VERSION 5.4 ;
NAMESCASESENSITIVE ON ;
BUSBITCHARS "[]" ;
DIVIDERCHAR "/" ;
UNITS
  DATABASE MICRONS 2000 ;
END UNITS
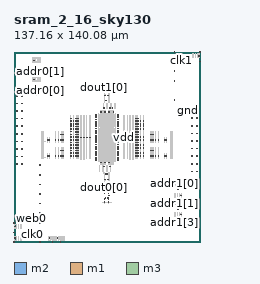
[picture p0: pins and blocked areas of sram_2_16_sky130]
MACRO sram_2_16_sky130
   CLASS BLOCK ;
   SIZE 137.16 BY 140.08 ;
   SYMMETRY X Y R90 ;
   PIN din0[0]
      DIRECTION INPUT ;
      PORT
         LAYER m2 ;
         RECT  26.135 2.69 26.465 2.95 ;
      END
   END din0[0]
   PIN din0[1]
      DIRECTION INPUT ;
      PORT
         LAYER m2 ;
         RECT  31.975 2.69 32.305 2.95 ;
      END
   END din0[1]
   PIN addr0[0]
      DIRECTION INPUT ;
      PORT
         LAYER m2 ;
         RECT  14.455 111.25 14.785 111.51 ;
      END
   END addr0[0]
   PIN addr0[1]
      DIRECTION INPUT ;
      PORT
         LAYER m2 ;
         RECT  14.455 119.75 14.785 120.01 ;
      END
   END addr0[1]
   PIN addr0[2]
      DIRECTION INPUT ;
      PORT
         LAYER m2 ;
         RECT  14.455 125.39 14.785 125.65 ;
      END
   END addr0[2]
   PIN addr0[3]
      DIRECTION INPUT ;
      PORT
         LAYER m2 ;
         RECT  14.455 133.89 14.785 134.15 ;
      END
   END addr0[3]
   PIN addr1[0]
      DIRECTION INPUT ;
      PORT
         LAYER m2 ;
         RECT  122.795 42.71 123.125 42.97 ;
      END
   END addr1[0]
   PIN addr1[1]
      DIRECTION INPUT ;
      PORT
         LAYER m2 ;
         RECT  122.795 34.21 123.125 34.47 ;
      END
   END addr1[1]
   PIN addr1[2]
      DIRECTION INPUT ;
      PORT
         LAYER m2 ;
         RECT  122.795 28.57 123.125 28.83 ;
      END
   END addr1[2]
   PIN addr1[3]
      DIRECTION INPUT ;
      PORT
         LAYER m2 ;
         RECT  122.795 20.07 123.125 20.33 ;
      END
   END addr1[3]
   PIN csb0
      DIRECTION INPUT ;
      PORT
         LAYER m2 ;
         RECT  0.685 2.69 1.015 2.95 ;
      END
   END csb0
   PIN csb1
      DIRECTION INPUT ;
      PORT
         LAYER m2 ;
         RECT  136.145 137.13 136.475 137.39 ;
      END
   END csb1
   PIN web0
      DIRECTION INPUT ;
      PORT
         LAYER m2 ;
         RECT  0.685 11.19 1.015 11.45 ;
      END
   END web0
   PIN clk0
      DIRECTION INPUT ;
      PORT
         LAYER m2 ;
         RECT  13.815 3.275 13.955 3.415 ;
      END
   END clk0
   PIN clk1
      DIRECTION INPUT ;
      PORT
         LAYER m2 ;
         RECT  123.625 136.665 123.765 136.805 ;
      END
   END clk1
   PIN dout0[0]
      DIRECTION OUTPUT ;
      PORT
         LAYER m1 ;
         RECT  65.98 39.79 66.21 41.06 ;
      END
   END dout0[0]
   PIN dout0[1]
      DIRECTION OUTPUT ;
      PORT
         LAYER m1 ;
         RECT  70.33 39.79 70.56 41.06 ;
      END
   END dout0[1]
   PIN dout1[0]
      DIRECTION OUTPUT ;
      PORT
         LAYER m1 ;
         RECT  65.98 113.16 66.21 114.43 ;
      END
   END dout1[0]
   PIN dout1[1]
      DIRECTION OUTPUT ;
      PORT
         LAYER m1 ;
         RECT  70.33 113.16 70.56 114.43 ;
      END
   END dout1[1]
   PIN vdd
      DIRECTION INOUT ;
      USE POWER ; 
      SHAPE ABUTMENT ; 
      PORT
         LAYER m3 ;
         RECT  100.815 63.185 101.305 63.675 ;
         LAYER m3 ;
         RECT  43.67 63.22 44.16 63.71 ;
         LAYER m3 ;
         RECT  104.07 67.17 104.56 67.66 ;
         LAYER m3 ;
         RECT  89.745 75.035 90.235 75.525 ;
         LAYER m3 ;
         RECT  130.995 91.015 131.485 91.505 ;
         LAYER m3 ;
         RECT  46.925 84.91 47.415 85.4 ;
         LAYER m3 ;
         RECT  93.0 79.02 93.49 79.51 ;
         LAYER m3 ;
         RECT  89.745 71.085 90.235 71.575 ;
         LAYER m3 ;
         RECT  25.985 63.185 26.475 63.675 ;
         LAYER m3 ;
         RECT  18.945 6.825 19.435 7.315 ;
         LAYER m3 ;
         RECT  46.925 82.935 47.415 83.425 ;
         LAYER m3 ;
         RECT  68.99 107.845 69.48 108.335 ;
         LAYER m3 ;
         RECT  67.12 112.035 67.61 112.525 ;
         LAYER m3 ;
         RECT  1.995 85.115 2.485 85.605 ;
         LAYER m3 ;
         RECT  80.815 76.865 81.305 77.355 ;
         LAYER m3 ;
         RECT  70.49 55.305 70.98 55.795 ;
         LAYER m3 ;
         RECT  100.815 75.035 101.305 75.525 ;
         LAYER m3 ;
         RECT  64.25 55.305 64.74 55.795 ;
         LAYER m3 ;
         RECT  18.945 49.245 19.435 49.735 ;
         LAYER m3 ;
         RECT  66.18 55.305 66.67 55.795 ;
         LAYER m3 ;
         RECT  134.675 46.215 135.165 46.705 ;
         LAYER m3 ;
         RECT  89.745 67.135 90.235 67.625 ;
         LAYER m3 ;
         RECT  100.815 78.985 101.305 79.475 ;
         LAYER m3 ;
         RECT  46.925 77.01 47.415 77.5 ;
         LAYER m3 ;
         RECT  67.06 45.885 67.55 46.375 ;
         LAYER m3 ;
         RECT  89.745 88.86 90.235 89.35 ;
         LAYER m3 ;
         RECT  130.995 79.815 131.485 80.305 ;
         LAYER m3 ;
         RECT  46.925 65.16 47.415 65.65 ;
         LAYER m3 ;
         RECT  25.985 75.035 26.475 75.525 ;
         LAYER m3 ;
         RECT  100.815 67.135 101.305 67.625 ;
         LAYER m3 ;
         RECT  130.995 68.615 131.485 69.105 ;
         LAYER m3 ;
         RECT  67.12 41.695 67.61 42.185 ;
         LAYER m3 ;
         RECT  43.67 67.17 44.16 67.66 ;
         LAYER m3 ;
         RECT  68.93 112.035 69.42 112.525 ;
         LAYER m3 ;
         RECT  118.145 132.765 118.635 133.255 ;
         LAYER m3 ;
         RECT  118.145 104.485 118.635 104.975 ;
         LAYER m3 ;
         RECT  18.945 35.105 19.435 35.595 ;
         LAYER m3 ;
         RECT  55.855 76.865 56.345 77.355 ;
         LAYER m3 ;
         RECT  43.67 82.97 44.16 83.46 ;
         LAYER m3 ;
         RECT  5.675 73.915 6.165 74.405 ;
         LAYER m3 ;
         RECT  93.0 90.87 93.49 91.36 ;
         LAYER m3 ;
         RECT  89.745 65.16 90.235 65.65 ;
         LAYER m3 ;
         RECT  32.6 63.22 33.09 63.71 ;
         LAYER m3 ;
         RECT  1.995 73.915 2.485 74.405 ;
         LAYER m3 ;
         RECT  43.67 75.07 44.16 75.56 ;
         LAYER m3 ;
         RECT  46.925 67.135 47.415 67.625 ;
         LAYER m3 ;
         RECT  46.925 71.085 47.415 71.575 ;
         LAYER m3 ;
         RECT  63.655 95.47 64.145 95.96 ;
         LAYER m3 ;
         RECT  85.39 76.785 85.88 77.275 ;
         LAYER m3 ;
         RECT  89.745 73.06 90.235 73.55 ;
         LAYER m3 ;
         RECT  104.07 79.02 104.56 79.51 ;
         LAYER m3 ;
         RECT  35.855 67.135 36.345 67.625 ;
         LAYER m3 ;
         RECT  134.675 79.815 135.165 80.305 ;
         LAYER m3 ;
         RECT  51.28 76.785 51.77 77.275 ;
         LAYER m3 ;
         RECT  32.6 75.07 33.09 75.56 ;
         LAYER m3 ;
         RECT  93.0 86.92 93.49 87.41 ;
         LAYER m3 ;
         RECT  134.675 68.615 135.165 69.105 ;
         LAYER m3 ;
         RECT  89.745 82.935 90.235 83.425 ;
         LAYER m3 ;
         RECT  67.06 107.845 67.55 108.335 ;
         LAYER m3 ;
         RECT  93.0 85.07 93.49 85.56 ;
         LAYER m3 ;
         RECT  32.6 79.02 33.09 79.51 ;
         LAYER m3 ;
         RECT  46.925 63.185 47.415 63.675 ;
         LAYER m3 ;
         RECT  46.925 88.86 47.415 89.35 ;
         LAYER m3 ;
         RECT  70.49 98.425 70.98 98.915 ;
         LAYER m3 ;
         RECT  120.645 38.345 121.135 38.835 ;
         LAYER m3 ;
         RECT  46.925 80.96 47.415 81.45 ;
         LAYER m3 ;
         RECT  46.925 69.11 47.415 69.6 ;
         LAYER m3 ;
         RECT  66.87 95.565 67.17 95.865 ;
         LAYER m3 ;
         RECT  134.675 57.415 135.165 57.905 ;
         LAYER m3 ;
         RECT  5.675 96.315 6.165 96.805 ;
         LAYER m3 ;
         RECT  1.995 62.715 2.485 63.205 ;
         LAYER m3 ;
         RECT  93.0 75.07 93.49 75.56 ;
         LAYER m3 ;
         RECT  89.745 80.96 90.235 81.45 ;
         LAYER m3 ;
         RECT  43.67 69.27 44.16 69.76 ;
         LAYER m3 ;
         RECT  93.0 82.97 93.49 83.46 ;
         LAYER m3 ;
         RECT  120.645 24.205 121.135 24.695 ;
         LAYER m3 ;
         RECT  118.145 118.625 118.635 119.115 ;
         LAYER m3 ;
         RECT  72.42 98.425 72.91 98.915 ;
         LAYER m3 ;
         RECT  93.0 89.02 93.49 89.51 ;
         LAYER m3 ;
         RECT  43.67 81.12 44.16 81.61 ;
         LAYER m3 ;
         RECT  93.0 77.17 93.49 77.66 ;
         LAYER m3 ;
         RECT  5.675 62.715 6.165 63.205 ;
         LAYER m3 ;
         RECT  130.995 57.415 131.485 57.905 ;
         LAYER m3 ;
         RECT  66.495 33.935 66.985 34.425 ;
         LAYER m3 ;
         RECT  110.685 63.185 111.175 63.675 ;
         LAYER m3 ;
         RECT  33.965 6.825 34.455 7.315 ;
         LAYER m3 ;
         RECT  68.99 45.885 69.48 46.375 ;
         LAYER m3 ;
         RECT  5.675 85.115 6.165 85.605 ;
         LAYER m3 ;
         RECT  16.445 115.385 16.935 115.875 ;
         LAYER m3 ;
         RECT  43.67 79.02 44.16 79.51 ;
         LAYER m3 ;
         RECT  1.995 107.515 2.485 108.005 ;
         LAYER m3 ;
         RECT  5.675 107.515 6.165 108.005 ;
         LAYER m3 ;
         RECT  46.925 73.06 47.415 73.55 ;
         LAYER m3 ;
         RECT  110.685 75.035 111.175 75.525 ;
         LAYER m3 ;
         RECT  43.67 71.12 44.16 71.61 ;
         LAYER m3 ;
         RECT  69.455 29.185 69.945 29.675 ;
         LAYER m3 ;
         RECT  104.07 63.22 104.56 63.71 ;
         LAYER m3 ;
         RECT  89.745 78.985 90.235 79.475 ;
         LAYER m3 ;
         RECT  93.0 69.27 93.49 69.76 ;
         LAYER m3 ;
         RECT  134.675 91.015 135.165 91.505 ;
         LAYER m3 ;
         RECT  66.87 58.355 67.17 58.655 ;
         LAYER m3 ;
         RECT  43.67 65.32 44.16 65.81 ;
         LAYER m3 ;
         RECT  93.0 81.12 93.49 81.61 ;
         LAYER m3 ;
         RECT  43.67 86.92 44.16 87.41 ;
         LAYER m3 ;
         RECT  35.855 78.985 36.345 79.475 ;
         LAYER m3 ;
         RECT  104.07 75.07 104.56 75.56 ;
         LAYER m3 ;
         RECT  136.915 132.765 137.405 133.255 ;
         LAYER m3 ;
         RECT  93.0 63.22 93.49 63.71 ;
         LAYER m3 ;
         RECT  43.67 90.87 44.16 91.36 ;
         LAYER m3 ;
         RECT  130.995 46.215 131.485 46.705 ;
         LAYER m3 ;
         RECT  89.745 77.01 90.235 77.5 ;
         LAYER m3 ;
         RECT  35.855 63.185 36.345 63.675 ;
         LAYER m3 ;
         RECT  46.925 86.885 47.415 87.375 ;
         LAYER m3 ;
         RECT  16.445 129.525 16.935 130.015 ;
         LAYER m3 ;
         RECT  66.18 98.425 66.67 98.915 ;
         LAYER m3 ;
         RECT  93.0 67.17 93.49 67.66 ;
         LAYER m3 ;
         RECT  93.0 73.22 93.49 73.71 ;
         LAYER m3 ;
         RECT  63.655 58.26 64.145 58.75 ;
         LAYER m3 ;
         RECT  43.67 85.07 44.16 85.56 ;
         LAYER m3 ;
         RECT  43.67 77.17 44.16 77.66 ;
         LAYER m3 ;
         RECT  69.555 33.935 70.045 34.425 ;
         LAYER m3 ;
         RECT  46.925 75.035 47.415 75.525 ;
         LAYER m3 ;
         RECT  89.745 84.91 90.235 85.4 ;
         LAYER m3 ;
         RECT  73.015 58.26 73.505 58.75 ;
         LAYER m3 ;
         RECT  43.67 73.22 44.16 73.71 ;
         LAYER m3 ;
         RECT  32.6 67.17 33.09 67.66 ;
         LAYER m3 ;
         RECT  73.015 95.47 73.505 95.96 ;
         LAYER m3 ;
         RECT  35.855 75.035 36.345 75.525 ;
         LAYER m3 ;
         RECT  66.595 29.185 67.085 29.675 ;
         LAYER m3 ;
         RECT  69.99 95.565 70.29 95.865 ;
         LAYER m3 ;
         RECT  46.925 78.985 47.415 79.475 ;
         LAYER m3 ;
         RECT  93.0 65.32 93.49 65.81 ;
         LAYER m3 ;
         RECT  68.93 41.695 69.42 42.185 ;
         LAYER m3 ;
         RECT  18.945 20.965 19.435 21.455 ;
         LAYER m3 ;
         RECT  46.925 90.835 47.415 91.325 ;
         LAYER m3 ;
         RECT  1.995 96.315 2.485 96.805 ;
         LAYER m3 ;
         RECT  28.125 6.825 28.615 7.315 ;
         LAYER m3 ;
         RECT  43.67 89.02 44.16 89.51 ;
         LAYER m3 ;
         RECT  93.0 71.12 93.49 71.61 ;
         LAYER m3 ;
         RECT  89.745 90.835 90.235 91.325 ;
         LAYER m3 ;
         RECT  89.745 69.11 90.235 69.6 ;
         LAYER m3 ;
         RECT  89.745 86.885 90.235 87.375 ;
         LAYER m3 ;
         RECT  -0.245 6.825 0.245 7.315 ;
         LAYER m3 ;
         RECT  69.99 58.355 70.29 58.655 ;
         LAYER m3 ;
         RECT  89.745 63.185 90.235 63.675 ;
      END
   END vdd
   PIN gnd
      DIRECTION INOUT ;
      USE GROUND ; 
      SHAPE ABUTMENT ; 
      PORT
         LAYER m3 ;
         RECT  41.545 79.02 42.035 79.51 ;
         LAYER m3 ;
         RECT  102.175 78.985 102.665 79.475 ;
         LAYER m3 ;
         RECT  76.59 78.145 76.89 78.445 ;
         LAYER m3 ;
         RECT  1.995 68.315 2.485 68.805 ;
         LAYER m3 ;
         RECT  76.59 84.86 76.89 85.16 ;
         LAYER m3 ;
         RECT  60.27 87.625 60.57 87.925 ;
         LAYER m3 ;
         RECT  106.195 67.17 106.685 67.66 ;
         LAYER m3 ;
         RECT  91.105 82.935 91.595 83.425 ;
         LAYER m3 ;
         RECT  16.445 122.455 16.935 122.945 ;
         LAYER m3 ;
         RECT  76.59 67.875 76.89 68.175 ;
         LAYER m3 ;
         RECT  60.27 73.01 60.57 73.31 ;
         LAYER m3 ;
         RECT  1.995 90.715 2.485 91.205 ;
         LAYER m3 ;
         RECT  5.675 101.915 6.165 102.405 ;
         LAYER m3 ;
         RECT  76.59 82.095 76.89 82.395 ;
         LAYER m3 ;
         RECT  45.565 71.085 46.055 71.575 ;
         LAYER m3 ;
         RECT  95.125 89.01 95.615 89.5 ;
         LAYER m3 ;
         RECT  45.565 73.06 46.055 73.55 ;
         LAYER m3 ;
         RECT  95.125 73.21 95.615 73.7 ;
         LAYER m3 ;
         RECT  30.475 79.02 30.965 79.51 ;
         LAYER m3 ;
         RECT  45.565 75.035 46.055 75.525 ;
         LAYER m3 ;
         RECT  102.175 63.185 102.665 63.675 ;
         LAYER m3 ;
         RECT  91.105 90.835 91.595 91.325 ;
         LAYER m3 ;
         RECT  60.27 69.06 60.57 69.36 ;
         LAYER m3 ;
         RECT  41.545 82.97 42.035 83.46 ;
         LAYER m3 ;
         RECT  5.675 90.715 6.165 91.205 ;
         LAYER m3 ;
         RECT  67.47 49.755 67.96 50.245 ;
         LAYER m3 ;
         RECT  87.515 76.79 88.005 77.28 ;
         LAYER m3 ;
         RECT  76.59 92.76 76.89 93.06 ;
         LAYER m3 ;
         RECT  45.565 80.96 46.055 81.45 ;
         LAYER m3 ;
         RECT  -0.245 13.905 0.245 14.395 ;
         LAYER m3 ;
         RECT  34.495 78.985 34.985 79.475 ;
         LAYER m3 ;
         RECT  68.58 103.975 69.07 104.465 ;
         LAYER m3 ;
         RECT  60.27 75.775 60.57 76.075 ;
         LAYER m3 ;
         RECT  60.27 70.245 60.57 70.545 ;
         LAYER m3 ;
         RECT  76.59 70.245 76.89 70.545 ;
         LAYER m3 ;
         RECT  76.59 87.625 76.89 87.925 ;
         LAYER m3 ;
         RECT  18.945 42.175 19.435 42.665 ;
         LAYER m3 ;
         RECT  45.565 86.885 46.055 87.375 ;
         LAYER m3 ;
         RECT  91.105 77.01 91.595 77.5 ;
         LAYER m3 ;
         RECT  118.145 111.555 118.635 112.045 ;
         LAYER m3 ;
         RECT  76.59 76.96 76.89 77.26 ;
         LAYER m3 ;
         RECT  33.965 -0.245 34.455 0.245 ;
         LAYER m3 ;
         RECT  28.125 -0.245 28.615 0.245 ;
         LAYER m3 ;
         RECT  49.155 76.79 49.645 77.28 ;
         LAYER m3 ;
         RECT  69.525 31.265 70.015 31.755 ;
         LAYER m3 ;
         RECT  60.27 78.145 60.57 78.445 ;
         LAYER m3 ;
         RECT  91.105 80.96 91.595 81.45 ;
         LAYER m3 ;
         RECT  60.27 80.91 60.57 81.21 ;
         LAYER m3 ;
         RECT  118.145 139.835 118.635 140.325 ;
         LAYER m3 ;
         RECT  60.27 86.045 60.57 86.345 ;
         LAYER m3 ;
         RECT  5.675 57.115 6.165 57.605 ;
         LAYER m3 ;
         RECT  30.475 67.17 30.965 67.66 ;
         LAYER m3 ;
         RECT  134.675 51.815 135.165 52.305 ;
         LAYER m3 ;
         RECT  34.495 67.135 34.985 67.625 ;
         LAYER m3 ;
         RECT  24.625 63.185 25.115 63.675 ;
         LAYER m3 ;
         RECT  60.27 76.96 60.57 77.26 ;
         LAYER m3 ;
         RECT  95.125 65.31 95.615 65.8 ;
         LAYER m3 ;
         RECT  91.105 75.035 91.595 75.525 ;
         LAYER m3 ;
         RECT  68.93 113.645 69.42 114.135 ;
         LAYER m3 ;
         RECT  60.27 62.345 60.57 62.645 ;
         LAYER m3 ;
         RECT  112.045 75.035 112.535 75.525 ;
         LAYER m3 ;
         RECT  41.545 85.06 42.035 85.55 ;
         LAYER m3 ;
         RECT  60.27 66.295 60.57 66.595 ;
         LAYER m3 ;
         RECT  45.565 90.835 46.055 91.325 ;
         LAYER m3 ;
         RECT  18.945 56.315 19.435 56.805 ;
         LAYER m3 ;
         RECT  18.945 -0.245 19.435 0.245 ;
         LAYER m3 ;
         RECT  95.125 82.97 95.615 83.46 ;
         LAYER m3 ;
         RECT  91.105 73.06 91.595 73.55 ;
         LAYER m3 ;
         RECT  60.27 71.825 60.57 72.125 ;
         LAYER m3 ;
         RECT  130.995 96.615 131.485 97.105 ;
         LAYER m3 ;
         RECT  134.675 74.215 135.165 74.705 ;
         LAYER m3 ;
         RECT  136.915 139.845 137.405 140.335 ;
         LAYER m3 ;
         RECT  24.625 75.035 25.115 75.525 ;
         LAYER m3 ;
         RECT  134.675 96.615 135.165 97.105 ;
         LAYER m3 ;
         RECT  95.125 77.16 95.615 77.65 ;
         LAYER m3 ;
         RECT  76.59 89.995 76.89 90.295 ;
         LAYER m3 ;
         RECT  60.27 93.945 60.57 94.245 ;
         LAYER m3 ;
         RECT  69.5 36.12 69.99 36.61 ;
         LAYER m3 ;
         RECT  91.105 71.085 91.595 71.575 ;
         LAYER m3 ;
         RECT  41.545 67.17 42.035 67.66 ;
         LAYER m3 ;
         RECT  1.995 79.515 2.485 80.005 ;
         LAYER m3 ;
         RECT  60.27 59.975 60.57 60.275 ;
         LAYER m3 ;
         RECT  45.565 63.185 46.055 63.675 ;
         LAYER m3 ;
         RECT  130.995 74.215 131.485 74.705 ;
         LAYER m3 ;
         RECT  66.525 31.265 67.015 31.755 ;
         LAYER m3 ;
         RECT  76.59 83.675 76.89 83.975 ;
         LAYER m3 ;
         RECT  60.27 65.11 60.57 65.41 ;
         LAYER m3 ;
         RECT  106.195 63.22 106.685 63.71 ;
         LAYER m3 ;
         RECT  120.645 45.415 121.135 45.905 ;
         LAYER m3 ;
         RECT  106.195 79.02 106.685 79.51 ;
         LAYER m3 ;
         RECT  76.59 66.295 76.89 66.595 ;
         LAYER m3 ;
         RECT  112.045 63.185 112.535 63.675 ;
         LAYER m3 ;
         RECT  41.545 69.26 42.035 69.75 ;
         LAYER m3 ;
         RECT  76.59 63.925 76.89 64.225 ;
         LAYER m3 ;
         RECT  76.59 69.06 76.89 69.36 ;
         LAYER m3 ;
         RECT  45.565 78.985 46.055 79.475 ;
         LAYER m3 ;
         RECT  60.27 91.575 60.57 91.875 ;
         LAYER m3 ;
         RECT  76.59 88.81 76.89 89.11 ;
         LAYER m3 ;
         RECT  5.675 68.315 6.165 68.805 ;
         LAYER m3 ;
         RECT  67.12 40.085 67.61 40.575 ;
         LAYER m3 ;
         RECT  76.59 79.725 76.89 80.025 ;
         LAYER m3 ;
         RECT  41.545 81.11 42.035 81.6 ;
         LAYER m3 ;
         RECT  83.305 76.865 83.795 77.355 ;
         LAYER m3 ;
         RECT  91.105 84.91 91.595 85.4 ;
         LAYER m3 ;
         RECT  76.59 59.975 76.89 60.275 ;
         LAYER m3 ;
         RECT  95.125 86.92 95.615 87.41 ;
         LAYER m3 ;
         RECT  95.125 71.12 95.615 71.61 ;
         LAYER m3 ;
         RECT  60.27 79.725 60.57 80.025 ;
         LAYER m3 ;
         RECT  76.59 75.775 76.89 76.075 ;
         LAYER m3 ;
         RECT  1.995 101.915 2.485 102.405 ;
         LAYER m3 ;
         RECT  91.105 65.16 91.595 65.65 ;
         LAYER m3 ;
         RECT  76.59 74.195 76.89 74.495 ;
         LAYER m3 ;
         RECT  95.125 81.11 95.615 81.6 ;
         LAYER m3 ;
         RECT  16.445 136.595 16.935 137.085 ;
         LAYER m3 ;
         RECT  41.545 65.31 42.035 65.8 ;
         LAYER m3 ;
         RECT  67.12 113.645 67.61 114.135 ;
         LAYER m3 ;
         RECT  130.995 51.815 131.485 52.305 ;
         LAYER m3 ;
         RECT  41.545 73.21 42.035 73.7 ;
         LAYER m3 ;
         RECT  102.175 67.135 102.665 67.625 ;
         LAYER m3 ;
         RECT  95.125 85.06 95.615 85.55 ;
         LAYER m3 ;
         RECT  130.995 63.015 131.485 63.505 ;
         LAYER m3 ;
         RECT  45.565 67.135 46.055 67.625 ;
         LAYER m3 ;
         RECT  68.93 40.085 69.42 40.575 ;
         LAYER m3 ;
         RECT  76.59 86.045 76.89 86.345 ;
         LAYER m3 ;
         RECT  106.195 75.07 106.685 75.56 ;
         LAYER m3 ;
         RECT  34.495 63.185 34.985 63.675 ;
         LAYER m3 ;
         RECT  76.59 93.945 76.89 94.245 ;
         LAYER m3 ;
         RECT  91.105 69.11 91.595 69.6 ;
         LAYER m3 ;
         RECT  60.27 67.875 60.57 68.175 ;
         LAYER m3 ;
         RECT  76.59 61.16 76.89 61.46 ;
         LAYER m3 ;
         RECT  95.125 90.87 95.615 91.36 ;
         LAYER m3 ;
         RECT  41.545 90.87 42.035 91.36 ;
         LAYER m3 ;
         RECT  118.145 97.415 118.635 97.905 ;
         LAYER m3 ;
         RECT  76.59 80.91 76.89 81.21 ;
         LAYER m3 ;
         RECT  60.27 84.86 60.57 85.16 ;
         LAYER m3 ;
         RECT  45.565 82.935 46.055 83.425 ;
         LAYER m3 ;
         RECT  34.495 75.035 34.985 75.525 ;
         LAYER m3 ;
         RECT  60.27 63.925 60.57 64.225 ;
         LAYER m3 ;
         RECT  5.675 79.515 6.165 80.005 ;
         LAYER m3 ;
         RECT  18.945 13.895 19.435 14.385 ;
         LAYER m3 ;
         RECT  60.27 92.76 60.57 93.06 ;
         LAYER m3 ;
         RECT  76.59 73.01 76.89 73.31 ;
         LAYER m3 ;
         RECT  76.59 62.345 76.89 62.645 ;
         LAYER m3 ;
         RECT  95.125 69.26 95.615 69.75 ;
         LAYER m3 ;
         RECT  91.105 67.135 91.595 67.625 ;
         LAYER m3 ;
         RECT  30.475 75.07 30.965 75.56 ;
         LAYER m3 ;
         RECT  60.27 82.095 60.57 82.395 ;
         LAYER m3 ;
         RECT  60.27 83.675 60.57 83.975 ;
         LAYER m3 ;
         RECT  45.565 65.16 46.055 65.65 ;
         LAYER m3 ;
         RECT  41.545 63.22 42.035 63.71 ;
         LAYER m3 ;
         RECT  60.27 88.81 60.57 89.11 ;
         LAYER m3 ;
         RECT  16.445 108.315 16.935 108.805 ;
         LAYER m3 ;
         RECT  60.27 61.16 60.57 61.46 ;
         LAYER m3 ;
         RECT  53.365 76.865 53.855 77.355 ;
         LAYER m3 ;
         RECT  67.47 103.975 67.96 104.465 ;
         LAYER m3 ;
         RECT  91.105 78.985 91.595 79.475 ;
         LAYER m3 ;
         RECT  -0.245 -0.255 0.245 0.235 ;
         LAYER m3 ;
         RECT  134.675 63.015 135.165 63.505 ;
         LAYER m3 ;
         RECT  76.59 71.825 76.89 72.125 ;
         LAYER m3 ;
         RECT  45.565 84.91 46.055 85.4 ;
         LAYER m3 ;
         RECT  102.175 75.035 102.665 75.525 ;
         LAYER m3 ;
         RECT  120.645 31.275 121.135 31.765 ;
         LAYER m3 ;
         RECT  95.125 75.07 95.615 75.56 ;
         LAYER m3 ;
         RECT  91.105 63.185 91.595 63.675 ;
         LAYER m3 ;
         RECT  60.27 74.195 60.57 74.495 ;
         LAYER m3 ;
         RECT  95.125 79.02 95.615 79.51 ;
         LAYER m3 ;
         RECT  118.145 125.695 118.635 126.185 ;
         LAYER m3 ;
         RECT  130.995 85.415 131.485 85.905 ;
         LAYER m3 ;
         RECT  68.95 32.275 69.44 32.765 ;
         LAYER m3 ;
         RECT  45.565 77.01 46.055 77.5 ;
         LAYER m3 ;
         RECT  30.475 63.22 30.965 63.71 ;
         LAYER m3 ;
         RECT  1.995 57.115 2.485 57.605 ;
         LAYER m3 ;
         RECT  18.945 28.035 19.435 28.525 ;
         LAYER m3 ;
         RECT  41.545 71.12 42.035 71.61 ;
         LAYER m3 ;
         RECT  134.675 85.415 135.165 85.905 ;
         LAYER m3 ;
         RECT  60.27 89.995 60.57 90.295 ;
         LAYER m3 ;
         RECT  95.125 67.17 95.615 67.66 ;
         LAYER m3 ;
         RECT  41.545 89.01 42.035 89.5 ;
         LAYER m3 ;
         RECT  41.545 77.16 42.035 77.65 ;
         LAYER m3 ;
         RECT  66.55 36.12 67.04 36.61 ;
         LAYER m3 ;
         RECT  76.59 65.11 76.89 65.41 ;
         LAYER m3 ;
         RECT  91.105 88.86 91.595 89.35 ;
         LAYER m3 ;
         RECT  68.58 49.755 69.07 50.245 ;
         LAYER m3 ;
         RECT  76.59 91.575 76.89 91.875 ;
         LAYER m3 ;
         RECT  45.565 88.86 46.055 89.35 ;
         LAYER m3 ;
         RECT  91.105 86.885 91.595 87.375 ;
         LAYER m3 ;
         RECT  95.125 63.22 95.615 63.71 ;
         LAYER m3 ;
         RECT  120.645 17.135 121.135 17.625 ;
         LAYER m3 ;
         RECT  45.565 69.11 46.055 69.6 ;
         LAYER m3 ;
         RECT  67.1 32.275 67.59 32.765 ;
         LAYER m3 ;
         RECT  41.545 86.92 42.035 87.41 ;
         LAYER m3 ;
         RECT  41.545 75.07 42.035 75.56 ;
      END
   END gnd
   OBS
   LAYER  m1 ;
      RECT  68.295 61.705 68.37 63.41 ;
      RECT  68.37 61.12 68.58 61.5 ;
      RECT  66.21 60.79 66.39 61.705 ;
      POLYGON  67.86 61.795 67.86 62.205 68.035 62.205 68.115 62.125 68.115 61.795 67.86 61.795 ;
      RECT  65.85 61.705 66.03 63.41 ;
      RECT  66.21 61.705 66.39 63.41 ;
      RECT  65.46 61.705 65.67 63.41 ;
      RECT  65.25 61.5 65.46 61.705 ;
      RECT  65.25 61.705 65.46 63.41 ;
      RECT  68.37 61.705 68.58 63.41 ;
      POLYGON  67.86 62.785 67.86 63.195 68.115 63.195 68.115 62.865 68.035 62.785 67.86 62.785 ;
      RECT  65.46 61.12 65.67 61.5 ;
      RECT  68.37 60.79 68.58 61.12 ;
      RECT  66.57 60.79 66.75 61.705 ;
      RECT  68.21 62.29 68.295 62.7 ;
      RECT  67.29 61.705 67.47 63.41 ;
      RECT  67.65 62.785 67.86 63.195 ;
      RECT  65.46 60.79 65.67 61.12 ;
      RECT  67.65 61.795 67.86 62.205 ;
      RECT  67.65 61.12 67.86 61.5 ;
      RECT  65.25 61.12 65.46 61.5 ;
      RECT  66.93 60.79 67.11 61.705 ;
      RECT  66.93 61.705 67.11 63.41 ;
      RECT  68.37 61.5 68.58 61.705 ;
      RECT  65.46 61.5 65.67 61.705 ;
      RECT  65.25 60.79 65.46 61.12 ;
      RECT  67.29 60.79 67.47 61.705 ;
      RECT  65.85 60.79 66.03 61.705 ;
      POLYGON  68.295 60.79 68.295 61.12 67.86 61.12 67.86 61.5 68.295 61.5 68.295 61.705 68.37 61.705 68.37 60.79 68.295 60.79 ;
      RECT  66.57 61.705 66.75 63.41 ;
      RECT  68.295 64.865 68.37 63.16 ;
      RECT  68.37 65.45 68.58 65.07 ;
      RECT  66.21 65.78 66.39 64.865 ;
      POLYGON  67.86 64.775 67.86 64.365 68.035 64.365 68.115 64.445 68.115 64.775 67.86 64.775 ;
      RECT  65.85 64.865 66.03 63.16 ;
      RECT  66.21 64.865 66.39 63.16 ;
      RECT  65.46 64.865 65.67 63.16 ;
      RECT  65.25 65.07 65.46 64.865 ;
      RECT  65.25 64.865 65.46 63.16 ;
      RECT  68.37 64.865 68.58 63.16 ;
      POLYGON  67.86 63.785 67.86 63.375 68.115 63.375 68.115 63.705 68.035 63.785 67.86 63.785 ;
      RECT  65.46 65.45 65.67 65.07 ;
      RECT  68.37 65.78 68.58 65.45 ;
      RECT  66.57 65.78 66.75 64.865 ;
      RECT  68.21 64.28 68.295 63.87 ;
      RECT  67.29 64.865 67.47 63.16 ;
      RECT  67.65 63.785 67.86 63.375 ;
      RECT  65.46 65.78 65.67 65.45 ;
      RECT  67.65 64.775 67.86 64.365 ;
      RECT  67.65 65.45 67.86 65.07 ;
      RECT  65.25 65.45 65.46 65.07 ;
      RECT  66.93 65.78 67.11 64.865 ;
      RECT  66.93 64.865 67.11 63.16 ;
      RECT  68.37 65.07 68.58 64.865 ;
      RECT  65.46 65.07 65.67 64.865 ;
      RECT  65.25 65.78 65.46 65.45 ;
      RECT  67.29 65.78 67.47 64.865 ;
      RECT  65.85 65.78 66.03 64.865 ;
      POLYGON  68.295 65.78 68.295 65.45 67.86 65.45 67.86 65.07 68.295 65.07 68.295 64.865 68.37 64.865 68.37 65.78 68.295 65.78 ;
      RECT  66.57 64.865 66.75 63.16 ;
      RECT  68.295 65.655 68.37 67.36 ;
      RECT  68.37 65.07 68.58 65.45 ;
      RECT  66.21 64.74 66.39 65.655 ;
      POLYGON  67.86 65.745 67.86 66.155 68.035 66.155 68.115 66.075 68.115 65.745 67.86 65.745 ;
      RECT  65.85 65.655 66.03 67.36 ;
      RECT  66.21 65.655 66.39 67.36 ;
      RECT  65.46 65.655 65.67 67.36 ;
      RECT  65.25 65.45 65.46 65.655 ;
      RECT  65.25 65.655 65.46 67.36 ;
      RECT  68.37 65.655 68.58 67.36 ;
      POLYGON  67.86 66.735 67.86 67.145 68.115 67.145 68.115 66.815 68.035 66.735 67.86 66.735 ;
      RECT  65.46 65.07 65.67 65.45 ;
      RECT  68.37 64.74 68.58 65.07 ;
      RECT  66.57 64.74 66.75 65.655 ;
      RECT  68.21 66.24 68.295 66.65 ;
      RECT  67.29 65.655 67.47 67.36 ;
      RECT  67.65 66.735 67.86 67.145 ;
      RECT  65.46 64.74 65.67 65.07 ;
      RECT  67.65 65.745 67.86 66.155 ;
      RECT  67.65 65.07 67.86 65.45 ;
      RECT  65.25 65.07 65.46 65.45 ;
      RECT  66.93 64.74 67.11 65.655 ;
      RECT  66.93 65.655 67.11 67.36 ;
      RECT  68.37 65.45 68.58 65.655 ;
      RECT  65.46 65.45 65.67 65.655 ;
      RECT  65.25 64.74 65.46 65.07 ;
      RECT  67.29 64.74 67.47 65.655 ;
      RECT  65.85 64.74 66.03 65.655 ;
      POLYGON  68.295 64.74 68.295 65.07 67.86 65.07 67.86 65.45 68.295 65.45 68.295 65.655 68.37 65.655 68.37 64.74 68.295 64.74 ;
      RECT  66.57 65.655 66.75 67.36 ;
      RECT  68.295 68.815 68.37 67.11 ;
      RECT  68.37 69.4 68.58 69.02 ;
      RECT  66.21 69.73 66.39 68.815 ;
      POLYGON  67.86 68.725 67.86 68.315 68.035 68.315 68.115 68.395 68.115 68.725 67.86 68.725 ;
      RECT  65.85 68.815 66.03 67.11 ;
      RECT  66.21 68.815 66.39 67.11 ;
      RECT  65.46 68.815 65.67 67.11 ;
      RECT  65.25 69.02 65.46 68.815 ;
      RECT  65.25 68.815 65.46 67.11 ;
      RECT  68.37 68.815 68.58 67.11 ;
      POLYGON  67.86 67.735 67.86 67.325 68.115 67.325 68.115 67.655 68.035 67.735 67.86 67.735 ;
      RECT  65.46 69.4 65.67 69.02 ;
      RECT  68.37 69.73 68.58 69.4 ;
      RECT  66.57 69.73 66.75 68.815 ;
      RECT  68.21 68.23 68.295 67.82 ;
      RECT  67.29 68.815 67.47 67.11 ;
      RECT  67.65 67.735 67.86 67.325 ;
      RECT  65.46 69.73 65.67 69.4 ;
      RECT  67.65 68.725 67.86 68.315 ;
      RECT  67.65 69.4 67.86 69.02 ;
      RECT  65.25 69.4 65.46 69.02 ;
      RECT  66.93 69.73 67.11 68.815 ;
      RECT  66.93 68.815 67.11 67.11 ;
      RECT  68.37 69.02 68.58 68.815 ;
      RECT  65.46 69.02 65.67 68.815 ;
      RECT  65.25 69.73 65.46 69.4 ;
      RECT  67.29 69.73 67.47 68.815 ;
      RECT  65.85 69.73 66.03 68.815 ;
      POLYGON  68.295 69.73 68.295 69.4 67.86 69.4 67.86 69.02 68.295 69.02 68.295 68.815 68.37 68.815 68.37 69.73 68.295 69.73 ;
      RECT  66.57 68.815 66.75 67.11 ;
      RECT  68.295 69.605 68.37 71.31 ;
      RECT  68.37 69.02 68.58 69.4 ;
      RECT  66.21 68.69 66.39 69.605 ;
      POLYGON  67.86 69.695 67.86 70.105 68.035 70.105 68.115 70.025 68.115 69.695 67.86 69.695 ;
      RECT  65.85 69.605 66.03 71.31 ;
      RECT  66.21 69.605 66.39 71.31 ;
      RECT  65.46 69.605 65.67 71.31 ;
      RECT  65.25 69.4 65.46 69.605 ;
      RECT  65.25 69.605 65.46 71.31 ;
      RECT  68.37 69.605 68.58 71.31 ;
      POLYGON  67.86 70.685 67.86 71.095 68.115 71.095 68.115 70.765 68.035 70.685 67.86 70.685 ;
      RECT  65.46 69.02 65.67 69.4 ;
      RECT  68.37 68.69 68.58 69.02 ;
      RECT  66.57 68.69 66.75 69.605 ;
      RECT  68.21 70.19 68.295 70.6 ;
      RECT  67.29 69.605 67.47 71.31 ;
      RECT  67.65 70.685 67.86 71.095 ;
      RECT  65.46 68.69 65.67 69.02 ;
      RECT  67.65 69.695 67.86 70.105 ;
      RECT  67.65 69.02 67.86 69.4 ;
      RECT  65.25 69.02 65.46 69.4 ;
      RECT  66.93 68.69 67.11 69.605 ;
      RECT  66.93 69.605 67.11 71.31 ;
      RECT  68.37 69.4 68.58 69.605 ;
      RECT  65.46 69.4 65.67 69.605 ;
      RECT  65.25 68.69 65.46 69.02 ;
      RECT  67.29 68.69 67.47 69.605 ;
      RECT  65.85 68.69 66.03 69.605 ;
      POLYGON  68.295 68.69 68.295 69.02 67.86 69.02 67.86 69.4 68.295 69.4 68.295 69.605 68.37 69.605 68.37 68.69 68.295 68.69 ;
      RECT  66.57 69.605 66.75 71.31 ;
      RECT  68.295 72.765 68.37 71.06 ;
      RECT  68.37 73.35 68.58 72.97 ;
      RECT  66.21 73.68 66.39 72.765 ;
      POLYGON  67.86 72.675 67.86 72.265 68.035 72.265 68.115 72.345 68.115 72.675 67.86 72.675 ;
      RECT  65.85 72.765 66.03 71.06 ;
      RECT  66.21 72.765 66.39 71.06 ;
      RECT  65.46 72.765 65.67 71.06 ;
      RECT  65.25 72.97 65.46 72.765 ;
      RECT  65.25 72.765 65.46 71.06 ;
      RECT  68.37 72.765 68.58 71.06 ;
      POLYGON  67.86 71.685 67.86 71.275 68.115 71.275 68.115 71.605 68.035 71.685 67.86 71.685 ;
      RECT  65.46 73.35 65.67 72.97 ;
      RECT  68.37 73.68 68.58 73.35 ;
      RECT  66.57 73.68 66.75 72.765 ;
      RECT  68.21 72.18 68.295 71.77 ;
      RECT  67.29 72.765 67.47 71.06 ;
      RECT  67.65 71.685 67.86 71.275 ;
      RECT  65.46 73.68 65.67 73.35 ;
      RECT  67.65 72.675 67.86 72.265 ;
      RECT  67.65 73.35 67.86 72.97 ;
      RECT  65.25 73.35 65.46 72.97 ;
      RECT  66.93 73.68 67.11 72.765 ;
      RECT  66.93 72.765 67.11 71.06 ;
      RECT  68.37 72.97 68.58 72.765 ;
      RECT  65.46 72.97 65.67 72.765 ;
      RECT  65.25 73.68 65.46 73.35 ;
      RECT  67.29 73.68 67.47 72.765 ;
      RECT  65.85 73.68 66.03 72.765 ;
      POLYGON  68.295 73.68 68.295 73.35 67.86 73.35 67.86 72.97 68.295 72.97 68.295 72.765 68.37 72.765 68.37 73.68 68.295 73.68 ;
      RECT  66.57 72.765 66.75 71.06 ;
      RECT  68.295 73.555 68.37 75.26 ;
      RECT  68.37 72.97 68.58 73.35 ;
      RECT  66.21 72.64 66.39 73.555 ;
      POLYGON  67.86 73.645 67.86 74.055 68.035 74.055 68.115 73.975 68.115 73.645 67.86 73.645 ;
      RECT  65.85 73.555 66.03 75.26 ;
      RECT  66.21 73.555 66.39 75.26 ;
      RECT  65.46 73.555 65.67 75.26 ;
      RECT  65.25 73.35 65.46 73.555 ;
      RECT  65.25 73.555 65.46 75.26 ;
      RECT  68.37 73.555 68.58 75.26 ;
      POLYGON  67.86 74.635 67.86 75.045 68.115 75.045 68.115 74.715 68.035 74.635 67.86 74.635 ;
      RECT  65.46 72.97 65.67 73.35 ;
      RECT  68.37 72.64 68.58 72.97 ;
      RECT  66.57 72.64 66.75 73.555 ;
      RECT  68.21 74.14 68.295 74.55 ;
      RECT  67.29 73.555 67.47 75.26 ;
      RECT  67.65 74.635 67.86 75.045 ;
      RECT  65.46 72.64 65.67 72.97 ;
      RECT  67.65 73.645 67.86 74.055 ;
      RECT  67.65 72.97 67.86 73.35 ;
      RECT  65.25 72.97 65.46 73.35 ;
      RECT  66.93 72.64 67.11 73.555 ;
      RECT  66.93 73.555 67.11 75.26 ;
      RECT  68.37 73.35 68.58 73.555 ;
      RECT  65.46 73.35 65.67 73.555 ;
      RECT  65.25 72.64 65.46 72.97 ;
      RECT  67.29 72.64 67.47 73.555 ;
      RECT  65.85 72.64 66.03 73.555 ;
      POLYGON  68.295 72.64 68.295 72.97 67.86 72.97 67.86 73.35 68.295 73.35 68.295 73.555 68.37 73.555 68.37 72.64 68.295 72.64 ;
      RECT  66.57 73.555 66.75 75.26 ;
      RECT  68.295 76.715 68.37 75.01 ;
      RECT  68.37 77.3 68.58 76.92 ;
      RECT  66.21 77.63 66.39 76.715 ;
      POLYGON  67.86 76.625 67.86 76.215 68.035 76.215 68.115 76.295 68.115 76.625 67.86 76.625 ;
      RECT  65.85 76.715 66.03 75.01 ;
      RECT  66.21 76.715 66.39 75.01 ;
      RECT  65.46 76.715 65.67 75.01 ;
      RECT  65.25 76.92 65.46 76.715 ;
      RECT  65.25 76.715 65.46 75.01 ;
      RECT  68.37 76.715 68.58 75.01 ;
      POLYGON  67.86 75.635 67.86 75.225 68.115 75.225 68.115 75.555 68.035 75.635 67.86 75.635 ;
      RECT  65.46 77.3 65.67 76.92 ;
      RECT  68.37 77.63 68.58 77.3 ;
      RECT  66.57 77.63 66.75 76.715 ;
      RECT  68.21 76.13 68.295 75.72 ;
      RECT  67.29 76.715 67.47 75.01 ;
      RECT  67.65 75.635 67.86 75.225 ;
      RECT  65.46 77.63 65.67 77.3 ;
      RECT  67.65 76.625 67.86 76.215 ;
      RECT  67.65 77.3 67.86 76.92 ;
      RECT  65.25 77.3 65.46 76.92 ;
      RECT  66.93 77.63 67.11 76.715 ;
      RECT  66.93 76.715 67.11 75.01 ;
      RECT  68.37 76.92 68.58 76.715 ;
      RECT  65.46 76.92 65.67 76.715 ;
      RECT  65.25 77.63 65.46 77.3 ;
      RECT  67.29 77.63 67.47 76.715 ;
      RECT  65.85 77.63 66.03 76.715 ;
      POLYGON  68.295 77.63 68.295 77.3 67.86 77.3 67.86 76.92 68.295 76.92 68.295 76.715 68.37 76.715 68.37 77.63 68.295 77.63 ;
      RECT  66.57 76.715 66.75 75.01 ;
      RECT  68.295 77.505 68.37 79.21 ;
      RECT  68.37 76.92 68.58 77.3 ;
      RECT  66.21 76.59 66.39 77.505 ;
      POLYGON  67.86 77.595 67.86 78.005 68.035 78.005 68.115 77.925 68.115 77.595 67.86 77.595 ;
      RECT  65.85 77.505 66.03 79.21 ;
      RECT  66.21 77.505 66.39 79.21 ;
      RECT  65.46 77.505 65.67 79.21 ;
      RECT  65.25 77.3 65.46 77.505 ;
      RECT  65.25 77.505 65.46 79.21 ;
      RECT  68.37 77.505 68.58 79.21 ;
      POLYGON  67.86 78.585 67.86 78.995 68.115 78.995 68.115 78.665 68.035 78.585 67.86 78.585 ;
      RECT  65.46 76.92 65.67 77.3 ;
      RECT  68.37 76.59 68.58 76.92 ;
      RECT  66.57 76.59 66.75 77.505 ;
      RECT  68.21 78.09 68.295 78.5 ;
      RECT  67.29 77.505 67.47 79.21 ;
      RECT  67.65 78.585 67.86 78.995 ;
      RECT  65.46 76.59 65.67 76.92 ;
      RECT  67.65 77.595 67.86 78.005 ;
      RECT  67.65 76.92 67.86 77.3 ;
      RECT  65.25 76.92 65.46 77.3 ;
      RECT  66.93 76.59 67.11 77.505 ;
      RECT  66.93 77.505 67.11 79.21 ;
      RECT  68.37 77.3 68.58 77.505 ;
      RECT  65.46 77.3 65.67 77.505 ;
      RECT  65.25 76.59 65.46 76.92 ;
      RECT  67.29 76.59 67.47 77.505 ;
      RECT  65.85 76.59 66.03 77.505 ;
      POLYGON  68.295 76.59 68.295 76.92 67.86 76.92 67.86 77.3 68.295 77.3 68.295 77.505 68.37 77.505 68.37 76.59 68.295 76.59 ;
      RECT  66.57 77.505 66.75 79.21 ;
      RECT  68.295 80.665 68.37 78.96 ;
      RECT  68.37 81.25 68.58 80.87 ;
      RECT  66.21 81.58 66.39 80.665 ;
      POLYGON  67.86 80.575 67.86 80.165 68.035 80.165 68.115 80.245 68.115 80.575 67.86 80.575 ;
      RECT  65.85 80.665 66.03 78.96 ;
      RECT  66.21 80.665 66.39 78.96 ;
      RECT  65.46 80.665 65.67 78.96 ;
      RECT  65.25 80.87 65.46 80.665 ;
      RECT  65.25 80.665 65.46 78.96 ;
      RECT  68.37 80.665 68.58 78.96 ;
      POLYGON  67.86 79.585 67.86 79.175 68.115 79.175 68.115 79.505 68.035 79.585 67.86 79.585 ;
      RECT  65.46 81.25 65.67 80.87 ;
      RECT  68.37 81.58 68.58 81.25 ;
      RECT  66.57 81.58 66.75 80.665 ;
      RECT  68.21 80.08 68.295 79.67 ;
      RECT  67.29 80.665 67.47 78.96 ;
      RECT  67.65 79.585 67.86 79.175 ;
      RECT  65.46 81.58 65.67 81.25 ;
      RECT  67.65 80.575 67.86 80.165 ;
      RECT  67.65 81.25 67.86 80.87 ;
      RECT  65.25 81.25 65.46 80.87 ;
      RECT  66.93 81.58 67.11 80.665 ;
      RECT  66.93 80.665 67.11 78.96 ;
      RECT  68.37 80.87 68.58 80.665 ;
      RECT  65.46 80.87 65.67 80.665 ;
      RECT  65.25 81.58 65.46 81.25 ;
      RECT  67.29 81.58 67.47 80.665 ;
      RECT  65.85 81.58 66.03 80.665 ;
      POLYGON  68.295 81.58 68.295 81.25 67.86 81.25 67.86 80.87 68.295 80.87 68.295 80.665 68.37 80.665 68.37 81.58 68.295 81.58 ;
      RECT  66.57 80.665 66.75 78.96 ;
      RECT  68.295 81.455 68.37 83.16 ;
      RECT  68.37 80.87 68.58 81.25 ;
      RECT  66.21 80.54 66.39 81.455 ;
      POLYGON  67.86 81.545 67.86 81.955 68.035 81.955 68.115 81.875 68.115 81.545 67.86 81.545 ;
      RECT  65.85 81.455 66.03 83.16 ;
      RECT  66.21 81.455 66.39 83.16 ;
      RECT  65.46 81.455 65.67 83.16 ;
      RECT  65.25 81.25 65.46 81.455 ;
      RECT  65.25 81.455 65.46 83.16 ;
      RECT  68.37 81.455 68.58 83.16 ;
      POLYGON  67.86 82.535 67.86 82.945 68.115 82.945 68.115 82.615 68.035 82.535 67.86 82.535 ;
      RECT  65.46 80.87 65.67 81.25 ;
      RECT  68.37 80.54 68.58 80.87 ;
      RECT  66.57 80.54 66.75 81.455 ;
      RECT  68.21 82.04 68.295 82.45 ;
      RECT  67.29 81.455 67.47 83.16 ;
      RECT  67.65 82.535 67.86 82.945 ;
      RECT  65.46 80.54 65.67 80.87 ;
      RECT  67.65 81.545 67.86 81.955 ;
      RECT  67.65 80.87 67.86 81.25 ;
      RECT  65.25 80.87 65.46 81.25 ;
      RECT  66.93 80.54 67.11 81.455 ;
      RECT  66.93 81.455 67.11 83.16 ;
      RECT  68.37 81.25 68.58 81.455 ;
      RECT  65.46 81.25 65.67 81.455 ;
      RECT  65.25 80.54 65.46 80.87 ;
      RECT  67.29 80.54 67.47 81.455 ;
      RECT  65.85 80.54 66.03 81.455 ;
      POLYGON  68.295 80.54 68.295 80.87 67.86 80.87 67.86 81.25 68.295 81.25 68.295 81.455 68.37 81.455 68.37 80.54 68.295 80.54 ;
      RECT  66.57 81.455 66.75 83.16 ;
      RECT  68.295 84.615 68.37 82.91 ;
      RECT  68.37 85.2 68.58 84.82 ;
      RECT  66.21 85.53 66.39 84.615 ;
      POLYGON  67.86 84.525 67.86 84.115 68.035 84.115 68.115 84.195 68.115 84.525 67.86 84.525 ;
      RECT  65.85 84.615 66.03 82.91 ;
      RECT  66.21 84.615 66.39 82.91 ;
      RECT  65.46 84.615 65.67 82.91 ;
      RECT  65.25 84.82 65.46 84.615 ;
      RECT  65.25 84.615 65.46 82.91 ;
      RECT  68.37 84.615 68.58 82.91 ;
      POLYGON  67.86 83.535 67.86 83.125 68.115 83.125 68.115 83.455 68.035 83.535 67.86 83.535 ;
      RECT  65.46 85.2 65.67 84.82 ;
      RECT  68.37 85.53 68.58 85.2 ;
      RECT  66.57 85.53 66.75 84.615 ;
      RECT  68.21 84.03 68.295 83.62 ;
      RECT  67.29 84.615 67.47 82.91 ;
      RECT  67.65 83.535 67.86 83.125 ;
      RECT  65.46 85.53 65.67 85.2 ;
      RECT  67.65 84.525 67.86 84.115 ;
      RECT  67.65 85.2 67.86 84.82 ;
      RECT  65.25 85.2 65.46 84.82 ;
      RECT  66.93 85.53 67.11 84.615 ;
      RECT  66.93 84.615 67.11 82.91 ;
      RECT  68.37 84.82 68.58 84.615 ;
      RECT  65.46 84.82 65.67 84.615 ;
      RECT  65.25 85.53 65.46 85.2 ;
      RECT  67.29 85.53 67.47 84.615 ;
      RECT  65.85 85.53 66.03 84.615 ;
      POLYGON  68.295 85.53 68.295 85.2 67.86 85.2 67.86 84.82 68.295 84.82 68.295 84.615 68.37 84.615 68.37 85.53 68.295 85.53 ;
      RECT  66.57 84.615 66.75 82.91 ;
      RECT  68.295 85.405 68.37 87.11 ;
      RECT  68.37 84.82 68.58 85.2 ;
      RECT  66.21 84.49 66.39 85.405 ;
      POLYGON  67.86 85.495 67.86 85.905 68.035 85.905 68.115 85.825 68.115 85.495 67.86 85.495 ;
      RECT  65.85 85.405 66.03 87.11 ;
      RECT  66.21 85.405 66.39 87.11 ;
      RECT  65.46 85.405 65.67 87.11 ;
      RECT  65.25 85.2 65.46 85.405 ;
      RECT  65.25 85.405 65.46 87.11 ;
      RECT  68.37 85.405 68.58 87.11 ;
      POLYGON  67.86 86.485 67.86 86.895 68.115 86.895 68.115 86.565 68.035 86.485 67.86 86.485 ;
      RECT  65.46 84.82 65.67 85.2 ;
      RECT  68.37 84.49 68.58 84.82 ;
      RECT  66.57 84.49 66.75 85.405 ;
      RECT  68.21 85.99 68.295 86.4 ;
      RECT  67.29 85.405 67.47 87.11 ;
      RECT  67.65 86.485 67.86 86.895 ;
      RECT  65.46 84.49 65.67 84.82 ;
      RECT  67.65 85.495 67.86 85.905 ;
      RECT  67.65 84.82 67.86 85.2 ;
      RECT  65.25 84.82 65.46 85.2 ;
      RECT  66.93 84.49 67.11 85.405 ;
      RECT  66.93 85.405 67.11 87.11 ;
      RECT  68.37 85.2 68.58 85.405 ;
      RECT  65.46 85.2 65.67 85.405 ;
      RECT  65.25 84.49 65.46 84.82 ;
      RECT  67.29 84.49 67.47 85.405 ;
      RECT  65.85 84.49 66.03 85.405 ;
      POLYGON  68.295 84.49 68.295 84.82 67.86 84.82 67.86 85.2 68.295 85.2 68.295 85.405 68.37 85.405 68.37 84.49 68.295 84.49 ;
      RECT  66.57 85.405 66.75 87.11 ;
      RECT  68.295 88.565 68.37 86.86 ;
      RECT  68.37 89.15 68.58 88.77 ;
      RECT  66.21 89.48 66.39 88.565 ;
      POLYGON  67.86 88.475 67.86 88.065 68.035 88.065 68.115 88.145 68.115 88.475 67.86 88.475 ;
      RECT  65.85 88.565 66.03 86.86 ;
      RECT  66.21 88.565 66.39 86.86 ;
      RECT  65.46 88.565 65.67 86.86 ;
      RECT  65.25 88.77 65.46 88.565 ;
      RECT  65.25 88.565 65.46 86.86 ;
      RECT  68.37 88.565 68.58 86.86 ;
      POLYGON  67.86 87.485 67.86 87.075 68.115 87.075 68.115 87.405 68.035 87.485 67.86 87.485 ;
      RECT  65.46 89.15 65.67 88.77 ;
      RECT  68.37 89.48 68.58 89.15 ;
      RECT  66.57 89.48 66.75 88.565 ;
      RECT  68.21 87.98 68.295 87.57 ;
      RECT  67.29 88.565 67.47 86.86 ;
      RECT  67.65 87.485 67.86 87.075 ;
      RECT  65.46 89.48 65.67 89.15 ;
      RECT  67.65 88.475 67.86 88.065 ;
      RECT  67.65 89.15 67.86 88.77 ;
      RECT  65.25 89.15 65.46 88.77 ;
      RECT  66.93 89.48 67.11 88.565 ;
      RECT  66.93 88.565 67.11 86.86 ;
      RECT  68.37 88.77 68.58 88.565 ;
      RECT  65.46 88.77 65.67 88.565 ;
      RECT  65.25 89.48 65.46 89.15 ;
      RECT  67.29 89.48 67.47 88.565 ;
      RECT  65.85 89.48 66.03 88.565 ;
      POLYGON  68.295 89.48 68.295 89.15 67.86 89.15 67.86 88.77 68.295 88.77 68.295 88.565 68.37 88.565 68.37 89.48 68.295 89.48 ;
      RECT  66.57 88.565 66.75 86.86 ;
      RECT  68.295 89.355 68.37 91.06 ;
      RECT  68.37 88.77 68.58 89.15 ;
      RECT  66.21 88.44 66.39 89.355 ;
      POLYGON  67.86 89.445 67.86 89.855 68.035 89.855 68.115 89.775 68.115 89.445 67.86 89.445 ;
      RECT  65.85 89.355 66.03 91.06 ;
      RECT  66.21 89.355 66.39 91.06 ;
      RECT  65.46 89.355 65.67 91.06 ;
      RECT  65.25 89.15 65.46 89.355 ;
      RECT  65.25 89.355 65.46 91.06 ;
      RECT  68.37 89.355 68.58 91.06 ;
      POLYGON  67.86 90.435 67.86 90.845 68.115 90.845 68.115 90.515 68.035 90.435 67.86 90.435 ;
      RECT  65.46 88.77 65.67 89.15 ;
      RECT  68.37 88.44 68.58 88.77 ;
      RECT  66.57 88.44 66.75 89.355 ;
      RECT  68.21 89.94 68.295 90.35 ;
      RECT  67.29 89.355 67.47 91.06 ;
      RECT  67.65 90.435 67.86 90.845 ;
      RECT  65.46 88.44 65.67 88.77 ;
      RECT  67.65 89.445 67.86 89.855 ;
      RECT  67.65 88.77 67.86 89.15 ;
      RECT  65.25 88.77 65.46 89.15 ;
      RECT  66.93 88.44 67.11 89.355 ;
      RECT  66.93 89.355 67.11 91.06 ;
      RECT  68.37 89.15 68.58 89.355 ;
      RECT  65.46 89.15 65.67 89.355 ;
      RECT  65.25 88.44 65.46 88.77 ;
      RECT  67.29 88.44 67.47 89.355 ;
      RECT  65.85 88.44 66.03 89.355 ;
      POLYGON  68.295 88.44 68.295 88.77 67.86 88.77 67.86 89.15 68.295 89.15 68.295 89.355 68.37 89.355 68.37 88.44 68.295 88.44 ;
      RECT  66.57 89.355 66.75 91.06 ;
      RECT  68.295 92.515 68.37 90.81 ;
      RECT  68.37 93.1 68.58 92.72 ;
      RECT  66.21 93.43 66.39 92.515 ;
      POLYGON  67.86 92.425 67.86 92.015 68.035 92.015 68.115 92.095 68.115 92.425 67.86 92.425 ;
      RECT  65.85 92.515 66.03 90.81 ;
      RECT  66.21 92.515 66.39 90.81 ;
      RECT  65.46 92.515 65.67 90.81 ;
      RECT  65.25 92.72 65.46 92.515 ;
      RECT  65.25 92.515 65.46 90.81 ;
      RECT  68.37 92.515 68.58 90.81 ;
      POLYGON  67.86 91.435 67.86 91.025 68.115 91.025 68.115 91.355 68.035 91.435 67.86 91.435 ;
      RECT  65.46 93.1 65.67 92.72 ;
      RECT  68.37 93.43 68.58 93.1 ;
      RECT  66.57 93.43 66.75 92.515 ;
      RECT  68.21 91.93 68.295 91.52 ;
      RECT  67.29 92.515 67.47 90.81 ;
      RECT  67.65 91.435 67.86 91.025 ;
      RECT  65.46 93.43 65.67 93.1 ;
      RECT  67.65 92.425 67.86 92.015 ;
      RECT  67.65 93.1 67.86 92.72 ;
      RECT  65.25 93.1 65.46 92.72 ;
      RECT  66.93 93.43 67.11 92.515 ;
      RECT  66.93 92.515 67.11 90.81 ;
      RECT  68.37 92.72 68.58 92.515 ;
      RECT  65.46 92.72 65.67 92.515 ;
      RECT  65.25 93.43 65.46 93.1 ;
      RECT  67.29 93.43 67.47 92.515 ;
      RECT  65.85 93.43 66.03 92.515 ;
      POLYGON  68.295 93.43 68.295 93.1 67.86 93.1 67.86 92.72 68.295 92.72 68.295 92.515 68.37 92.515 68.37 93.43 68.295 93.43 ;
      RECT  66.57 92.515 66.75 90.81 ;
      RECT  68.865 61.705 68.79 63.41 ;
      RECT  68.79 61.12 68.58 61.5 ;
      RECT  70.95 60.79 70.77 61.705 ;
      POLYGON  69.3 61.795 69.3 62.205 69.125 62.205 69.045 62.125 69.045 61.795 69.3 61.795 ;
      RECT  71.31 61.705 71.13 63.41 ;
      RECT  70.95 61.705 70.77 63.41 ;
      RECT  71.7 61.705 71.49 63.41 ;
      RECT  71.91 61.5 71.7 61.705 ;
      RECT  71.91 61.705 71.7 63.41 ;
      RECT  68.79 61.705 68.58 63.41 ;
      POLYGON  69.3 62.785 69.3 63.195 69.045 63.195 69.045 62.865 69.125 62.785 69.3 62.785 ;
      RECT  71.7 61.12 71.49 61.5 ;
      RECT  68.79 60.79 68.58 61.12 ;
      RECT  70.59 60.79 70.41 61.705 ;
      RECT  68.95 62.29 68.865 62.7 ;
      RECT  69.87 61.705 69.69 63.41 ;
      RECT  69.51 62.785 69.3 63.195 ;
      RECT  71.7 60.79 71.49 61.12 ;
      RECT  69.51 61.795 69.3 62.205 ;
      RECT  69.51 61.12 69.3 61.5 ;
      RECT  71.91 61.12 71.7 61.5 ;
      RECT  70.23 60.79 70.05 61.705 ;
      RECT  70.23 61.705 70.05 63.41 ;
      RECT  68.79 61.5 68.58 61.705 ;
      RECT  71.7 61.5 71.49 61.705 ;
      RECT  71.91 60.79 71.7 61.12 ;
      RECT  69.87 60.79 69.69 61.705 ;
      RECT  71.31 60.79 71.13 61.705 ;
      POLYGON  68.865 60.79 68.865 61.12 69.3 61.12 69.3 61.5 68.865 61.5 68.865 61.705 68.79 61.705 68.79 60.79 68.865 60.79 ;
      RECT  70.59 61.705 70.41 63.41 ;
      RECT  68.865 64.865 68.79 63.16 ;
      RECT  68.79 65.45 68.58 65.07 ;
      RECT  70.95 65.78 70.77 64.865 ;
      POLYGON  69.3 64.775 69.3 64.365 69.125 64.365 69.045 64.445 69.045 64.775 69.3 64.775 ;
      RECT  71.31 64.865 71.13 63.16 ;
      RECT  70.95 64.865 70.77 63.16 ;
      RECT  71.7 64.865 71.49 63.16 ;
      RECT  71.91 65.07 71.7 64.865 ;
      RECT  71.91 64.865 71.7 63.16 ;
      RECT  68.79 64.865 68.58 63.16 ;
      POLYGON  69.3 63.785 69.3 63.375 69.045 63.375 69.045 63.705 69.125 63.785 69.3 63.785 ;
      RECT  71.7 65.45 71.49 65.07 ;
      RECT  68.79 65.78 68.58 65.45 ;
      RECT  70.59 65.78 70.41 64.865 ;
      RECT  68.95 64.28 68.865 63.87 ;
      RECT  69.87 64.865 69.69 63.16 ;
      RECT  69.51 63.785 69.3 63.375 ;
      RECT  71.7 65.78 71.49 65.45 ;
      RECT  69.51 64.775 69.3 64.365 ;
      RECT  69.51 65.45 69.3 65.07 ;
      RECT  71.91 65.45 71.7 65.07 ;
      RECT  70.23 65.78 70.05 64.865 ;
      RECT  70.23 64.865 70.05 63.16 ;
      RECT  68.79 65.07 68.58 64.865 ;
      RECT  71.7 65.07 71.49 64.865 ;
      RECT  71.91 65.78 71.7 65.45 ;
      RECT  69.87 65.78 69.69 64.865 ;
      RECT  71.31 65.78 71.13 64.865 ;
      POLYGON  68.865 65.78 68.865 65.45 69.3 65.45 69.3 65.07 68.865 65.07 68.865 64.865 68.79 64.865 68.79 65.78 68.865 65.78 ;
      RECT  70.59 64.865 70.41 63.16 ;
      RECT  68.865 65.655 68.79 67.36 ;
      RECT  68.79 65.07 68.58 65.45 ;
      RECT  70.95 64.74 70.77 65.655 ;
      POLYGON  69.3 65.745 69.3 66.155 69.125 66.155 69.045 66.075 69.045 65.745 69.3 65.745 ;
      RECT  71.31 65.655 71.13 67.36 ;
      RECT  70.95 65.655 70.77 67.36 ;
      RECT  71.7 65.655 71.49 67.36 ;
      RECT  71.91 65.45 71.7 65.655 ;
      RECT  71.91 65.655 71.7 67.36 ;
      RECT  68.79 65.655 68.58 67.36 ;
      POLYGON  69.3 66.735 69.3 67.145 69.045 67.145 69.045 66.815 69.125 66.735 69.3 66.735 ;
      RECT  71.7 65.07 71.49 65.45 ;
      RECT  68.79 64.74 68.58 65.07 ;
      RECT  70.59 64.74 70.41 65.655 ;
      RECT  68.95 66.24 68.865 66.65 ;
      RECT  69.87 65.655 69.69 67.36 ;
      RECT  69.51 66.735 69.3 67.145 ;
      RECT  71.7 64.74 71.49 65.07 ;
      RECT  69.51 65.745 69.3 66.155 ;
      RECT  69.51 65.07 69.3 65.45 ;
      RECT  71.91 65.07 71.7 65.45 ;
      RECT  70.23 64.74 70.05 65.655 ;
      RECT  70.23 65.655 70.05 67.36 ;
      RECT  68.79 65.45 68.58 65.655 ;
      RECT  71.7 65.45 71.49 65.655 ;
      RECT  71.91 64.74 71.7 65.07 ;
      RECT  69.87 64.74 69.69 65.655 ;
      RECT  71.31 64.74 71.13 65.655 ;
      POLYGON  68.865 64.74 68.865 65.07 69.3 65.07 69.3 65.45 68.865 65.45 68.865 65.655 68.79 65.655 68.79 64.74 68.865 64.74 ;
      RECT  70.59 65.655 70.41 67.36 ;
      RECT  68.865 68.815 68.79 67.11 ;
      RECT  68.79 69.4 68.58 69.02 ;
      RECT  70.95 69.73 70.77 68.815 ;
      POLYGON  69.3 68.725 69.3 68.315 69.125 68.315 69.045 68.395 69.045 68.725 69.3 68.725 ;
      RECT  71.31 68.815 71.13 67.11 ;
      RECT  70.95 68.815 70.77 67.11 ;
      RECT  71.7 68.815 71.49 67.11 ;
      RECT  71.91 69.02 71.7 68.815 ;
      RECT  71.91 68.815 71.7 67.11 ;
      RECT  68.79 68.815 68.58 67.11 ;
      POLYGON  69.3 67.735 69.3 67.325 69.045 67.325 69.045 67.655 69.125 67.735 69.3 67.735 ;
      RECT  71.7 69.4 71.49 69.02 ;
      RECT  68.79 69.73 68.58 69.4 ;
      RECT  70.59 69.73 70.41 68.815 ;
      RECT  68.95 68.23 68.865 67.82 ;
      RECT  69.87 68.815 69.69 67.11 ;
      RECT  69.51 67.735 69.3 67.325 ;
      RECT  71.7 69.73 71.49 69.4 ;
      RECT  69.51 68.725 69.3 68.315 ;
      RECT  69.51 69.4 69.3 69.02 ;
      RECT  71.91 69.4 71.7 69.02 ;
      RECT  70.23 69.73 70.05 68.815 ;
      RECT  70.23 68.815 70.05 67.11 ;
      RECT  68.79 69.02 68.58 68.815 ;
      RECT  71.7 69.02 71.49 68.815 ;
      RECT  71.91 69.73 71.7 69.4 ;
      RECT  69.87 69.73 69.69 68.815 ;
      RECT  71.31 69.73 71.13 68.815 ;
      POLYGON  68.865 69.73 68.865 69.4 69.3 69.4 69.3 69.02 68.865 69.02 68.865 68.815 68.79 68.815 68.79 69.73 68.865 69.73 ;
      RECT  70.59 68.815 70.41 67.11 ;
      RECT  68.865 69.605 68.79 71.31 ;
      RECT  68.79 69.02 68.58 69.4 ;
      RECT  70.95 68.69 70.77 69.605 ;
      POLYGON  69.3 69.695 69.3 70.105 69.125 70.105 69.045 70.025 69.045 69.695 69.3 69.695 ;
      RECT  71.31 69.605 71.13 71.31 ;
      RECT  70.95 69.605 70.77 71.31 ;
      RECT  71.7 69.605 71.49 71.31 ;
      RECT  71.91 69.4 71.7 69.605 ;
      RECT  71.91 69.605 71.7 71.31 ;
      RECT  68.79 69.605 68.58 71.31 ;
      POLYGON  69.3 70.685 69.3 71.095 69.045 71.095 69.045 70.765 69.125 70.685 69.3 70.685 ;
      RECT  71.7 69.02 71.49 69.4 ;
      RECT  68.79 68.69 68.58 69.02 ;
      RECT  70.59 68.69 70.41 69.605 ;
      RECT  68.95 70.19 68.865 70.6 ;
      RECT  69.87 69.605 69.69 71.31 ;
      RECT  69.51 70.685 69.3 71.095 ;
      RECT  71.7 68.69 71.49 69.02 ;
      RECT  69.51 69.695 69.3 70.105 ;
      RECT  69.51 69.02 69.3 69.4 ;
      RECT  71.91 69.02 71.7 69.4 ;
      RECT  70.23 68.69 70.05 69.605 ;
      RECT  70.23 69.605 70.05 71.31 ;
      RECT  68.79 69.4 68.58 69.605 ;
      RECT  71.7 69.4 71.49 69.605 ;
      RECT  71.91 68.69 71.7 69.02 ;
      RECT  69.87 68.69 69.69 69.605 ;
      RECT  71.31 68.69 71.13 69.605 ;
      POLYGON  68.865 68.69 68.865 69.02 69.3 69.02 69.3 69.4 68.865 69.4 68.865 69.605 68.79 69.605 68.79 68.69 68.865 68.69 ;
      RECT  70.59 69.605 70.41 71.31 ;
      RECT  68.865 72.765 68.79 71.06 ;
      RECT  68.79 73.35 68.58 72.97 ;
      RECT  70.95 73.68 70.77 72.765 ;
      POLYGON  69.3 72.675 69.3 72.265 69.125 72.265 69.045 72.345 69.045 72.675 69.3 72.675 ;
      RECT  71.31 72.765 71.13 71.06 ;
      RECT  70.95 72.765 70.77 71.06 ;
      RECT  71.7 72.765 71.49 71.06 ;
      RECT  71.91 72.97 71.7 72.765 ;
      RECT  71.91 72.765 71.7 71.06 ;
      RECT  68.79 72.765 68.58 71.06 ;
      POLYGON  69.3 71.685 69.3 71.275 69.045 71.275 69.045 71.605 69.125 71.685 69.3 71.685 ;
      RECT  71.7 73.35 71.49 72.97 ;
      RECT  68.79 73.68 68.58 73.35 ;
      RECT  70.59 73.68 70.41 72.765 ;
      RECT  68.95 72.18 68.865 71.77 ;
      RECT  69.87 72.765 69.69 71.06 ;
      RECT  69.51 71.685 69.3 71.275 ;
      RECT  71.7 73.68 71.49 73.35 ;
      RECT  69.51 72.675 69.3 72.265 ;
      RECT  69.51 73.35 69.3 72.97 ;
      RECT  71.91 73.35 71.7 72.97 ;
      RECT  70.23 73.68 70.05 72.765 ;
      RECT  70.23 72.765 70.05 71.06 ;
      RECT  68.79 72.97 68.58 72.765 ;
      RECT  71.7 72.97 71.49 72.765 ;
      RECT  71.91 73.68 71.7 73.35 ;
      RECT  69.87 73.68 69.69 72.765 ;
      RECT  71.31 73.68 71.13 72.765 ;
      POLYGON  68.865 73.68 68.865 73.35 69.3 73.35 69.3 72.97 68.865 72.97 68.865 72.765 68.79 72.765 68.79 73.68 68.865 73.68 ;
      RECT  70.59 72.765 70.41 71.06 ;
      RECT  68.865 73.555 68.79 75.26 ;
      RECT  68.79 72.97 68.58 73.35 ;
      RECT  70.95 72.64 70.77 73.555 ;
      POLYGON  69.3 73.645 69.3 74.055 69.125 74.055 69.045 73.975 69.045 73.645 69.3 73.645 ;
      RECT  71.31 73.555 71.13 75.26 ;
      RECT  70.95 73.555 70.77 75.26 ;
      RECT  71.7 73.555 71.49 75.26 ;
      RECT  71.91 73.35 71.7 73.555 ;
      RECT  71.91 73.555 71.7 75.26 ;
      RECT  68.79 73.555 68.58 75.26 ;
      POLYGON  69.3 74.635 69.3 75.045 69.045 75.045 69.045 74.715 69.125 74.635 69.3 74.635 ;
      RECT  71.7 72.97 71.49 73.35 ;
      RECT  68.79 72.64 68.58 72.97 ;
      RECT  70.59 72.64 70.41 73.555 ;
      RECT  68.95 74.14 68.865 74.55 ;
      RECT  69.87 73.555 69.69 75.26 ;
      RECT  69.51 74.635 69.3 75.045 ;
      RECT  71.7 72.64 71.49 72.97 ;
      RECT  69.51 73.645 69.3 74.055 ;
      RECT  69.51 72.97 69.3 73.35 ;
      RECT  71.91 72.97 71.7 73.35 ;
      RECT  70.23 72.64 70.05 73.555 ;
      RECT  70.23 73.555 70.05 75.26 ;
      RECT  68.79 73.35 68.58 73.555 ;
      RECT  71.7 73.35 71.49 73.555 ;
      RECT  71.91 72.64 71.7 72.97 ;
      RECT  69.87 72.64 69.69 73.555 ;
      RECT  71.31 72.64 71.13 73.555 ;
      POLYGON  68.865 72.64 68.865 72.97 69.3 72.97 69.3 73.35 68.865 73.35 68.865 73.555 68.79 73.555 68.79 72.64 68.865 72.64 ;
      RECT  70.59 73.555 70.41 75.26 ;
      RECT  68.865 76.715 68.79 75.01 ;
      RECT  68.79 77.3 68.58 76.92 ;
      RECT  70.95 77.63 70.77 76.715 ;
      POLYGON  69.3 76.625 69.3 76.215 69.125 76.215 69.045 76.295 69.045 76.625 69.3 76.625 ;
      RECT  71.31 76.715 71.13 75.01 ;
      RECT  70.95 76.715 70.77 75.01 ;
      RECT  71.7 76.715 71.49 75.01 ;
      RECT  71.91 76.92 71.7 76.715 ;
      RECT  71.91 76.715 71.7 75.01 ;
      RECT  68.79 76.715 68.58 75.01 ;
      POLYGON  69.3 75.635 69.3 75.225 69.045 75.225 69.045 75.555 69.125 75.635 69.3 75.635 ;
      RECT  71.7 77.3 71.49 76.92 ;
      RECT  68.79 77.63 68.58 77.3 ;
      RECT  70.59 77.63 70.41 76.715 ;
      RECT  68.95 76.13 68.865 75.72 ;
      RECT  69.87 76.715 69.69 75.01 ;
      RECT  69.51 75.635 69.3 75.225 ;
      RECT  71.7 77.63 71.49 77.3 ;
      RECT  69.51 76.625 69.3 76.215 ;
      RECT  69.51 77.3 69.3 76.92 ;
      RECT  71.91 77.3 71.7 76.92 ;
      RECT  70.23 77.63 70.05 76.715 ;
      RECT  70.23 76.715 70.05 75.01 ;
      RECT  68.79 76.92 68.58 76.715 ;
      RECT  71.7 76.92 71.49 76.715 ;
      RECT  71.91 77.63 71.7 77.3 ;
      RECT  69.87 77.63 69.69 76.715 ;
      RECT  71.31 77.63 71.13 76.715 ;
      POLYGON  68.865 77.63 68.865 77.3 69.3 77.3 69.3 76.92 68.865 76.92 68.865 76.715 68.79 76.715 68.79 77.63 68.865 77.63 ;
      RECT  70.59 76.715 70.41 75.01 ;
      RECT  68.865 77.505 68.79 79.21 ;
      RECT  68.79 76.92 68.58 77.3 ;
      RECT  70.95 76.59 70.77 77.505 ;
      POLYGON  69.3 77.595 69.3 78.005 69.125 78.005 69.045 77.925 69.045 77.595 69.3 77.595 ;
      RECT  71.31 77.505 71.13 79.21 ;
      RECT  70.95 77.505 70.77 79.21 ;
      RECT  71.7 77.505 71.49 79.21 ;
      RECT  71.91 77.3 71.7 77.505 ;
      RECT  71.91 77.505 71.7 79.21 ;
      RECT  68.79 77.505 68.58 79.21 ;
      POLYGON  69.3 78.585 69.3 78.995 69.045 78.995 69.045 78.665 69.125 78.585 69.3 78.585 ;
      RECT  71.7 76.92 71.49 77.3 ;
      RECT  68.79 76.59 68.58 76.92 ;
      RECT  70.59 76.59 70.41 77.505 ;
      RECT  68.95 78.09 68.865 78.5 ;
      RECT  69.87 77.505 69.69 79.21 ;
      RECT  69.51 78.585 69.3 78.995 ;
      RECT  71.7 76.59 71.49 76.92 ;
      RECT  69.51 77.595 69.3 78.005 ;
      RECT  69.51 76.92 69.3 77.3 ;
      RECT  71.91 76.92 71.7 77.3 ;
      RECT  70.23 76.59 70.05 77.505 ;
      RECT  70.23 77.505 70.05 79.21 ;
      RECT  68.79 77.3 68.58 77.505 ;
      RECT  71.7 77.3 71.49 77.505 ;
      RECT  71.91 76.59 71.7 76.92 ;
      RECT  69.87 76.59 69.69 77.505 ;
      RECT  71.31 76.59 71.13 77.505 ;
      POLYGON  68.865 76.59 68.865 76.92 69.3 76.92 69.3 77.3 68.865 77.3 68.865 77.505 68.79 77.505 68.79 76.59 68.865 76.59 ;
      RECT  70.59 77.505 70.41 79.21 ;
      RECT  68.865 80.665 68.79 78.96 ;
      RECT  68.79 81.25 68.58 80.87 ;
      RECT  70.95 81.58 70.77 80.665 ;
      POLYGON  69.3 80.575 69.3 80.165 69.125 80.165 69.045 80.245 69.045 80.575 69.3 80.575 ;
      RECT  71.31 80.665 71.13 78.96 ;
      RECT  70.95 80.665 70.77 78.96 ;
      RECT  71.7 80.665 71.49 78.96 ;
      RECT  71.91 80.87 71.7 80.665 ;
      RECT  71.91 80.665 71.7 78.96 ;
      RECT  68.79 80.665 68.58 78.96 ;
      POLYGON  69.3 79.585 69.3 79.175 69.045 79.175 69.045 79.505 69.125 79.585 69.3 79.585 ;
      RECT  71.7 81.25 71.49 80.87 ;
      RECT  68.79 81.58 68.58 81.25 ;
      RECT  70.59 81.58 70.41 80.665 ;
      RECT  68.95 80.08 68.865 79.67 ;
      RECT  69.87 80.665 69.69 78.96 ;
      RECT  69.51 79.585 69.3 79.175 ;
      RECT  71.7 81.58 71.49 81.25 ;
      RECT  69.51 80.575 69.3 80.165 ;
      RECT  69.51 81.25 69.3 80.87 ;
      RECT  71.91 81.25 71.7 80.87 ;
      RECT  70.23 81.58 70.05 80.665 ;
      RECT  70.23 80.665 70.05 78.96 ;
      RECT  68.79 80.87 68.58 80.665 ;
      RECT  71.7 80.87 71.49 80.665 ;
      RECT  71.91 81.58 71.7 81.25 ;
      RECT  69.87 81.58 69.69 80.665 ;
      RECT  71.31 81.58 71.13 80.665 ;
      POLYGON  68.865 81.58 68.865 81.25 69.3 81.25 69.3 80.87 68.865 80.87 68.865 80.665 68.79 80.665 68.79 81.58 68.865 81.58 ;
      RECT  70.59 80.665 70.41 78.96 ;
      RECT  68.865 81.455 68.79 83.16 ;
      RECT  68.79 80.87 68.58 81.25 ;
      RECT  70.95 80.54 70.77 81.455 ;
      POLYGON  69.3 81.545 69.3 81.955 69.125 81.955 69.045 81.875 69.045 81.545 69.3 81.545 ;
      RECT  71.31 81.455 71.13 83.16 ;
      RECT  70.95 81.455 70.77 83.16 ;
      RECT  71.7 81.455 71.49 83.16 ;
      RECT  71.91 81.25 71.7 81.455 ;
      RECT  71.91 81.455 71.7 83.16 ;
      RECT  68.79 81.455 68.58 83.16 ;
      POLYGON  69.3 82.535 69.3 82.945 69.045 82.945 69.045 82.615 69.125 82.535 69.3 82.535 ;
      RECT  71.7 80.87 71.49 81.25 ;
      RECT  68.79 80.54 68.58 80.87 ;
      RECT  70.59 80.54 70.41 81.455 ;
      RECT  68.95 82.04 68.865 82.45 ;
      RECT  69.87 81.455 69.69 83.16 ;
      RECT  69.51 82.535 69.3 82.945 ;
      RECT  71.7 80.54 71.49 80.87 ;
      RECT  69.51 81.545 69.3 81.955 ;
      RECT  69.51 80.87 69.3 81.25 ;
      RECT  71.91 80.87 71.7 81.25 ;
      RECT  70.23 80.54 70.05 81.455 ;
      RECT  70.23 81.455 70.05 83.16 ;
      RECT  68.79 81.25 68.58 81.455 ;
      RECT  71.7 81.25 71.49 81.455 ;
      RECT  71.91 80.54 71.7 80.87 ;
      RECT  69.87 80.54 69.69 81.455 ;
      RECT  71.31 80.54 71.13 81.455 ;
      POLYGON  68.865 80.54 68.865 80.87 69.3 80.87 69.3 81.25 68.865 81.25 68.865 81.455 68.79 81.455 68.79 80.54 68.865 80.54 ;
      RECT  70.59 81.455 70.41 83.16 ;
      RECT  68.865 84.615 68.79 82.91 ;
      RECT  68.79 85.2 68.58 84.82 ;
      RECT  70.95 85.53 70.77 84.615 ;
      POLYGON  69.3 84.525 69.3 84.115 69.125 84.115 69.045 84.195 69.045 84.525 69.3 84.525 ;
      RECT  71.31 84.615 71.13 82.91 ;
      RECT  70.95 84.615 70.77 82.91 ;
      RECT  71.7 84.615 71.49 82.91 ;
      RECT  71.91 84.82 71.7 84.615 ;
      RECT  71.91 84.615 71.7 82.91 ;
      RECT  68.79 84.615 68.58 82.91 ;
      POLYGON  69.3 83.535 69.3 83.125 69.045 83.125 69.045 83.455 69.125 83.535 69.3 83.535 ;
      RECT  71.7 85.2 71.49 84.82 ;
      RECT  68.79 85.53 68.58 85.2 ;
      RECT  70.59 85.53 70.41 84.615 ;
      RECT  68.95 84.03 68.865 83.62 ;
      RECT  69.87 84.615 69.69 82.91 ;
      RECT  69.51 83.535 69.3 83.125 ;
      RECT  71.7 85.53 71.49 85.2 ;
      RECT  69.51 84.525 69.3 84.115 ;
      RECT  69.51 85.2 69.3 84.82 ;
      RECT  71.91 85.2 71.7 84.82 ;
      RECT  70.23 85.53 70.05 84.615 ;
      RECT  70.23 84.615 70.05 82.91 ;
      RECT  68.79 84.82 68.58 84.615 ;
      RECT  71.7 84.82 71.49 84.615 ;
      RECT  71.91 85.53 71.7 85.2 ;
      RECT  69.87 85.53 69.69 84.615 ;
      RECT  71.31 85.53 71.13 84.615 ;
      POLYGON  68.865 85.53 68.865 85.2 69.3 85.2 69.3 84.82 68.865 84.82 68.865 84.615 68.79 84.615 68.79 85.53 68.865 85.53 ;
      RECT  70.59 84.615 70.41 82.91 ;
      RECT  68.865 85.405 68.79 87.11 ;
      RECT  68.79 84.82 68.58 85.2 ;
      RECT  70.95 84.49 70.77 85.405 ;
      POLYGON  69.3 85.495 69.3 85.905 69.125 85.905 69.045 85.825 69.045 85.495 69.3 85.495 ;
      RECT  71.31 85.405 71.13 87.11 ;
      RECT  70.95 85.405 70.77 87.11 ;
      RECT  71.7 85.405 71.49 87.11 ;
      RECT  71.91 85.2 71.7 85.405 ;
      RECT  71.91 85.405 71.7 87.11 ;
      RECT  68.79 85.405 68.58 87.11 ;
      POLYGON  69.3 86.485 69.3 86.895 69.045 86.895 69.045 86.565 69.125 86.485 69.3 86.485 ;
      RECT  71.7 84.82 71.49 85.2 ;
      RECT  68.79 84.49 68.58 84.82 ;
      RECT  70.59 84.49 70.41 85.405 ;
      RECT  68.95 85.99 68.865 86.4 ;
      RECT  69.87 85.405 69.69 87.11 ;
      RECT  69.51 86.485 69.3 86.895 ;
      RECT  71.7 84.49 71.49 84.82 ;
      RECT  69.51 85.495 69.3 85.905 ;
      RECT  69.51 84.82 69.3 85.2 ;
      RECT  71.91 84.82 71.7 85.2 ;
      RECT  70.23 84.49 70.05 85.405 ;
      RECT  70.23 85.405 70.05 87.11 ;
      RECT  68.79 85.2 68.58 85.405 ;
      RECT  71.7 85.2 71.49 85.405 ;
      RECT  71.91 84.49 71.7 84.82 ;
      RECT  69.87 84.49 69.69 85.405 ;
      RECT  71.31 84.49 71.13 85.405 ;
      POLYGON  68.865 84.49 68.865 84.82 69.3 84.82 69.3 85.2 68.865 85.2 68.865 85.405 68.79 85.405 68.79 84.49 68.865 84.49 ;
      RECT  70.59 85.405 70.41 87.11 ;
      RECT  68.865 88.565 68.79 86.86 ;
      RECT  68.79 89.15 68.58 88.77 ;
      RECT  70.95 89.48 70.77 88.565 ;
      POLYGON  69.3 88.475 69.3 88.065 69.125 88.065 69.045 88.145 69.045 88.475 69.3 88.475 ;
      RECT  71.31 88.565 71.13 86.86 ;
      RECT  70.95 88.565 70.77 86.86 ;
      RECT  71.7 88.565 71.49 86.86 ;
      RECT  71.91 88.77 71.7 88.565 ;
      RECT  71.91 88.565 71.7 86.86 ;
      RECT  68.79 88.565 68.58 86.86 ;
      POLYGON  69.3 87.485 69.3 87.075 69.045 87.075 69.045 87.405 69.125 87.485 69.3 87.485 ;
      RECT  71.7 89.15 71.49 88.77 ;
      RECT  68.79 89.48 68.58 89.15 ;
      RECT  70.59 89.48 70.41 88.565 ;
      RECT  68.95 87.98 68.865 87.57 ;
      RECT  69.87 88.565 69.69 86.86 ;
      RECT  69.51 87.485 69.3 87.075 ;
      RECT  71.7 89.48 71.49 89.15 ;
      RECT  69.51 88.475 69.3 88.065 ;
      RECT  69.51 89.15 69.3 88.77 ;
      RECT  71.91 89.15 71.7 88.77 ;
      RECT  70.23 89.48 70.05 88.565 ;
      RECT  70.23 88.565 70.05 86.86 ;
      RECT  68.79 88.77 68.58 88.565 ;
      RECT  71.7 88.77 71.49 88.565 ;
      RECT  71.91 89.48 71.7 89.15 ;
      RECT  69.87 89.48 69.69 88.565 ;
      RECT  71.31 89.48 71.13 88.565 ;
      POLYGON  68.865 89.48 68.865 89.15 69.3 89.15 69.3 88.77 68.865 88.77 68.865 88.565 68.79 88.565 68.79 89.48 68.865 89.48 ;
      RECT  70.59 88.565 70.41 86.86 ;
      RECT  68.865 89.355 68.79 91.06 ;
      RECT  68.79 88.77 68.58 89.15 ;
      RECT  70.95 88.44 70.77 89.355 ;
      POLYGON  69.3 89.445 69.3 89.855 69.125 89.855 69.045 89.775 69.045 89.445 69.3 89.445 ;
      RECT  71.31 89.355 71.13 91.06 ;
      RECT  70.95 89.355 70.77 91.06 ;
      RECT  71.7 89.355 71.49 91.06 ;
      RECT  71.91 89.15 71.7 89.355 ;
      RECT  71.91 89.355 71.7 91.06 ;
      RECT  68.79 89.355 68.58 91.06 ;
      POLYGON  69.3 90.435 69.3 90.845 69.045 90.845 69.045 90.515 69.125 90.435 69.3 90.435 ;
      RECT  71.7 88.77 71.49 89.15 ;
      RECT  68.79 88.44 68.58 88.77 ;
      RECT  70.59 88.44 70.41 89.355 ;
      RECT  68.95 89.94 68.865 90.35 ;
      RECT  69.87 89.355 69.69 91.06 ;
      RECT  69.51 90.435 69.3 90.845 ;
      RECT  71.7 88.44 71.49 88.77 ;
      RECT  69.51 89.445 69.3 89.855 ;
      RECT  69.51 88.77 69.3 89.15 ;
      RECT  71.91 88.77 71.7 89.15 ;
      RECT  70.23 88.44 70.05 89.355 ;
      RECT  70.23 89.355 70.05 91.06 ;
      RECT  68.79 89.15 68.58 89.355 ;
      RECT  71.7 89.15 71.49 89.355 ;
      RECT  71.91 88.44 71.7 88.77 ;
      RECT  69.87 88.44 69.69 89.355 ;
      RECT  71.31 88.44 71.13 89.355 ;
      POLYGON  68.865 88.44 68.865 88.77 69.3 88.77 69.3 89.15 68.865 89.15 68.865 89.355 68.79 89.355 68.79 88.44 68.865 88.44 ;
      RECT  70.59 89.355 70.41 91.06 ;
      RECT  68.865 92.515 68.79 90.81 ;
      RECT  68.79 93.1 68.58 92.72 ;
      RECT  70.95 93.43 70.77 92.515 ;
      POLYGON  69.3 92.425 69.3 92.015 69.125 92.015 69.045 92.095 69.045 92.425 69.3 92.425 ;
      RECT  71.31 92.515 71.13 90.81 ;
      RECT  70.95 92.515 70.77 90.81 ;
      RECT  71.7 92.515 71.49 90.81 ;
      RECT  71.91 92.72 71.7 92.515 ;
      RECT  71.91 92.515 71.7 90.81 ;
      RECT  68.79 92.515 68.58 90.81 ;
      POLYGON  69.3 91.435 69.3 91.025 69.045 91.025 69.045 91.355 69.125 91.435 69.3 91.435 ;
      RECT  71.7 93.1 71.49 92.72 ;
      RECT  68.79 93.43 68.58 93.1 ;
      RECT  70.59 93.43 70.41 92.515 ;
      RECT  68.95 91.93 68.865 91.52 ;
      RECT  69.87 92.515 69.69 90.81 ;
      RECT  69.51 91.435 69.3 91.025 ;
      RECT  71.7 93.43 71.49 93.1 ;
      RECT  69.51 92.425 69.3 92.015 ;
      RECT  69.51 93.1 69.3 92.72 ;
      RECT  71.91 93.1 71.7 92.72 ;
      RECT  70.23 93.43 70.05 92.515 ;
      RECT  70.23 92.515 70.05 90.81 ;
      RECT  68.79 92.72 68.58 92.515 ;
      RECT  71.7 92.72 71.49 92.515 ;
      RECT  71.91 93.43 71.7 93.1 ;
      RECT  69.87 93.43 69.69 92.515 ;
      RECT  71.31 93.43 71.13 92.515 ;
      POLYGON  68.865 93.43 68.865 93.1 69.3 93.1 69.3 92.72 68.865 92.72 68.865 92.515 68.79 92.515 68.79 93.43 68.865 93.43 ;
      RECT  70.59 92.515 70.41 90.81 ;
      RECT  65.85 61.31 66.03 92.91 ;
      RECT  66.21 61.31 66.39 92.91 ;
      RECT  66.93 61.31 67.11 92.91 ;
      RECT  67.29 61.31 67.47 92.91 ;
      RECT  71.13 61.31 71.31 92.91 ;
      RECT  70.77 61.31 70.95 92.91 ;
      RECT  70.05 61.31 70.23 92.91 ;
      RECT  69.69 61.31 69.87 92.91 ;
      RECT  70.41 61.705 70.59 63.41 ;
      RECT  66.57 77.505 66.75 79.21 ;
      RECT  70.41 86.86 70.59 88.565 ;
      RECT  70.41 63.16 70.59 64.865 ;
      RECT  70.41 65.655 70.59 67.36 ;
      RECT  66.57 85.405 66.75 87.11 ;
      RECT  70.41 78.96 70.59 80.665 ;
      RECT  66.57 90.81 66.75 92.515 ;
      RECT  70.41 81.455 70.59 83.16 ;
      RECT  66.57 67.11 66.75 68.815 ;
      RECT  66.57 86.86 66.75 88.565 ;
      RECT  70.41 75.01 70.59 76.715 ;
      RECT  70.41 71.06 70.59 72.765 ;
      RECT  70.41 77.505 70.59 79.21 ;
      RECT  66.57 73.555 66.75 75.26 ;
      RECT  70.41 67.11 70.59 68.815 ;
      RECT  70.41 90.81 70.59 92.515 ;
      RECT  70.41 73.555 70.59 75.26 ;
      RECT  66.57 75.01 66.75 76.715 ;
      RECT  66.57 69.605 66.75 71.31 ;
      RECT  70.41 82.91 70.59 84.615 ;
      RECT  70.41 89.355 70.59 91.06 ;
      RECT  70.41 85.405 70.59 87.11 ;
      RECT  66.57 61.705 66.75 63.41 ;
      RECT  66.57 89.355 66.75 91.06 ;
      RECT  66.57 65.655 66.75 67.36 ;
      RECT  66.57 81.455 66.75 83.16 ;
      RECT  66.57 71.06 66.75 72.765 ;
      RECT  66.57 63.16 66.75 64.865 ;
      RECT  70.41 69.605 70.59 71.31 ;
      RECT  66.57 82.91 66.75 84.615 ;
      RECT  66.57 78.96 66.75 80.665 ;
      RECT  64.35 58.15 64.17 59.73 ;
      RECT  64.71 58.15 64.53 59.73 ;
      RECT  64.26 58.15 64.13 58.86 ;
      RECT  63.99 58.15 63.81 59.73 ;
      RECT  64.39 58.15 64.26 58.86 ;
      RECT  64.71 57.36 64.53 58.15 ;
      RECT  65.07 57.36 64.89 58.15 ;
      RECT  63.63 57.36 63.45 58.15 ;
      RECT  64.35 57.36 64.17 58.15 ;
      RECT  63.99 57.36 63.81 58.15 ;
      RECT  65.07 58.15 64.89 59.73 ;
      RECT  63.63 58.15 63.45 59.73 ;
      RECT  62.625 60.915 62.55 59.21 ;
      RECT  62.55 61.5 62.34 61.12 ;
      RECT  64.71 61.83 64.53 60.915 ;
      POLYGON  63.06 60.825 63.06 60.415 62.885 60.415 62.805 60.495 62.805 60.825 63.06 60.825 ;
      RECT  65.07 60.915 64.89 59.21 ;
      RECT  64.71 60.915 64.53 59.21 ;
      RECT  65.46 60.915 65.25 59.21 ;
      RECT  65.67 61.12 65.46 60.915 ;
      RECT  65.67 60.915 65.46 59.21 ;
      RECT  62.55 60.915 62.34 59.21 ;
      POLYGON  63.06 59.835 63.06 59.425 62.805 59.425 62.805 59.755 62.885 59.835 63.06 59.835 ;
      RECT  65.46 61.5 65.25 61.12 ;
      RECT  62.55 61.83 62.34 61.5 ;
      RECT  64.35 61.83 64.17 60.915 ;
      RECT  62.71 60.33 62.625 59.92 ;
      RECT  63.63 60.915 63.45 59.21 ;
      RECT  63.27 59.835 63.06 59.425 ;
      RECT  65.46 61.83 65.25 61.5 ;
      RECT  63.27 60.825 63.06 60.415 ;
      RECT  63.27 61.5 63.06 61.12 ;
      RECT  65.67 61.5 65.46 61.12 ;
      RECT  63.99 61.83 63.81 60.915 ;
      RECT  63.99 60.915 63.81 59.21 ;
      RECT  62.55 61.12 62.34 60.915 ;
      RECT  65.46 61.12 65.25 60.915 ;
      RECT  65.67 61.83 65.46 61.5 ;
      RECT  63.63 61.83 63.45 60.915 ;
      RECT  65.07 61.83 64.89 60.915 ;
      POLYGON  62.625 61.83 62.625 61.5 63.06 61.5 63.06 61.12 62.625 61.12 62.625 60.915 62.55 60.915 62.55 61.83 62.625 61.83 ;
      RECT  64.35 60.915 64.17 59.21 ;
      RECT  62.625 61.705 62.55 63.41 ;
      RECT  62.55 61.12 62.34 61.5 ;
      RECT  64.71 60.79 64.53 61.705 ;
      POLYGON  63.06 61.795 63.06 62.205 62.885 62.205 62.805 62.125 62.805 61.795 63.06 61.795 ;
      RECT  65.07 61.705 64.89 63.41 ;
      RECT  64.71 61.705 64.53 63.41 ;
      RECT  65.46 61.705 65.25 63.41 ;
      RECT  65.67 61.5 65.46 61.705 ;
      RECT  65.67 61.705 65.46 63.41 ;
      RECT  62.55 61.705 62.34 63.41 ;
      POLYGON  63.06 62.785 63.06 63.195 62.805 63.195 62.805 62.865 62.885 62.785 63.06 62.785 ;
      RECT  65.46 61.12 65.25 61.5 ;
      RECT  62.55 60.79 62.34 61.12 ;
      RECT  64.35 60.79 64.17 61.705 ;
      RECT  62.71 62.29 62.625 62.7 ;
      RECT  63.63 61.705 63.45 63.41 ;
      RECT  63.27 62.785 63.06 63.195 ;
      RECT  65.46 60.79 65.25 61.12 ;
      RECT  63.27 61.795 63.06 62.205 ;
      RECT  63.27 61.12 63.06 61.5 ;
      RECT  65.67 61.12 65.46 61.5 ;
      RECT  63.99 60.79 63.81 61.705 ;
      RECT  63.99 61.705 63.81 63.41 ;
      RECT  62.55 61.5 62.34 61.705 ;
      RECT  65.46 61.5 65.25 61.705 ;
      RECT  65.67 60.79 65.46 61.12 ;
      RECT  63.63 60.79 63.45 61.705 ;
      RECT  65.07 60.79 64.89 61.705 ;
      POLYGON  62.625 60.79 62.625 61.12 63.06 61.12 63.06 61.5 62.625 61.5 62.625 61.705 62.55 61.705 62.55 60.79 62.625 60.79 ;
      RECT  64.35 61.705 64.17 63.41 ;
      RECT  62.625 64.865 62.55 63.16 ;
      RECT  62.55 65.45 62.34 65.07 ;
      RECT  64.71 65.78 64.53 64.865 ;
      POLYGON  63.06 64.775 63.06 64.365 62.885 64.365 62.805 64.445 62.805 64.775 63.06 64.775 ;
      RECT  65.07 64.865 64.89 63.16 ;
      RECT  64.71 64.865 64.53 63.16 ;
      RECT  65.46 64.865 65.25 63.16 ;
      RECT  65.67 65.07 65.46 64.865 ;
      RECT  65.67 64.865 65.46 63.16 ;
      RECT  62.55 64.865 62.34 63.16 ;
      POLYGON  63.06 63.785 63.06 63.375 62.805 63.375 62.805 63.705 62.885 63.785 63.06 63.785 ;
      RECT  65.46 65.45 65.25 65.07 ;
      RECT  62.55 65.78 62.34 65.45 ;
      RECT  64.35 65.78 64.17 64.865 ;
      RECT  62.71 64.28 62.625 63.87 ;
      RECT  63.63 64.865 63.45 63.16 ;
      RECT  63.27 63.785 63.06 63.375 ;
      RECT  65.46 65.78 65.25 65.45 ;
      RECT  63.27 64.775 63.06 64.365 ;
      RECT  63.27 65.45 63.06 65.07 ;
      RECT  65.67 65.45 65.46 65.07 ;
      RECT  63.99 65.78 63.81 64.865 ;
      RECT  63.99 64.865 63.81 63.16 ;
      RECT  62.55 65.07 62.34 64.865 ;
      RECT  65.46 65.07 65.25 64.865 ;
      RECT  65.67 65.78 65.46 65.45 ;
      RECT  63.63 65.78 63.45 64.865 ;
      RECT  65.07 65.78 64.89 64.865 ;
      POLYGON  62.625 65.78 62.625 65.45 63.06 65.45 63.06 65.07 62.625 65.07 62.625 64.865 62.55 64.865 62.55 65.78 62.625 65.78 ;
      RECT  64.35 64.865 64.17 63.16 ;
      RECT  62.625 65.655 62.55 67.36 ;
      RECT  62.55 65.07 62.34 65.45 ;
      RECT  64.71 64.74 64.53 65.655 ;
      POLYGON  63.06 65.745 63.06 66.155 62.885 66.155 62.805 66.075 62.805 65.745 63.06 65.745 ;
      RECT  65.07 65.655 64.89 67.36 ;
      RECT  64.71 65.655 64.53 67.36 ;
      RECT  65.46 65.655 65.25 67.36 ;
      RECT  65.67 65.45 65.46 65.655 ;
      RECT  65.67 65.655 65.46 67.36 ;
      RECT  62.55 65.655 62.34 67.36 ;
      POLYGON  63.06 66.735 63.06 67.145 62.805 67.145 62.805 66.815 62.885 66.735 63.06 66.735 ;
      RECT  65.46 65.07 65.25 65.45 ;
      RECT  62.55 64.74 62.34 65.07 ;
      RECT  64.35 64.74 64.17 65.655 ;
      RECT  62.71 66.24 62.625 66.65 ;
      RECT  63.63 65.655 63.45 67.36 ;
      RECT  63.27 66.735 63.06 67.145 ;
      RECT  65.46 64.74 65.25 65.07 ;
      RECT  63.27 65.745 63.06 66.155 ;
      RECT  63.27 65.07 63.06 65.45 ;
      RECT  65.67 65.07 65.46 65.45 ;
      RECT  63.99 64.74 63.81 65.655 ;
      RECT  63.99 65.655 63.81 67.36 ;
      RECT  62.55 65.45 62.34 65.655 ;
      RECT  65.46 65.45 65.25 65.655 ;
      RECT  65.67 64.74 65.46 65.07 ;
      RECT  63.63 64.74 63.45 65.655 ;
      RECT  65.07 64.74 64.89 65.655 ;
      POLYGON  62.625 64.74 62.625 65.07 63.06 65.07 63.06 65.45 62.625 65.45 62.625 65.655 62.55 65.655 62.55 64.74 62.625 64.74 ;
      RECT  64.35 65.655 64.17 67.36 ;
      RECT  62.625 68.815 62.55 67.11 ;
      RECT  62.55 69.4 62.34 69.02 ;
      RECT  64.71 69.73 64.53 68.815 ;
      POLYGON  63.06 68.725 63.06 68.315 62.885 68.315 62.805 68.395 62.805 68.725 63.06 68.725 ;
      RECT  65.07 68.815 64.89 67.11 ;
      RECT  64.71 68.815 64.53 67.11 ;
      RECT  65.46 68.815 65.25 67.11 ;
      RECT  65.67 69.02 65.46 68.815 ;
      RECT  65.67 68.815 65.46 67.11 ;
      RECT  62.55 68.815 62.34 67.11 ;
      POLYGON  63.06 67.735 63.06 67.325 62.805 67.325 62.805 67.655 62.885 67.735 63.06 67.735 ;
      RECT  65.46 69.4 65.25 69.02 ;
      RECT  62.55 69.73 62.34 69.4 ;
      RECT  64.35 69.73 64.17 68.815 ;
      RECT  62.71 68.23 62.625 67.82 ;
      RECT  63.63 68.815 63.45 67.11 ;
      RECT  63.27 67.735 63.06 67.325 ;
      RECT  65.46 69.73 65.25 69.4 ;
      RECT  63.27 68.725 63.06 68.315 ;
      RECT  63.27 69.4 63.06 69.02 ;
      RECT  65.67 69.4 65.46 69.02 ;
      RECT  63.99 69.73 63.81 68.815 ;
      RECT  63.99 68.815 63.81 67.11 ;
      RECT  62.55 69.02 62.34 68.815 ;
      RECT  65.46 69.02 65.25 68.815 ;
      RECT  65.67 69.73 65.46 69.4 ;
      RECT  63.63 69.73 63.45 68.815 ;
      RECT  65.07 69.73 64.89 68.815 ;
      POLYGON  62.625 69.73 62.625 69.4 63.06 69.4 63.06 69.02 62.625 69.02 62.625 68.815 62.55 68.815 62.55 69.73 62.625 69.73 ;
      RECT  64.35 68.815 64.17 67.11 ;
      RECT  62.625 69.605 62.55 71.31 ;
      RECT  62.55 69.02 62.34 69.4 ;
      RECT  64.71 68.69 64.53 69.605 ;
      POLYGON  63.06 69.695 63.06 70.105 62.885 70.105 62.805 70.025 62.805 69.695 63.06 69.695 ;
      RECT  65.07 69.605 64.89 71.31 ;
      RECT  64.71 69.605 64.53 71.31 ;
      RECT  65.46 69.605 65.25 71.31 ;
      RECT  65.67 69.4 65.46 69.605 ;
      RECT  65.67 69.605 65.46 71.31 ;
      RECT  62.55 69.605 62.34 71.31 ;
      POLYGON  63.06 70.685 63.06 71.095 62.805 71.095 62.805 70.765 62.885 70.685 63.06 70.685 ;
      RECT  65.46 69.02 65.25 69.4 ;
      RECT  62.55 68.69 62.34 69.02 ;
      RECT  64.35 68.69 64.17 69.605 ;
      RECT  62.71 70.19 62.625 70.6 ;
      RECT  63.63 69.605 63.45 71.31 ;
      RECT  63.27 70.685 63.06 71.095 ;
      RECT  65.46 68.69 65.25 69.02 ;
      RECT  63.27 69.695 63.06 70.105 ;
      RECT  63.27 69.02 63.06 69.4 ;
      RECT  65.67 69.02 65.46 69.4 ;
      RECT  63.99 68.69 63.81 69.605 ;
      RECT  63.99 69.605 63.81 71.31 ;
      RECT  62.55 69.4 62.34 69.605 ;
      RECT  65.46 69.4 65.25 69.605 ;
      RECT  65.67 68.69 65.46 69.02 ;
      RECT  63.63 68.69 63.45 69.605 ;
      RECT  65.07 68.69 64.89 69.605 ;
      POLYGON  62.625 68.69 62.625 69.02 63.06 69.02 63.06 69.4 62.625 69.4 62.625 69.605 62.55 69.605 62.55 68.69 62.625 68.69 ;
      RECT  64.35 69.605 64.17 71.31 ;
      RECT  62.625 72.765 62.55 71.06 ;
      RECT  62.55 73.35 62.34 72.97 ;
      RECT  64.71 73.68 64.53 72.765 ;
      POLYGON  63.06 72.675 63.06 72.265 62.885 72.265 62.805 72.345 62.805 72.675 63.06 72.675 ;
      RECT  65.07 72.765 64.89 71.06 ;
      RECT  64.71 72.765 64.53 71.06 ;
      RECT  65.46 72.765 65.25 71.06 ;
      RECT  65.67 72.97 65.46 72.765 ;
      RECT  65.67 72.765 65.46 71.06 ;
      RECT  62.55 72.765 62.34 71.06 ;
      POLYGON  63.06 71.685 63.06 71.275 62.805 71.275 62.805 71.605 62.885 71.685 63.06 71.685 ;
      RECT  65.46 73.35 65.25 72.97 ;
      RECT  62.55 73.68 62.34 73.35 ;
      RECT  64.35 73.68 64.17 72.765 ;
      RECT  62.71 72.18 62.625 71.77 ;
      RECT  63.63 72.765 63.45 71.06 ;
      RECT  63.27 71.685 63.06 71.275 ;
      RECT  65.46 73.68 65.25 73.35 ;
      RECT  63.27 72.675 63.06 72.265 ;
      RECT  63.27 73.35 63.06 72.97 ;
      RECT  65.67 73.35 65.46 72.97 ;
      RECT  63.99 73.68 63.81 72.765 ;
      RECT  63.99 72.765 63.81 71.06 ;
      RECT  62.55 72.97 62.34 72.765 ;
      RECT  65.46 72.97 65.25 72.765 ;
      RECT  65.67 73.68 65.46 73.35 ;
      RECT  63.63 73.68 63.45 72.765 ;
      RECT  65.07 73.68 64.89 72.765 ;
      POLYGON  62.625 73.68 62.625 73.35 63.06 73.35 63.06 72.97 62.625 72.97 62.625 72.765 62.55 72.765 62.55 73.68 62.625 73.68 ;
      RECT  64.35 72.765 64.17 71.06 ;
      RECT  62.625 73.555 62.55 75.26 ;
      RECT  62.55 72.97 62.34 73.35 ;
      RECT  64.71 72.64 64.53 73.555 ;
      POLYGON  63.06 73.645 63.06 74.055 62.885 74.055 62.805 73.975 62.805 73.645 63.06 73.645 ;
      RECT  65.07 73.555 64.89 75.26 ;
      RECT  64.71 73.555 64.53 75.26 ;
      RECT  65.46 73.555 65.25 75.26 ;
      RECT  65.67 73.35 65.46 73.555 ;
      RECT  65.67 73.555 65.46 75.26 ;
      RECT  62.55 73.555 62.34 75.26 ;
      POLYGON  63.06 74.635 63.06 75.045 62.805 75.045 62.805 74.715 62.885 74.635 63.06 74.635 ;
      RECT  65.46 72.97 65.25 73.35 ;
      RECT  62.55 72.64 62.34 72.97 ;
      RECT  64.35 72.64 64.17 73.555 ;
      RECT  62.71 74.14 62.625 74.55 ;
      RECT  63.63 73.555 63.45 75.26 ;
      RECT  63.27 74.635 63.06 75.045 ;
      RECT  65.46 72.64 65.25 72.97 ;
      RECT  63.27 73.645 63.06 74.055 ;
      RECT  63.27 72.97 63.06 73.35 ;
      RECT  65.67 72.97 65.46 73.35 ;
      RECT  63.99 72.64 63.81 73.555 ;
      RECT  63.99 73.555 63.81 75.26 ;
      RECT  62.55 73.35 62.34 73.555 ;
      RECT  65.46 73.35 65.25 73.555 ;
      RECT  65.67 72.64 65.46 72.97 ;
      RECT  63.63 72.64 63.45 73.555 ;
      RECT  65.07 72.64 64.89 73.555 ;
      POLYGON  62.625 72.64 62.625 72.97 63.06 72.97 63.06 73.35 62.625 73.35 62.625 73.555 62.55 73.555 62.55 72.64 62.625 72.64 ;
      RECT  64.35 73.555 64.17 75.26 ;
      RECT  62.625 76.715 62.55 75.01 ;
      RECT  62.55 77.3 62.34 76.92 ;
      RECT  64.71 77.63 64.53 76.715 ;
      POLYGON  63.06 76.625 63.06 76.215 62.885 76.215 62.805 76.295 62.805 76.625 63.06 76.625 ;
      RECT  65.07 76.715 64.89 75.01 ;
      RECT  64.71 76.715 64.53 75.01 ;
      RECT  65.46 76.715 65.25 75.01 ;
      RECT  65.67 76.92 65.46 76.715 ;
      RECT  65.67 76.715 65.46 75.01 ;
      RECT  62.55 76.715 62.34 75.01 ;
      POLYGON  63.06 75.635 63.06 75.225 62.805 75.225 62.805 75.555 62.885 75.635 63.06 75.635 ;
      RECT  65.46 77.3 65.25 76.92 ;
      RECT  62.55 77.63 62.34 77.3 ;
      RECT  64.35 77.63 64.17 76.715 ;
      RECT  62.71 76.13 62.625 75.72 ;
      RECT  63.63 76.715 63.45 75.01 ;
      RECT  63.27 75.635 63.06 75.225 ;
      RECT  65.46 77.63 65.25 77.3 ;
      RECT  63.27 76.625 63.06 76.215 ;
      RECT  63.27 77.3 63.06 76.92 ;
      RECT  65.67 77.3 65.46 76.92 ;
      RECT  63.99 77.63 63.81 76.715 ;
      RECT  63.99 76.715 63.81 75.01 ;
      RECT  62.55 76.92 62.34 76.715 ;
      RECT  65.46 76.92 65.25 76.715 ;
      RECT  65.67 77.63 65.46 77.3 ;
      RECT  63.63 77.63 63.45 76.715 ;
      RECT  65.07 77.63 64.89 76.715 ;
      POLYGON  62.625 77.63 62.625 77.3 63.06 77.3 63.06 76.92 62.625 76.92 62.625 76.715 62.55 76.715 62.55 77.63 62.625 77.63 ;
      RECT  64.35 76.715 64.17 75.01 ;
      RECT  62.625 77.505 62.55 79.21 ;
      RECT  62.55 76.92 62.34 77.3 ;
      RECT  64.71 76.59 64.53 77.505 ;
      POLYGON  63.06 77.595 63.06 78.005 62.885 78.005 62.805 77.925 62.805 77.595 63.06 77.595 ;
      RECT  65.07 77.505 64.89 79.21 ;
      RECT  64.71 77.505 64.53 79.21 ;
      RECT  65.46 77.505 65.25 79.21 ;
      RECT  65.67 77.3 65.46 77.505 ;
      RECT  65.67 77.505 65.46 79.21 ;
      RECT  62.55 77.505 62.34 79.21 ;
      POLYGON  63.06 78.585 63.06 78.995 62.805 78.995 62.805 78.665 62.885 78.585 63.06 78.585 ;
      RECT  65.46 76.92 65.25 77.3 ;
      RECT  62.55 76.59 62.34 76.92 ;
      RECT  64.35 76.59 64.17 77.505 ;
      RECT  62.71 78.09 62.625 78.5 ;
      RECT  63.63 77.505 63.45 79.21 ;
      RECT  63.27 78.585 63.06 78.995 ;
      RECT  65.46 76.59 65.25 76.92 ;
      RECT  63.27 77.595 63.06 78.005 ;
      RECT  63.27 76.92 63.06 77.3 ;
      RECT  65.67 76.92 65.46 77.3 ;
      RECT  63.99 76.59 63.81 77.505 ;
      RECT  63.99 77.505 63.81 79.21 ;
      RECT  62.55 77.3 62.34 77.505 ;
      RECT  65.46 77.3 65.25 77.505 ;
      RECT  65.67 76.59 65.46 76.92 ;
      RECT  63.63 76.59 63.45 77.505 ;
      RECT  65.07 76.59 64.89 77.505 ;
      POLYGON  62.625 76.59 62.625 76.92 63.06 76.92 63.06 77.3 62.625 77.3 62.625 77.505 62.55 77.505 62.55 76.59 62.625 76.59 ;
      RECT  64.35 77.505 64.17 79.21 ;
      RECT  62.625 80.665 62.55 78.96 ;
      RECT  62.55 81.25 62.34 80.87 ;
      RECT  64.71 81.58 64.53 80.665 ;
      POLYGON  63.06 80.575 63.06 80.165 62.885 80.165 62.805 80.245 62.805 80.575 63.06 80.575 ;
      RECT  65.07 80.665 64.89 78.96 ;
      RECT  64.71 80.665 64.53 78.96 ;
      RECT  65.46 80.665 65.25 78.96 ;
      RECT  65.67 80.87 65.46 80.665 ;
      RECT  65.67 80.665 65.46 78.96 ;
      RECT  62.55 80.665 62.34 78.96 ;
      POLYGON  63.06 79.585 63.06 79.175 62.805 79.175 62.805 79.505 62.885 79.585 63.06 79.585 ;
      RECT  65.46 81.25 65.25 80.87 ;
      RECT  62.55 81.58 62.34 81.25 ;
      RECT  64.35 81.58 64.17 80.665 ;
      RECT  62.71 80.08 62.625 79.67 ;
      RECT  63.63 80.665 63.45 78.96 ;
      RECT  63.27 79.585 63.06 79.175 ;
      RECT  65.46 81.58 65.25 81.25 ;
      RECT  63.27 80.575 63.06 80.165 ;
      RECT  63.27 81.25 63.06 80.87 ;
      RECT  65.67 81.25 65.46 80.87 ;
      RECT  63.99 81.58 63.81 80.665 ;
      RECT  63.99 80.665 63.81 78.96 ;
      RECT  62.55 80.87 62.34 80.665 ;
      RECT  65.46 80.87 65.25 80.665 ;
      RECT  65.67 81.58 65.46 81.25 ;
      RECT  63.63 81.58 63.45 80.665 ;
      RECT  65.07 81.58 64.89 80.665 ;
      POLYGON  62.625 81.58 62.625 81.25 63.06 81.25 63.06 80.87 62.625 80.87 62.625 80.665 62.55 80.665 62.55 81.58 62.625 81.58 ;
      RECT  64.35 80.665 64.17 78.96 ;
      RECT  62.625 81.455 62.55 83.16 ;
      RECT  62.55 80.87 62.34 81.25 ;
      RECT  64.71 80.54 64.53 81.455 ;
      POLYGON  63.06 81.545 63.06 81.955 62.885 81.955 62.805 81.875 62.805 81.545 63.06 81.545 ;
      RECT  65.07 81.455 64.89 83.16 ;
      RECT  64.71 81.455 64.53 83.16 ;
      RECT  65.46 81.455 65.25 83.16 ;
      RECT  65.67 81.25 65.46 81.455 ;
      RECT  65.67 81.455 65.46 83.16 ;
      RECT  62.55 81.455 62.34 83.16 ;
      POLYGON  63.06 82.535 63.06 82.945 62.805 82.945 62.805 82.615 62.885 82.535 63.06 82.535 ;
      RECT  65.46 80.87 65.25 81.25 ;
      RECT  62.55 80.54 62.34 80.87 ;
      RECT  64.35 80.54 64.17 81.455 ;
      RECT  62.71 82.04 62.625 82.45 ;
      RECT  63.63 81.455 63.45 83.16 ;
      RECT  63.27 82.535 63.06 82.945 ;
      RECT  65.46 80.54 65.25 80.87 ;
      RECT  63.27 81.545 63.06 81.955 ;
      RECT  63.27 80.87 63.06 81.25 ;
      RECT  65.67 80.87 65.46 81.25 ;
      RECT  63.99 80.54 63.81 81.455 ;
      RECT  63.99 81.455 63.81 83.16 ;
      RECT  62.55 81.25 62.34 81.455 ;
      RECT  65.46 81.25 65.25 81.455 ;
      RECT  65.67 80.54 65.46 80.87 ;
      RECT  63.63 80.54 63.45 81.455 ;
      RECT  65.07 80.54 64.89 81.455 ;
      POLYGON  62.625 80.54 62.625 80.87 63.06 80.87 63.06 81.25 62.625 81.25 62.625 81.455 62.55 81.455 62.55 80.54 62.625 80.54 ;
      RECT  64.35 81.455 64.17 83.16 ;
      RECT  62.625 84.615 62.55 82.91 ;
      RECT  62.55 85.2 62.34 84.82 ;
      RECT  64.71 85.53 64.53 84.615 ;
      POLYGON  63.06 84.525 63.06 84.115 62.885 84.115 62.805 84.195 62.805 84.525 63.06 84.525 ;
      RECT  65.07 84.615 64.89 82.91 ;
      RECT  64.71 84.615 64.53 82.91 ;
      RECT  65.46 84.615 65.25 82.91 ;
      RECT  65.67 84.82 65.46 84.615 ;
      RECT  65.67 84.615 65.46 82.91 ;
      RECT  62.55 84.615 62.34 82.91 ;
      POLYGON  63.06 83.535 63.06 83.125 62.805 83.125 62.805 83.455 62.885 83.535 63.06 83.535 ;
      RECT  65.46 85.2 65.25 84.82 ;
      RECT  62.55 85.53 62.34 85.2 ;
      RECT  64.35 85.53 64.17 84.615 ;
      RECT  62.71 84.03 62.625 83.62 ;
      RECT  63.63 84.615 63.45 82.91 ;
      RECT  63.27 83.535 63.06 83.125 ;
      RECT  65.46 85.53 65.25 85.2 ;
      RECT  63.27 84.525 63.06 84.115 ;
      RECT  63.27 85.2 63.06 84.82 ;
      RECT  65.67 85.2 65.46 84.82 ;
      RECT  63.99 85.53 63.81 84.615 ;
      RECT  63.99 84.615 63.81 82.91 ;
      RECT  62.55 84.82 62.34 84.615 ;
      RECT  65.46 84.82 65.25 84.615 ;
      RECT  65.67 85.53 65.46 85.2 ;
      RECT  63.63 85.53 63.45 84.615 ;
      RECT  65.07 85.53 64.89 84.615 ;
      POLYGON  62.625 85.53 62.625 85.2 63.06 85.2 63.06 84.82 62.625 84.82 62.625 84.615 62.55 84.615 62.55 85.53 62.625 85.53 ;
      RECT  64.35 84.615 64.17 82.91 ;
      RECT  62.625 85.405 62.55 87.11 ;
      RECT  62.55 84.82 62.34 85.2 ;
      RECT  64.71 84.49 64.53 85.405 ;
      POLYGON  63.06 85.495 63.06 85.905 62.885 85.905 62.805 85.825 62.805 85.495 63.06 85.495 ;
      RECT  65.07 85.405 64.89 87.11 ;
      RECT  64.71 85.405 64.53 87.11 ;
      RECT  65.46 85.405 65.25 87.11 ;
      RECT  65.67 85.2 65.46 85.405 ;
      RECT  65.67 85.405 65.46 87.11 ;
      RECT  62.55 85.405 62.34 87.11 ;
      POLYGON  63.06 86.485 63.06 86.895 62.805 86.895 62.805 86.565 62.885 86.485 63.06 86.485 ;
      RECT  65.46 84.82 65.25 85.2 ;
      RECT  62.55 84.49 62.34 84.82 ;
      RECT  64.35 84.49 64.17 85.405 ;
      RECT  62.71 85.99 62.625 86.4 ;
      RECT  63.63 85.405 63.45 87.11 ;
      RECT  63.27 86.485 63.06 86.895 ;
      RECT  65.46 84.49 65.25 84.82 ;
      RECT  63.27 85.495 63.06 85.905 ;
      RECT  63.27 84.82 63.06 85.2 ;
      RECT  65.67 84.82 65.46 85.2 ;
      RECT  63.99 84.49 63.81 85.405 ;
      RECT  63.99 85.405 63.81 87.11 ;
      RECT  62.55 85.2 62.34 85.405 ;
      RECT  65.46 85.2 65.25 85.405 ;
      RECT  65.67 84.49 65.46 84.82 ;
      RECT  63.63 84.49 63.45 85.405 ;
      RECT  65.07 84.49 64.89 85.405 ;
      POLYGON  62.625 84.49 62.625 84.82 63.06 84.82 63.06 85.2 62.625 85.2 62.625 85.405 62.55 85.405 62.55 84.49 62.625 84.49 ;
      RECT  64.35 85.405 64.17 87.11 ;
      RECT  62.625 88.565 62.55 86.86 ;
      RECT  62.55 89.15 62.34 88.77 ;
      RECT  64.71 89.48 64.53 88.565 ;
      POLYGON  63.06 88.475 63.06 88.065 62.885 88.065 62.805 88.145 62.805 88.475 63.06 88.475 ;
      RECT  65.07 88.565 64.89 86.86 ;
      RECT  64.71 88.565 64.53 86.86 ;
      RECT  65.46 88.565 65.25 86.86 ;
      RECT  65.67 88.77 65.46 88.565 ;
      RECT  65.67 88.565 65.46 86.86 ;
      RECT  62.55 88.565 62.34 86.86 ;
      POLYGON  63.06 87.485 63.06 87.075 62.805 87.075 62.805 87.405 62.885 87.485 63.06 87.485 ;
      RECT  65.46 89.15 65.25 88.77 ;
      RECT  62.55 89.48 62.34 89.15 ;
      RECT  64.35 89.48 64.17 88.565 ;
      RECT  62.71 87.98 62.625 87.57 ;
      RECT  63.63 88.565 63.45 86.86 ;
      RECT  63.27 87.485 63.06 87.075 ;
      RECT  65.46 89.48 65.25 89.15 ;
      RECT  63.27 88.475 63.06 88.065 ;
      RECT  63.27 89.15 63.06 88.77 ;
      RECT  65.67 89.15 65.46 88.77 ;
      RECT  63.99 89.48 63.81 88.565 ;
      RECT  63.99 88.565 63.81 86.86 ;
      RECT  62.55 88.77 62.34 88.565 ;
      RECT  65.46 88.77 65.25 88.565 ;
      RECT  65.67 89.48 65.46 89.15 ;
      RECT  63.63 89.48 63.45 88.565 ;
      RECT  65.07 89.48 64.89 88.565 ;
      POLYGON  62.625 89.48 62.625 89.15 63.06 89.15 63.06 88.77 62.625 88.77 62.625 88.565 62.55 88.565 62.55 89.48 62.625 89.48 ;
      RECT  64.35 88.565 64.17 86.86 ;
      RECT  62.625 89.355 62.55 91.06 ;
      RECT  62.55 88.77 62.34 89.15 ;
      RECT  64.71 88.44 64.53 89.355 ;
      POLYGON  63.06 89.445 63.06 89.855 62.885 89.855 62.805 89.775 62.805 89.445 63.06 89.445 ;
      RECT  65.07 89.355 64.89 91.06 ;
      RECT  64.71 89.355 64.53 91.06 ;
      RECT  65.46 89.355 65.25 91.06 ;
      RECT  65.67 89.15 65.46 89.355 ;
      RECT  65.67 89.355 65.46 91.06 ;
      RECT  62.55 89.355 62.34 91.06 ;
      POLYGON  63.06 90.435 63.06 90.845 62.805 90.845 62.805 90.515 62.885 90.435 63.06 90.435 ;
      RECT  65.46 88.77 65.25 89.15 ;
      RECT  62.55 88.44 62.34 88.77 ;
      RECT  64.35 88.44 64.17 89.355 ;
      RECT  62.71 89.94 62.625 90.35 ;
      RECT  63.63 89.355 63.45 91.06 ;
      RECT  63.27 90.435 63.06 90.845 ;
      RECT  65.46 88.44 65.25 88.77 ;
      RECT  63.27 89.445 63.06 89.855 ;
      RECT  63.27 88.77 63.06 89.15 ;
      RECT  65.67 88.77 65.46 89.15 ;
      RECT  63.99 88.44 63.81 89.355 ;
      RECT  63.99 89.355 63.81 91.06 ;
      RECT  62.55 89.15 62.34 89.355 ;
      RECT  65.46 89.15 65.25 89.355 ;
      RECT  65.67 88.44 65.46 88.77 ;
      RECT  63.63 88.44 63.45 89.355 ;
      RECT  65.07 88.44 64.89 89.355 ;
      POLYGON  62.625 88.44 62.625 88.77 63.06 88.77 63.06 89.15 62.625 89.15 62.625 89.355 62.55 89.355 62.55 88.44 62.625 88.44 ;
      RECT  64.35 89.355 64.17 91.06 ;
      RECT  62.625 92.515 62.55 90.81 ;
      RECT  62.55 93.1 62.34 92.72 ;
      RECT  64.71 93.43 64.53 92.515 ;
      POLYGON  63.06 92.425 63.06 92.015 62.885 92.015 62.805 92.095 62.805 92.425 63.06 92.425 ;
      RECT  65.07 92.515 64.89 90.81 ;
      RECT  64.71 92.515 64.53 90.81 ;
      RECT  65.46 92.515 65.25 90.81 ;
      RECT  65.67 92.72 65.46 92.515 ;
      RECT  65.67 92.515 65.46 90.81 ;
      RECT  62.55 92.515 62.34 90.81 ;
      POLYGON  63.06 91.435 63.06 91.025 62.805 91.025 62.805 91.355 62.885 91.435 63.06 91.435 ;
      RECT  65.46 93.1 65.25 92.72 ;
      RECT  62.55 93.43 62.34 93.1 ;
      RECT  64.35 93.43 64.17 92.515 ;
      RECT  62.71 91.93 62.625 91.52 ;
      RECT  63.63 92.515 63.45 90.81 ;
      RECT  63.27 91.435 63.06 91.025 ;
      RECT  65.46 93.43 65.25 93.1 ;
      RECT  63.27 92.425 63.06 92.015 ;
      RECT  63.27 93.1 63.06 92.72 ;
      RECT  65.67 93.1 65.46 92.72 ;
      RECT  63.99 93.43 63.81 92.515 ;
      RECT  63.99 92.515 63.81 90.81 ;
      RECT  62.55 92.72 62.34 92.515 ;
      RECT  65.46 92.72 65.25 92.515 ;
      RECT  65.67 93.43 65.46 93.1 ;
      RECT  63.63 93.43 63.45 92.515 ;
      RECT  65.07 93.43 64.89 92.515 ;
      POLYGON  62.625 93.43 62.625 93.1 63.06 93.1 63.06 92.72 62.625 92.72 62.625 92.515 62.55 92.515 62.55 93.43 62.625 93.43 ;
      RECT  64.35 92.515 64.17 90.81 ;
      RECT  62.625 93.305 62.55 95.01 ;
      RECT  62.55 92.72 62.34 93.1 ;
      RECT  64.71 92.39 64.53 93.305 ;
      POLYGON  63.06 93.395 63.06 93.805 62.885 93.805 62.805 93.725 62.805 93.395 63.06 93.395 ;
      RECT  65.07 93.305 64.89 95.01 ;
      RECT  64.71 93.305 64.53 95.01 ;
      RECT  65.46 93.305 65.25 95.01 ;
      RECT  65.67 93.1 65.46 93.305 ;
      RECT  65.67 93.305 65.46 95.01 ;
      RECT  62.55 93.305 62.34 95.01 ;
      POLYGON  63.06 94.385 63.06 94.795 62.805 94.795 62.805 94.465 62.885 94.385 63.06 94.385 ;
      RECT  65.46 92.72 65.25 93.1 ;
      RECT  62.55 92.39 62.34 92.72 ;
      RECT  64.35 92.39 64.17 93.305 ;
      RECT  62.71 93.89 62.625 94.3 ;
      RECT  63.63 93.305 63.45 95.01 ;
      RECT  63.27 94.385 63.06 94.795 ;
      RECT  65.46 92.39 65.25 92.72 ;
      RECT  63.27 93.395 63.06 93.805 ;
      RECT  63.27 92.72 63.06 93.1 ;
      RECT  65.67 92.72 65.46 93.1 ;
      RECT  63.99 92.39 63.81 93.305 ;
      RECT  63.99 93.305 63.81 95.01 ;
      RECT  62.55 93.1 62.34 93.305 ;
      RECT  65.46 93.1 65.25 93.305 ;
      RECT  65.67 92.39 65.46 92.72 ;
      RECT  63.63 92.39 63.45 93.305 ;
      RECT  65.07 92.39 64.89 93.305 ;
      POLYGON  62.625 92.39 62.625 92.72 63.06 92.72 63.06 93.1 62.625 93.1 62.625 93.305 62.55 93.305 62.55 92.39 62.625 92.39 ;
      RECT  64.35 93.305 64.17 95.01 ;
      RECT  64.35 96.07 64.17 94.49 ;
      RECT  64.71 96.07 64.53 94.49 ;
      RECT  64.26 96.07 64.13 95.36 ;
      RECT  63.99 96.07 63.81 94.49 ;
      RECT  64.39 96.07 64.26 95.36 ;
      RECT  64.71 96.86 64.53 96.07 ;
      RECT  65.07 96.86 64.89 96.07 ;
      RECT  63.63 96.86 63.45 96.07 ;
      RECT  64.35 96.86 64.17 96.07 ;
      RECT  63.99 96.86 63.81 96.07 ;
      RECT  65.07 96.07 64.89 94.49 ;
      RECT  63.63 96.07 63.45 94.49 ;
      RECT  64.17 81.455 64.35 83.16 ;
      RECT  64.17 90.81 64.35 92.515 ;
      RECT  64.17 59.21 64.35 60.915 ;
      RECT  64.17 67.11 64.35 68.815 ;
      RECT  64.17 75.01 64.35 76.715 ;
      RECT  64.17 85.405 64.35 87.11 ;
      RECT  64.17 89.355 64.35 91.06 ;
      RECT  64.17 93.305 64.35 95.01 ;
      RECT  64.17 86.86 64.35 88.565 ;
      RECT  64.17 73.555 64.35 75.26 ;
      RECT  64.17 63.16 64.35 64.865 ;
      RECT  64.17 69.605 64.35 71.31 ;
      RECT  64.17 77.505 64.35 79.21 ;
      RECT  64.17 71.06 64.35 72.765 ;
      RECT  64.17 82.91 64.35 84.615 ;
      RECT  64.17 65.655 64.35 67.36 ;
      RECT  64.17 61.705 64.35 63.41 ;
      RECT  64.17 78.96 64.35 80.665 ;
      RECT  72.81 58.15 72.99 59.73 ;
      RECT  72.45 58.15 72.63 59.73 ;
      RECT  72.9 58.15 73.03 58.86 ;
      RECT  73.17 58.15 73.35 59.73 ;
      RECT  72.77 58.15 72.9 58.86 ;
      RECT  72.45 57.36 72.63 58.15 ;
      RECT  72.09 57.36 72.27 58.15 ;
      RECT  73.53 57.36 73.71 58.15 ;
      RECT  72.81 57.36 72.99 58.15 ;
      RECT  73.17 57.36 73.35 58.15 ;
      RECT  72.09 58.15 72.27 59.73 ;
      RECT  73.53 58.15 73.71 59.73 ;
      RECT  74.535 60.915 74.61 59.21 ;
      RECT  74.61 61.5 74.82 61.12 ;
      RECT  72.45 61.83 72.63 60.915 ;
      POLYGON  74.1 60.825 74.1 60.415 74.275 60.415 74.355 60.495 74.355 60.825 74.1 60.825 ;
      RECT  72.09 60.915 72.27 59.21 ;
      RECT  72.45 60.915 72.63 59.21 ;
      RECT  71.7 60.915 71.91 59.21 ;
      RECT  71.49 61.12 71.7 60.915 ;
      RECT  71.49 60.915 71.7 59.21 ;
      RECT  74.61 60.915 74.82 59.21 ;
      POLYGON  74.1 59.835 74.1 59.425 74.355 59.425 74.355 59.755 74.275 59.835 74.1 59.835 ;
      RECT  71.7 61.5 71.91 61.12 ;
      RECT  74.61 61.83 74.82 61.5 ;
      RECT  72.81 61.83 72.99 60.915 ;
      RECT  74.45 60.33 74.535 59.92 ;
      RECT  73.53 60.915 73.71 59.21 ;
      RECT  73.89 59.835 74.1 59.425 ;
      RECT  71.7 61.83 71.91 61.5 ;
      RECT  73.89 60.825 74.1 60.415 ;
      RECT  73.89 61.5 74.1 61.12 ;
      RECT  71.49 61.5 71.7 61.12 ;
      RECT  73.17 61.83 73.35 60.915 ;
      RECT  73.17 60.915 73.35 59.21 ;
      RECT  74.61 61.12 74.82 60.915 ;
      RECT  71.7 61.12 71.91 60.915 ;
      RECT  71.49 61.83 71.7 61.5 ;
      RECT  73.53 61.83 73.71 60.915 ;
      RECT  72.09 61.83 72.27 60.915 ;
      POLYGON  74.535 61.83 74.535 61.5 74.1 61.5 74.1 61.12 74.535 61.12 74.535 60.915 74.61 60.915 74.61 61.83 74.535 61.83 ;
      RECT  72.81 60.915 72.99 59.21 ;
      RECT  74.535 61.705 74.61 63.41 ;
      RECT  74.61 61.12 74.82 61.5 ;
      RECT  72.45 60.79 72.63 61.705 ;
      POLYGON  74.1 61.795 74.1 62.205 74.275 62.205 74.355 62.125 74.355 61.795 74.1 61.795 ;
      RECT  72.09 61.705 72.27 63.41 ;
      RECT  72.45 61.705 72.63 63.41 ;
      RECT  71.7 61.705 71.91 63.41 ;
      RECT  71.49 61.5 71.7 61.705 ;
      RECT  71.49 61.705 71.7 63.41 ;
      RECT  74.61 61.705 74.82 63.41 ;
      POLYGON  74.1 62.785 74.1 63.195 74.355 63.195 74.355 62.865 74.275 62.785 74.1 62.785 ;
      RECT  71.7 61.12 71.91 61.5 ;
      RECT  74.61 60.79 74.82 61.12 ;
      RECT  72.81 60.79 72.99 61.705 ;
      RECT  74.45 62.29 74.535 62.7 ;
      RECT  73.53 61.705 73.71 63.41 ;
      RECT  73.89 62.785 74.1 63.195 ;
      RECT  71.7 60.79 71.91 61.12 ;
      RECT  73.89 61.795 74.1 62.205 ;
      RECT  73.89 61.12 74.1 61.5 ;
      RECT  71.49 61.12 71.7 61.5 ;
      RECT  73.17 60.79 73.35 61.705 ;
      RECT  73.17 61.705 73.35 63.41 ;
      RECT  74.61 61.5 74.82 61.705 ;
      RECT  71.7 61.5 71.91 61.705 ;
      RECT  71.49 60.79 71.7 61.12 ;
      RECT  73.53 60.79 73.71 61.705 ;
      RECT  72.09 60.79 72.27 61.705 ;
      POLYGON  74.535 60.79 74.535 61.12 74.1 61.12 74.1 61.5 74.535 61.5 74.535 61.705 74.61 61.705 74.61 60.79 74.535 60.79 ;
      RECT  72.81 61.705 72.99 63.41 ;
      RECT  74.535 64.865 74.61 63.16 ;
      RECT  74.61 65.45 74.82 65.07 ;
      RECT  72.45 65.78 72.63 64.865 ;
      POLYGON  74.1 64.775 74.1 64.365 74.275 64.365 74.355 64.445 74.355 64.775 74.1 64.775 ;
      RECT  72.09 64.865 72.27 63.16 ;
      RECT  72.45 64.865 72.63 63.16 ;
      RECT  71.7 64.865 71.91 63.16 ;
      RECT  71.49 65.07 71.7 64.865 ;
      RECT  71.49 64.865 71.7 63.16 ;
      RECT  74.61 64.865 74.82 63.16 ;
      POLYGON  74.1 63.785 74.1 63.375 74.355 63.375 74.355 63.705 74.275 63.785 74.1 63.785 ;
      RECT  71.7 65.45 71.91 65.07 ;
      RECT  74.61 65.78 74.82 65.45 ;
      RECT  72.81 65.78 72.99 64.865 ;
      RECT  74.45 64.28 74.535 63.87 ;
      RECT  73.53 64.865 73.71 63.16 ;
      RECT  73.89 63.785 74.1 63.375 ;
      RECT  71.7 65.78 71.91 65.45 ;
      RECT  73.89 64.775 74.1 64.365 ;
      RECT  73.89 65.45 74.1 65.07 ;
      RECT  71.49 65.45 71.7 65.07 ;
      RECT  73.17 65.78 73.35 64.865 ;
      RECT  73.17 64.865 73.35 63.16 ;
      RECT  74.61 65.07 74.82 64.865 ;
      RECT  71.7 65.07 71.91 64.865 ;
      RECT  71.49 65.78 71.7 65.45 ;
      RECT  73.53 65.78 73.71 64.865 ;
      RECT  72.09 65.78 72.27 64.865 ;
      POLYGON  74.535 65.78 74.535 65.45 74.1 65.45 74.1 65.07 74.535 65.07 74.535 64.865 74.61 64.865 74.61 65.78 74.535 65.78 ;
      RECT  72.81 64.865 72.99 63.16 ;
      RECT  74.535 65.655 74.61 67.36 ;
      RECT  74.61 65.07 74.82 65.45 ;
      RECT  72.45 64.74 72.63 65.655 ;
      POLYGON  74.1 65.745 74.1 66.155 74.275 66.155 74.355 66.075 74.355 65.745 74.1 65.745 ;
      RECT  72.09 65.655 72.27 67.36 ;
      RECT  72.45 65.655 72.63 67.36 ;
      RECT  71.7 65.655 71.91 67.36 ;
      RECT  71.49 65.45 71.7 65.655 ;
      RECT  71.49 65.655 71.7 67.36 ;
      RECT  74.61 65.655 74.82 67.36 ;
      POLYGON  74.1 66.735 74.1 67.145 74.355 67.145 74.355 66.815 74.275 66.735 74.1 66.735 ;
      RECT  71.7 65.07 71.91 65.45 ;
      RECT  74.61 64.74 74.82 65.07 ;
      RECT  72.81 64.74 72.99 65.655 ;
      RECT  74.45 66.24 74.535 66.65 ;
      RECT  73.53 65.655 73.71 67.36 ;
      RECT  73.89 66.735 74.1 67.145 ;
      RECT  71.7 64.74 71.91 65.07 ;
      RECT  73.89 65.745 74.1 66.155 ;
      RECT  73.89 65.07 74.1 65.45 ;
      RECT  71.49 65.07 71.7 65.45 ;
      RECT  73.17 64.74 73.35 65.655 ;
      RECT  73.17 65.655 73.35 67.36 ;
      RECT  74.61 65.45 74.82 65.655 ;
      RECT  71.7 65.45 71.91 65.655 ;
      RECT  71.49 64.74 71.7 65.07 ;
      RECT  73.53 64.74 73.71 65.655 ;
      RECT  72.09 64.74 72.27 65.655 ;
      POLYGON  74.535 64.74 74.535 65.07 74.1 65.07 74.1 65.45 74.535 65.45 74.535 65.655 74.61 65.655 74.61 64.74 74.535 64.74 ;
      RECT  72.81 65.655 72.99 67.36 ;
      RECT  74.535 68.815 74.61 67.11 ;
      RECT  74.61 69.4 74.82 69.02 ;
      RECT  72.45 69.73 72.63 68.815 ;
      POLYGON  74.1 68.725 74.1 68.315 74.275 68.315 74.355 68.395 74.355 68.725 74.1 68.725 ;
      RECT  72.09 68.815 72.27 67.11 ;
      RECT  72.45 68.815 72.63 67.11 ;
      RECT  71.7 68.815 71.91 67.11 ;
      RECT  71.49 69.02 71.7 68.815 ;
      RECT  71.49 68.815 71.7 67.11 ;
      RECT  74.61 68.815 74.82 67.11 ;
      POLYGON  74.1 67.735 74.1 67.325 74.355 67.325 74.355 67.655 74.275 67.735 74.1 67.735 ;
      RECT  71.7 69.4 71.91 69.02 ;
      RECT  74.61 69.73 74.82 69.4 ;
      RECT  72.81 69.73 72.99 68.815 ;
      RECT  74.45 68.23 74.535 67.82 ;
      RECT  73.53 68.815 73.71 67.11 ;
      RECT  73.89 67.735 74.1 67.325 ;
      RECT  71.7 69.73 71.91 69.4 ;
      RECT  73.89 68.725 74.1 68.315 ;
      RECT  73.89 69.4 74.1 69.02 ;
      RECT  71.49 69.4 71.7 69.02 ;
      RECT  73.17 69.73 73.35 68.815 ;
      RECT  73.17 68.815 73.35 67.11 ;
      RECT  74.61 69.02 74.82 68.815 ;
      RECT  71.7 69.02 71.91 68.815 ;
      RECT  71.49 69.73 71.7 69.4 ;
      RECT  73.53 69.73 73.71 68.815 ;
      RECT  72.09 69.73 72.27 68.815 ;
      POLYGON  74.535 69.73 74.535 69.4 74.1 69.4 74.1 69.02 74.535 69.02 74.535 68.815 74.61 68.815 74.61 69.73 74.535 69.73 ;
      RECT  72.81 68.815 72.99 67.11 ;
      RECT  74.535 69.605 74.61 71.31 ;
      RECT  74.61 69.02 74.82 69.4 ;
      RECT  72.45 68.69 72.63 69.605 ;
      POLYGON  74.1 69.695 74.1 70.105 74.275 70.105 74.355 70.025 74.355 69.695 74.1 69.695 ;
      RECT  72.09 69.605 72.27 71.31 ;
      RECT  72.45 69.605 72.63 71.31 ;
      RECT  71.7 69.605 71.91 71.31 ;
      RECT  71.49 69.4 71.7 69.605 ;
      RECT  71.49 69.605 71.7 71.31 ;
      RECT  74.61 69.605 74.82 71.31 ;
      POLYGON  74.1 70.685 74.1 71.095 74.355 71.095 74.355 70.765 74.275 70.685 74.1 70.685 ;
      RECT  71.7 69.02 71.91 69.4 ;
      RECT  74.61 68.69 74.82 69.02 ;
      RECT  72.81 68.69 72.99 69.605 ;
      RECT  74.45 70.19 74.535 70.6 ;
      RECT  73.53 69.605 73.71 71.31 ;
      RECT  73.89 70.685 74.1 71.095 ;
      RECT  71.7 68.69 71.91 69.02 ;
      RECT  73.89 69.695 74.1 70.105 ;
      RECT  73.89 69.02 74.1 69.4 ;
      RECT  71.49 69.02 71.7 69.4 ;
      RECT  73.17 68.69 73.35 69.605 ;
      RECT  73.17 69.605 73.35 71.31 ;
      RECT  74.61 69.4 74.82 69.605 ;
      RECT  71.7 69.4 71.91 69.605 ;
      RECT  71.49 68.69 71.7 69.02 ;
      RECT  73.53 68.69 73.71 69.605 ;
      RECT  72.09 68.69 72.27 69.605 ;
      POLYGON  74.535 68.69 74.535 69.02 74.1 69.02 74.1 69.4 74.535 69.4 74.535 69.605 74.61 69.605 74.61 68.69 74.535 68.69 ;
      RECT  72.81 69.605 72.99 71.31 ;
      RECT  74.535 72.765 74.61 71.06 ;
      RECT  74.61 73.35 74.82 72.97 ;
      RECT  72.45 73.68 72.63 72.765 ;
      POLYGON  74.1 72.675 74.1 72.265 74.275 72.265 74.355 72.345 74.355 72.675 74.1 72.675 ;
      RECT  72.09 72.765 72.27 71.06 ;
      RECT  72.45 72.765 72.63 71.06 ;
      RECT  71.7 72.765 71.91 71.06 ;
      RECT  71.49 72.97 71.7 72.765 ;
      RECT  71.49 72.765 71.7 71.06 ;
      RECT  74.61 72.765 74.82 71.06 ;
      POLYGON  74.1 71.685 74.1 71.275 74.355 71.275 74.355 71.605 74.275 71.685 74.1 71.685 ;
      RECT  71.7 73.35 71.91 72.97 ;
      RECT  74.61 73.68 74.82 73.35 ;
      RECT  72.81 73.68 72.99 72.765 ;
      RECT  74.45 72.18 74.535 71.77 ;
      RECT  73.53 72.765 73.71 71.06 ;
      RECT  73.89 71.685 74.1 71.275 ;
      RECT  71.7 73.68 71.91 73.35 ;
      RECT  73.89 72.675 74.1 72.265 ;
      RECT  73.89 73.35 74.1 72.97 ;
      RECT  71.49 73.35 71.7 72.97 ;
      RECT  73.17 73.68 73.35 72.765 ;
      RECT  73.17 72.765 73.35 71.06 ;
      RECT  74.61 72.97 74.82 72.765 ;
      RECT  71.7 72.97 71.91 72.765 ;
      RECT  71.49 73.68 71.7 73.35 ;
      RECT  73.53 73.68 73.71 72.765 ;
      RECT  72.09 73.68 72.27 72.765 ;
      POLYGON  74.535 73.68 74.535 73.35 74.1 73.35 74.1 72.97 74.535 72.97 74.535 72.765 74.61 72.765 74.61 73.68 74.535 73.68 ;
      RECT  72.81 72.765 72.99 71.06 ;
      RECT  74.535 73.555 74.61 75.26 ;
      RECT  74.61 72.97 74.82 73.35 ;
      RECT  72.45 72.64 72.63 73.555 ;
      POLYGON  74.1 73.645 74.1 74.055 74.275 74.055 74.355 73.975 74.355 73.645 74.1 73.645 ;
      RECT  72.09 73.555 72.27 75.26 ;
      RECT  72.45 73.555 72.63 75.26 ;
      RECT  71.7 73.555 71.91 75.26 ;
      RECT  71.49 73.35 71.7 73.555 ;
      RECT  71.49 73.555 71.7 75.26 ;
      RECT  74.61 73.555 74.82 75.26 ;
      POLYGON  74.1 74.635 74.1 75.045 74.355 75.045 74.355 74.715 74.275 74.635 74.1 74.635 ;
      RECT  71.7 72.97 71.91 73.35 ;
      RECT  74.61 72.64 74.82 72.97 ;
      RECT  72.81 72.64 72.99 73.555 ;
      RECT  74.45 74.14 74.535 74.55 ;
      RECT  73.53 73.555 73.71 75.26 ;
      RECT  73.89 74.635 74.1 75.045 ;
      RECT  71.7 72.64 71.91 72.97 ;
      RECT  73.89 73.645 74.1 74.055 ;
      RECT  73.89 72.97 74.1 73.35 ;
      RECT  71.49 72.97 71.7 73.35 ;
      RECT  73.17 72.64 73.35 73.555 ;
      RECT  73.17 73.555 73.35 75.26 ;
      RECT  74.61 73.35 74.82 73.555 ;
      RECT  71.7 73.35 71.91 73.555 ;
      RECT  71.49 72.64 71.7 72.97 ;
      RECT  73.53 72.64 73.71 73.555 ;
      RECT  72.09 72.64 72.27 73.555 ;
      POLYGON  74.535 72.64 74.535 72.97 74.1 72.97 74.1 73.35 74.535 73.35 74.535 73.555 74.61 73.555 74.61 72.64 74.535 72.64 ;
      RECT  72.81 73.555 72.99 75.26 ;
      RECT  74.535 76.715 74.61 75.01 ;
      RECT  74.61 77.3 74.82 76.92 ;
      RECT  72.45 77.63 72.63 76.715 ;
      POLYGON  74.1 76.625 74.1 76.215 74.275 76.215 74.355 76.295 74.355 76.625 74.1 76.625 ;
      RECT  72.09 76.715 72.27 75.01 ;
      RECT  72.45 76.715 72.63 75.01 ;
      RECT  71.7 76.715 71.91 75.01 ;
      RECT  71.49 76.92 71.7 76.715 ;
      RECT  71.49 76.715 71.7 75.01 ;
      RECT  74.61 76.715 74.82 75.01 ;
      POLYGON  74.1 75.635 74.1 75.225 74.355 75.225 74.355 75.555 74.275 75.635 74.1 75.635 ;
      RECT  71.7 77.3 71.91 76.92 ;
      RECT  74.61 77.63 74.82 77.3 ;
      RECT  72.81 77.63 72.99 76.715 ;
      RECT  74.45 76.13 74.535 75.72 ;
      RECT  73.53 76.715 73.71 75.01 ;
      RECT  73.89 75.635 74.1 75.225 ;
      RECT  71.7 77.63 71.91 77.3 ;
      RECT  73.89 76.625 74.1 76.215 ;
      RECT  73.89 77.3 74.1 76.92 ;
      RECT  71.49 77.3 71.7 76.92 ;
      RECT  73.17 77.63 73.35 76.715 ;
      RECT  73.17 76.715 73.35 75.01 ;
      RECT  74.61 76.92 74.82 76.715 ;
      RECT  71.7 76.92 71.91 76.715 ;
      RECT  71.49 77.63 71.7 77.3 ;
      RECT  73.53 77.63 73.71 76.715 ;
      RECT  72.09 77.63 72.27 76.715 ;
      POLYGON  74.535 77.63 74.535 77.3 74.1 77.3 74.1 76.92 74.535 76.92 74.535 76.715 74.61 76.715 74.61 77.63 74.535 77.63 ;
      RECT  72.81 76.715 72.99 75.01 ;
      RECT  74.535 77.505 74.61 79.21 ;
      RECT  74.61 76.92 74.82 77.3 ;
      RECT  72.45 76.59 72.63 77.505 ;
      POLYGON  74.1 77.595 74.1 78.005 74.275 78.005 74.355 77.925 74.355 77.595 74.1 77.595 ;
      RECT  72.09 77.505 72.27 79.21 ;
      RECT  72.45 77.505 72.63 79.21 ;
      RECT  71.7 77.505 71.91 79.21 ;
      RECT  71.49 77.3 71.7 77.505 ;
      RECT  71.49 77.505 71.7 79.21 ;
      RECT  74.61 77.505 74.82 79.21 ;
      POLYGON  74.1 78.585 74.1 78.995 74.355 78.995 74.355 78.665 74.275 78.585 74.1 78.585 ;
      RECT  71.7 76.92 71.91 77.3 ;
      RECT  74.61 76.59 74.82 76.92 ;
      RECT  72.81 76.59 72.99 77.505 ;
      RECT  74.45 78.09 74.535 78.5 ;
      RECT  73.53 77.505 73.71 79.21 ;
      RECT  73.89 78.585 74.1 78.995 ;
      RECT  71.7 76.59 71.91 76.92 ;
      RECT  73.89 77.595 74.1 78.005 ;
      RECT  73.89 76.92 74.1 77.3 ;
      RECT  71.49 76.92 71.7 77.3 ;
      RECT  73.17 76.59 73.35 77.505 ;
      RECT  73.17 77.505 73.35 79.21 ;
      RECT  74.61 77.3 74.82 77.505 ;
      RECT  71.7 77.3 71.91 77.505 ;
      RECT  71.49 76.59 71.7 76.92 ;
      RECT  73.53 76.59 73.71 77.505 ;
      RECT  72.09 76.59 72.27 77.505 ;
      POLYGON  74.535 76.59 74.535 76.92 74.1 76.92 74.1 77.3 74.535 77.3 74.535 77.505 74.61 77.505 74.61 76.59 74.535 76.59 ;
      RECT  72.81 77.505 72.99 79.21 ;
      RECT  74.535 80.665 74.61 78.96 ;
      RECT  74.61 81.25 74.82 80.87 ;
      RECT  72.45 81.58 72.63 80.665 ;
      POLYGON  74.1 80.575 74.1 80.165 74.275 80.165 74.355 80.245 74.355 80.575 74.1 80.575 ;
      RECT  72.09 80.665 72.27 78.96 ;
      RECT  72.45 80.665 72.63 78.96 ;
      RECT  71.7 80.665 71.91 78.96 ;
      RECT  71.49 80.87 71.7 80.665 ;
      RECT  71.49 80.665 71.7 78.96 ;
      RECT  74.61 80.665 74.82 78.96 ;
      POLYGON  74.1 79.585 74.1 79.175 74.355 79.175 74.355 79.505 74.275 79.585 74.1 79.585 ;
      RECT  71.7 81.25 71.91 80.87 ;
      RECT  74.61 81.58 74.82 81.25 ;
      RECT  72.81 81.58 72.99 80.665 ;
      RECT  74.45 80.08 74.535 79.67 ;
      RECT  73.53 80.665 73.71 78.96 ;
      RECT  73.89 79.585 74.1 79.175 ;
      RECT  71.7 81.58 71.91 81.25 ;
      RECT  73.89 80.575 74.1 80.165 ;
      RECT  73.89 81.25 74.1 80.87 ;
      RECT  71.49 81.25 71.7 80.87 ;
      RECT  73.17 81.58 73.35 80.665 ;
      RECT  73.17 80.665 73.35 78.96 ;
      RECT  74.61 80.87 74.82 80.665 ;
      RECT  71.7 80.87 71.91 80.665 ;
      RECT  71.49 81.58 71.7 81.25 ;
      RECT  73.53 81.58 73.71 80.665 ;
      RECT  72.09 81.58 72.27 80.665 ;
      POLYGON  74.535 81.58 74.535 81.25 74.1 81.25 74.1 80.87 74.535 80.87 74.535 80.665 74.61 80.665 74.61 81.58 74.535 81.58 ;
      RECT  72.81 80.665 72.99 78.96 ;
      RECT  74.535 81.455 74.61 83.16 ;
      RECT  74.61 80.87 74.82 81.25 ;
      RECT  72.45 80.54 72.63 81.455 ;
      POLYGON  74.1 81.545 74.1 81.955 74.275 81.955 74.355 81.875 74.355 81.545 74.1 81.545 ;
      RECT  72.09 81.455 72.27 83.16 ;
      RECT  72.45 81.455 72.63 83.16 ;
      RECT  71.7 81.455 71.91 83.16 ;
      RECT  71.49 81.25 71.7 81.455 ;
      RECT  71.49 81.455 71.7 83.16 ;
      RECT  74.61 81.455 74.82 83.16 ;
      POLYGON  74.1 82.535 74.1 82.945 74.355 82.945 74.355 82.615 74.275 82.535 74.1 82.535 ;
      RECT  71.7 80.87 71.91 81.25 ;
      RECT  74.61 80.54 74.82 80.87 ;
      RECT  72.81 80.54 72.99 81.455 ;
      RECT  74.45 82.04 74.535 82.45 ;
      RECT  73.53 81.455 73.71 83.16 ;
      RECT  73.89 82.535 74.1 82.945 ;
      RECT  71.7 80.54 71.91 80.87 ;
      RECT  73.89 81.545 74.1 81.955 ;
      RECT  73.89 80.87 74.1 81.25 ;
      RECT  71.49 80.87 71.7 81.25 ;
      RECT  73.17 80.54 73.35 81.455 ;
      RECT  73.17 81.455 73.35 83.16 ;
      RECT  74.61 81.25 74.82 81.455 ;
      RECT  71.7 81.25 71.91 81.455 ;
      RECT  71.49 80.54 71.7 80.87 ;
      RECT  73.53 80.54 73.71 81.455 ;
      RECT  72.09 80.54 72.27 81.455 ;
      POLYGON  74.535 80.54 74.535 80.87 74.1 80.87 74.1 81.25 74.535 81.25 74.535 81.455 74.61 81.455 74.61 80.54 74.535 80.54 ;
      RECT  72.81 81.455 72.99 83.16 ;
      RECT  74.535 84.615 74.61 82.91 ;
      RECT  74.61 85.2 74.82 84.82 ;
      RECT  72.45 85.53 72.63 84.615 ;
      POLYGON  74.1 84.525 74.1 84.115 74.275 84.115 74.355 84.195 74.355 84.525 74.1 84.525 ;
      RECT  72.09 84.615 72.27 82.91 ;
      RECT  72.45 84.615 72.63 82.91 ;
      RECT  71.7 84.615 71.91 82.91 ;
      RECT  71.49 84.82 71.7 84.615 ;
      RECT  71.49 84.615 71.7 82.91 ;
      RECT  74.61 84.615 74.82 82.91 ;
      POLYGON  74.1 83.535 74.1 83.125 74.355 83.125 74.355 83.455 74.275 83.535 74.1 83.535 ;
      RECT  71.7 85.2 71.91 84.82 ;
      RECT  74.61 85.53 74.82 85.2 ;
      RECT  72.81 85.53 72.99 84.615 ;
      RECT  74.45 84.03 74.535 83.62 ;
      RECT  73.53 84.615 73.71 82.91 ;
      RECT  73.89 83.535 74.1 83.125 ;
      RECT  71.7 85.53 71.91 85.2 ;
      RECT  73.89 84.525 74.1 84.115 ;
      RECT  73.89 85.2 74.1 84.82 ;
      RECT  71.49 85.2 71.7 84.82 ;
      RECT  73.17 85.53 73.35 84.615 ;
      RECT  73.17 84.615 73.35 82.91 ;
      RECT  74.61 84.82 74.82 84.615 ;
      RECT  71.7 84.82 71.91 84.615 ;
      RECT  71.49 85.53 71.7 85.2 ;
      RECT  73.53 85.53 73.71 84.615 ;
      RECT  72.09 85.53 72.27 84.615 ;
      POLYGON  74.535 85.53 74.535 85.2 74.1 85.2 74.1 84.82 74.535 84.82 74.535 84.615 74.61 84.615 74.61 85.53 74.535 85.53 ;
      RECT  72.81 84.615 72.99 82.91 ;
      RECT  74.535 85.405 74.61 87.11 ;
      RECT  74.61 84.82 74.82 85.2 ;
      RECT  72.45 84.49 72.63 85.405 ;
      POLYGON  74.1 85.495 74.1 85.905 74.275 85.905 74.355 85.825 74.355 85.495 74.1 85.495 ;
      RECT  72.09 85.405 72.27 87.11 ;
      RECT  72.45 85.405 72.63 87.11 ;
      RECT  71.7 85.405 71.91 87.11 ;
      RECT  71.49 85.2 71.7 85.405 ;
      RECT  71.49 85.405 71.7 87.11 ;
      RECT  74.61 85.405 74.82 87.11 ;
      POLYGON  74.1 86.485 74.1 86.895 74.355 86.895 74.355 86.565 74.275 86.485 74.1 86.485 ;
      RECT  71.7 84.82 71.91 85.2 ;
      RECT  74.61 84.49 74.82 84.82 ;
      RECT  72.81 84.49 72.99 85.405 ;
      RECT  74.45 85.99 74.535 86.4 ;
      RECT  73.53 85.405 73.71 87.11 ;
      RECT  73.89 86.485 74.1 86.895 ;
      RECT  71.7 84.49 71.91 84.82 ;
      RECT  73.89 85.495 74.1 85.905 ;
      RECT  73.89 84.82 74.1 85.2 ;
      RECT  71.49 84.82 71.7 85.2 ;
      RECT  73.17 84.49 73.35 85.405 ;
      RECT  73.17 85.405 73.35 87.11 ;
      RECT  74.61 85.2 74.82 85.405 ;
      RECT  71.7 85.2 71.91 85.405 ;
      RECT  71.49 84.49 71.7 84.82 ;
      RECT  73.53 84.49 73.71 85.405 ;
      RECT  72.09 84.49 72.27 85.405 ;
      POLYGON  74.535 84.49 74.535 84.82 74.1 84.82 74.1 85.2 74.535 85.2 74.535 85.405 74.61 85.405 74.61 84.49 74.535 84.49 ;
      RECT  72.81 85.405 72.99 87.11 ;
      RECT  74.535 88.565 74.61 86.86 ;
      RECT  74.61 89.15 74.82 88.77 ;
      RECT  72.45 89.48 72.63 88.565 ;
      POLYGON  74.1 88.475 74.1 88.065 74.275 88.065 74.355 88.145 74.355 88.475 74.1 88.475 ;
      RECT  72.09 88.565 72.27 86.86 ;
      RECT  72.45 88.565 72.63 86.86 ;
      RECT  71.7 88.565 71.91 86.86 ;
      RECT  71.49 88.77 71.7 88.565 ;
      RECT  71.49 88.565 71.7 86.86 ;
      RECT  74.61 88.565 74.82 86.86 ;
      POLYGON  74.1 87.485 74.1 87.075 74.355 87.075 74.355 87.405 74.275 87.485 74.1 87.485 ;
      RECT  71.7 89.15 71.91 88.77 ;
      RECT  74.61 89.48 74.82 89.15 ;
      RECT  72.81 89.48 72.99 88.565 ;
      RECT  74.45 87.98 74.535 87.57 ;
      RECT  73.53 88.565 73.71 86.86 ;
      RECT  73.89 87.485 74.1 87.075 ;
      RECT  71.7 89.48 71.91 89.15 ;
      RECT  73.89 88.475 74.1 88.065 ;
      RECT  73.89 89.15 74.1 88.77 ;
      RECT  71.49 89.15 71.7 88.77 ;
      RECT  73.17 89.48 73.35 88.565 ;
      RECT  73.17 88.565 73.35 86.86 ;
      RECT  74.61 88.77 74.82 88.565 ;
      RECT  71.7 88.77 71.91 88.565 ;
      RECT  71.49 89.48 71.7 89.15 ;
      RECT  73.53 89.48 73.71 88.565 ;
      RECT  72.09 89.48 72.27 88.565 ;
      POLYGON  74.535 89.48 74.535 89.15 74.1 89.15 74.1 88.77 74.535 88.77 74.535 88.565 74.61 88.565 74.61 89.48 74.535 89.48 ;
      RECT  72.81 88.565 72.99 86.86 ;
      RECT  74.535 89.355 74.61 91.06 ;
      RECT  74.61 88.77 74.82 89.15 ;
      RECT  72.45 88.44 72.63 89.355 ;
      POLYGON  74.1 89.445 74.1 89.855 74.275 89.855 74.355 89.775 74.355 89.445 74.1 89.445 ;
      RECT  72.09 89.355 72.27 91.06 ;
      RECT  72.45 89.355 72.63 91.06 ;
      RECT  71.7 89.355 71.91 91.06 ;
      RECT  71.49 89.15 71.7 89.355 ;
      RECT  71.49 89.355 71.7 91.06 ;
      RECT  74.61 89.355 74.82 91.06 ;
      POLYGON  74.1 90.435 74.1 90.845 74.355 90.845 74.355 90.515 74.275 90.435 74.1 90.435 ;
      RECT  71.7 88.77 71.91 89.15 ;
      RECT  74.61 88.44 74.82 88.77 ;
      RECT  72.81 88.44 72.99 89.355 ;
      RECT  74.45 89.94 74.535 90.35 ;
      RECT  73.53 89.355 73.71 91.06 ;
      RECT  73.89 90.435 74.1 90.845 ;
      RECT  71.7 88.44 71.91 88.77 ;
      RECT  73.89 89.445 74.1 89.855 ;
      RECT  73.89 88.77 74.1 89.15 ;
      RECT  71.49 88.77 71.7 89.15 ;
      RECT  73.17 88.44 73.35 89.355 ;
      RECT  73.17 89.355 73.35 91.06 ;
      RECT  74.61 89.15 74.82 89.355 ;
      RECT  71.7 89.15 71.91 89.355 ;
      RECT  71.49 88.44 71.7 88.77 ;
      RECT  73.53 88.44 73.71 89.355 ;
      RECT  72.09 88.44 72.27 89.355 ;
      POLYGON  74.535 88.44 74.535 88.77 74.1 88.77 74.1 89.15 74.535 89.15 74.535 89.355 74.61 89.355 74.61 88.44 74.535 88.44 ;
      RECT  72.81 89.355 72.99 91.06 ;
      RECT  74.535 92.515 74.61 90.81 ;
      RECT  74.61 93.1 74.82 92.72 ;
      RECT  72.45 93.43 72.63 92.515 ;
      POLYGON  74.1 92.425 74.1 92.015 74.275 92.015 74.355 92.095 74.355 92.425 74.1 92.425 ;
      RECT  72.09 92.515 72.27 90.81 ;
      RECT  72.45 92.515 72.63 90.81 ;
      RECT  71.7 92.515 71.91 90.81 ;
      RECT  71.49 92.72 71.7 92.515 ;
      RECT  71.49 92.515 71.7 90.81 ;
      RECT  74.61 92.515 74.82 90.81 ;
      POLYGON  74.1 91.435 74.1 91.025 74.355 91.025 74.355 91.355 74.275 91.435 74.1 91.435 ;
      RECT  71.7 93.1 71.91 92.72 ;
      RECT  74.61 93.43 74.82 93.1 ;
      RECT  72.81 93.43 72.99 92.515 ;
      RECT  74.45 91.93 74.535 91.52 ;
      RECT  73.53 92.515 73.71 90.81 ;
      RECT  73.89 91.435 74.1 91.025 ;
      RECT  71.7 93.43 71.91 93.1 ;
      RECT  73.89 92.425 74.1 92.015 ;
      RECT  73.89 93.1 74.1 92.72 ;
      RECT  71.49 93.1 71.7 92.72 ;
      RECT  73.17 93.43 73.35 92.515 ;
      RECT  73.17 92.515 73.35 90.81 ;
      RECT  74.61 92.72 74.82 92.515 ;
      RECT  71.7 92.72 71.91 92.515 ;
      RECT  71.49 93.43 71.7 93.1 ;
      RECT  73.53 93.43 73.71 92.515 ;
      RECT  72.09 93.43 72.27 92.515 ;
      POLYGON  74.535 93.43 74.535 93.1 74.1 93.1 74.1 92.72 74.535 92.72 74.535 92.515 74.61 92.515 74.61 93.43 74.535 93.43 ;
      RECT  72.81 92.515 72.99 90.81 ;
      RECT  74.535 93.305 74.61 95.01 ;
      RECT  74.61 92.72 74.82 93.1 ;
      RECT  72.45 92.39 72.63 93.305 ;
      POLYGON  74.1 93.395 74.1 93.805 74.275 93.805 74.355 93.725 74.355 93.395 74.1 93.395 ;
      RECT  72.09 93.305 72.27 95.01 ;
      RECT  72.45 93.305 72.63 95.01 ;
      RECT  71.7 93.305 71.91 95.01 ;
      RECT  71.49 93.1 71.7 93.305 ;
      RECT  71.49 93.305 71.7 95.01 ;
      RECT  74.61 93.305 74.82 95.01 ;
      POLYGON  74.1 94.385 74.1 94.795 74.355 94.795 74.355 94.465 74.275 94.385 74.1 94.385 ;
      RECT  71.7 92.72 71.91 93.1 ;
      RECT  74.61 92.39 74.82 92.72 ;
      RECT  72.81 92.39 72.99 93.305 ;
      RECT  74.45 93.89 74.535 94.3 ;
      RECT  73.53 93.305 73.71 95.01 ;
      RECT  73.89 94.385 74.1 94.795 ;
      RECT  71.7 92.39 71.91 92.72 ;
      RECT  73.89 93.395 74.1 93.805 ;
      RECT  73.89 92.72 74.1 93.1 ;
      RECT  71.49 92.72 71.7 93.1 ;
      RECT  73.17 92.39 73.35 93.305 ;
      RECT  73.17 93.305 73.35 95.01 ;
      RECT  74.61 93.1 74.82 93.305 ;
      RECT  71.7 93.1 71.91 93.305 ;
      RECT  71.49 92.39 71.7 92.72 ;
      RECT  73.53 92.39 73.71 93.305 ;
      RECT  72.09 92.39 72.27 93.305 ;
      POLYGON  74.535 92.39 74.535 92.72 74.1 92.72 74.1 93.1 74.535 93.1 74.535 93.305 74.61 93.305 74.61 92.39 74.535 92.39 ;
      RECT  72.81 93.305 72.99 95.01 ;
      RECT  72.81 96.07 72.99 94.49 ;
      RECT  72.45 96.07 72.63 94.49 ;
      RECT  72.9 96.07 73.03 95.36 ;
      RECT  73.17 96.07 73.35 94.49 ;
      RECT  72.77 96.07 72.9 95.36 ;
      RECT  72.45 96.86 72.63 96.07 ;
      RECT  72.09 96.86 72.27 96.07 ;
      RECT  73.53 96.86 73.71 96.07 ;
      RECT  72.81 96.86 72.99 96.07 ;
      RECT  73.17 96.86 73.35 96.07 ;
      RECT  72.09 96.07 72.27 94.49 ;
      RECT  73.53 96.07 73.71 94.49 ;
      RECT  72.81 63.16 72.99 64.865 ;
      RECT  72.81 73.555 72.99 75.26 ;
      RECT  72.81 82.91 72.99 84.615 ;
      RECT  72.81 86.86 72.99 88.565 ;
      RECT  72.81 71.06 72.99 72.765 ;
      RECT  72.81 85.405 72.99 87.11 ;
      RECT  72.81 77.505 72.99 79.21 ;
      RECT  72.81 67.11 72.99 68.815 ;
      RECT  72.81 81.455 72.99 83.16 ;
      RECT  72.81 89.355 72.99 91.06 ;
      RECT  72.81 69.605 72.99 71.31 ;
      RECT  72.81 93.305 72.99 95.01 ;
      RECT  72.81 90.81 72.99 92.515 ;
      RECT  72.81 59.21 72.99 60.915 ;
      RECT  72.81 61.705 72.99 63.41 ;
      RECT  72.81 65.655 72.99 67.36 ;
      RECT  72.81 78.96 72.99 80.665 ;
      RECT  72.81 75.01 72.99 76.715 ;
      RECT  68.295 60.915 68.37 59.21 ;
      RECT  68.37 61.5 68.58 61.12 ;
      RECT  66.21 61.83 66.39 60.915 ;
      POLYGON  67.86 60.825 67.86 60.415 68.035 60.415 68.115 60.495 68.115 60.825 67.86 60.825 ;
      RECT  65.85 60.915 66.03 59.21 ;
      RECT  66.21 60.915 66.39 59.21 ;
      RECT  65.46 60.915 65.67 59.21 ;
      RECT  65.25 61.12 65.46 60.915 ;
      RECT  65.25 60.915 65.46 59.21 ;
      RECT  68.37 60.915 68.58 59.21 ;
      POLYGON  67.86 59.835 67.86 59.425 68.115 59.425 68.115 59.755 68.035 59.835 67.86 59.835 ;
      RECT  65.46 61.5 65.67 61.12 ;
      RECT  68.37 61.83 68.58 61.5 ;
      RECT  66.57 61.83 66.75 60.915 ;
      RECT  68.21 60.33 68.295 59.92 ;
      RECT  67.29 60.915 67.47 59.21 ;
      RECT  67.65 59.835 67.86 59.425 ;
      RECT  65.46 61.83 65.67 61.5 ;
      RECT  67.65 60.825 67.86 60.415 ;
      RECT  67.65 61.5 67.86 61.12 ;
      RECT  65.25 61.5 65.46 61.12 ;
      RECT  66.93 61.83 67.11 60.915 ;
      RECT  66.93 60.915 67.11 59.21 ;
      RECT  68.37 61.12 68.58 60.915 ;
      RECT  65.46 61.12 65.67 60.915 ;
      RECT  65.25 61.83 65.46 61.5 ;
      RECT  67.29 61.83 67.47 60.915 ;
      RECT  65.85 61.83 66.03 60.915 ;
      POLYGON  68.295 61.83 68.295 61.5 67.86 61.5 67.86 61.12 68.295 61.12 68.295 60.915 68.37 60.915 68.37 61.83 68.295 61.83 ;
      RECT  66.57 60.915 66.75 59.21 ;
      RECT  68.865 60.915 68.79 59.21 ;
      RECT  68.79 61.5 68.58 61.12 ;
      RECT  70.95 61.83 70.77 60.915 ;
      POLYGON  69.3 60.825 69.3 60.415 69.125 60.415 69.045 60.495 69.045 60.825 69.3 60.825 ;
      RECT  71.31 60.915 71.13 59.21 ;
      RECT  70.95 60.915 70.77 59.21 ;
      RECT  71.7 60.915 71.49 59.21 ;
      RECT  71.91 61.12 71.7 60.915 ;
      RECT  71.91 60.915 71.7 59.21 ;
      RECT  68.79 60.915 68.58 59.21 ;
      POLYGON  69.3 59.835 69.3 59.425 69.045 59.425 69.045 59.755 69.125 59.835 69.3 59.835 ;
      RECT  71.7 61.5 71.49 61.12 ;
      RECT  68.79 61.83 68.58 61.5 ;
      RECT  70.59 61.83 70.41 60.915 ;
      RECT  68.95 60.33 68.865 59.92 ;
      RECT  69.87 60.915 69.69 59.21 ;
      RECT  69.51 59.835 69.3 59.425 ;
      RECT  71.7 61.83 71.49 61.5 ;
      RECT  69.51 60.825 69.3 60.415 ;
      RECT  69.51 61.5 69.3 61.12 ;
      RECT  71.91 61.5 71.7 61.12 ;
      RECT  70.23 61.83 70.05 60.915 ;
      RECT  70.23 60.915 70.05 59.21 ;
      RECT  68.79 61.12 68.58 60.915 ;
      RECT  71.7 61.12 71.49 60.915 ;
      RECT  71.91 61.83 71.7 61.5 ;
      RECT  69.87 61.83 69.69 60.915 ;
      RECT  71.31 61.83 71.13 60.915 ;
      POLYGON  68.865 61.83 68.865 61.5 69.3 61.5 69.3 61.12 68.865 61.12 68.865 60.915 68.79 60.915 68.79 61.83 68.865 61.83 ;
      RECT  70.59 60.915 70.41 59.21 ;
      RECT  65.85 61.31 66.03 59.335 ;
      RECT  66.21 61.31 66.39 59.335 ;
      RECT  66.93 61.31 67.11 59.335 ;
      RECT  67.29 61.31 67.47 59.335 ;
      RECT  71.13 61.31 71.31 59.335 ;
      RECT  70.77 61.31 70.95 59.335 ;
      RECT  70.05 61.31 70.23 59.335 ;
      RECT  69.69 61.31 69.87 59.335 ;
      RECT  70.41 60.915 70.59 59.21 ;
      RECT  66.57 60.915 66.75 59.21 ;
      RECT  68.295 93.305 68.37 95.01 ;
      RECT  68.37 92.72 68.58 93.1 ;
      RECT  66.21 92.39 66.39 93.305 ;
      POLYGON  67.86 93.395 67.86 93.805 68.035 93.805 68.115 93.725 68.115 93.395 67.86 93.395 ;
      RECT  65.85 93.305 66.03 95.01 ;
      RECT  66.21 93.305 66.39 95.01 ;
      RECT  65.46 93.305 65.67 95.01 ;
      RECT  65.25 93.1 65.46 93.305 ;
      RECT  65.25 93.305 65.46 95.01 ;
      RECT  68.37 93.305 68.58 95.01 ;
      POLYGON  67.86 94.385 67.86 94.795 68.115 94.795 68.115 94.465 68.035 94.385 67.86 94.385 ;
      RECT  65.46 92.72 65.67 93.1 ;
      RECT  68.37 92.39 68.58 92.72 ;
      RECT  66.57 92.39 66.75 93.305 ;
      RECT  68.21 93.89 68.295 94.3 ;
      RECT  67.29 93.305 67.47 95.01 ;
      RECT  67.65 94.385 67.86 94.795 ;
      RECT  65.46 92.39 65.67 92.72 ;
      RECT  67.65 93.395 67.86 93.805 ;
      RECT  67.65 92.72 67.86 93.1 ;
      RECT  65.25 92.72 65.46 93.1 ;
      RECT  66.93 92.39 67.11 93.305 ;
      RECT  66.93 93.305 67.11 95.01 ;
      RECT  68.37 93.1 68.58 93.305 ;
      RECT  65.46 93.1 65.67 93.305 ;
      RECT  65.25 92.39 65.46 92.72 ;
      RECT  67.29 92.39 67.47 93.305 ;
      RECT  65.85 92.39 66.03 93.305 ;
      POLYGON  68.295 92.39 68.295 92.72 67.86 92.72 67.86 93.1 68.295 93.1 68.295 93.305 68.37 93.305 68.37 92.39 68.295 92.39 ;
      RECT  66.57 93.305 66.75 95.01 ;
      RECT  68.865 93.305 68.79 95.01 ;
      RECT  68.79 92.72 68.58 93.1 ;
      RECT  70.95 92.39 70.77 93.305 ;
      POLYGON  69.3 93.395 69.3 93.805 69.125 93.805 69.045 93.725 69.045 93.395 69.3 93.395 ;
      RECT  71.31 93.305 71.13 95.01 ;
      RECT  70.95 93.305 70.77 95.01 ;
      RECT  71.7 93.305 71.49 95.01 ;
      RECT  71.91 93.1 71.7 93.305 ;
      RECT  71.91 93.305 71.7 95.01 ;
      RECT  68.79 93.305 68.58 95.01 ;
      POLYGON  69.3 94.385 69.3 94.795 69.045 94.795 69.045 94.465 69.125 94.385 69.3 94.385 ;
      RECT  71.7 92.72 71.49 93.1 ;
      RECT  68.79 92.39 68.58 92.72 ;
      RECT  70.59 92.39 70.41 93.305 ;
      RECT  68.95 93.89 68.865 94.3 ;
      RECT  69.87 93.305 69.69 95.01 ;
      RECT  69.51 94.385 69.3 94.795 ;
      RECT  71.7 92.39 71.49 92.72 ;
      RECT  69.51 93.395 69.3 93.805 ;
      RECT  69.51 92.72 69.3 93.1 ;
      RECT  71.91 92.72 71.7 93.1 ;
      RECT  70.23 92.39 70.05 93.305 ;
      RECT  70.23 93.305 70.05 95.01 ;
      RECT  68.79 93.1 68.58 93.305 ;
      RECT  71.7 93.1 71.49 93.305 ;
      RECT  71.91 92.39 71.7 92.72 ;
      RECT  69.87 92.39 69.69 93.305 ;
      RECT  71.31 92.39 71.13 93.305 ;
      POLYGON  68.865 92.39 68.865 92.72 69.3 92.72 69.3 93.1 68.865 93.1 68.865 93.305 68.79 93.305 68.79 92.39 68.865 92.39 ;
      RECT  70.59 93.305 70.41 95.01 ;
      RECT  65.85 92.91 66.03 94.885 ;
      RECT  66.21 92.91 66.39 94.885 ;
      RECT  66.93 92.91 67.11 94.885 ;
      RECT  67.29 92.91 67.47 94.885 ;
      RECT  71.13 92.91 71.31 94.885 ;
      RECT  70.77 92.91 70.95 94.885 ;
      RECT  70.05 92.91 70.23 94.885 ;
      RECT  69.69 92.91 69.87 94.885 ;
      RECT  70.41 93.305 70.59 95.01 ;
      RECT  66.57 93.305 66.75 95.01 ;
      RECT  66.57 58.15 66.75 59.73 ;
      RECT  66.21 58.15 66.39 59.73 ;
      RECT  66.66 58.15 66.79 58.86 ;
      RECT  66.93 58.15 67.11 59.73 ;
      RECT  66.53 58.15 66.66 58.86 ;
      RECT  66.21 57.36 66.39 58.15 ;
      RECT  65.85 57.36 66.03 58.15 ;
      RECT  67.29 57.36 67.47 58.15 ;
      RECT  66.57 57.36 66.75 58.15 ;
      RECT  66.93 57.36 67.11 58.15 ;
      RECT  65.85 58.15 66.03 59.73 ;
      RECT  67.29 58.15 67.47 59.73 ;
      RECT  70.59 58.15 70.41 59.73 ;
      RECT  70.95 58.15 70.77 59.73 ;
      RECT  70.5 58.15 70.37 58.86 ;
      RECT  70.23 58.15 70.05 59.73 ;
      RECT  70.63 58.15 70.5 58.86 ;
      RECT  70.95 57.36 70.77 58.15 ;
      RECT  71.31 57.36 71.13 58.15 ;
      RECT  69.87 57.36 69.69 58.15 ;
      RECT  70.59 57.36 70.41 58.15 ;
      RECT  70.23 57.36 70.05 58.15 ;
      RECT  71.31 58.15 71.13 59.73 ;
      RECT  69.87 58.15 69.69 59.73 ;
      RECT  65.85 57.36 66.03 59.335 ;
      RECT  66.21 57.36 66.39 59.335 ;
      RECT  66.93 57.36 67.11 59.335 ;
      RECT  67.29 57.36 67.47 59.335 ;
      RECT  71.13 57.36 71.31 59.335 ;
      RECT  70.77 57.36 70.95 59.335 ;
      RECT  70.05 57.36 70.23 59.335 ;
      RECT  69.69 57.36 69.87 59.335 ;
      RECT  66.57 96.07 66.75 94.49 ;
      RECT  66.21 96.07 66.39 94.49 ;
      RECT  66.66 96.07 66.79 95.36 ;
      RECT  66.93 96.07 67.11 94.49 ;
      RECT  66.53 96.07 66.66 95.36 ;
      RECT  66.21 96.86 66.39 96.07 ;
      RECT  65.85 96.86 66.03 96.07 ;
      RECT  67.29 96.86 67.47 96.07 ;
      RECT  66.57 96.86 66.75 96.07 ;
      RECT  66.93 96.86 67.11 96.07 ;
      RECT  65.85 96.07 66.03 94.49 ;
      RECT  67.29 96.07 67.47 94.49 ;
      RECT  70.59 96.07 70.41 94.49 ;
      RECT  70.95 96.07 70.77 94.49 ;
      RECT  70.5 96.07 70.37 95.36 ;
      RECT  70.23 96.07 70.05 94.49 ;
      RECT  70.63 96.07 70.5 95.36 ;
      RECT  70.95 96.86 70.77 96.07 ;
      RECT  71.31 96.86 71.13 96.07 ;
      RECT  69.87 96.86 69.69 96.07 ;
      RECT  70.59 96.86 70.41 96.07 ;
      RECT  70.23 96.86 70.05 96.07 ;
      RECT  71.31 96.07 71.13 94.49 ;
      RECT  69.87 96.07 69.69 94.49 ;
      RECT  65.85 96.86 66.03 94.885 ;
      RECT  66.21 96.86 66.39 94.885 ;
      RECT  66.93 96.86 67.11 94.885 ;
      RECT  67.29 96.86 67.47 94.885 ;
      RECT  71.13 96.86 71.31 94.885 ;
      RECT  70.77 96.86 70.95 94.885 ;
      RECT  70.05 96.86 70.23 94.885 ;
      RECT  69.69 96.86 69.87 94.885 ;
      RECT  65.85 57.36 66.03 96.86 ;
      RECT  66.21 57.36 66.39 96.86 ;
      RECT  66.93 57.36 67.11 96.86 ;
      RECT  67.29 57.36 67.47 96.86 ;
      RECT  71.13 57.36 71.31 96.86 ;
      RECT  70.77 57.36 70.95 96.86 ;
      RECT  70.05 57.36 70.23 96.86 ;
      RECT  69.69 57.36 69.87 96.86 ;
      RECT  64.89 57.36 65.07 96.86 ;
      RECT  64.53 57.36 64.71 96.86 ;
      RECT  73.17 57.36 73.35 96.86 ;
      RECT  73.53 57.36 73.71 96.86 ;
      RECT  72.81 81.455 72.99 83.16 ;
      RECT  64.17 82.91 64.35 84.615 ;
      RECT  72.81 77.505 72.99 79.21 ;
      RECT  64.17 61.705 64.35 63.41 ;
      RECT  64.17 59.21 64.35 60.915 ;
      RECT  72.81 71.06 72.99 72.765 ;
      RECT  64.17 75.01 64.35 76.715 ;
      RECT  64.17 77.505 64.35 79.21 ;
      RECT  72.81 82.91 72.99 84.615 ;
      RECT  72.81 65.655 72.99 67.36 ;
      RECT  72.81 63.16 72.99 64.865 ;
      RECT  64.17 71.06 64.35 72.765 ;
      RECT  72.81 89.355 72.99 91.06 ;
      RECT  64.17 67.11 64.35 68.815 ;
      RECT  64.17 73.555 64.35 75.26 ;
      RECT  72.81 78.96 72.99 80.665 ;
      RECT  72.81 86.86 72.99 88.565 ;
      RECT  64.17 63.16 64.35 64.865 ;
      RECT  64.17 78.96 64.35 80.665 ;
      RECT  64.17 69.605 64.35 71.31 ;
      RECT  64.17 85.405 64.35 87.11 ;
      RECT  64.17 86.86 64.35 88.565 ;
      RECT  72.81 90.81 72.99 92.515 ;
      RECT  72.81 61.705 72.99 63.41 ;
      RECT  64.17 93.305 64.35 95.01 ;
      RECT  72.81 75.01 72.99 76.715 ;
      RECT  72.81 93.305 72.99 95.01 ;
      RECT  64.17 89.355 64.35 91.06 ;
      RECT  72.81 59.21 72.99 60.915 ;
      RECT  72.81 73.555 72.99 75.26 ;
      RECT  72.81 67.11 72.99 68.815 ;
      RECT  72.81 85.405 72.99 87.11 ;
      RECT  64.17 81.455 64.35 83.16 ;
      RECT  72.81 69.605 72.99 71.31 ;
      RECT  64.17 65.655 64.35 67.36 ;
      RECT  64.17 90.81 64.35 92.515 ;
      RECT  65.13 52.33 64.99 56.1 ;
      RECT  62.81 52.33 62.67 56.1 ;
      RECT  65.79 52.33 65.93 56.1 ;
      RECT  68.11 52.33 68.25 56.1 ;
      RECT  71.37 52.33 71.23 56.1 ;
      RECT  69.05 52.33 68.91 56.1 ;
      RECT  64.99 52.33 65.13 56.1 ;
      RECT  62.67 52.33 62.81 56.1 ;
      RECT  65.79 52.33 65.93 56.1 ;
      RECT  68.11 52.33 68.25 56.1 ;
      RECT  71.23 52.33 71.37 56.1 ;
      RECT  68.91 52.33 69.05 56.1 ;
      RECT  66.44 45.44 66.61 51.07 ;
      RECT  66.82 39.79 66.96 45.21 ;
      RECT  67.25 40.145 67.48 40.515 ;
      RECT  67.25 41.75 67.48 42.13 ;
      RECT  67.6 49.815 67.83 50.185 ;
      RECT  65.98 39.79 66.21 41.06 ;
      RECT  66.82 45.21 67.16 45.5 ;
      RECT  66.44 39.79 66.61 45.21 ;
      RECT  66.38 45.21 66.67 45.44 ;
      RECT  67.15 45.96 67.46 46.3 ;
      RECT  66.82 45.5 66.96 51.07 ;
      RECT  65.93 50.61 66.22 50.91 ;
      RECT  70.1 45.44 69.93 51.07 ;
      RECT  69.72 39.79 69.58 45.21 ;
      RECT  69.29 40.145 69.06 40.515 ;
      RECT  69.29 41.75 69.06 42.13 ;
      RECT  68.94 49.815 68.71 50.185 ;
      RECT  70.56 39.79 70.33 41.06 ;
      RECT  69.72 45.21 69.38 45.5 ;
      RECT  70.1 39.79 69.93 45.21 ;
      RECT  70.16 45.21 69.87 45.44 ;
      RECT  69.39 45.96 69.08 46.3 ;
      RECT  69.72 45.5 69.58 51.07 ;
      RECT  70.61 50.61 70.32 50.91 ;
      RECT  65.98 39.79 66.21 41.06 ;
      RECT  66.44 45.44 66.61 51.07 ;
      RECT  66.82 45.5 66.96 51.07 ;
      RECT  70.33 39.79 70.56 41.06 ;
      RECT  69.93 45.44 70.1 51.07 ;
      RECT  69.58 45.5 69.72 51.07 ;
      RECT  66.525 36.28 67.065 36.45 ;
      RECT  66.625 29.315 67.055 29.545 ;
      RECT  66.97 37.98 67.255 38.27 ;
      RECT  65.955 28.945 67.96 29.115 ;
      RECT  67.1 38.27 67.25 38.53 ;
      RECT  66.735 28.495 67.035 28.775 ;
      RECT  65.955 29.115 66.245 29.255 ;
      RECT  66.09 38.27 66.24 38.53 ;
      RECT  66.525 36.25 66.955 36.28 ;
      RECT  66.525 34.065 66.955 34.295 ;
      RECT  67.13 32.42 67.56 32.625 ;
      RECT  66.525 36.45 66.955 36.48 ;
      RECT  66.085 37.98 66.37 38.27 ;
      RECT  66.555 31.395 66.985 31.625 ;
      RECT  67.195 32.395 67.56 32.42 ;
      RECT  70.015 36.28 69.475 36.45 ;
      RECT  69.915 29.315 69.485 29.545 ;
      RECT  69.57 37.98 69.285 38.27 ;
      RECT  70.585 28.945 68.58 29.115 ;
      RECT  69.44 38.27 69.29 38.53 ;
      RECT  69.805 28.495 69.505 28.775 ;
      RECT  70.585 29.115 70.295 29.255 ;
      RECT  70.45 38.27 70.3 38.53 ;
      RECT  70.015 36.25 69.585 36.28 ;
      RECT  70.015 34.065 69.585 34.295 ;
      RECT  69.41 32.42 68.98 32.625 ;
      RECT  70.015 36.45 69.585 36.48 ;
      RECT  70.455 37.98 70.17 38.27 ;
      RECT  69.985 31.395 69.555 31.625 ;
      RECT  69.345 32.395 68.98 32.42 ;
      RECT  66.735 28.495 67.035 28.775 ;
      RECT  69.505 28.495 69.805 28.775 ;
      RECT  66.09 38.27 66.24 38.53 ;
      RECT  67.1 38.27 67.25 38.53 ;
      RECT  70.3 38.27 70.45 38.53 ;
      RECT  69.29 38.27 69.44 38.53 ;
      RECT  65.46 28.945 71.7 29.085 ;
      RECT  64.99 56.1 65.13 52.33 ;
      RECT  62.67 56.1 62.81 52.33 ;
      RECT  65.98 41.06 66.21 39.79 ;
      RECT  70.33 41.06 70.56 39.79 ;
      RECT  66.735 28.775 67.035 28.495 ;
      RECT  69.505 28.775 69.805 28.495 ;
      RECT  65.46 29.085 71.7 28.945 ;
      RECT  65.79 101.89 65.93 98.12 ;
      RECT  68.11 101.89 68.25 98.12 ;
      RECT  71.37 101.89 71.23 98.12 ;
      RECT  69.05 101.89 68.91 98.12 ;
      RECT  72.03 101.89 72.17 98.12 ;
      RECT  74.35 101.89 74.49 98.12 ;
      RECT  65.79 101.89 65.93 98.12 ;
      RECT  68.11 101.89 68.25 98.12 ;
      RECT  71.23 101.89 71.37 98.12 ;
      RECT  68.91 101.89 69.05 98.12 ;
      RECT  72.03 101.89 72.17 98.12 ;
      RECT  74.35 101.89 74.49 98.12 ;
      RECT  66.44 108.78 66.61 103.15 ;
      RECT  66.82 114.43 66.96 109.01 ;
      RECT  67.25 114.075 67.48 113.705 ;
      RECT  67.25 112.47 67.48 112.09 ;
      RECT  67.6 104.405 67.83 104.035 ;
      RECT  65.98 114.43 66.21 113.16 ;
      RECT  66.82 109.01 67.16 108.72 ;
      RECT  66.44 114.43 66.61 109.01 ;
      RECT  66.38 109.01 66.67 108.78 ;
      RECT  67.15 108.26 67.46 107.92 ;
      RECT  66.82 108.72 66.96 103.15 ;
      RECT  65.93 103.61 66.22 103.31 ;
      RECT  70.1 108.78 69.93 103.15 ;
      RECT  69.72 114.43 69.58 109.01 ;
      RECT  69.29 114.075 69.06 113.705 ;
      RECT  69.29 112.47 69.06 112.09 ;
      RECT  68.94 104.405 68.71 104.035 ;
      RECT  70.56 114.43 70.33 113.16 ;
      RECT  69.72 109.01 69.38 108.72 ;
      RECT  70.1 114.43 69.93 109.01 ;
      RECT  70.16 109.01 69.87 108.78 ;
      RECT  69.39 108.26 69.08 107.92 ;
      RECT  69.72 108.72 69.58 103.15 ;
      RECT  70.61 103.61 70.32 103.31 ;
      RECT  65.98 114.43 66.21 113.16 ;
      RECT  66.44 108.78 66.61 103.15 ;
      RECT  66.82 108.72 66.96 103.15 ;
      RECT  70.33 114.43 70.56 113.16 ;
      RECT  69.93 108.78 70.1 103.15 ;
      RECT  69.58 108.72 69.72 103.15 ;
      RECT  72.03 98.12 72.17 101.89 ;
      RECT  74.35 98.12 74.49 101.89 ;
      RECT  65.98 113.16 66.21 114.43 ;
      RECT  70.33 113.16 70.56 114.43 ;
      RECT  26.16 61.455 26.3 63.43 ;
      RECT  24.8 61.455 24.94 63.43 ;
      RECT  26.16 65.405 26.3 63.43 ;
      RECT  24.8 65.405 24.94 63.43 ;
      RECT  32.72 61.295 32.97 63.465 ;
      RECT  30.6 61.305 30.84 63.465 ;
      RECT  36.03 61.455 36.17 63.43 ;
      RECT  34.67 61.455 34.81 63.43 ;
      RECT  36.03 61.455 36.17 63.43 ;
      RECT  32.72 61.295 32.97 63.465 ;
      RECT  30.6 61.305 30.84 63.465 ;
      RECT  34.67 61.455 34.81 63.43 ;
      RECT  32.72 65.565 32.97 63.395 ;
      RECT  30.6 65.555 30.84 63.395 ;
      RECT  36.03 65.405 36.17 63.43 ;
      RECT  34.67 65.405 34.81 63.43 ;
      RECT  36.03 65.405 36.17 63.43 ;
      RECT  32.72 65.565 32.97 63.395 ;
      RECT  30.6 65.555 30.84 63.395 ;
      RECT  34.67 65.405 34.81 63.43 ;
      RECT  32.72 65.245 32.97 67.415 ;
      RECT  30.6 65.255 30.84 67.415 ;
      RECT  36.03 65.405 36.17 67.38 ;
      RECT  34.67 65.405 34.81 67.38 ;
      RECT  36.03 65.405 36.17 67.38 ;
      RECT  32.72 65.245 32.97 67.415 ;
      RECT  30.6 65.255 30.84 67.415 ;
      RECT  34.67 65.405 34.81 67.38 ;
      RECT  32.72 69.515 32.97 67.345 ;
      RECT  30.6 69.505 30.84 67.345 ;
      RECT  36.03 69.355 36.17 67.38 ;
      RECT  34.67 69.355 34.81 67.38 ;
      RECT  36.03 69.355 36.17 67.38 ;
      RECT  32.72 69.515 32.97 67.345 ;
      RECT  30.6 69.505 30.84 67.345 ;
      RECT  34.67 69.355 34.81 67.38 ;
      RECT  22.62 62.28 22.88 62.6 ;
      RECT  23.02 64.26 23.28 64.58 ;
      RECT  26.16 73.305 26.3 75.28 ;
      RECT  24.8 73.305 24.94 75.28 ;
      RECT  26.16 77.255 26.3 75.28 ;
      RECT  24.8 77.255 24.94 75.28 ;
      RECT  32.72 73.145 32.97 75.315 ;
      RECT  30.6 73.155 30.84 75.315 ;
      RECT  36.03 73.305 36.17 75.28 ;
      RECT  34.67 73.305 34.81 75.28 ;
      RECT  36.03 73.305 36.17 75.28 ;
      RECT  32.72 73.145 32.97 75.315 ;
      RECT  30.6 73.155 30.84 75.315 ;
      RECT  34.67 73.305 34.81 75.28 ;
      RECT  32.72 77.415 32.97 75.245 ;
      RECT  30.6 77.405 30.84 75.245 ;
      RECT  36.03 77.255 36.17 75.28 ;
      RECT  34.67 77.255 34.81 75.28 ;
      RECT  36.03 77.255 36.17 75.28 ;
      RECT  32.72 77.415 32.97 75.245 ;
      RECT  30.6 77.405 30.84 75.245 ;
      RECT  34.67 77.255 34.81 75.28 ;
      RECT  32.72 77.095 32.97 79.265 ;
      RECT  30.6 77.105 30.84 79.265 ;
      RECT  36.03 77.255 36.17 79.23 ;
      RECT  34.67 77.255 34.81 79.23 ;
      RECT  36.03 77.255 36.17 79.23 ;
      RECT  32.72 77.095 32.97 79.265 ;
      RECT  30.6 77.105 30.84 79.265 ;
      RECT  34.67 77.255 34.81 79.23 ;
      RECT  32.72 81.365 32.97 79.195 ;
      RECT  30.6 81.355 30.84 79.195 ;
      RECT  36.03 81.205 36.17 79.23 ;
      RECT  34.67 81.205 34.81 79.23 ;
      RECT  36.03 81.205 36.17 79.23 ;
      RECT  32.72 81.365 32.97 79.195 ;
      RECT  30.6 81.355 30.84 79.195 ;
      RECT  34.67 81.205 34.81 79.23 ;
      RECT  22.62 74.13 22.88 74.45 ;
      RECT  23.02 76.11 23.28 76.43 ;
      RECT  43.79 61.295 44.04 63.465 ;
      RECT  41.67 61.305 41.91 63.465 ;
      RECT  47.1 61.455 47.24 63.43 ;
      RECT  45.74 61.455 45.88 63.43 ;
      RECT  47.1 61.455 47.24 63.43 ;
      RECT  43.79 61.295 44.04 63.465 ;
      RECT  41.67 61.305 41.91 63.465 ;
      RECT  45.74 61.455 45.88 63.43 ;
      RECT  43.79 65.565 44.04 63.395 ;
      RECT  41.67 65.555 41.91 63.395 ;
      RECT  47.1 65.405 47.24 63.43 ;
      RECT  45.74 65.405 45.88 63.43 ;
      RECT  47.1 65.405 47.24 63.43 ;
      RECT  43.79 65.565 44.04 63.395 ;
      RECT  41.67 65.555 41.91 63.395 ;
      RECT  45.74 65.405 45.88 63.43 ;
      RECT  43.79 65.245 44.04 67.415 ;
      RECT  41.67 65.255 41.91 67.415 ;
      RECT  47.1 65.405 47.24 67.38 ;
      RECT  45.74 65.405 45.88 67.38 ;
      RECT  47.1 65.405 47.24 67.38 ;
      RECT  43.79 65.245 44.04 67.415 ;
      RECT  41.67 65.255 41.91 67.415 ;
      RECT  45.74 65.405 45.88 67.38 ;
      RECT  43.79 69.515 44.04 67.345 ;
      RECT  41.67 69.505 41.91 67.345 ;
      RECT  47.1 69.355 47.24 67.38 ;
      RECT  45.74 69.355 45.88 67.38 ;
      RECT  47.1 69.355 47.24 67.38 ;
      RECT  43.79 69.515 44.04 67.345 ;
      RECT  41.67 69.505 41.91 67.345 ;
      RECT  45.74 69.355 45.88 67.38 ;
      RECT  43.79 69.195 44.04 71.365 ;
      RECT  41.67 69.205 41.91 71.365 ;
      RECT  47.1 69.355 47.24 71.33 ;
      RECT  45.74 69.355 45.88 71.33 ;
      RECT  47.1 69.355 47.24 71.33 ;
      RECT  43.79 69.195 44.04 71.365 ;
      RECT  41.67 69.205 41.91 71.365 ;
      RECT  45.74 69.355 45.88 71.33 ;
      RECT  43.79 73.465 44.04 71.295 ;
      RECT  41.67 73.455 41.91 71.295 ;
      RECT  47.1 73.305 47.24 71.33 ;
      RECT  45.74 73.305 45.88 71.33 ;
      RECT  47.1 73.305 47.24 71.33 ;
      RECT  43.79 73.465 44.04 71.295 ;
      RECT  41.67 73.455 41.91 71.295 ;
      RECT  45.74 73.305 45.88 71.33 ;
      RECT  43.79 73.145 44.04 75.315 ;
      RECT  41.67 73.155 41.91 75.315 ;
      RECT  47.1 73.305 47.24 75.28 ;
      RECT  45.74 73.305 45.88 75.28 ;
      RECT  47.1 73.305 47.24 75.28 ;
      RECT  43.79 73.145 44.04 75.315 ;
      RECT  41.67 73.155 41.91 75.315 ;
      RECT  45.74 73.305 45.88 75.28 ;
      RECT  43.79 77.415 44.04 75.245 ;
      RECT  41.67 77.405 41.91 75.245 ;
      RECT  47.1 77.255 47.24 75.28 ;
      RECT  45.74 77.255 45.88 75.28 ;
      RECT  47.1 77.255 47.24 75.28 ;
      RECT  43.79 77.415 44.04 75.245 ;
      RECT  41.67 77.405 41.91 75.245 ;
      RECT  45.74 77.255 45.88 75.28 ;
      RECT  43.79 77.095 44.04 79.265 ;
      RECT  41.67 77.105 41.91 79.265 ;
      RECT  47.1 77.255 47.24 79.23 ;
      RECT  45.74 77.255 45.88 79.23 ;
      RECT  47.1 77.255 47.24 79.23 ;
      RECT  43.79 77.095 44.04 79.265 ;
      RECT  41.67 77.105 41.91 79.265 ;
      RECT  45.74 77.255 45.88 79.23 ;
      RECT  43.79 81.365 44.04 79.195 ;
      RECT  41.67 81.355 41.91 79.195 ;
      RECT  47.1 81.205 47.24 79.23 ;
      RECT  45.74 81.205 45.88 79.23 ;
      RECT  47.1 81.205 47.24 79.23 ;
      RECT  43.79 81.365 44.04 79.195 ;
      RECT  41.67 81.355 41.91 79.195 ;
      RECT  45.74 81.205 45.88 79.23 ;
      RECT  43.79 81.045 44.04 83.215 ;
      RECT  41.67 81.055 41.91 83.215 ;
      RECT  47.1 81.205 47.24 83.18 ;
      RECT  45.74 81.205 45.88 83.18 ;
      RECT  47.1 81.205 47.24 83.18 ;
      RECT  43.79 81.045 44.04 83.215 ;
      RECT  41.67 81.055 41.91 83.215 ;
      RECT  45.74 81.205 45.88 83.18 ;
      RECT  43.79 85.315 44.04 83.145 ;
      RECT  41.67 85.305 41.91 83.145 ;
      RECT  47.1 85.155 47.24 83.18 ;
      RECT  45.74 85.155 45.88 83.18 ;
      RECT  47.1 85.155 47.24 83.18 ;
      RECT  43.79 85.315 44.04 83.145 ;
      RECT  41.67 85.305 41.91 83.145 ;
      RECT  45.74 85.155 45.88 83.18 ;
      RECT  43.79 84.995 44.04 87.165 ;
      RECT  41.67 85.005 41.91 87.165 ;
      RECT  47.1 85.155 47.24 87.13 ;
      RECT  45.74 85.155 45.88 87.13 ;
      RECT  47.1 85.155 47.24 87.13 ;
      RECT  43.79 84.995 44.04 87.165 ;
      RECT  41.67 85.005 41.91 87.165 ;
      RECT  45.74 85.155 45.88 87.13 ;
      RECT  43.79 89.265 44.04 87.095 ;
      RECT  41.67 89.255 41.91 87.095 ;
      RECT  47.1 89.105 47.24 87.13 ;
      RECT  45.74 89.105 45.88 87.13 ;
      RECT  47.1 89.105 47.24 87.13 ;
      RECT  43.79 89.265 44.04 87.095 ;
      RECT  41.67 89.255 41.91 87.095 ;
      RECT  45.74 89.105 45.88 87.13 ;
      RECT  43.79 88.945 44.04 91.115 ;
      RECT  41.67 88.955 41.91 91.115 ;
      RECT  47.1 89.105 47.24 91.08 ;
      RECT  45.74 89.105 45.88 91.08 ;
      RECT  47.1 89.105 47.24 91.08 ;
      RECT  43.79 88.945 44.04 91.115 ;
      RECT  41.67 88.955 41.91 91.115 ;
      RECT  45.74 89.105 45.88 91.08 ;
      RECT  43.79 93.215 44.04 91.045 ;
      RECT  41.67 93.205 41.91 91.045 ;
      RECT  47.1 93.055 47.24 91.08 ;
      RECT  45.74 93.055 45.88 91.08 ;
      RECT  47.1 93.055 47.24 91.08 ;
      RECT  43.79 93.215 44.04 91.045 ;
      RECT  41.67 93.205 41.91 91.045 ;
      RECT  45.74 93.055 45.88 91.08 ;
      RECT  20.54 61.455 20.68 81.205 ;
      RECT  20.94 61.455 21.08 81.205 ;
      RECT  21.34 61.455 21.48 81.205 ;
      RECT  21.74 61.455 21.88 81.205 ;
      RECT  51.4 61.15 51.65 63.32 ;
      RECT  49.28 61.16 49.52 63.32 ;
      RECT  56.03 61.31 56.17 63.285 ;
      RECT  53.54 61.31 53.68 63.285 ;
      RECT  56.03 61.31 56.17 63.285 ;
      RECT  51.4 61.15 51.65 63.32 ;
      RECT  49.28 61.16 49.52 63.32 ;
      RECT  53.54 61.31 53.68 63.285 ;
      RECT  51.4 65.42 51.65 63.25 ;
      RECT  49.28 65.41 49.52 63.25 ;
      RECT  56.03 65.26 56.17 63.285 ;
      RECT  53.54 65.26 53.68 63.285 ;
      RECT  56.03 65.26 56.17 63.285 ;
      RECT  51.4 65.42 51.65 63.25 ;
      RECT  49.28 65.41 49.52 63.25 ;
      RECT  53.54 65.26 53.68 63.285 ;
      RECT  51.4 65.1 51.65 67.27 ;
      RECT  49.28 65.11 49.52 67.27 ;
      RECT  56.03 65.26 56.17 67.235 ;
      RECT  53.54 65.26 53.68 67.235 ;
      RECT  56.03 65.26 56.17 67.235 ;
      RECT  51.4 65.1 51.65 67.27 ;
      RECT  49.28 65.11 49.52 67.27 ;
      RECT  53.54 65.26 53.68 67.235 ;
      RECT  51.4 69.37 51.65 67.2 ;
      RECT  49.28 69.36 49.52 67.2 ;
      RECT  56.03 69.21 56.17 67.235 ;
      RECT  53.54 69.21 53.68 67.235 ;
      RECT  56.03 69.21 56.17 67.235 ;
      RECT  51.4 69.37 51.65 67.2 ;
      RECT  49.28 69.36 49.52 67.2 ;
      RECT  53.54 69.21 53.68 67.235 ;
      RECT  51.4 69.05 51.65 71.22 ;
      RECT  49.28 69.06 49.52 71.22 ;
      RECT  56.03 69.21 56.17 71.185 ;
      RECT  53.54 69.21 53.68 71.185 ;
      RECT  56.03 69.21 56.17 71.185 ;
      RECT  51.4 69.05 51.65 71.22 ;
      RECT  49.28 69.06 49.52 71.22 ;
      RECT  53.54 69.21 53.68 71.185 ;
      RECT  51.4 73.32 51.65 71.15 ;
      RECT  49.28 73.31 49.52 71.15 ;
      RECT  56.03 73.16 56.17 71.185 ;
      RECT  53.54 73.16 53.68 71.185 ;
      RECT  56.03 73.16 56.17 71.185 ;
      RECT  51.4 73.32 51.65 71.15 ;
      RECT  49.28 73.31 49.52 71.15 ;
      RECT  53.54 73.16 53.68 71.185 ;
      RECT  51.4 73.0 51.65 75.17 ;
      RECT  49.28 73.01 49.52 75.17 ;
      RECT  56.03 73.16 56.17 75.135 ;
      RECT  53.54 73.16 53.68 75.135 ;
      RECT  56.03 73.16 56.17 75.135 ;
      RECT  51.4 73.0 51.65 75.17 ;
      RECT  49.28 73.01 49.52 75.17 ;
      RECT  53.54 73.16 53.68 75.135 ;
      RECT  51.4 77.27 51.65 75.1 ;
      RECT  49.28 77.26 49.52 75.1 ;
      RECT  56.03 77.11 56.17 75.135 ;
      RECT  53.54 77.11 53.68 75.135 ;
      RECT  56.03 77.11 56.17 75.135 ;
      RECT  51.4 77.27 51.65 75.1 ;
      RECT  49.28 77.26 49.52 75.1 ;
      RECT  53.54 77.11 53.68 75.135 ;
      RECT  51.4 76.95 51.65 79.12 ;
      RECT  49.28 76.96 49.52 79.12 ;
      RECT  56.03 77.11 56.17 79.085 ;
      RECT  53.54 77.11 53.68 79.085 ;
      RECT  56.03 77.11 56.17 79.085 ;
      RECT  51.4 76.95 51.65 79.12 ;
      RECT  49.28 76.96 49.52 79.12 ;
      RECT  53.54 77.11 53.68 79.085 ;
      RECT  51.4 81.22 51.65 79.05 ;
      RECT  49.28 81.21 49.52 79.05 ;
      RECT  56.03 81.06 56.17 79.085 ;
      RECT  53.54 81.06 53.68 79.085 ;
      RECT  56.03 81.06 56.17 79.085 ;
      RECT  51.4 81.22 51.65 79.05 ;
      RECT  49.28 81.21 49.52 79.05 ;
      RECT  53.54 81.06 53.68 79.085 ;
      RECT  51.4 80.9 51.65 83.07 ;
      RECT  49.28 80.91 49.52 83.07 ;
      RECT  56.03 81.06 56.17 83.035 ;
      RECT  53.54 81.06 53.68 83.035 ;
      RECT  56.03 81.06 56.17 83.035 ;
      RECT  51.4 80.9 51.65 83.07 ;
      RECT  49.28 80.91 49.52 83.07 ;
      RECT  53.54 81.06 53.68 83.035 ;
      RECT  51.4 85.17 51.65 83.0 ;
      RECT  49.28 85.16 49.52 83.0 ;
      RECT  56.03 85.01 56.17 83.035 ;
      RECT  53.54 85.01 53.68 83.035 ;
      RECT  56.03 85.01 56.17 83.035 ;
      RECT  51.4 85.17 51.65 83.0 ;
      RECT  49.28 85.16 49.52 83.0 ;
      RECT  53.54 85.01 53.68 83.035 ;
      RECT  51.4 84.85 51.65 87.02 ;
      RECT  49.28 84.86 49.52 87.02 ;
      RECT  56.03 85.01 56.17 86.985 ;
      RECT  53.54 85.01 53.68 86.985 ;
      RECT  56.03 85.01 56.17 86.985 ;
      RECT  51.4 84.85 51.65 87.02 ;
      RECT  49.28 84.86 49.52 87.02 ;
      RECT  53.54 85.01 53.68 86.985 ;
      RECT  51.4 89.12 51.65 86.95 ;
      RECT  49.28 89.11 49.52 86.95 ;
      RECT  56.03 88.96 56.17 86.985 ;
      RECT  53.54 88.96 53.68 86.985 ;
      RECT  56.03 88.96 56.17 86.985 ;
      RECT  51.4 89.12 51.65 86.95 ;
      RECT  49.28 89.11 49.52 86.95 ;
      RECT  53.54 88.96 53.68 86.985 ;
      RECT  51.4 88.8 51.65 90.97 ;
      RECT  49.28 88.81 49.52 90.97 ;
      RECT  56.03 88.96 56.17 90.935 ;
      RECT  53.54 88.96 53.68 90.935 ;
      RECT  56.03 88.96 56.17 90.935 ;
      RECT  51.4 88.8 51.65 90.97 ;
      RECT  49.28 88.81 49.52 90.97 ;
      RECT  53.54 88.96 53.68 90.935 ;
      RECT  51.4 93.07 51.65 90.9 ;
      RECT  49.28 93.06 49.52 90.9 ;
      RECT  56.03 92.91 56.17 90.935 ;
      RECT  53.54 92.91 53.68 90.935 ;
      RECT  56.03 92.91 56.17 90.935 ;
      RECT  51.4 93.07 51.65 90.9 ;
      RECT  49.28 93.06 49.52 90.9 ;
      RECT  53.54 92.91 53.68 90.935 ;
      RECT  56.03 61.31 56.17 92.91 ;
      RECT  51.455 61.15 51.595 92.91 ;
      RECT  49.33 61.16 49.47 92.91 ;
      RECT  53.54 61.31 53.68 92.91 ;
      RECT  20.54 61.455 20.68 81.205 ;
      RECT  20.94 61.455 21.08 81.205 ;
      RECT  21.34 61.455 21.48 81.205 ;
      RECT  21.74 61.455 21.88 81.205 ;
      RECT  111.0 61.455 110.86 63.43 ;
      RECT  112.36 61.455 112.22 63.43 ;
      RECT  111.0 65.405 110.86 63.43 ;
      RECT  112.36 65.405 112.22 63.43 ;
      RECT  104.44 61.295 104.19 63.465 ;
      RECT  106.56 61.305 106.32 63.465 ;
      RECT  101.13 61.455 100.99 63.43 ;
      RECT  102.49 61.455 102.35 63.43 ;
      RECT  101.13 61.455 100.99 63.43 ;
      RECT  104.44 61.295 104.19 63.465 ;
      RECT  106.56 61.305 106.32 63.465 ;
      RECT  102.49 61.455 102.35 63.43 ;
      RECT  104.44 65.565 104.19 63.395 ;
      RECT  106.56 65.555 106.32 63.395 ;
      RECT  101.13 65.405 100.99 63.43 ;
      RECT  102.49 65.405 102.35 63.43 ;
      RECT  101.13 65.405 100.99 63.43 ;
      RECT  104.44 65.565 104.19 63.395 ;
      RECT  106.56 65.555 106.32 63.395 ;
      RECT  102.49 65.405 102.35 63.43 ;
      RECT  104.44 65.245 104.19 67.415 ;
      RECT  106.56 65.255 106.32 67.415 ;
      RECT  101.13 65.405 100.99 67.38 ;
      RECT  102.49 65.405 102.35 67.38 ;
      RECT  101.13 65.405 100.99 67.38 ;
      RECT  104.44 65.245 104.19 67.415 ;
      RECT  106.56 65.255 106.32 67.415 ;
      RECT  102.49 65.405 102.35 67.38 ;
      RECT  104.44 69.515 104.19 67.345 ;
      RECT  106.56 69.505 106.32 67.345 ;
      RECT  101.13 69.355 100.99 67.38 ;
      RECT  102.49 69.355 102.35 67.38 ;
      RECT  101.13 69.355 100.99 67.38 ;
      RECT  104.44 69.515 104.19 67.345 ;
      RECT  106.56 69.505 106.32 67.345 ;
      RECT  102.49 69.355 102.35 67.38 ;
      RECT  114.54 62.28 114.28 62.6 ;
      RECT  114.14 64.26 113.88 64.58 ;
      RECT  111.0 73.305 110.86 75.28 ;
      RECT  112.36 73.305 112.22 75.28 ;
      RECT  111.0 77.255 110.86 75.28 ;
      RECT  112.36 77.255 112.22 75.28 ;
      RECT  104.44 73.145 104.19 75.315 ;
      RECT  106.56 73.155 106.32 75.315 ;
      RECT  101.13 73.305 100.99 75.28 ;
      RECT  102.49 73.305 102.35 75.28 ;
      RECT  101.13 73.305 100.99 75.28 ;
      RECT  104.44 73.145 104.19 75.315 ;
      RECT  106.56 73.155 106.32 75.315 ;
      RECT  102.49 73.305 102.35 75.28 ;
      RECT  104.44 77.415 104.19 75.245 ;
      RECT  106.56 77.405 106.32 75.245 ;
      RECT  101.13 77.255 100.99 75.28 ;
      RECT  102.49 77.255 102.35 75.28 ;
      RECT  101.13 77.255 100.99 75.28 ;
      RECT  104.44 77.415 104.19 75.245 ;
      RECT  106.56 77.405 106.32 75.245 ;
      RECT  102.49 77.255 102.35 75.28 ;
      RECT  104.44 77.095 104.19 79.265 ;
      RECT  106.56 77.105 106.32 79.265 ;
      RECT  101.13 77.255 100.99 79.23 ;
      RECT  102.49 77.255 102.35 79.23 ;
      RECT  101.13 77.255 100.99 79.23 ;
      RECT  104.44 77.095 104.19 79.265 ;
      RECT  106.56 77.105 106.32 79.265 ;
      RECT  102.49 77.255 102.35 79.23 ;
      RECT  104.44 81.365 104.19 79.195 ;
      RECT  106.56 81.355 106.32 79.195 ;
      RECT  101.13 81.205 100.99 79.23 ;
      RECT  102.49 81.205 102.35 79.23 ;
      RECT  101.13 81.205 100.99 79.23 ;
      RECT  104.44 81.365 104.19 79.195 ;
      RECT  106.56 81.355 106.32 79.195 ;
      RECT  102.49 81.205 102.35 79.23 ;
      RECT  114.54 74.13 114.28 74.45 ;
      RECT  114.14 76.11 113.88 76.43 ;
      RECT  93.37 61.295 93.12 63.465 ;
      RECT  95.49 61.305 95.25 63.465 ;
      RECT  90.06 61.455 89.92 63.43 ;
      RECT  91.42 61.455 91.28 63.43 ;
      RECT  90.06 61.455 89.92 63.43 ;
      RECT  93.37 61.295 93.12 63.465 ;
      RECT  95.49 61.305 95.25 63.465 ;
      RECT  91.42 61.455 91.28 63.43 ;
      RECT  93.37 65.565 93.12 63.395 ;
      RECT  95.49 65.555 95.25 63.395 ;
      RECT  90.06 65.405 89.92 63.43 ;
      RECT  91.42 65.405 91.28 63.43 ;
      RECT  90.06 65.405 89.92 63.43 ;
      RECT  93.37 65.565 93.12 63.395 ;
      RECT  95.49 65.555 95.25 63.395 ;
      RECT  91.42 65.405 91.28 63.43 ;
      RECT  93.37 65.245 93.12 67.415 ;
      RECT  95.49 65.255 95.25 67.415 ;
      RECT  90.06 65.405 89.92 67.38 ;
      RECT  91.42 65.405 91.28 67.38 ;
      RECT  90.06 65.405 89.92 67.38 ;
      RECT  93.37 65.245 93.12 67.415 ;
      RECT  95.49 65.255 95.25 67.415 ;
      RECT  91.42 65.405 91.28 67.38 ;
      RECT  93.37 69.515 93.12 67.345 ;
      RECT  95.49 69.505 95.25 67.345 ;
      RECT  90.06 69.355 89.92 67.38 ;
      RECT  91.42 69.355 91.28 67.38 ;
      RECT  90.06 69.355 89.92 67.38 ;
      RECT  93.37 69.515 93.12 67.345 ;
      RECT  95.49 69.505 95.25 67.345 ;
      RECT  91.42 69.355 91.28 67.38 ;
      RECT  93.37 69.195 93.12 71.365 ;
      RECT  95.49 69.205 95.25 71.365 ;
      RECT  90.06 69.355 89.92 71.33 ;
      RECT  91.42 69.355 91.28 71.33 ;
      RECT  90.06 69.355 89.92 71.33 ;
      RECT  93.37 69.195 93.12 71.365 ;
      RECT  95.49 69.205 95.25 71.365 ;
      RECT  91.42 69.355 91.28 71.33 ;
      RECT  93.37 73.465 93.12 71.295 ;
      RECT  95.49 73.455 95.25 71.295 ;
      RECT  90.06 73.305 89.92 71.33 ;
      RECT  91.42 73.305 91.28 71.33 ;
      RECT  90.06 73.305 89.92 71.33 ;
      RECT  93.37 73.465 93.12 71.295 ;
      RECT  95.49 73.455 95.25 71.295 ;
      RECT  91.42 73.305 91.28 71.33 ;
      RECT  93.37 73.145 93.12 75.315 ;
      RECT  95.49 73.155 95.25 75.315 ;
      RECT  90.06 73.305 89.92 75.28 ;
      RECT  91.42 73.305 91.28 75.28 ;
      RECT  90.06 73.305 89.92 75.28 ;
      RECT  93.37 73.145 93.12 75.315 ;
      RECT  95.49 73.155 95.25 75.315 ;
      RECT  91.42 73.305 91.28 75.28 ;
      RECT  93.37 77.415 93.12 75.245 ;
      RECT  95.49 77.405 95.25 75.245 ;
      RECT  90.06 77.255 89.92 75.28 ;
      RECT  91.42 77.255 91.28 75.28 ;
      RECT  90.06 77.255 89.92 75.28 ;
      RECT  93.37 77.415 93.12 75.245 ;
      RECT  95.49 77.405 95.25 75.245 ;
      RECT  91.42 77.255 91.28 75.28 ;
      RECT  93.37 77.095 93.12 79.265 ;
      RECT  95.49 77.105 95.25 79.265 ;
      RECT  90.06 77.255 89.92 79.23 ;
      RECT  91.42 77.255 91.28 79.23 ;
      RECT  90.06 77.255 89.92 79.23 ;
      RECT  93.37 77.095 93.12 79.265 ;
      RECT  95.49 77.105 95.25 79.265 ;
      RECT  91.42 77.255 91.28 79.23 ;
      RECT  93.37 81.365 93.12 79.195 ;
      RECT  95.49 81.355 95.25 79.195 ;
      RECT  90.06 81.205 89.92 79.23 ;
      RECT  91.42 81.205 91.28 79.23 ;
      RECT  90.06 81.205 89.92 79.23 ;
      RECT  93.37 81.365 93.12 79.195 ;
      RECT  95.49 81.355 95.25 79.195 ;
      RECT  91.42 81.205 91.28 79.23 ;
      RECT  93.37 81.045 93.12 83.215 ;
      RECT  95.49 81.055 95.25 83.215 ;
      RECT  90.06 81.205 89.92 83.18 ;
      RECT  91.42 81.205 91.28 83.18 ;
      RECT  90.06 81.205 89.92 83.18 ;
      RECT  93.37 81.045 93.12 83.215 ;
      RECT  95.49 81.055 95.25 83.215 ;
      RECT  91.42 81.205 91.28 83.18 ;
      RECT  93.37 85.315 93.12 83.145 ;
      RECT  95.49 85.305 95.25 83.145 ;
      RECT  90.06 85.155 89.92 83.18 ;
      RECT  91.42 85.155 91.28 83.18 ;
      RECT  90.06 85.155 89.92 83.18 ;
      RECT  93.37 85.315 93.12 83.145 ;
      RECT  95.49 85.305 95.25 83.145 ;
      RECT  91.42 85.155 91.28 83.18 ;
      RECT  93.37 84.995 93.12 87.165 ;
      RECT  95.49 85.005 95.25 87.165 ;
      RECT  90.06 85.155 89.92 87.13 ;
      RECT  91.42 85.155 91.28 87.13 ;
      RECT  90.06 85.155 89.92 87.13 ;
      RECT  93.37 84.995 93.12 87.165 ;
      RECT  95.49 85.005 95.25 87.165 ;
      RECT  91.42 85.155 91.28 87.13 ;
      RECT  93.37 89.265 93.12 87.095 ;
      RECT  95.49 89.255 95.25 87.095 ;
      RECT  90.06 89.105 89.92 87.13 ;
      RECT  91.42 89.105 91.28 87.13 ;
      RECT  90.06 89.105 89.92 87.13 ;
      RECT  93.37 89.265 93.12 87.095 ;
      RECT  95.49 89.255 95.25 87.095 ;
      RECT  91.42 89.105 91.28 87.13 ;
      RECT  93.37 88.945 93.12 91.115 ;
      RECT  95.49 88.955 95.25 91.115 ;
      RECT  90.06 89.105 89.92 91.08 ;
      RECT  91.42 89.105 91.28 91.08 ;
      RECT  90.06 89.105 89.92 91.08 ;
      RECT  93.37 88.945 93.12 91.115 ;
      RECT  95.49 88.955 95.25 91.115 ;
      RECT  91.42 89.105 91.28 91.08 ;
      RECT  93.37 93.215 93.12 91.045 ;
      RECT  95.49 93.205 95.25 91.045 ;
      RECT  90.06 93.055 89.92 91.08 ;
      RECT  91.42 93.055 91.28 91.08 ;
      RECT  90.06 93.055 89.92 91.08 ;
      RECT  93.37 93.215 93.12 91.045 ;
      RECT  95.49 93.205 95.25 91.045 ;
      RECT  91.42 93.055 91.28 91.08 ;
      RECT  116.62 61.455 116.48 81.205 ;
      RECT  116.22 61.455 116.08 81.205 ;
      RECT  115.82 61.455 115.68 81.205 ;
      RECT  115.42 61.455 115.28 81.205 ;
      RECT  85.76 61.15 85.51 63.32 ;
      RECT  87.88 61.16 87.64 63.32 ;
      RECT  81.13 61.31 80.99 63.285 ;
      RECT  83.62 61.31 83.48 63.285 ;
      RECT  81.13 61.31 80.99 63.285 ;
      RECT  85.76 61.15 85.51 63.32 ;
      RECT  87.88 61.16 87.64 63.32 ;
      RECT  83.62 61.31 83.48 63.285 ;
      RECT  85.76 65.42 85.51 63.25 ;
      RECT  87.88 65.41 87.64 63.25 ;
      RECT  81.13 65.26 80.99 63.285 ;
      RECT  83.62 65.26 83.48 63.285 ;
      RECT  81.13 65.26 80.99 63.285 ;
      RECT  85.76 65.42 85.51 63.25 ;
      RECT  87.88 65.41 87.64 63.25 ;
      RECT  83.62 65.26 83.48 63.285 ;
      RECT  85.76 65.1 85.51 67.27 ;
      RECT  87.88 65.11 87.64 67.27 ;
      RECT  81.13 65.26 80.99 67.235 ;
      RECT  83.62 65.26 83.48 67.235 ;
      RECT  81.13 65.26 80.99 67.235 ;
      RECT  85.76 65.1 85.51 67.27 ;
      RECT  87.88 65.11 87.64 67.27 ;
      RECT  83.62 65.26 83.48 67.235 ;
      RECT  85.76 69.37 85.51 67.2 ;
      RECT  87.88 69.36 87.64 67.2 ;
      RECT  81.13 69.21 80.99 67.235 ;
      RECT  83.62 69.21 83.48 67.235 ;
      RECT  81.13 69.21 80.99 67.235 ;
      RECT  85.76 69.37 85.51 67.2 ;
      RECT  87.88 69.36 87.64 67.2 ;
      RECT  83.62 69.21 83.48 67.235 ;
      RECT  85.76 69.05 85.51 71.22 ;
      RECT  87.88 69.06 87.64 71.22 ;
      RECT  81.13 69.21 80.99 71.185 ;
      RECT  83.62 69.21 83.48 71.185 ;
      RECT  81.13 69.21 80.99 71.185 ;
      RECT  85.76 69.05 85.51 71.22 ;
      RECT  87.88 69.06 87.64 71.22 ;
      RECT  83.62 69.21 83.48 71.185 ;
      RECT  85.76 73.32 85.51 71.15 ;
      RECT  87.88 73.31 87.64 71.15 ;
      RECT  81.13 73.16 80.99 71.185 ;
      RECT  83.62 73.16 83.48 71.185 ;
      RECT  81.13 73.16 80.99 71.185 ;
      RECT  85.76 73.32 85.51 71.15 ;
      RECT  87.88 73.31 87.64 71.15 ;
      RECT  83.62 73.16 83.48 71.185 ;
      RECT  85.76 73.0 85.51 75.17 ;
      RECT  87.88 73.01 87.64 75.17 ;
      RECT  81.13 73.16 80.99 75.135 ;
      RECT  83.62 73.16 83.48 75.135 ;
      RECT  81.13 73.16 80.99 75.135 ;
      RECT  85.76 73.0 85.51 75.17 ;
      RECT  87.88 73.01 87.64 75.17 ;
      RECT  83.62 73.16 83.48 75.135 ;
      RECT  85.76 77.27 85.51 75.1 ;
      RECT  87.88 77.26 87.64 75.1 ;
      RECT  81.13 77.11 80.99 75.135 ;
      RECT  83.62 77.11 83.48 75.135 ;
      RECT  81.13 77.11 80.99 75.135 ;
      RECT  85.76 77.27 85.51 75.1 ;
      RECT  87.88 77.26 87.64 75.1 ;
      RECT  83.62 77.11 83.48 75.135 ;
      RECT  85.76 76.95 85.51 79.12 ;
      RECT  87.88 76.96 87.64 79.12 ;
      RECT  81.13 77.11 80.99 79.085 ;
      RECT  83.62 77.11 83.48 79.085 ;
      RECT  81.13 77.11 80.99 79.085 ;
      RECT  85.76 76.95 85.51 79.12 ;
      RECT  87.88 76.96 87.64 79.12 ;
      RECT  83.62 77.11 83.48 79.085 ;
      RECT  85.76 81.22 85.51 79.05 ;
      RECT  87.88 81.21 87.64 79.05 ;
      RECT  81.13 81.06 80.99 79.085 ;
      RECT  83.62 81.06 83.48 79.085 ;
      RECT  81.13 81.06 80.99 79.085 ;
      RECT  85.76 81.22 85.51 79.05 ;
      RECT  87.88 81.21 87.64 79.05 ;
      RECT  83.62 81.06 83.48 79.085 ;
      RECT  85.76 80.9 85.51 83.07 ;
      RECT  87.88 80.91 87.64 83.07 ;
      RECT  81.13 81.06 80.99 83.035 ;
      RECT  83.62 81.06 83.48 83.035 ;
      RECT  81.13 81.06 80.99 83.035 ;
      RECT  85.76 80.9 85.51 83.07 ;
      RECT  87.88 80.91 87.64 83.07 ;
      RECT  83.62 81.06 83.48 83.035 ;
      RECT  85.76 85.17 85.51 83.0 ;
      RECT  87.88 85.16 87.64 83.0 ;
      RECT  81.13 85.01 80.99 83.035 ;
      RECT  83.62 85.01 83.48 83.035 ;
      RECT  81.13 85.01 80.99 83.035 ;
      RECT  85.76 85.17 85.51 83.0 ;
      RECT  87.88 85.16 87.64 83.0 ;
      RECT  83.62 85.01 83.48 83.035 ;
      RECT  85.76 84.85 85.51 87.02 ;
      RECT  87.88 84.86 87.64 87.02 ;
      RECT  81.13 85.01 80.99 86.985 ;
      RECT  83.62 85.01 83.48 86.985 ;
      RECT  81.13 85.01 80.99 86.985 ;
      RECT  85.76 84.85 85.51 87.02 ;
      RECT  87.88 84.86 87.64 87.02 ;
      RECT  83.62 85.01 83.48 86.985 ;
      RECT  85.76 89.12 85.51 86.95 ;
      RECT  87.88 89.11 87.64 86.95 ;
      RECT  81.13 88.96 80.99 86.985 ;
      RECT  83.62 88.96 83.48 86.985 ;
      RECT  81.13 88.96 80.99 86.985 ;
      RECT  85.76 89.12 85.51 86.95 ;
      RECT  87.88 89.11 87.64 86.95 ;
      RECT  83.62 88.96 83.48 86.985 ;
      RECT  85.76 88.8 85.51 90.97 ;
      RECT  87.88 88.81 87.64 90.97 ;
      RECT  81.13 88.96 80.99 90.935 ;
      RECT  83.62 88.96 83.48 90.935 ;
      RECT  81.13 88.96 80.99 90.935 ;
      RECT  85.76 88.8 85.51 90.97 ;
      RECT  87.88 88.81 87.64 90.97 ;
      RECT  83.62 88.96 83.48 90.935 ;
      RECT  85.76 93.07 85.51 90.9 ;
      RECT  87.88 93.06 87.64 90.9 ;
      RECT  81.13 92.91 80.99 90.935 ;
      RECT  83.62 92.91 83.48 90.935 ;
      RECT  81.13 92.91 80.99 90.935 ;
      RECT  85.76 93.07 85.51 90.9 ;
      RECT  87.88 93.06 87.64 90.9 ;
      RECT  83.62 92.91 83.48 90.935 ;
      RECT  81.13 61.31 80.99 92.91 ;
      RECT  85.705 61.15 85.565 92.91 ;
      RECT  87.83 61.16 87.69 92.91 ;
      RECT  83.62 61.31 83.48 92.91 ;
      RECT  116.62 61.455 116.48 81.205 ;
      RECT  116.22 61.455 116.08 81.205 ;
      RECT  115.82 61.455 115.68 81.205 ;
      RECT  115.42 61.455 115.28 81.205 ;
      RECT  65.98 39.79 66.21 41.06 ;
      RECT  70.33 39.79 70.56 41.06 ;
      RECT  65.98 113.16 66.21 114.43 ;
      RECT  70.33 113.16 70.56 114.43 ;
      RECT  66.735 28.495 67.035 28.775 ;
      RECT  69.505 28.495 69.805 28.775 ;
      RECT  20.54 61.455 20.68 81.205 ;
      RECT  20.94 61.455 21.08 81.205 ;
      RECT  21.34 61.455 21.48 81.205 ;
      RECT  21.74 61.455 21.88 81.205 ;
      RECT  116.48 61.455 116.62 81.205 ;
      RECT  116.08 61.455 116.22 81.205 ;
      RECT  115.68 61.455 115.82 81.205 ;
      RECT  115.28 61.455 115.42 81.205 ;
      RECT  0.505 3.105 0.795 3.135 ;
      RECT  0.18 1.335 0.35 2.305 ;
      RECT  4.48 1.105 4.77 1.335 ;
      RECT  3.175 1.105 3.465 1.335 ;
      RECT  1.895 2.18 2.065 3.46 ;
      RECT  0.12 3.905 0.41 4.135 ;
      RECT  0.12 2.305 0.41 2.535 ;
      RECT  1.845 3.735 2.115 3.78 ;
      RECT  1.845 2.135 2.115 2.18 ;
      RECT  4.48 3.905 4.77 4.135 ;
      RECT  4.48 2.305 4.77 2.535 ;
      RECT  1.425 3.905 1.715 4.135 ;
      RECT  0.18 2.535 0.35 3.905 ;
      RECT  0.12 1.105 0.41 1.335 ;
      RECT  0.505 3.305 0.795 3.335 ;
      RECT  4.54 2.535 4.71 3.905 ;
      RECT  5.41 3.045 5.74 3.305 ;
      RECT  3.235 1.335 3.405 3.905 ;
      RECT  0.505 3.135 1.655 3.305 ;
      RECT  0.685 2.69 1.015 2.95 ;
      RECT  5.43 3.905 5.72 4.135 ;
      RECT  5.02 2.29 5.35 2.55 ;
      RECT  1.485 3.305 1.655 3.905 ;
      RECT  1.845 3.46 2.115 3.505 ;
      RECT  1.845 1.86 2.115 1.905 ;
      RECT  3.175 3.905 3.465 4.135 ;
      RECT  1.835 3.505 2.125 3.735 ;
      RECT  1.835 1.905 2.125 2.135 ;
      RECT  1.425 1.105 1.715 1.335 ;
      RECT  5.49 3.305 5.66 3.905 ;
      RECT  4.54 1.335 4.71 2.305 ;
      RECT  5.49 1.335 5.66 3.045 ;
      RECT  5.43 1.105 5.72 1.335 ;
      RECT  1.485 1.335 1.655 3.135 ;
      RECT  0.505 11.035 0.795 11.005 ;
      RECT  0.18 12.805 0.35 11.835 ;
      RECT  4.48 13.035 4.77 12.805 ;
      RECT  3.175 13.035 3.465 12.805 ;
      RECT  1.895 11.96 2.065 10.68 ;
      RECT  0.12 10.235 0.41 10.005 ;
      RECT  0.12 11.835 0.41 11.605 ;
      RECT  1.845 10.405 2.115 10.36 ;
      RECT  1.845 12.005 2.115 11.96 ;
      RECT  4.48 10.235 4.77 10.005 ;
      RECT  4.48 11.835 4.77 11.605 ;
      RECT  1.425 10.235 1.715 10.005 ;
      RECT  0.18 11.605 0.35 10.235 ;
      RECT  0.12 13.035 0.41 12.805 ;
      RECT  0.505 10.835 0.795 10.805 ;
      RECT  4.54 11.605 4.71 10.235 ;
      RECT  5.41 11.095 5.74 10.835 ;
      RECT  3.235 12.805 3.405 10.235 ;
      RECT  0.505 11.005 1.655 10.835 ;
      RECT  0.685 11.45 1.015 11.19 ;
      RECT  5.43 10.235 5.72 10.005 ;
      RECT  5.02 11.85 5.35 11.59 ;
      RECT  1.485 10.835 1.655 10.235 ;
      RECT  1.845 10.68 2.115 10.635 ;
      RECT  1.845 12.28 2.115 12.235 ;
      RECT  3.175 10.235 3.465 10.005 ;
      RECT  1.835 10.635 2.125 10.405 ;
      RECT  1.835 12.235 2.125 12.005 ;
      RECT  1.425 13.035 1.715 12.805 ;
      RECT  5.49 10.835 5.66 10.235 ;
      RECT  4.54 12.805 4.71 11.835 ;
      RECT  5.49 12.805 5.66 11.095 ;
      RECT  5.43 13.035 5.72 12.805 ;
      RECT  1.485 12.805 1.655 11.005 ;
      RECT  136.655 136.975 136.365 136.945 ;
      RECT  136.98 138.745 136.81 137.775 ;
      RECT  132.68 138.975 132.39 138.745 ;
      RECT  133.985 138.975 133.695 138.745 ;
      RECT  135.265 137.9 135.095 136.62 ;
      RECT  137.04 136.175 136.75 135.945 ;
      RECT  137.04 137.775 136.75 137.545 ;
      RECT  135.315 136.345 135.045 136.3 ;
      RECT  135.315 137.945 135.045 137.9 ;
      RECT  132.68 136.175 132.39 135.945 ;
      RECT  132.68 137.775 132.39 137.545 ;
      RECT  135.735 136.175 135.445 135.945 ;
      RECT  136.98 137.545 136.81 136.175 ;
      RECT  137.04 138.975 136.75 138.745 ;
      RECT  136.655 136.775 136.365 136.745 ;
      RECT  132.62 137.545 132.45 136.175 ;
      RECT  131.75 137.035 131.42 136.775 ;
      RECT  133.925 138.745 133.755 136.175 ;
      RECT  136.655 136.945 135.505 136.775 ;
      RECT  136.475 137.39 136.145 137.13 ;
      RECT  131.73 136.175 131.44 135.945 ;
      RECT  132.14 137.79 131.81 137.53 ;
      RECT  135.675 136.775 135.505 136.175 ;
      RECT  135.315 136.62 135.045 136.575 ;
      RECT  135.315 138.22 135.045 138.175 ;
      RECT  133.985 136.175 133.695 135.945 ;
      RECT  135.325 136.575 135.035 136.345 ;
      RECT  135.325 138.175 135.035 137.945 ;
      RECT  135.735 138.975 135.445 138.745 ;
      RECT  131.67 136.775 131.5 136.175 ;
      RECT  132.62 138.745 132.45 137.775 ;
      RECT  131.67 138.745 131.5 137.035 ;
      RECT  131.73 138.975 131.44 138.745 ;
      RECT  135.675 138.745 135.505 136.945 ;
      RECT  14.275 111.665 14.565 111.695 ;
      RECT  13.95 109.895 14.12 110.865 ;
      RECT  18.25 109.665 18.54 109.895 ;
      RECT  16.945 109.665 17.235 109.895 ;
      RECT  15.665 110.74 15.835 112.02 ;
      RECT  13.89 112.465 14.18 112.695 ;
      RECT  13.89 110.865 14.18 111.095 ;
      RECT  15.615 112.295 15.885 112.34 ;
      RECT  15.615 110.695 15.885 110.74 ;
      RECT  18.25 112.465 18.54 112.695 ;
      RECT  18.25 110.865 18.54 111.095 ;
      RECT  15.195 112.465 15.485 112.695 ;
      RECT  13.95 111.095 14.12 112.465 ;
      RECT  13.89 109.665 14.18 109.895 ;
      RECT  14.275 111.865 14.565 111.895 ;
      RECT  18.31 111.095 18.48 112.465 ;
      RECT  19.18 111.605 19.51 111.865 ;
      RECT  17.005 109.895 17.175 112.465 ;
      RECT  14.275 111.695 15.425 111.865 ;
      RECT  14.455 111.25 14.785 111.51 ;
      RECT  19.2 112.465 19.49 112.695 ;
      RECT  18.79 110.85 19.12 111.11 ;
      RECT  15.255 111.865 15.425 112.465 ;
      RECT  15.615 112.02 15.885 112.065 ;
      RECT  15.615 110.42 15.885 110.465 ;
      RECT  16.945 112.465 17.235 112.695 ;
      RECT  15.605 112.065 15.895 112.295 ;
      RECT  15.605 110.465 15.895 110.695 ;
      RECT  15.195 109.665 15.485 109.895 ;
      RECT  19.26 111.865 19.43 112.465 ;
      RECT  18.31 109.895 18.48 110.865 ;
      RECT  19.26 109.895 19.43 111.605 ;
      RECT  19.2 109.665 19.49 109.895 ;
      RECT  15.255 109.895 15.425 111.695 ;
      RECT  14.275 119.595 14.565 119.565 ;
      RECT  13.95 121.365 14.12 120.395 ;
      RECT  18.25 121.595 18.54 121.365 ;
      RECT  16.945 121.595 17.235 121.365 ;
      RECT  15.665 120.52 15.835 119.24 ;
      RECT  13.89 118.795 14.18 118.565 ;
      RECT  13.89 120.395 14.18 120.165 ;
      RECT  15.615 118.965 15.885 118.92 ;
      RECT  15.615 120.565 15.885 120.52 ;
      RECT  18.25 118.795 18.54 118.565 ;
      RECT  18.25 120.395 18.54 120.165 ;
      RECT  15.195 118.795 15.485 118.565 ;
      RECT  13.95 120.165 14.12 118.795 ;
      RECT  13.89 121.595 14.18 121.365 ;
      RECT  14.275 119.395 14.565 119.365 ;
      RECT  18.31 120.165 18.48 118.795 ;
      RECT  19.18 119.655 19.51 119.395 ;
      RECT  17.005 121.365 17.175 118.795 ;
      RECT  14.275 119.565 15.425 119.395 ;
      RECT  14.455 120.01 14.785 119.75 ;
      RECT  19.2 118.795 19.49 118.565 ;
      RECT  18.79 120.41 19.12 120.15 ;
      RECT  15.255 119.395 15.425 118.795 ;
      RECT  15.615 119.24 15.885 119.195 ;
      RECT  15.615 120.84 15.885 120.795 ;
      RECT  16.945 118.795 17.235 118.565 ;
      RECT  15.605 119.195 15.895 118.965 ;
      RECT  15.605 120.795 15.895 120.565 ;
      RECT  15.195 121.595 15.485 121.365 ;
      RECT  19.26 119.395 19.43 118.795 ;
      RECT  18.31 121.365 18.48 120.395 ;
      RECT  19.26 121.365 19.43 119.655 ;
      RECT  19.2 121.595 19.49 121.365 ;
      RECT  15.255 121.365 15.425 119.565 ;
      RECT  14.275 125.805 14.565 125.835 ;
      RECT  13.95 124.035 14.12 125.005 ;
      RECT  18.25 123.805 18.54 124.035 ;
      RECT  16.945 123.805 17.235 124.035 ;
      RECT  15.665 124.88 15.835 126.16 ;
      RECT  13.89 126.605 14.18 126.835 ;
      RECT  13.89 125.005 14.18 125.235 ;
      RECT  15.615 126.435 15.885 126.48 ;
      RECT  15.615 124.835 15.885 124.88 ;
      RECT  18.25 126.605 18.54 126.835 ;
      RECT  18.25 125.005 18.54 125.235 ;
      RECT  15.195 126.605 15.485 126.835 ;
      RECT  13.95 125.235 14.12 126.605 ;
      RECT  13.89 123.805 14.18 124.035 ;
      RECT  14.275 126.005 14.565 126.035 ;
      RECT  18.31 125.235 18.48 126.605 ;
      RECT  19.18 125.745 19.51 126.005 ;
      RECT  17.005 124.035 17.175 126.605 ;
      RECT  14.275 125.835 15.425 126.005 ;
      RECT  14.455 125.39 14.785 125.65 ;
      RECT  19.2 126.605 19.49 126.835 ;
      RECT  18.79 124.99 19.12 125.25 ;
      RECT  15.255 126.005 15.425 126.605 ;
      RECT  15.615 126.16 15.885 126.205 ;
      RECT  15.615 124.56 15.885 124.605 ;
      RECT  16.945 126.605 17.235 126.835 ;
      RECT  15.605 126.205 15.895 126.435 ;
      RECT  15.605 124.605 15.895 124.835 ;
      RECT  15.195 123.805 15.485 124.035 ;
      RECT  19.26 126.005 19.43 126.605 ;
      RECT  18.31 124.035 18.48 125.005 ;
      RECT  19.26 124.035 19.43 125.745 ;
      RECT  19.2 123.805 19.49 124.035 ;
      RECT  15.255 124.035 15.425 125.835 ;
      RECT  14.275 133.735 14.565 133.705 ;
      RECT  13.95 135.505 14.12 134.535 ;
      RECT  18.25 135.735 18.54 135.505 ;
      RECT  16.945 135.735 17.235 135.505 ;
      RECT  15.665 134.66 15.835 133.38 ;
      RECT  13.89 132.935 14.18 132.705 ;
      RECT  13.89 134.535 14.18 134.305 ;
      RECT  15.615 133.105 15.885 133.06 ;
      RECT  15.615 134.705 15.885 134.66 ;
      RECT  18.25 132.935 18.54 132.705 ;
      RECT  18.25 134.535 18.54 134.305 ;
      RECT  15.195 132.935 15.485 132.705 ;
      RECT  13.95 134.305 14.12 132.935 ;
      RECT  13.89 135.735 14.18 135.505 ;
      RECT  14.275 133.535 14.565 133.505 ;
      RECT  18.31 134.305 18.48 132.935 ;
      RECT  19.18 133.795 19.51 133.535 ;
      RECT  17.005 135.505 17.175 132.935 ;
      RECT  14.275 133.705 15.425 133.535 ;
      RECT  14.455 134.15 14.785 133.89 ;
      RECT  19.2 132.935 19.49 132.705 ;
      RECT  18.79 134.55 19.12 134.29 ;
      RECT  15.255 133.535 15.425 132.935 ;
      RECT  15.615 133.38 15.885 133.335 ;
      RECT  15.615 134.98 15.885 134.935 ;
      RECT  16.945 132.935 17.235 132.705 ;
      RECT  15.605 133.335 15.895 133.105 ;
      RECT  15.605 134.935 15.895 134.705 ;
      RECT  15.195 135.735 15.485 135.505 ;
      RECT  19.26 133.535 19.43 132.935 ;
      RECT  18.31 135.505 18.48 134.535 ;
      RECT  19.26 135.505 19.43 133.795 ;
      RECT  19.2 135.735 19.49 135.505 ;
      RECT  15.255 135.505 15.425 133.705 ;
      RECT  123.305 42.555 123.015 42.525 ;
      RECT  123.63 44.325 123.46 43.355 ;
      RECT  119.33 44.555 119.04 44.325 ;
      RECT  120.635 44.555 120.345 44.325 ;
      RECT  121.915 43.48 121.745 42.2 ;
      RECT  123.69 41.755 123.4 41.525 ;
      RECT  123.69 43.355 123.4 43.125 ;
      RECT  121.965 41.925 121.695 41.88 ;
      RECT  121.965 43.525 121.695 43.48 ;
      RECT  119.33 41.755 119.04 41.525 ;
      RECT  119.33 43.355 119.04 43.125 ;
      RECT  122.385 41.755 122.095 41.525 ;
      RECT  123.63 43.125 123.46 41.755 ;
      RECT  123.69 44.555 123.4 44.325 ;
      RECT  123.305 42.355 123.015 42.325 ;
      RECT  119.27 43.125 119.1 41.755 ;
      RECT  118.4 42.615 118.07 42.355 ;
      RECT  120.575 44.325 120.405 41.755 ;
      RECT  123.305 42.525 122.155 42.355 ;
      RECT  123.125 42.97 122.795 42.71 ;
      RECT  118.38 41.755 118.09 41.525 ;
      RECT  118.79 43.37 118.46 43.11 ;
      RECT  122.325 42.355 122.155 41.755 ;
      RECT  121.965 42.2 121.695 42.155 ;
      RECT  121.965 43.8 121.695 43.755 ;
      RECT  120.635 41.755 120.345 41.525 ;
      RECT  121.975 42.155 121.685 41.925 ;
      RECT  121.975 43.755 121.685 43.525 ;
      RECT  122.385 44.555 122.095 44.325 ;
      RECT  118.32 42.355 118.15 41.755 ;
      RECT  119.27 44.325 119.1 43.355 ;
      RECT  118.32 44.325 118.15 42.615 ;
      RECT  118.38 44.555 118.09 44.325 ;
      RECT  122.325 44.325 122.155 42.525 ;
      RECT  123.305 34.625 123.015 34.655 ;
      RECT  123.63 32.855 123.46 33.825 ;
      RECT  119.33 32.625 119.04 32.855 ;
      RECT  120.635 32.625 120.345 32.855 ;
      RECT  121.915 33.7 121.745 34.98 ;
      RECT  123.69 35.425 123.4 35.655 ;
      RECT  123.69 33.825 123.4 34.055 ;
      RECT  121.965 35.255 121.695 35.3 ;
      RECT  121.965 33.655 121.695 33.7 ;
      RECT  119.33 35.425 119.04 35.655 ;
      RECT  119.33 33.825 119.04 34.055 ;
      RECT  122.385 35.425 122.095 35.655 ;
      RECT  123.63 34.055 123.46 35.425 ;
      RECT  123.69 32.625 123.4 32.855 ;
      RECT  123.305 34.825 123.015 34.855 ;
      RECT  119.27 34.055 119.1 35.425 ;
      RECT  118.4 34.565 118.07 34.825 ;
      RECT  120.575 32.855 120.405 35.425 ;
      RECT  123.305 34.655 122.155 34.825 ;
      RECT  123.125 34.21 122.795 34.47 ;
      RECT  118.38 35.425 118.09 35.655 ;
      RECT  118.79 33.81 118.46 34.07 ;
      RECT  122.325 34.825 122.155 35.425 ;
      RECT  121.965 34.98 121.695 35.025 ;
      RECT  121.965 33.38 121.695 33.425 ;
      RECT  120.635 35.425 120.345 35.655 ;
      RECT  121.975 35.025 121.685 35.255 ;
      RECT  121.975 33.425 121.685 33.655 ;
      RECT  122.385 32.625 122.095 32.855 ;
      RECT  118.32 34.825 118.15 35.425 ;
      RECT  119.27 32.855 119.1 33.825 ;
      RECT  118.32 32.855 118.15 34.565 ;
      RECT  118.38 32.625 118.09 32.855 ;
      RECT  122.325 32.855 122.155 34.655 ;
      RECT  123.305 28.415 123.015 28.385 ;
      RECT  123.63 30.185 123.46 29.215 ;
      RECT  119.33 30.415 119.04 30.185 ;
      RECT  120.635 30.415 120.345 30.185 ;
      RECT  121.915 29.34 121.745 28.06 ;
      RECT  123.69 27.615 123.4 27.385 ;
      RECT  123.69 29.215 123.4 28.985 ;
      RECT  121.965 27.785 121.695 27.74 ;
      RECT  121.965 29.385 121.695 29.34 ;
      RECT  119.33 27.615 119.04 27.385 ;
      RECT  119.33 29.215 119.04 28.985 ;
      RECT  122.385 27.615 122.095 27.385 ;
      RECT  123.63 28.985 123.46 27.615 ;
      RECT  123.69 30.415 123.4 30.185 ;
      RECT  123.305 28.215 123.015 28.185 ;
      RECT  119.27 28.985 119.1 27.615 ;
      RECT  118.4 28.475 118.07 28.215 ;
      RECT  120.575 30.185 120.405 27.615 ;
      RECT  123.305 28.385 122.155 28.215 ;
      RECT  123.125 28.83 122.795 28.57 ;
      RECT  118.38 27.615 118.09 27.385 ;
      RECT  118.79 29.23 118.46 28.97 ;
      RECT  122.325 28.215 122.155 27.615 ;
      RECT  121.965 28.06 121.695 28.015 ;
      RECT  121.965 29.66 121.695 29.615 ;
      RECT  120.635 27.615 120.345 27.385 ;
      RECT  121.975 28.015 121.685 27.785 ;
      RECT  121.975 29.615 121.685 29.385 ;
      RECT  122.385 30.415 122.095 30.185 ;
      RECT  118.32 28.215 118.15 27.615 ;
      RECT  119.27 30.185 119.1 29.215 ;
      RECT  118.32 30.185 118.15 28.475 ;
      RECT  118.38 30.415 118.09 30.185 ;
      RECT  122.325 30.185 122.155 28.385 ;
      RECT  123.305 20.485 123.015 20.515 ;
      RECT  123.63 18.715 123.46 19.685 ;
      RECT  119.33 18.485 119.04 18.715 ;
      RECT  120.635 18.485 120.345 18.715 ;
      RECT  121.915 19.56 121.745 20.84 ;
      RECT  123.69 21.285 123.4 21.515 ;
      RECT  123.69 19.685 123.4 19.915 ;
      RECT  121.965 21.115 121.695 21.16 ;
      RECT  121.965 19.515 121.695 19.56 ;
      RECT  119.33 21.285 119.04 21.515 ;
      RECT  119.33 19.685 119.04 19.915 ;
      RECT  122.385 21.285 122.095 21.515 ;
      RECT  123.63 19.915 123.46 21.285 ;
      RECT  123.69 18.485 123.4 18.715 ;
      RECT  123.305 20.685 123.015 20.715 ;
      RECT  119.27 19.915 119.1 21.285 ;
      RECT  118.4 20.425 118.07 20.685 ;
      RECT  120.575 18.715 120.405 21.285 ;
      RECT  123.305 20.515 122.155 20.685 ;
      RECT  123.125 20.07 122.795 20.33 ;
      RECT  118.38 21.285 118.09 21.515 ;
      RECT  118.79 19.67 118.46 19.93 ;
      RECT  122.325 20.685 122.155 21.285 ;
      RECT  121.965 20.84 121.695 20.885 ;
      RECT  121.965 19.24 121.695 19.285 ;
      RECT  120.635 21.285 120.345 21.515 ;
      RECT  121.975 20.885 121.685 21.115 ;
      RECT  121.975 19.285 121.685 19.515 ;
      RECT  122.385 18.485 122.095 18.715 ;
      RECT  118.32 20.685 118.15 21.285 ;
      RECT  119.27 18.715 119.1 19.685 ;
      RECT  118.32 18.715 118.15 20.425 ;
      RECT  118.38 18.485 118.09 18.715 ;
      RECT  122.325 18.715 122.155 20.515 ;
      RECT  25.955 3.105 26.245 3.135 ;
      RECT  25.63 1.335 25.8 2.305 ;
      RECT  29.93 1.105 30.22 1.335 ;
      RECT  28.625 1.105 28.915 1.335 ;
      RECT  27.345 2.18 27.515 3.46 ;
      RECT  25.57 3.905 25.86 4.135 ;
      RECT  25.57 2.305 25.86 2.535 ;
      RECT  27.295 3.735 27.565 3.78 ;
      RECT  27.295 2.135 27.565 2.18 ;
      RECT  29.93 3.905 30.22 4.135 ;
      RECT  29.93 2.305 30.22 2.535 ;
      RECT  26.875 3.905 27.165 4.135 ;
      RECT  25.63 2.535 25.8 3.905 ;
      RECT  25.57 1.105 25.86 1.335 ;
      RECT  25.955 3.305 26.245 3.335 ;
      RECT  29.99 2.535 30.16 3.905 ;
      RECT  30.86 3.045 31.19 3.305 ;
      RECT  28.685 1.335 28.855 3.905 ;
      RECT  25.955 3.135 27.105 3.305 ;
      RECT  26.135 2.69 26.465 2.95 ;
      RECT  30.88 3.905 31.17 4.135 ;
      RECT  30.47 2.29 30.8 2.55 ;
      RECT  26.935 3.305 27.105 3.905 ;
      RECT  27.295 3.46 27.565 3.505 ;
      RECT  27.295 1.86 27.565 1.905 ;
      RECT  28.625 3.905 28.915 4.135 ;
      RECT  27.285 3.505 27.575 3.735 ;
      RECT  27.285 1.905 27.575 2.135 ;
      RECT  26.875 1.105 27.165 1.335 ;
      RECT  30.94 3.305 31.11 3.905 ;
      RECT  29.99 1.335 30.16 2.305 ;
      RECT  30.94 1.335 31.11 3.045 ;
      RECT  30.88 1.105 31.17 1.335 ;
      RECT  26.935 1.335 27.105 3.135 ;
      RECT  31.795 3.105 32.085 3.135 ;
      RECT  31.47 1.335 31.64 2.305 ;
      RECT  35.77 1.105 36.06 1.335 ;
      RECT  34.465 1.105 34.755 1.335 ;
      RECT  33.185 2.18 33.355 3.46 ;
      RECT  31.41 3.905 31.7 4.135 ;
      RECT  31.41 2.305 31.7 2.535 ;
      RECT  33.135 3.735 33.405 3.78 ;
      RECT  33.135 2.135 33.405 2.18 ;
      RECT  35.77 3.905 36.06 4.135 ;
      RECT  35.77 2.305 36.06 2.535 ;
      RECT  32.715 3.905 33.005 4.135 ;
      RECT  31.47 2.535 31.64 3.905 ;
      RECT  31.41 1.105 31.7 1.335 ;
      RECT  31.795 3.305 32.085 3.335 ;
      RECT  35.83 2.535 36.0 3.905 ;
      RECT  36.7 3.045 37.03 3.305 ;
      RECT  34.525 1.335 34.695 3.905 ;
      RECT  31.795 3.135 32.945 3.305 ;
      RECT  31.975 2.69 32.305 2.95 ;
      RECT  36.72 3.905 37.01 4.135 ;
      RECT  36.31 2.29 36.64 2.55 ;
      RECT  32.775 3.305 32.945 3.905 ;
      RECT  33.135 3.46 33.405 3.505 ;
      RECT  33.135 1.86 33.405 1.905 ;
      RECT  34.465 3.905 34.755 4.135 ;
      RECT  33.125 3.505 33.415 3.735 ;
      RECT  33.125 1.905 33.415 2.135 ;
      RECT  32.715 1.105 33.005 1.335 ;
      RECT  36.78 3.305 36.95 3.905 ;
      RECT  35.83 1.335 36.0 2.305 ;
      RECT  36.78 1.335 36.95 3.045 ;
      RECT  36.72 1.105 37.01 1.335 ;
      RECT  32.775 1.335 32.945 3.135 ;
   LAYER  m2 ;
      RECT  67.86 62.925 68.37 63.165 ;
      RECT  67.86 62.855 68.06 62.925 ;
      RECT  66.39 62.305 66.93 62.685 ;
      RECT  65.46 61.035 66.39 61.585 ;
      RECT  65.25 62.925 65.46 63.165 ;
      RECT  68.37 62.925 68.58 63.165 ;
      RECT  65.46 62.925 67.86 63.165 ;
      RECT  67.65 62.065 67.86 62.135 ;
      RECT  68.37 62.305 68.58 62.685 ;
      RECT  67.65 62.855 67.86 62.925 ;
      RECT  67.86 62.065 68.06 62.135 ;
      RECT  65.46 61.825 67.86 62.065 ;
      RECT  68.37 61.825 68.58 62.065 ;
      RECT  66.39 61.035 66.93 61.585 ;
      RECT  65.25 62.305 66.39 62.685 ;
      RECT  65.25 61.035 65.46 61.585 ;
      POLYGON  68.23 62.305 68.23 62.375 67.86 62.375 67.86 62.615 68.23 62.615 68.23 62.685 68.37 62.685 68.37 62.305 68.23 62.305 ;
      RECT  67.86 61.825 68.37 62.065 ;
      RECT  66.93 61.035 68.58 61.585 ;
      POLYGON  66.93 62.305 66.93 62.685 67.48 62.685 67.48 62.615 67.86 62.615 67.86 62.375 67.48 62.375 67.48 62.305 66.93 62.305 ;
      RECT  65.25 61.825 65.46 62.065 ;
      RECT  67.86 63.645 68.37 63.405 ;
      RECT  67.86 63.715 68.06 63.645 ;
      RECT  66.39 64.265 66.93 63.885 ;
      RECT  65.46 65.535 66.39 64.985 ;
      RECT  65.25 63.645 65.46 63.405 ;
      RECT  68.37 63.645 68.58 63.405 ;
      RECT  65.46 63.645 67.86 63.405 ;
      RECT  67.65 64.505 67.86 64.435 ;
      RECT  68.37 64.265 68.58 63.885 ;
      RECT  67.65 63.715 67.86 63.645 ;
      RECT  67.86 64.505 68.06 64.435 ;
      RECT  65.46 64.745 67.86 64.505 ;
      RECT  68.37 64.745 68.58 64.505 ;
      RECT  66.39 65.535 66.93 64.985 ;
      RECT  65.25 64.265 66.39 63.885 ;
      RECT  65.25 65.535 65.46 64.985 ;
      POLYGON  68.23 64.265 68.23 64.195 67.86 64.195 67.86 63.955 68.23 63.955 68.23 63.885 68.37 63.885 68.37 64.265 68.23 64.265 ;
      RECT  67.86 64.745 68.37 64.505 ;
      RECT  66.93 65.535 68.58 64.985 ;
      POLYGON  66.93 64.265 66.93 63.885 67.48 63.885 67.48 63.955 67.86 63.955 67.86 64.195 67.48 64.195 67.48 64.265 66.93 64.265 ;
      RECT  65.25 64.745 65.46 64.505 ;
      RECT  67.86 66.875 68.37 67.115 ;
      RECT  67.86 66.805 68.06 66.875 ;
      RECT  66.39 66.255 66.93 66.635 ;
      RECT  65.46 64.985 66.39 65.535 ;
      RECT  65.25 66.875 65.46 67.115 ;
      RECT  68.37 66.875 68.58 67.115 ;
      RECT  65.46 66.875 67.86 67.115 ;
      RECT  67.65 66.015 67.86 66.085 ;
      RECT  68.37 66.255 68.58 66.635 ;
      RECT  67.65 66.805 67.86 66.875 ;
      RECT  67.86 66.015 68.06 66.085 ;
      RECT  65.46 65.775 67.86 66.015 ;
      RECT  68.37 65.775 68.58 66.015 ;
      RECT  66.39 64.985 66.93 65.535 ;
      RECT  65.25 66.255 66.39 66.635 ;
      RECT  65.25 64.985 65.46 65.535 ;
      POLYGON  68.23 66.255 68.23 66.325 67.86 66.325 67.86 66.565 68.23 66.565 68.23 66.635 68.37 66.635 68.37 66.255 68.23 66.255 ;
      RECT  67.86 65.775 68.37 66.015 ;
      RECT  66.93 64.985 68.58 65.535 ;
      POLYGON  66.93 66.255 66.93 66.635 67.48 66.635 67.48 66.565 67.86 66.565 67.86 66.325 67.48 66.325 67.48 66.255 66.93 66.255 ;
      RECT  65.25 65.775 65.46 66.015 ;
      RECT  67.86 67.595 68.37 67.355 ;
      RECT  67.86 67.665 68.06 67.595 ;
      RECT  66.39 68.215 66.93 67.835 ;
      RECT  65.46 69.485 66.39 68.935 ;
      RECT  65.25 67.595 65.46 67.355 ;
      RECT  68.37 67.595 68.58 67.355 ;
      RECT  65.46 67.595 67.86 67.355 ;
      RECT  67.65 68.455 67.86 68.385 ;
      RECT  68.37 68.215 68.58 67.835 ;
      RECT  67.65 67.665 67.86 67.595 ;
      RECT  67.86 68.455 68.06 68.385 ;
      RECT  65.46 68.695 67.86 68.455 ;
      RECT  68.37 68.695 68.58 68.455 ;
      RECT  66.39 69.485 66.93 68.935 ;
      RECT  65.25 68.215 66.39 67.835 ;
      RECT  65.25 69.485 65.46 68.935 ;
      POLYGON  68.23 68.215 68.23 68.145 67.86 68.145 67.86 67.905 68.23 67.905 68.23 67.835 68.37 67.835 68.37 68.215 68.23 68.215 ;
      RECT  67.86 68.695 68.37 68.455 ;
      RECT  66.93 69.485 68.58 68.935 ;
      POLYGON  66.93 68.215 66.93 67.835 67.48 67.835 67.48 67.905 67.86 67.905 67.86 68.145 67.48 68.145 67.48 68.215 66.93 68.215 ;
      RECT  65.25 68.695 65.46 68.455 ;
      RECT  67.86 70.825 68.37 71.065 ;
      RECT  67.86 70.755 68.06 70.825 ;
      RECT  66.39 70.205 66.93 70.585 ;
      RECT  65.46 68.935 66.39 69.485 ;
      RECT  65.25 70.825 65.46 71.065 ;
      RECT  68.37 70.825 68.58 71.065 ;
      RECT  65.46 70.825 67.86 71.065 ;
      RECT  67.65 69.965 67.86 70.035 ;
      RECT  68.37 70.205 68.58 70.585 ;
      RECT  67.65 70.755 67.86 70.825 ;
      RECT  67.86 69.965 68.06 70.035 ;
      RECT  65.46 69.725 67.86 69.965 ;
      RECT  68.37 69.725 68.58 69.965 ;
      RECT  66.39 68.935 66.93 69.485 ;
      RECT  65.25 70.205 66.39 70.585 ;
      RECT  65.25 68.935 65.46 69.485 ;
      POLYGON  68.23 70.205 68.23 70.275 67.86 70.275 67.86 70.515 68.23 70.515 68.23 70.585 68.37 70.585 68.37 70.205 68.23 70.205 ;
      RECT  67.86 69.725 68.37 69.965 ;
      RECT  66.93 68.935 68.58 69.485 ;
      POLYGON  66.93 70.205 66.93 70.585 67.48 70.585 67.48 70.515 67.86 70.515 67.86 70.275 67.48 70.275 67.48 70.205 66.93 70.205 ;
      RECT  65.25 69.725 65.46 69.965 ;
      RECT  67.86 71.545 68.37 71.305 ;
      RECT  67.86 71.615 68.06 71.545 ;
      RECT  66.39 72.165 66.93 71.785 ;
      RECT  65.46 73.435 66.39 72.885 ;
      RECT  65.25 71.545 65.46 71.305 ;
      RECT  68.37 71.545 68.58 71.305 ;
      RECT  65.46 71.545 67.86 71.305 ;
      RECT  67.65 72.405 67.86 72.335 ;
      RECT  68.37 72.165 68.58 71.785 ;
      RECT  67.65 71.615 67.86 71.545 ;
      RECT  67.86 72.405 68.06 72.335 ;
      RECT  65.46 72.645 67.86 72.405 ;
      RECT  68.37 72.645 68.58 72.405 ;
      RECT  66.39 73.435 66.93 72.885 ;
      RECT  65.25 72.165 66.39 71.785 ;
      RECT  65.25 73.435 65.46 72.885 ;
      POLYGON  68.23 72.165 68.23 72.095 67.86 72.095 67.86 71.855 68.23 71.855 68.23 71.785 68.37 71.785 68.37 72.165 68.23 72.165 ;
      RECT  67.86 72.645 68.37 72.405 ;
      RECT  66.93 73.435 68.58 72.885 ;
      POLYGON  66.93 72.165 66.93 71.785 67.48 71.785 67.48 71.855 67.86 71.855 67.86 72.095 67.48 72.095 67.48 72.165 66.93 72.165 ;
      RECT  65.25 72.645 65.46 72.405 ;
      RECT  67.86 74.775 68.37 75.015 ;
      RECT  67.86 74.705 68.06 74.775 ;
      RECT  66.39 74.155 66.93 74.535 ;
      RECT  65.46 72.885 66.39 73.435 ;
      RECT  65.25 74.775 65.46 75.015 ;
      RECT  68.37 74.775 68.58 75.015 ;
      RECT  65.46 74.775 67.86 75.015 ;
      RECT  67.65 73.915 67.86 73.985 ;
      RECT  68.37 74.155 68.58 74.535 ;
      RECT  67.65 74.705 67.86 74.775 ;
      RECT  67.86 73.915 68.06 73.985 ;
      RECT  65.46 73.675 67.86 73.915 ;
      RECT  68.37 73.675 68.58 73.915 ;
      RECT  66.39 72.885 66.93 73.435 ;
      RECT  65.25 74.155 66.39 74.535 ;
      RECT  65.25 72.885 65.46 73.435 ;
      POLYGON  68.23 74.155 68.23 74.225 67.86 74.225 67.86 74.465 68.23 74.465 68.23 74.535 68.37 74.535 68.37 74.155 68.23 74.155 ;
      RECT  67.86 73.675 68.37 73.915 ;
      RECT  66.93 72.885 68.58 73.435 ;
      POLYGON  66.93 74.155 66.93 74.535 67.48 74.535 67.48 74.465 67.86 74.465 67.86 74.225 67.48 74.225 67.48 74.155 66.93 74.155 ;
      RECT  65.25 73.675 65.46 73.915 ;
      RECT  67.86 75.495 68.37 75.255 ;
      RECT  67.86 75.565 68.06 75.495 ;
      RECT  66.39 76.115 66.93 75.735 ;
      RECT  65.46 77.385 66.39 76.835 ;
      RECT  65.25 75.495 65.46 75.255 ;
      RECT  68.37 75.495 68.58 75.255 ;
      RECT  65.46 75.495 67.86 75.255 ;
      RECT  67.65 76.355 67.86 76.285 ;
      RECT  68.37 76.115 68.58 75.735 ;
      RECT  67.65 75.565 67.86 75.495 ;
      RECT  67.86 76.355 68.06 76.285 ;
      RECT  65.46 76.595 67.86 76.355 ;
      RECT  68.37 76.595 68.58 76.355 ;
      RECT  66.39 77.385 66.93 76.835 ;
      RECT  65.25 76.115 66.39 75.735 ;
      RECT  65.25 77.385 65.46 76.835 ;
      POLYGON  68.23 76.115 68.23 76.045 67.86 76.045 67.86 75.805 68.23 75.805 68.23 75.735 68.37 75.735 68.37 76.115 68.23 76.115 ;
      RECT  67.86 76.595 68.37 76.355 ;
      RECT  66.93 77.385 68.58 76.835 ;
      POLYGON  66.93 76.115 66.93 75.735 67.48 75.735 67.48 75.805 67.86 75.805 67.86 76.045 67.48 76.045 67.48 76.115 66.93 76.115 ;
      RECT  65.25 76.595 65.46 76.355 ;
      RECT  67.86 78.725 68.37 78.965 ;
      RECT  67.86 78.655 68.06 78.725 ;
      RECT  66.39 78.105 66.93 78.485 ;
      RECT  65.46 76.835 66.39 77.385 ;
      RECT  65.25 78.725 65.46 78.965 ;
      RECT  68.37 78.725 68.58 78.965 ;
      RECT  65.46 78.725 67.86 78.965 ;
      RECT  67.65 77.865 67.86 77.935 ;
      RECT  68.37 78.105 68.58 78.485 ;
      RECT  67.65 78.655 67.86 78.725 ;
      RECT  67.86 77.865 68.06 77.935 ;
      RECT  65.46 77.625 67.86 77.865 ;
      RECT  68.37 77.625 68.58 77.865 ;
      RECT  66.39 76.835 66.93 77.385 ;
      RECT  65.25 78.105 66.39 78.485 ;
      RECT  65.25 76.835 65.46 77.385 ;
      POLYGON  68.23 78.105 68.23 78.175 67.86 78.175 67.86 78.415 68.23 78.415 68.23 78.485 68.37 78.485 68.37 78.105 68.23 78.105 ;
      RECT  67.86 77.625 68.37 77.865 ;
      RECT  66.93 76.835 68.58 77.385 ;
      POLYGON  66.93 78.105 66.93 78.485 67.48 78.485 67.48 78.415 67.86 78.415 67.86 78.175 67.48 78.175 67.48 78.105 66.93 78.105 ;
      RECT  65.25 77.625 65.46 77.865 ;
      RECT  67.86 79.445 68.37 79.205 ;
      RECT  67.86 79.515 68.06 79.445 ;
      RECT  66.39 80.065 66.93 79.685 ;
      RECT  65.46 81.335 66.39 80.785 ;
      RECT  65.25 79.445 65.46 79.205 ;
      RECT  68.37 79.445 68.58 79.205 ;
      RECT  65.46 79.445 67.86 79.205 ;
      RECT  67.65 80.305 67.86 80.235 ;
      RECT  68.37 80.065 68.58 79.685 ;
      RECT  67.65 79.515 67.86 79.445 ;
      RECT  67.86 80.305 68.06 80.235 ;
      RECT  65.46 80.545 67.86 80.305 ;
      RECT  68.37 80.545 68.58 80.305 ;
      RECT  66.39 81.335 66.93 80.785 ;
      RECT  65.25 80.065 66.39 79.685 ;
      RECT  65.25 81.335 65.46 80.785 ;
      POLYGON  68.23 80.065 68.23 79.995 67.86 79.995 67.86 79.755 68.23 79.755 68.23 79.685 68.37 79.685 68.37 80.065 68.23 80.065 ;
      RECT  67.86 80.545 68.37 80.305 ;
      RECT  66.93 81.335 68.58 80.785 ;
      POLYGON  66.93 80.065 66.93 79.685 67.48 79.685 67.48 79.755 67.86 79.755 67.86 79.995 67.48 79.995 67.48 80.065 66.93 80.065 ;
      RECT  65.25 80.545 65.46 80.305 ;
      RECT  67.86 82.675 68.37 82.915 ;
      RECT  67.86 82.605 68.06 82.675 ;
      RECT  66.39 82.055 66.93 82.435 ;
      RECT  65.46 80.785 66.39 81.335 ;
      RECT  65.25 82.675 65.46 82.915 ;
      RECT  68.37 82.675 68.58 82.915 ;
      RECT  65.46 82.675 67.86 82.915 ;
      RECT  67.65 81.815 67.86 81.885 ;
      RECT  68.37 82.055 68.58 82.435 ;
      RECT  67.65 82.605 67.86 82.675 ;
      RECT  67.86 81.815 68.06 81.885 ;
      RECT  65.46 81.575 67.86 81.815 ;
      RECT  68.37 81.575 68.58 81.815 ;
      RECT  66.39 80.785 66.93 81.335 ;
      RECT  65.25 82.055 66.39 82.435 ;
      RECT  65.25 80.785 65.46 81.335 ;
      POLYGON  68.23 82.055 68.23 82.125 67.86 82.125 67.86 82.365 68.23 82.365 68.23 82.435 68.37 82.435 68.37 82.055 68.23 82.055 ;
      RECT  67.86 81.575 68.37 81.815 ;
      RECT  66.93 80.785 68.58 81.335 ;
      POLYGON  66.93 82.055 66.93 82.435 67.48 82.435 67.48 82.365 67.86 82.365 67.86 82.125 67.48 82.125 67.48 82.055 66.93 82.055 ;
      RECT  65.25 81.575 65.46 81.815 ;
      RECT  67.86 83.395 68.37 83.155 ;
      RECT  67.86 83.465 68.06 83.395 ;
      RECT  66.39 84.015 66.93 83.635 ;
      RECT  65.46 85.285 66.39 84.735 ;
      RECT  65.25 83.395 65.46 83.155 ;
      RECT  68.37 83.395 68.58 83.155 ;
      RECT  65.46 83.395 67.86 83.155 ;
      RECT  67.65 84.255 67.86 84.185 ;
      RECT  68.37 84.015 68.58 83.635 ;
      RECT  67.65 83.465 67.86 83.395 ;
      RECT  67.86 84.255 68.06 84.185 ;
      RECT  65.46 84.495 67.86 84.255 ;
      RECT  68.37 84.495 68.58 84.255 ;
      RECT  66.39 85.285 66.93 84.735 ;
      RECT  65.25 84.015 66.39 83.635 ;
      RECT  65.25 85.285 65.46 84.735 ;
      POLYGON  68.23 84.015 68.23 83.945 67.86 83.945 67.86 83.705 68.23 83.705 68.23 83.635 68.37 83.635 68.37 84.015 68.23 84.015 ;
      RECT  67.86 84.495 68.37 84.255 ;
      RECT  66.93 85.285 68.58 84.735 ;
      POLYGON  66.93 84.015 66.93 83.635 67.48 83.635 67.48 83.705 67.86 83.705 67.86 83.945 67.48 83.945 67.48 84.015 66.93 84.015 ;
      RECT  65.25 84.495 65.46 84.255 ;
      RECT  67.86 86.625 68.37 86.865 ;
      RECT  67.86 86.555 68.06 86.625 ;
      RECT  66.39 86.005 66.93 86.385 ;
      RECT  65.46 84.735 66.39 85.285 ;
      RECT  65.25 86.625 65.46 86.865 ;
      RECT  68.37 86.625 68.58 86.865 ;
      RECT  65.46 86.625 67.86 86.865 ;
      RECT  67.65 85.765 67.86 85.835 ;
      RECT  68.37 86.005 68.58 86.385 ;
      RECT  67.65 86.555 67.86 86.625 ;
      RECT  67.86 85.765 68.06 85.835 ;
      RECT  65.46 85.525 67.86 85.765 ;
      RECT  68.37 85.525 68.58 85.765 ;
      RECT  66.39 84.735 66.93 85.285 ;
      RECT  65.25 86.005 66.39 86.385 ;
      RECT  65.25 84.735 65.46 85.285 ;
      POLYGON  68.23 86.005 68.23 86.075 67.86 86.075 67.86 86.315 68.23 86.315 68.23 86.385 68.37 86.385 68.37 86.005 68.23 86.005 ;
      RECT  67.86 85.525 68.37 85.765 ;
      RECT  66.93 84.735 68.58 85.285 ;
      POLYGON  66.93 86.005 66.93 86.385 67.48 86.385 67.48 86.315 67.86 86.315 67.86 86.075 67.48 86.075 67.48 86.005 66.93 86.005 ;
      RECT  65.25 85.525 65.46 85.765 ;
      RECT  67.86 87.345 68.37 87.105 ;
      RECT  67.86 87.415 68.06 87.345 ;
      RECT  66.39 87.965 66.93 87.585 ;
      RECT  65.46 89.235 66.39 88.685 ;
      RECT  65.25 87.345 65.46 87.105 ;
      RECT  68.37 87.345 68.58 87.105 ;
      RECT  65.46 87.345 67.86 87.105 ;
      RECT  67.65 88.205 67.86 88.135 ;
      RECT  68.37 87.965 68.58 87.585 ;
      RECT  67.65 87.415 67.86 87.345 ;
      RECT  67.86 88.205 68.06 88.135 ;
      RECT  65.46 88.445 67.86 88.205 ;
      RECT  68.37 88.445 68.58 88.205 ;
      RECT  66.39 89.235 66.93 88.685 ;
      RECT  65.25 87.965 66.39 87.585 ;
      RECT  65.25 89.235 65.46 88.685 ;
      POLYGON  68.23 87.965 68.23 87.895 67.86 87.895 67.86 87.655 68.23 87.655 68.23 87.585 68.37 87.585 68.37 87.965 68.23 87.965 ;
      RECT  67.86 88.445 68.37 88.205 ;
      RECT  66.93 89.235 68.58 88.685 ;
      POLYGON  66.93 87.965 66.93 87.585 67.48 87.585 67.48 87.655 67.86 87.655 67.86 87.895 67.48 87.895 67.48 87.965 66.93 87.965 ;
      RECT  65.25 88.445 65.46 88.205 ;
      RECT  67.86 90.575 68.37 90.815 ;
      RECT  67.86 90.505 68.06 90.575 ;
      RECT  66.39 89.955 66.93 90.335 ;
      RECT  65.46 88.685 66.39 89.235 ;
      RECT  65.25 90.575 65.46 90.815 ;
      RECT  68.37 90.575 68.58 90.815 ;
      RECT  65.46 90.575 67.86 90.815 ;
      RECT  67.65 89.715 67.86 89.785 ;
      RECT  68.37 89.955 68.58 90.335 ;
      RECT  67.65 90.505 67.86 90.575 ;
      RECT  67.86 89.715 68.06 89.785 ;
      RECT  65.46 89.475 67.86 89.715 ;
      RECT  68.37 89.475 68.58 89.715 ;
      RECT  66.39 88.685 66.93 89.235 ;
      RECT  65.25 89.955 66.39 90.335 ;
      RECT  65.25 88.685 65.46 89.235 ;
      POLYGON  68.23 89.955 68.23 90.025 67.86 90.025 67.86 90.265 68.23 90.265 68.23 90.335 68.37 90.335 68.37 89.955 68.23 89.955 ;
      RECT  67.86 89.475 68.37 89.715 ;
      RECT  66.93 88.685 68.58 89.235 ;
      POLYGON  66.93 89.955 66.93 90.335 67.48 90.335 67.48 90.265 67.86 90.265 67.86 90.025 67.48 90.025 67.48 89.955 66.93 89.955 ;
      RECT  65.25 89.475 65.46 89.715 ;
      RECT  67.86 91.295 68.37 91.055 ;
      RECT  67.86 91.365 68.06 91.295 ;
      RECT  66.39 91.915 66.93 91.535 ;
      RECT  65.46 93.185 66.39 92.635 ;
      RECT  65.25 91.295 65.46 91.055 ;
      RECT  68.37 91.295 68.58 91.055 ;
      RECT  65.46 91.295 67.86 91.055 ;
      RECT  67.65 92.155 67.86 92.085 ;
      RECT  68.37 91.915 68.58 91.535 ;
      RECT  67.65 91.365 67.86 91.295 ;
      RECT  67.86 92.155 68.06 92.085 ;
      RECT  65.46 92.395 67.86 92.155 ;
      RECT  68.37 92.395 68.58 92.155 ;
      RECT  66.39 93.185 66.93 92.635 ;
      RECT  65.25 91.915 66.39 91.535 ;
      RECT  65.25 93.185 65.46 92.635 ;
      POLYGON  68.23 91.915 68.23 91.845 67.86 91.845 67.86 91.605 68.23 91.605 68.23 91.535 68.37 91.535 68.37 91.915 68.23 91.915 ;
      RECT  67.86 92.395 68.37 92.155 ;
      RECT  66.93 93.185 68.58 92.635 ;
      POLYGON  66.93 91.915 66.93 91.535 67.48 91.535 67.48 91.605 67.86 91.605 67.86 91.845 67.48 91.845 67.48 91.915 66.93 91.915 ;
      RECT  65.25 92.395 65.46 92.155 ;
      RECT  69.3 62.925 68.79 63.165 ;
      RECT  69.3 62.855 69.1 62.925 ;
      RECT  70.77 62.305 70.23 62.685 ;
      RECT  71.7 61.035 70.77 61.585 ;
      RECT  71.91 62.925 71.7 63.165 ;
      RECT  68.79 62.925 68.58 63.165 ;
      RECT  71.7 62.925 69.3 63.165 ;
      RECT  69.51 62.065 69.3 62.135 ;
      RECT  68.79 62.305 68.58 62.685 ;
      RECT  69.51 62.855 69.3 62.925 ;
      RECT  69.3 62.065 69.1 62.135 ;
      RECT  71.7 61.825 69.3 62.065 ;
      RECT  68.79 61.825 68.58 62.065 ;
      RECT  70.77 61.035 70.23 61.585 ;
      RECT  71.91 62.305 70.77 62.685 ;
      RECT  71.91 61.035 71.7 61.585 ;
      POLYGON  68.93 62.305 68.93 62.375 69.3 62.375 69.3 62.615 68.93 62.615 68.93 62.685 68.79 62.685 68.79 62.305 68.93 62.305 ;
      RECT  69.3 61.825 68.79 62.065 ;
      RECT  70.23 61.035 68.58 61.585 ;
      POLYGON  70.23 62.305 70.23 62.685 69.68 62.685 69.68 62.615 69.3 62.615 69.3 62.375 69.68 62.375 69.68 62.305 70.23 62.305 ;
      RECT  71.91 61.825 71.7 62.065 ;
      RECT  69.3 63.645 68.79 63.405 ;
      RECT  69.3 63.715 69.1 63.645 ;
      RECT  70.77 64.265 70.23 63.885 ;
      RECT  71.7 65.535 70.77 64.985 ;
      RECT  71.91 63.645 71.7 63.405 ;
      RECT  68.79 63.645 68.58 63.405 ;
      RECT  71.7 63.645 69.3 63.405 ;
      RECT  69.51 64.505 69.3 64.435 ;
      RECT  68.79 64.265 68.58 63.885 ;
      RECT  69.51 63.715 69.3 63.645 ;
      RECT  69.3 64.505 69.1 64.435 ;
      RECT  71.7 64.745 69.3 64.505 ;
      RECT  68.79 64.745 68.58 64.505 ;
      RECT  70.77 65.535 70.23 64.985 ;
      RECT  71.91 64.265 70.77 63.885 ;
      RECT  71.91 65.535 71.7 64.985 ;
      POLYGON  68.93 64.265 68.93 64.195 69.3 64.195 69.3 63.955 68.93 63.955 68.93 63.885 68.79 63.885 68.79 64.265 68.93 64.265 ;
      RECT  69.3 64.745 68.79 64.505 ;
      RECT  70.23 65.535 68.58 64.985 ;
      POLYGON  70.23 64.265 70.23 63.885 69.68 63.885 69.68 63.955 69.3 63.955 69.3 64.195 69.68 64.195 69.68 64.265 70.23 64.265 ;
      RECT  71.91 64.745 71.7 64.505 ;
      RECT  69.3 66.875 68.79 67.115 ;
      RECT  69.3 66.805 69.1 66.875 ;
      RECT  70.77 66.255 70.23 66.635 ;
      RECT  71.7 64.985 70.77 65.535 ;
      RECT  71.91 66.875 71.7 67.115 ;
      RECT  68.79 66.875 68.58 67.115 ;
      RECT  71.7 66.875 69.3 67.115 ;
      RECT  69.51 66.015 69.3 66.085 ;
      RECT  68.79 66.255 68.58 66.635 ;
      RECT  69.51 66.805 69.3 66.875 ;
      RECT  69.3 66.015 69.1 66.085 ;
      RECT  71.7 65.775 69.3 66.015 ;
      RECT  68.79 65.775 68.58 66.015 ;
      RECT  70.77 64.985 70.23 65.535 ;
      RECT  71.91 66.255 70.77 66.635 ;
      RECT  71.91 64.985 71.7 65.535 ;
      POLYGON  68.93 66.255 68.93 66.325 69.3 66.325 69.3 66.565 68.93 66.565 68.93 66.635 68.79 66.635 68.79 66.255 68.93 66.255 ;
      RECT  69.3 65.775 68.79 66.015 ;
      RECT  70.23 64.985 68.58 65.535 ;
      POLYGON  70.23 66.255 70.23 66.635 69.68 66.635 69.68 66.565 69.3 66.565 69.3 66.325 69.68 66.325 69.68 66.255 70.23 66.255 ;
      RECT  71.91 65.775 71.7 66.015 ;
      RECT  69.3 67.595 68.79 67.355 ;
      RECT  69.3 67.665 69.1 67.595 ;
      RECT  70.77 68.215 70.23 67.835 ;
      RECT  71.7 69.485 70.77 68.935 ;
      RECT  71.91 67.595 71.7 67.355 ;
      RECT  68.79 67.595 68.58 67.355 ;
      RECT  71.7 67.595 69.3 67.355 ;
      RECT  69.51 68.455 69.3 68.385 ;
      RECT  68.79 68.215 68.58 67.835 ;
      RECT  69.51 67.665 69.3 67.595 ;
      RECT  69.3 68.455 69.1 68.385 ;
      RECT  71.7 68.695 69.3 68.455 ;
      RECT  68.79 68.695 68.58 68.455 ;
      RECT  70.77 69.485 70.23 68.935 ;
      RECT  71.91 68.215 70.77 67.835 ;
      RECT  71.91 69.485 71.7 68.935 ;
      POLYGON  68.93 68.215 68.93 68.145 69.3 68.145 69.3 67.905 68.93 67.905 68.93 67.835 68.79 67.835 68.79 68.215 68.93 68.215 ;
      RECT  69.3 68.695 68.79 68.455 ;
      RECT  70.23 69.485 68.58 68.935 ;
      POLYGON  70.23 68.215 70.23 67.835 69.68 67.835 69.68 67.905 69.3 67.905 69.3 68.145 69.68 68.145 69.68 68.215 70.23 68.215 ;
      RECT  71.91 68.695 71.7 68.455 ;
      RECT  69.3 70.825 68.79 71.065 ;
      RECT  69.3 70.755 69.1 70.825 ;
      RECT  70.77 70.205 70.23 70.585 ;
      RECT  71.7 68.935 70.77 69.485 ;
      RECT  71.91 70.825 71.7 71.065 ;
      RECT  68.79 70.825 68.58 71.065 ;
      RECT  71.7 70.825 69.3 71.065 ;
      RECT  69.51 69.965 69.3 70.035 ;
      RECT  68.79 70.205 68.58 70.585 ;
      RECT  69.51 70.755 69.3 70.825 ;
      RECT  69.3 69.965 69.1 70.035 ;
      RECT  71.7 69.725 69.3 69.965 ;
      RECT  68.79 69.725 68.58 69.965 ;
      RECT  70.77 68.935 70.23 69.485 ;
      RECT  71.91 70.205 70.77 70.585 ;
      RECT  71.91 68.935 71.7 69.485 ;
      POLYGON  68.93 70.205 68.93 70.275 69.3 70.275 69.3 70.515 68.93 70.515 68.93 70.585 68.79 70.585 68.79 70.205 68.93 70.205 ;
      RECT  69.3 69.725 68.79 69.965 ;
      RECT  70.23 68.935 68.58 69.485 ;
      POLYGON  70.23 70.205 70.23 70.585 69.68 70.585 69.68 70.515 69.3 70.515 69.3 70.275 69.68 70.275 69.68 70.205 70.23 70.205 ;
      RECT  71.91 69.725 71.7 69.965 ;
      RECT  69.3 71.545 68.79 71.305 ;
      RECT  69.3 71.615 69.1 71.545 ;
      RECT  70.77 72.165 70.23 71.785 ;
      RECT  71.7 73.435 70.77 72.885 ;
      RECT  71.91 71.545 71.7 71.305 ;
      RECT  68.79 71.545 68.58 71.305 ;
      RECT  71.7 71.545 69.3 71.305 ;
      RECT  69.51 72.405 69.3 72.335 ;
      RECT  68.79 72.165 68.58 71.785 ;
      RECT  69.51 71.615 69.3 71.545 ;
      RECT  69.3 72.405 69.1 72.335 ;
      RECT  71.7 72.645 69.3 72.405 ;
      RECT  68.79 72.645 68.58 72.405 ;
      RECT  70.77 73.435 70.23 72.885 ;
      RECT  71.91 72.165 70.77 71.785 ;
      RECT  71.91 73.435 71.7 72.885 ;
      POLYGON  68.93 72.165 68.93 72.095 69.3 72.095 69.3 71.855 68.93 71.855 68.93 71.785 68.79 71.785 68.79 72.165 68.93 72.165 ;
      RECT  69.3 72.645 68.79 72.405 ;
      RECT  70.23 73.435 68.58 72.885 ;
      POLYGON  70.23 72.165 70.23 71.785 69.68 71.785 69.68 71.855 69.3 71.855 69.3 72.095 69.68 72.095 69.68 72.165 70.23 72.165 ;
      RECT  71.91 72.645 71.7 72.405 ;
      RECT  69.3 74.775 68.79 75.015 ;
      RECT  69.3 74.705 69.1 74.775 ;
      RECT  70.77 74.155 70.23 74.535 ;
      RECT  71.7 72.885 70.77 73.435 ;
      RECT  71.91 74.775 71.7 75.015 ;
      RECT  68.79 74.775 68.58 75.015 ;
      RECT  71.7 74.775 69.3 75.015 ;
      RECT  69.51 73.915 69.3 73.985 ;
      RECT  68.79 74.155 68.58 74.535 ;
      RECT  69.51 74.705 69.3 74.775 ;
      RECT  69.3 73.915 69.1 73.985 ;
      RECT  71.7 73.675 69.3 73.915 ;
      RECT  68.79 73.675 68.58 73.915 ;
      RECT  70.77 72.885 70.23 73.435 ;
      RECT  71.91 74.155 70.77 74.535 ;
      RECT  71.91 72.885 71.7 73.435 ;
      POLYGON  68.93 74.155 68.93 74.225 69.3 74.225 69.3 74.465 68.93 74.465 68.93 74.535 68.79 74.535 68.79 74.155 68.93 74.155 ;
      RECT  69.3 73.675 68.79 73.915 ;
      RECT  70.23 72.885 68.58 73.435 ;
      POLYGON  70.23 74.155 70.23 74.535 69.68 74.535 69.68 74.465 69.3 74.465 69.3 74.225 69.68 74.225 69.68 74.155 70.23 74.155 ;
      RECT  71.91 73.675 71.7 73.915 ;
      RECT  69.3 75.495 68.79 75.255 ;
      RECT  69.3 75.565 69.1 75.495 ;
      RECT  70.77 76.115 70.23 75.735 ;
      RECT  71.7 77.385 70.77 76.835 ;
      RECT  71.91 75.495 71.7 75.255 ;
      RECT  68.79 75.495 68.58 75.255 ;
      RECT  71.7 75.495 69.3 75.255 ;
      RECT  69.51 76.355 69.3 76.285 ;
      RECT  68.79 76.115 68.58 75.735 ;
      RECT  69.51 75.565 69.3 75.495 ;
      RECT  69.3 76.355 69.1 76.285 ;
      RECT  71.7 76.595 69.3 76.355 ;
      RECT  68.79 76.595 68.58 76.355 ;
      RECT  70.77 77.385 70.23 76.835 ;
      RECT  71.91 76.115 70.77 75.735 ;
      RECT  71.91 77.385 71.7 76.835 ;
      POLYGON  68.93 76.115 68.93 76.045 69.3 76.045 69.3 75.805 68.93 75.805 68.93 75.735 68.79 75.735 68.79 76.115 68.93 76.115 ;
      RECT  69.3 76.595 68.79 76.355 ;
      RECT  70.23 77.385 68.58 76.835 ;
      POLYGON  70.23 76.115 70.23 75.735 69.68 75.735 69.68 75.805 69.3 75.805 69.3 76.045 69.68 76.045 69.68 76.115 70.23 76.115 ;
      RECT  71.91 76.595 71.7 76.355 ;
      RECT  69.3 78.725 68.79 78.965 ;
      RECT  69.3 78.655 69.1 78.725 ;
      RECT  70.77 78.105 70.23 78.485 ;
      RECT  71.7 76.835 70.77 77.385 ;
      RECT  71.91 78.725 71.7 78.965 ;
      RECT  68.79 78.725 68.58 78.965 ;
      RECT  71.7 78.725 69.3 78.965 ;
      RECT  69.51 77.865 69.3 77.935 ;
      RECT  68.79 78.105 68.58 78.485 ;
      RECT  69.51 78.655 69.3 78.725 ;
      RECT  69.3 77.865 69.1 77.935 ;
      RECT  71.7 77.625 69.3 77.865 ;
      RECT  68.79 77.625 68.58 77.865 ;
      RECT  70.77 76.835 70.23 77.385 ;
      RECT  71.91 78.105 70.77 78.485 ;
      RECT  71.91 76.835 71.7 77.385 ;
      POLYGON  68.93 78.105 68.93 78.175 69.3 78.175 69.3 78.415 68.93 78.415 68.93 78.485 68.79 78.485 68.79 78.105 68.93 78.105 ;
      RECT  69.3 77.625 68.79 77.865 ;
      RECT  70.23 76.835 68.58 77.385 ;
      POLYGON  70.23 78.105 70.23 78.485 69.68 78.485 69.68 78.415 69.3 78.415 69.3 78.175 69.68 78.175 69.68 78.105 70.23 78.105 ;
      RECT  71.91 77.625 71.7 77.865 ;
      RECT  69.3 79.445 68.79 79.205 ;
      RECT  69.3 79.515 69.1 79.445 ;
      RECT  70.77 80.065 70.23 79.685 ;
      RECT  71.7 81.335 70.77 80.785 ;
      RECT  71.91 79.445 71.7 79.205 ;
      RECT  68.79 79.445 68.58 79.205 ;
      RECT  71.7 79.445 69.3 79.205 ;
      RECT  69.51 80.305 69.3 80.235 ;
      RECT  68.79 80.065 68.58 79.685 ;
      RECT  69.51 79.515 69.3 79.445 ;
      RECT  69.3 80.305 69.1 80.235 ;
      RECT  71.7 80.545 69.3 80.305 ;
      RECT  68.79 80.545 68.58 80.305 ;
      RECT  70.77 81.335 70.23 80.785 ;
      RECT  71.91 80.065 70.77 79.685 ;
      RECT  71.91 81.335 71.7 80.785 ;
      POLYGON  68.93 80.065 68.93 79.995 69.3 79.995 69.3 79.755 68.93 79.755 68.93 79.685 68.79 79.685 68.79 80.065 68.93 80.065 ;
      RECT  69.3 80.545 68.79 80.305 ;
      RECT  70.23 81.335 68.58 80.785 ;
      POLYGON  70.23 80.065 70.23 79.685 69.68 79.685 69.68 79.755 69.3 79.755 69.3 79.995 69.68 79.995 69.68 80.065 70.23 80.065 ;
      RECT  71.91 80.545 71.7 80.305 ;
      RECT  69.3 82.675 68.79 82.915 ;
      RECT  69.3 82.605 69.1 82.675 ;
      RECT  70.77 82.055 70.23 82.435 ;
      RECT  71.7 80.785 70.77 81.335 ;
      RECT  71.91 82.675 71.7 82.915 ;
      RECT  68.79 82.675 68.58 82.915 ;
      RECT  71.7 82.675 69.3 82.915 ;
      RECT  69.51 81.815 69.3 81.885 ;
      RECT  68.79 82.055 68.58 82.435 ;
      RECT  69.51 82.605 69.3 82.675 ;
      RECT  69.3 81.815 69.1 81.885 ;
      RECT  71.7 81.575 69.3 81.815 ;
      RECT  68.79 81.575 68.58 81.815 ;
      RECT  70.77 80.785 70.23 81.335 ;
      RECT  71.91 82.055 70.77 82.435 ;
      RECT  71.91 80.785 71.7 81.335 ;
      POLYGON  68.93 82.055 68.93 82.125 69.3 82.125 69.3 82.365 68.93 82.365 68.93 82.435 68.79 82.435 68.79 82.055 68.93 82.055 ;
      RECT  69.3 81.575 68.79 81.815 ;
      RECT  70.23 80.785 68.58 81.335 ;
      POLYGON  70.23 82.055 70.23 82.435 69.68 82.435 69.68 82.365 69.3 82.365 69.3 82.125 69.68 82.125 69.68 82.055 70.23 82.055 ;
      RECT  71.91 81.575 71.7 81.815 ;
      RECT  69.3 83.395 68.79 83.155 ;
      RECT  69.3 83.465 69.1 83.395 ;
      RECT  70.77 84.015 70.23 83.635 ;
      RECT  71.7 85.285 70.77 84.735 ;
      RECT  71.91 83.395 71.7 83.155 ;
      RECT  68.79 83.395 68.58 83.155 ;
      RECT  71.7 83.395 69.3 83.155 ;
      RECT  69.51 84.255 69.3 84.185 ;
      RECT  68.79 84.015 68.58 83.635 ;
      RECT  69.51 83.465 69.3 83.395 ;
      RECT  69.3 84.255 69.1 84.185 ;
      RECT  71.7 84.495 69.3 84.255 ;
      RECT  68.79 84.495 68.58 84.255 ;
      RECT  70.77 85.285 70.23 84.735 ;
      RECT  71.91 84.015 70.77 83.635 ;
      RECT  71.91 85.285 71.7 84.735 ;
      POLYGON  68.93 84.015 68.93 83.945 69.3 83.945 69.3 83.705 68.93 83.705 68.93 83.635 68.79 83.635 68.79 84.015 68.93 84.015 ;
      RECT  69.3 84.495 68.79 84.255 ;
      RECT  70.23 85.285 68.58 84.735 ;
      POLYGON  70.23 84.015 70.23 83.635 69.68 83.635 69.68 83.705 69.3 83.705 69.3 83.945 69.68 83.945 69.68 84.015 70.23 84.015 ;
      RECT  71.91 84.495 71.7 84.255 ;
      RECT  69.3 86.625 68.79 86.865 ;
      RECT  69.3 86.555 69.1 86.625 ;
      RECT  70.77 86.005 70.23 86.385 ;
      RECT  71.7 84.735 70.77 85.285 ;
      RECT  71.91 86.625 71.7 86.865 ;
      RECT  68.79 86.625 68.58 86.865 ;
      RECT  71.7 86.625 69.3 86.865 ;
      RECT  69.51 85.765 69.3 85.835 ;
      RECT  68.79 86.005 68.58 86.385 ;
      RECT  69.51 86.555 69.3 86.625 ;
      RECT  69.3 85.765 69.1 85.835 ;
      RECT  71.7 85.525 69.3 85.765 ;
      RECT  68.79 85.525 68.58 85.765 ;
      RECT  70.77 84.735 70.23 85.285 ;
      RECT  71.91 86.005 70.77 86.385 ;
      RECT  71.91 84.735 71.7 85.285 ;
      POLYGON  68.93 86.005 68.93 86.075 69.3 86.075 69.3 86.315 68.93 86.315 68.93 86.385 68.79 86.385 68.79 86.005 68.93 86.005 ;
      RECT  69.3 85.525 68.79 85.765 ;
      RECT  70.23 84.735 68.58 85.285 ;
      POLYGON  70.23 86.005 70.23 86.385 69.68 86.385 69.68 86.315 69.3 86.315 69.3 86.075 69.68 86.075 69.68 86.005 70.23 86.005 ;
      RECT  71.91 85.525 71.7 85.765 ;
      RECT  69.3 87.345 68.79 87.105 ;
      RECT  69.3 87.415 69.1 87.345 ;
      RECT  70.77 87.965 70.23 87.585 ;
      RECT  71.7 89.235 70.77 88.685 ;
      RECT  71.91 87.345 71.7 87.105 ;
      RECT  68.79 87.345 68.58 87.105 ;
      RECT  71.7 87.345 69.3 87.105 ;
      RECT  69.51 88.205 69.3 88.135 ;
      RECT  68.79 87.965 68.58 87.585 ;
      RECT  69.51 87.415 69.3 87.345 ;
      RECT  69.3 88.205 69.1 88.135 ;
      RECT  71.7 88.445 69.3 88.205 ;
      RECT  68.79 88.445 68.58 88.205 ;
      RECT  70.77 89.235 70.23 88.685 ;
      RECT  71.91 87.965 70.77 87.585 ;
      RECT  71.91 89.235 71.7 88.685 ;
      POLYGON  68.93 87.965 68.93 87.895 69.3 87.895 69.3 87.655 68.93 87.655 68.93 87.585 68.79 87.585 68.79 87.965 68.93 87.965 ;
      RECT  69.3 88.445 68.79 88.205 ;
      RECT  70.23 89.235 68.58 88.685 ;
      POLYGON  70.23 87.965 70.23 87.585 69.68 87.585 69.68 87.655 69.3 87.655 69.3 87.895 69.68 87.895 69.68 87.965 70.23 87.965 ;
      RECT  71.91 88.445 71.7 88.205 ;
      RECT  69.3 90.575 68.79 90.815 ;
      RECT  69.3 90.505 69.1 90.575 ;
      RECT  70.77 89.955 70.23 90.335 ;
      RECT  71.7 88.685 70.77 89.235 ;
      RECT  71.91 90.575 71.7 90.815 ;
      RECT  68.79 90.575 68.58 90.815 ;
      RECT  71.7 90.575 69.3 90.815 ;
      RECT  69.51 89.715 69.3 89.785 ;
      RECT  68.79 89.955 68.58 90.335 ;
      RECT  69.51 90.505 69.3 90.575 ;
      RECT  69.3 89.715 69.1 89.785 ;
      RECT  71.7 89.475 69.3 89.715 ;
      RECT  68.79 89.475 68.58 89.715 ;
      RECT  70.77 88.685 70.23 89.235 ;
      RECT  71.91 89.955 70.77 90.335 ;
      RECT  71.91 88.685 71.7 89.235 ;
      POLYGON  68.93 89.955 68.93 90.025 69.3 90.025 69.3 90.265 68.93 90.265 68.93 90.335 68.79 90.335 68.79 89.955 68.93 89.955 ;
      RECT  69.3 89.475 68.79 89.715 ;
      RECT  70.23 88.685 68.58 89.235 ;
      POLYGON  70.23 89.955 70.23 90.335 69.68 90.335 69.68 90.265 69.3 90.265 69.3 90.025 69.68 90.025 69.68 89.955 70.23 89.955 ;
      RECT  71.91 89.475 71.7 89.715 ;
      RECT  69.3 91.295 68.79 91.055 ;
      RECT  69.3 91.365 69.1 91.295 ;
      RECT  70.77 91.915 70.23 91.535 ;
      RECT  71.7 93.185 70.77 92.635 ;
      RECT  71.91 91.295 71.7 91.055 ;
      RECT  68.79 91.295 68.58 91.055 ;
      RECT  71.7 91.295 69.3 91.055 ;
      RECT  69.51 92.155 69.3 92.085 ;
      RECT  68.79 91.915 68.58 91.535 ;
      RECT  69.51 91.365 69.3 91.295 ;
      RECT  69.3 92.155 69.1 92.085 ;
      RECT  71.7 92.395 69.3 92.155 ;
      RECT  68.79 92.395 68.58 92.155 ;
      RECT  70.77 93.185 70.23 92.635 ;
      RECT  71.91 91.915 70.77 91.535 ;
      RECT  71.91 93.185 71.7 92.635 ;
      POLYGON  68.93 91.915 68.93 91.845 69.3 91.845 69.3 91.605 68.93 91.605 68.93 91.535 68.79 91.535 68.79 91.915 68.93 91.915 ;
      RECT  69.3 92.395 68.79 92.155 ;
      RECT  70.23 93.185 68.58 92.635 ;
      POLYGON  70.23 91.915 70.23 91.535 69.68 91.535 69.68 91.605 69.3 91.605 69.3 91.845 69.68 91.845 69.68 91.915 70.23 91.915 ;
      RECT  71.91 92.395 71.7 92.155 ;
      RECT  65.46 62.925 71.7 63.165 ;
      RECT  65.46 61.825 71.7 62.065 ;
      RECT  65.46 63.405 71.7 63.645 ;
      RECT  65.46 64.505 71.7 64.745 ;
      RECT  65.46 66.875 71.7 67.115 ;
      RECT  65.46 65.775 71.7 66.015 ;
      RECT  65.46 67.355 71.7 67.595 ;
      RECT  65.46 68.455 71.7 68.695 ;
      RECT  65.46 70.825 71.7 71.065 ;
      RECT  65.46 69.725 71.7 69.965 ;
      RECT  65.46 71.305 71.7 71.545 ;
      RECT  65.46 72.405 71.7 72.645 ;
      RECT  65.46 74.775 71.7 75.015 ;
      RECT  65.46 73.675 71.7 73.915 ;
      RECT  65.46 75.255 71.7 75.495 ;
      RECT  65.46 76.355 71.7 76.595 ;
      RECT  65.46 78.725 71.7 78.965 ;
      RECT  65.46 77.625 71.7 77.865 ;
      RECT  65.46 79.205 71.7 79.445 ;
      RECT  65.46 80.305 71.7 80.545 ;
      RECT  65.46 82.675 71.7 82.915 ;
      RECT  65.46 81.575 71.7 81.815 ;
      RECT  65.46 83.155 71.7 83.395 ;
      RECT  65.46 84.255 71.7 84.495 ;
      RECT  65.46 86.625 71.7 86.865 ;
      RECT  65.46 85.525 71.7 85.765 ;
      RECT  65.46 87.105 71.7 87.345 ;
      RECT  65.46 88.205 71.7 88.445 ;
      RECT  65.46 90.575 71.7 90.815 ;
      RECT  65.46 89.475 71.7 89.715 ;
      RECT  65.46 91.055 71.7 91.295 ;
      RECT  65.46 92.155 71.7 92.395 ;
      RECT  70.23 92.635 70.77 93.185 ;
      RECT  70.23 74.155 70.77 74.535 ;
      RECT  66.39 75.735 66.93 76.115 ;
      RECT  70.23 87.585 70.77 87.965 ;
      RECT  66.39 83.635 66.93 84.015 ;
      RECT  70.23 89.955 70.77 90.335 ;
      RECT  70.23 64.985 70.77 65.535 ;
      RECT  66.39 89.955 66.93 90.335 ;
      RECT  66.39 82.055 66.93 82.435 ;
      RECT  66.39 79.685 66.93 80.065 ;
      RECT  70.23 83.635 70.77 84.015 ;
      RECT  66.39 72.885 66.93 73.435 ;
      RECT  70.23 80.785 70.77 81.335 ;
      RECT  70.23 62.305 70.77 62.685 ;
      RECT  66.39 86.005 66.93 86.385 ;
      RECT  70.23 91.535 70.77 91.915 ;
      RECT  70.23 84.735 70.77 85.285 ;
      RECT  70.23 72.885 70.77 73.435 ;
      RECT  66.39 71.785 66.93 72.165 ;
      RECT  66.39 76.835 66.93 77.385 ;
      RECT  66.39 63.885 66.93 64.265 ;
      RECT  70.23 66.255 70.77 66.635 ;
      RECT  70.23 88.685 70.77 89.235 ;
      RECT  66.39 62.305 66.93 62.685 ;
      RECT  70.23 79.685 70.77 80.065 ;
      RECT  66.39 91.535 66.93 91.915 ;
      RECT  70.23 63.885 70.77 64.265 ;
      RECT  66.39 70.205 66.93 70.585 ;
      RECT  70.23 61.035 70.77 61.585 ;
      RECT  70.23 76.835 70.77 77.385 ;
      RECT  70.23 71.785 70.77 72.165 ;
      RECT  70.23 75.735 70.77 76.115 ;
      RECT  66.39 92.635 66.93 93.185 ;
      RECT  66.39 64.985 66.93 65.535 ;
      RECT  66.39 84.735 66.93 85.285 ;
      RECT  70.23 82.055 70.77 82.435 ;
      RECT  70.23 68.935 70.77 69.485 ;
      RECT  70.23 67.835 70.77 68.215 ;
      RECT  66.39 78.105 66.93 78.485 ;
      RECT  70.23 78.105 70.77 78.485 ;
      RECT  66.39 87.585 66.93 87.965 ;
      RECT  66.39 67.835 66.93 68.215 ;
      RECT  66.39 68.935 66.93 69.485 ;
      RECT  66.39 80.785 66.93 81.335 ;
      RECT  70.23 86.005 70.77 86.385 ;
      RECT  66.39 88.685 66.93 89.235 ;
      RECT  66.39 61.035 66.93 61.585 ;
      RECT  66.39 66.255 66.93 66.635 ;
      RECT  70.23 70.205 70.77 70.585 ;
      RECT  66.39 74.155 66.93 74.535 ;
      RECT  65.46 58.23 62.34 58.78 ;
      RECT  63.06 59.695 62.55 59.455 ;
      RECT  63.06 59.765 62.86 59.695 ;
      RECT  64.53 60.315 63.99 59.935 ;
      RECT  65.46 61.585 64.53 61.035 ;
      RECT  65.67 59.695 65.46 59.455 ;
      RECT  62.55 59.695 62.34 59.455 ;
      RECT  65.46 59.695 63.06 59.455 ;
      RECT  63.27 60.555 63.06 60.485 ;
      RECT  62.55 60.315 62.34 59.935 ;
      RECT  63.27 59.765 63.06 59.695 ;
      RECT  63.06 60.555 62.86 60.485 ;
      RECT  65.46 60.795 63.06 60.555 ;
      RECT  62.55 60.795 62.34 60.555 ;
      RECT  64.53 61.585 63.99 61.035 ;
      RECT  65.67 60.315 64.53 59.935 ;
      RECT  65.67 61.585 65.46 61.035 ;
      POLYGON  62.69 60.315 62.69 60.245 63.06 60.245 63.06 60.005 62.69 60.005 62.69 59.935 62.55 59.935 62.55 60.315 62.69 60.315 ;
      RECT  63.06 60.795 62.55 60.555 ;
      RECT  63.99 61.585 62.34 61.035 ;
      POLYGON  63.99 60.315 63.99 59.935 63.44 59.935 63.44 60.005 63.06 60.005 63.06 60.245 63.44 60.245 63.44 60.315 63.99 60.315 ;
      RECT  65.67 60.795 65.46 60.555 ;
      RECT  63.06 62.925 62.55 63.165 ;
      RECT  63.06 62.855 62.86 62.925 ;
      RECT  64.53 62.305 63.99 62.685 ;
      RECT  65.46 61.035 64.53 61.585 ;
      RECT  65.67 62.925 65.46 63.165 ;
      RECT  62.55 62.925 62.34 63.165 ;
      RECT  65.46 62.925 63.06 63.165 ;
      RECT  63.27 62.065 63.06 62.135 ;
      RECT  62.55 62.305 62.34 62.685 ;
      RECT  63.27 62.855 63.06 62.925 ;
      RECT  63.06 62.065 62.86 62.135 ;
      RECT  65.46 61.825 63.06 62.065 ;
      RECT  62.55 61.825 62.34 62.065 ;
      RECT  64.53 61.035 63.99 61.585 ;
      RECT  65.67 62.305 64.53 62.685 ;
      RECT  65.67 61.035 65.46 61.585 ;
      POLYGON  62.69 62.305 62.69 62.375 63.06 62.375 63.06 62.615 62.69 62.615 62.69 62.685 62.55 62.685 62.55 62.305 62.69 62.305 ;
      RECT  63.06 61.825 62.55 62.065 ;
      RECT  63.99 61.035 62.34 61.585 ;
      POLYGON  63.99 62.305 63.99 62.685 63.44 62.685 63.44 62.615 63.06 62.615 63.06 62.375 63.44 62.375 63.44 62.305 63.99 62.305 ;
      RECT  65.67 61.825 65.46 62.065 ;
      RECT  63.06 63.645 62.55 63.405 ;
      RECT  63.06 63.715 62.86 63.645 ;
      RECT  64.53 64.265 63.99 63.885 ;
      RECT  65.46 65.535 64.53 64.985 ;
      RECT  65.67 63.645 65.46 63.405 ;
      RECT  62.55 63.645 62.34 63.405 ;
      RECT  65.46 63.645 63.06 63.405 ;
      RECT  63.27 64.505 63.06 64.435 ;
      RECT  62.55 64.265 62.34 63.885 ;
      RECT  63.27 63.715 63.06 63.645 ;
      RECT  63.06 64.505 62.86 64.435 ;
      RECT  65.46 64.745 63.06 64.505 ;
      RECT  62.55 64.745 62.34 64.505 ;
      RECT  64.53 65.535 63.99 64.985 ;
      RECT  65.67 64.265 64.53 63.885 ;
      RECT  65.67 65.535 65.46 64.985 ;
      POLYGON  62.69 64.265 62.69 64.195 63.06 64.195 63.06 63.955 62.69 63.955 62.69 63.885 62.55 63.885 62.55 64.265 62.69 64.265 ;
      RECT  63.06 64.745 62.55 64.505 ;
      RECT  63.99 65.535 62.34 64.985 ;
      POLYGON  63.99 64.265 63.99 63.885 63.44 63.885 63.44 63.955 63.06 63.955 63.06 64.195 63.44 64.195 63.44 64.265 63.99 64.265 ;
      RECT  65.67 64.745 65.46 64.505 ;
      RECT  63.06 66.875 62.55 67.115 ;
      RECT  63.06 66.805 62.86 66.875 ;
      RECT  64.53 66.255 63.99 66.635 ;
      RECT  65.46 64.985 64.53 65.535 ;
      RECT  65.67 66.875 65.46 67.115 ;
      RECT  62.55 66.875 62.34 67.115 ;
      RECT  65.46 66.875 63.06 67.115 ;
      RECT  63.27 66.015 63.06 66.085 ;
      RECT  62.55 66.255 62.34 66.635 ;
      RECT  63.27 66.805 63.06 66.875 ;
      RECT  63.06 66.015 62.86 66.085 ;
      RECT  65.46 65.775 63.06 66.015 ;
      RECT  62.55 65.775 62.34 66.015 ;
      RECT  64.53 64.985 63.99 65.535 ;
      RECT  65.67 66.255 64.53 66.635 ;
      RECT  65.67 64.985 65.46 65.535 ;
      POLYGON  62.69 66.255 62.69 66.325 63.06 66.325 63.06 66.565 62.69 66.565 62.69 66.635 62.55 66.635 62.55 66.255 62.69 66.255 ;
      RECT  63.06 65.775 62.55 66.015 ;
      RECT  63.99 64.985 62.34 65.535 ;
      POLYGON  63.99 66.255 63.99 66.635 63.44 66.635 63.44 66.565 63.06 66.565 63.06 66.325 63.44 66.325 63.44 66.255 63.99 66.255 ;
      RECT  65.67 65.775 65.46 66.015 ;
      RECT  63.06 67.595 62.55 67.355 ;
      RECT  63.06 67.665 62.86 67.595 ;
      RECT  64.53 68.215 63.99 67.835 ;
      RECT  65.46 69.485 64.53 68.935 ;
      RECT  65.67 67.595 65.46 67.355 ;
      RECT  62.55 67.595 62.34 67.355 ;
      RECT  65.46 67.595 63.06 67.355 ;
      RECT  63.27 68.455 63.06 68.385 ;
      RECT  62.55 68.215 62.34 67.835 ;
      RECT  63.27 67.665 63.06 67.595 ;
      RECT  63.06 68.455 62.86 68.385 ;
      RECT  65.46 68.695 63.06 68.455 ;
      RECT  62.55 68.695 62.34 68.455 ;
      RECT  64.53 69.485 63.99 68.935 ;
      RECT  65.67 68.215 64.53 67.835 ;
      RECT  65.67 69.485 65.46 68.935 ;
      POLYGON  62.69 68.215 62.69 68.145 63.06 68.145 63.06 67.905 62.69 67.905 62.69 67.835 62.55 67.835 62.55 68.215 62.69 68.215 ;
      RECT  63.06 68.695 62.55 68.455 ;
      RECT  63.99 69.485 62.34 68.935 ;
      POLYGON  63.99 68.215 63.99 67.835 63.44 67.835 63.44 67.905 63.06 67.905 63.06 68.145 63.44 68.145 63.44 68.215 63.99 68.215 ;
      RECT  65.67 68.695 65.46 68.455 ;
      RECT  63.06 70.825 62.55 71.065 ;
      RECT  63.06 70.755 62.86 70.825 ;
      RECT  64.53 70.205 63.99 70.585 ;
      RECT  65.46 68.935 64.53 69.485 ;
      RECT  65.67 70.825 65.46 71.065 ;
      RECT  62.55 70.825 62.34 71.065 ;
      RECT  65.46 70.825 63.06 71.065 ;
      RECT  63.27 69.965 63.06 70.035 ;
      RECT  62.55 70.205 62.34 70.585 ;
      RECT  63.27 70.755 63.06 70.825 ;
      RECT  63.06 69.965 62.86 70.035 ;
      RECT  65.46 69.725 63.06 69.965 ;
      RECT  62.55 69.725 62.34 69.965 ;
      RECT  64.53 68.935 63.99 69.485 ;
      RECT  65.67 70.205 64.53 70.585 ;
      RECT  65.67 68.935 65.46 69.485 ;
      POLYGON  62.69 70.205 62.69 70.275 63.06 70.275 63.06 70.515 62.69 70.515 62.69 70.585 62.55 70.585 62.55 70.205 62.69 70.205 ;
      RECT  63.06 69.725 62.55 69.965 ;
      RECT  63.99 68.935 62.34 69.485 ;
      POLYGON  63.99 70.205 63.99 70.585 63.44 70.585 63.44 70.515 63.06 70.515 63.06 70.275 63.44 70.275 63.44 70.205 63.99 70.205 ;
      RECT  65.67 69.725 65.46 69.965 ;
      RECT  63.06 71.545 62.55 71.305 ;
      RECT  63.06 71.615 62.86 71.545 ;
      RECT  64.53 72.165 63.99 71.785 ;
      RECT  65.46 73.435 64.53 72.885 ;
      RECT  65.67 71.545 65.46 71.305 ;
      RECT  62.55 71.545 62.34 71.305 ;
      RECT  65.46 71.545 63.06 71.305 ;
      RECT  63.27 72.405 63.06 72.335 ;
      RECT  62.55 72.165 62.34 71.785 ;
      RECT  63.27 71.615 63.06 71.545 ;
      RECT  63.06 72.405 62.86 72.335 ;
      RECT  65.46 72.645 63.06 72.405 ;
      RECT  62.55 72.645 62.34 72.405 ;
      RECT  64.53 73.435 63.99 72.885 ;
      RECT  65.67 72.165 64.53 71.785 ;
      RECT  65.67 73.435 65.46 72.885 ;
      POLYGON  62.69 72.165 62.69 72.095 63.06 72.095 63.06 71.855 62.69 71.855 62.69 71.785 62.55 71.785 62.55 72.165 62.69 72.165 ;
      RECT  63.06 72.645 62.55 72.405 ;
      RECT  63.99 73.435 62.34 72.885 ;
      POLYGON  63.99 72.165 63.99 71.785 63.44 71.785 63.44 71.855 63.06 71.855 63.06 72.095 63.44 72.095 63.44 72.165 63.99 72.165 ;
      RECT  65.67 72.645 65.46 72.405 ;
      RECT  63.06 74.775 62.55 75.015 ;
      RECT  63.06 74.705 62.86 74.775 ;
      RECT  64.53 74.155 63.99 74.535 ;
      RECT  65.46 72.885 64.53 73.435 ;
      RECT  65.67 74.775 65.46 75.015 ;
      RECT  62.55 74.775 62.34 75.015 ;
      RECT  65.46 74.775 63.06 75.015 ;
      RECT  63.27 73.915 63.06 73.985 ;
      RECT  62.55 74.155 62.34 74.535 ;
      RECT  63.27 74.705 63.06 74.775 ;
      RECT  63.06 73.915 62.86 73.985 ;
      RECT  65.46 73.675 63.06 73.915 ;
      RECT  62.55 73.675 62.34 73.915 ;
      RECT  64.53 72.885 63.99 73.435 ;
      RECT  65.67 74.155 64.53 74.535 ;
      RECT  65.67 72.885 65.46 73.435 ;
      POLYGON  62.69 74.155 62.69 74.225 63.06 74.225 63.06 74.465 62.69 74.465 62.69 74.535 62.55 74.535 62.55 74.155 62.69 74.155 ;
      RECT  63.06 73.675 62.55 73.915 ;
      RECT  63.99 72.885 62.34 73.435 ;
      POLYGON  63.99 74.155 63.99 74.535 63.44 74.535 63.44 74.465 63.06 74.465 63.06 74.225 63.44 74.225 63.44 74.155 63.99 74.155 ;
      RECT  65.67 73.675 65.46 73.915 ;
      RECT  63.06 75.495 62.55 75.255 ;
      RECT  63.06 75.565 62.86 75.495 ;
      RECT  64.53 76.115 63.99 75.735 ;
      RECT  65.46 77.385 64.53 76.835 ;
      RECT  65.67 75.495 65.46 75.255 ;
      RECT  62.55 75.495 62.34 75.255 ;
      RECT  65.46 75.495 63.06 75.255 ;
      RECT  63.27 76.355 63.06 76.285 ;
      RECT  62.55 76.115 62.34 75.735 ;
      RECT  63.27 75.565 63.06 75.495 ;
      RECT  63.06 76.355 62.86 76.285 ;
      RECT  65.46 76.595 63.06 76.355 ;
      RECT  62.55 76.595 62.34 76.355 ;
      RECT  64.53 77.385 63.99 76.835 ;
      RECT  65.67 76.115 64.53 75.735 ;
      RECT  65.67 77.385 65.46 76.835 ;
      POLYGON  62.69 76.115 62.69 76.045 63.06 76.045 63.06 75.805 62.69 75.805 62.69 75.735 62.55 75.735 62.55 76.115 62.69 76.115 ;
      RECT  63.06 76.595 62.55 76.355 ;
      RECT  63.99 77.385 62.34 76.835 ;
      POLYGON  63.99 76.115 63.99 75.735 63.44 75.735 63.44 75.805 63.06 75.805 63.06 76.045 63.44 76.045 63.44 76.115 63.99 76.115 ;
      RECT  65.67 76.595 65.46 76.355 ;
      RECT  63.06 78.725 62.55 78.965 ;
      RECT  63.06 78.655 62.86 78.725 ;
      RECT  64.53 78.105 63.99 78.485 ;
      RECT  65.46 76.835 64.53 77.385 ;
      RECT  65.67 78.725 65.46 78.965 ;
      RECT  62.55 78.725 62.34 78.965 ;
      RECT  65.46 78.725 63.06 78.965 ;
      RECT  63.27 77.865 63.06 77.935 ;
      RECT  62.55 78.105 62.34 78.485 ;
      RECT  63.27 78.655 63.06 78.725 ;
      RECT  63.06 77.865 62.86 77.935 ;
      RECT  65.46 77.625 63.06 77.865 ;
      RECT  62.55 77.625 62.34 77.865 ;
      RECT  64.53 76.835 63.99 77.385 ;
      RECT  65.67 78.105 64.53 78.485 ;
      RECT  65.67 76.835 65.46 77.385 ;
      POLYGON  62.69 78.105 62.69 78.175 63.06 78.175 63.06 78.415 62.69 78.415 62.69 78.485 62.55 78.485 62.55 78.105 62.69 78.105 ;
      RECT  63.06 77.625 62.55 77.865 ;
      RECT  63.99 76.835 62.34 77.385 ;
      POLYGON  63.99 78.105 63.99 78.485 63.44 78.485 63.44 78.415 63.06 78.415 63.06 78.175 63.44 78.175 63.44 78.105 63.99 78.105 ;
      RECT  65.67 77.625 65.46 77.865 ;
      RECT  63.06 79.445 62.55 79.205 ;
      RECT  63.06 79.515 62.86 79.445 ;
      RECT  64.53 80.065 63.99 79.685 ;
      RECT  65.46 81.335 64.53 80.785 ;
      RECT  65.67 79.445 65.46 79.205 ;
      RECT  62.55 79.445 62.34 79.205 ;
      RECT  65.46 79.445 63.06 79.205 ;
      RECT  63.27 80.305 63.06 80.235 ;
      RECT  62.55 80.065 62.34 79.685 ;
      RECT  63.27 79.515 63.06 79.445 ;
      RECT  63.06 80.305 62.86 80.235 ;
      RECT  65.46 80.545 63.06 80.305 ;
      RECT  62.55 80.545 62.34 80.305 ;
      RECT  64.53 81.335 63.99 80.785 ;
      RECT  65.67 80.065 64.53 79.685 ;
      RECT  65.67 81.335 65.46 80.785 ;
      POLYGON  62.69 80.065 62.69 79.995 63.06 79.995 63.06 79.755 62.69 79.755 62.69 79.685 62.55 79.685 62.55 80.065 62.69 80.065 ;
      RECT  63.06 80.545 62.55 80.305 ;
      RECT  63.99 81.335 62.34 80.785 ;
      POLYGON  63.99 80.065 63.99 79.685 63.44 79.685 63.44 79.755 63.06 79.755 63.06 79.995 63.44 79.995 63.44 80.065 63.99 80.065 ;
      RECT  65.67 80.545 65.46 80.305 ;
      RECT  63.06 82.675 62.55 82.915 ;
      RECT  63.06 82.605 62.86 82.675 ;
      RECT  64.53 82.055 63.99 82.435 ;
      RECT  65.46 80.785 64.53 81.335 ;
      RECT  65.67 82.675 65.46 82.915 ;
      RECT  62.55 82.675 62.34 82.915 ;
      RECT  65.46 82.675 63.06 82.915 ;
      RECT  63.27 81.815 63.06 81.885 ;
      RECT  62.55 82.055 62.34 82.435 ;
      RECT  63.27 82.605 63.06 82.675 ;
      RECT  63.06 81.815 62.86 81.885 ;
      RECT  65.46 81.575 63.06 81.815 ;
      RECT  62.55 81.575 62.34 81.815 ;
      RECT  64.53 80.785 63.99 81.335 ;
      RECT  65.67 82.055 64.53 82.435 ;
      RECT  65.67 80.785 65.46 81.335 ;
      POLYGON  62.69 82.055 62.69 82.125 63.06 82.125 63.06 82.365 62.69 82.365 62.69 82.435 62.55 82.435 62.55 82.055 62.69 82.055 ;
      RECT  63.06 81.575 62.55 81.815 ;
      RECT  63.99 80.785 62.34 81.335 ;
      POLYGON  63.99 82.055 63.99 82.435 63.44 82.435 63.44 82.365 63.06 82.365 63.06 82.125 63.44 82.125 63.44 82.055 63.99 82.055 ;
      RECT  65.67 81.575 65.46 81.815 ;
      RECT  63.06 83.395 62.55 83.155 ;
      RECT  63.06 83.465 62.86 83.395 ;
      RECT  64.53 84.015 63.99 83.635 ;
      RECT  65.46 85.285 64.53 84.735 ;
      RECT  65.67 83.395 65.46 83.155 ;
      RECT  62.55 83.395 62.34 83.155 ;
      RECT  65.46 83.395 63.06 83.155 ;
      RECT  63.27 84.255 63.06 84.185 ;
      RECT  62.55 84.015 62.34 83.635 ;
      RECT  63.27 83.465 63.06 83.395 ;
      RECT  63.06 84.255 62.86 84.185 ;
      RECT  65.46 84.495 63.06 84.255 ;
      RECT  62.55 84.495 62.34 84.255 ;
      RECT  64.53 85.285 63.99 84.735 ;
      RECT  65.67 84.015 64.53 83.635 ;
      RECT  65.67 85.285 65.46 84.735 ;
      POLYGON  62.69 84.015 62.69 83.945 63.06 83.945 63.06 83.705 62.69 83.705 62.69 83.635 62.55 83.635 62.55 84.015 62.69 84.015 ;
      RECT  63.06 84.495 62.55 84.255 ;
      RECT  63.99 85.285 62.34 84.735 ;
      POLYGON  63.99 84.015 63.99 83.635 63.44 83.635 63.44 83.705 63.06 83.705 63.06 83.945 63.44 83.945 63.44 84.015 63.99 84.015 ;
      RECT  65.67 84.495 65.46 84.255 ;
      RECT  63.06 86.625 62.55 86.865 ;
      RECT  63.06 86.555 62.86 86.625 ;
      RECT  64.53 86.005 63.99 86.385 ;
      RECT  65.46 84.735 64.53 85.285 ;
      RECT  65.67 86.625 65.46 86.865 ;
      RECT  62.55 86.625 62.34 86.865 ;
      RECT  65.46 86.625 63.06 86.865 ;
      RECT  63.27 85.765 63.06 85.835 ;
      RECT  62.55 86.005 62.34 86.385 ;
      RECT  63.27 86.555 63.06 86.625 ;
      RECT  63.06 85.765 62.86 85.835 ;
      RECT  65.46 85.525 63.06 85.765 ;
      RECT  62.55 85.525 62.34 85.765 ;
      RECT  64.53 84.735 63.99 85.285 ;
      RECT  65.67 86.005 64.53 86.385 ;
      RECT  65.67 84.735 65.46 85.285 ;
      POLYGON  62.69 86.005 62.69 86.075 63.06 86.075 63.06 86.315 62.69 86.315 62.69 86.385 62.55 86.385 62.55 86.005 62.69 86.005 ;
      RECT  63.06 85.525 62.55 85.765 ;
      RECT  63.99 84.735 62.34 85.285 ;
      POLYGON  63.99 86.005 63.99 86.385 63.44 86.385 63.44 86.315 63.06 86.315 63.06 86.075 63.44 86.075 63.44 86.005 63.99 86.005 ;
      RECT  65.67 85.525 65.46 85.765 ;
      RECT  63.06 87.345 62.55 87.105 ;
      RECT  63.06 87.415 62.86 87.345 ;
      RECT  64.53 87.965 63.99 87.585 ;
      RECT  65.46 89.235 64.53 88.685 ;
      RECT  65.67 87.345 65.46 87.105 ;
      RECT  62.55 87.345 62.34 87.105 ;
      RECT  65.46 87.345 63.06 87.105 ;
      RECT  63.27 88.205 63.06 88.135 ;
      RECT  62.55 87.965 62.34 87.585 ;
      RECT  63.27 87.415 63.06 87.345 ;
      RECT  63.06 88.205 62.86 88.135 ;
      RECT  65.46 88.445 63.06 88.205 ;
      RECT  62.55 88.445 62.34 88.205 ;
      RECT  64.53 89.235 63.99 88.685 ;
      RECT  65.67 87.965 64.53 87.585 ;
      RECT  65.67 89.235 65.46 88.685 ;
      POLYGON  62.69 87.965 62.69 87.895 63.06 87.895 63.06 87.655 62.69 87.655 62.69 87.585 62.55 87.585 62.55 87.965 62.69 87.965 ;
      RECT  63.06 88.445 62.55 88.205 ;
      RECT  63.99 89.235 62.34 88.685 ;
      POLYGON  63.99 87.965 63.99 87.585 63.44 87.585 63.44 87.655 63.06 87.655 63.06 87.895 63.44 87.895 63.44 87.965 63.99 87.965 ;
      RECT  65.67 88.445 65.46 88.205 ;
      RECT  63.06 90.575 62.55 90.815 ;
      RECT  63.06 90.505 62.86 90.575 ;
      RECT  64.53 89.955 63.99 90.335 ;
      RECT  65.46 88.685 64.53 89.235 ;
      RECT  65.67 90.575 65.46 90.815 ;
      RECT  62.55 90.575 62.34 90.815 ;
      RECT  65.46 90.575 63.06 90.815 ;
      RECT  63.27 89.715 63.06 89.785 ;
      RECT  62.55 89.955 62.34 90.335 ;
      RECT  63.27 90.505 63.06 90.575 ;
      RECT  63.06 89.715 62.86 89.785 ;
      RECT  65.46 89.475 63.06 89.715 ;
      RECT  62.55 89.475 62.34 89.715 ;
      RECT  64.53 88.685 63.99 89.235 ;
      RECT  65.67 89.955 64.53 90.335 ;
      RECT  65.67 88.685 65.46 89.235 ;
      POLYGON  62.69 89.955 62.69 90.025 63.06 90.025 63.06 90.265 62.69 90.265 62.69 90.335 62.55 90.335 62.55 89.955 62.69 89.955 ;
      RECT  63.06 89.475 62.55 89.715 ;
      RECT  63.99 88.685 62.34 89.235 ;
      POLYGON  63.99 89.955 63.99 90.335 63.44 90.335 63.44 90.265 63.06 90.265 63.06 90.025 63.44 90.025 63.44 89.955 63.99 89.955 ;
      RECT  65.67 89.475 65.46 89.715 ;
      RECT  63.06 91.295 62.55 91.055 ;
      RECT  63.06 91.365 62.86 91.295 ;
      RECT  64.53 91.915 63.99 91.535 ;
      RECT  65.46 93.185 64.53 92.635 ;
      RECT  65.67 91.295 65.46 91.055 ;
      RECT  62.55 91.295 62.34 91.055 ;
      RECT  65.46 91.295 63.06 91.055 ;
      RECT  63.27 92.155 63.06 92.085 ;
      RECT  62.55 91.915 62.34 91.535 ;
      RECT  63.27 91.365 63.06 91.295 ;
      RECT  63.06 92.155 62.86 92.085 ;
      RECT  65.46 92.395 63.06 92.155 ;
      RECT  62.55 92.395 62.34 92.155 ;
      RECT  64.53 93.185 63.99 92.635 ;
      RECT  65.67 91.915 64.53 91.535 ;
      RECT  65.67 93.185 65.46 92.635 ;
      POLYGON  62.69 91.915 62.69 91.845 63.06 91.845 63.06 91.605 62.69 91.605 62.69 91.535 62.55 91.535 62.55 91.915 62.69 91.915 ;
      RECT  63.06 92.395 62.55 92.155 ;
      RECT  63.99 93.185 62.34 92.635 ;
      POLYGON  63.99 91.915 63.99 91.535 63.44 91.535 63.44 91.605 63.06 91.605 63.06 91.845 63.44 91.845 63.44 91.915 63.99 91.915 ;
      RECT  65.67 92.395 65.46 92.155 ;
      RECT  63.06 94.525 62.55 94.765 ;
      RECT  63.06 94.455 62.86 94.525 ;
      RECT  64.53 93.905 63.99 94.285 ;
      RECT  65.46 92.635 64.53 93.185 ;
      RECT  65.67 94.525 65.46 94.765 ;
      RECT  62.55 94.525 62.34 94.765 ;
      RECT  65.46 94.525 63.06 94.765 ;
      RECT  63.27 93.665 63.06 93.735 ;
      RECT  62.55 93.905 62.34 94.285 ;
      RECT  63.27 94.455 63.06 94.525 ;
      RECT  63.06 93.665 62.86 93.735 ;
      RECT  65.46 93.425 63.06 93.665 ;
      RECT  62.55 93.425 62.34 93.665 ;
      RECT  64.53 92.635 63.99 93.185 ;
      RECT  65.67 93.905 64.53 94.285 ;
      RECT  65.67 92.635 65.46 93.185 ;
      POLYGON  62.69 93.905 62.69 93.975 63.06 93.975 63.06 94.215 62.69 94.215 62.69 94.285 62.55 94.285 62.55 93.905 62.69 93.905 ;
      RECT  63.06 93.425 62.55 93.665 ;
      RECT  63.99 92.635 62.34 93.185 ;
      POLYGON  63.99 93.905 63.99 94.285 63.44 94.285 63.44 94.215 63.06 94.215 63.06 93.975 63.44 93.975 63.44 93.905 63.99 93.905 ;
      RECT  65.67 93.425 65.46 93.665 ;
      RECT  65.46 95.99 62.34 95.44 ;
      RECT  62.34 59.455 65.46 59.695 ;
      RECT  62.34 60.555 65.46 60.795 ;
      RECT  62.34 62.925 65.46 63.165 ;
      RECT  62.34 61.825 65.46 62.065 ;
      RECT  62.34 63.405 65.46 63.645 ;
      RECT  62.34 64.505 65.46 64.745 ;
      RECT  62.34 66.875 65.46 67.115 ;
      RECT  62.34 65.775 65.46 66.015 ;
      RECT  62.34 67.355 65.46 67.595 ;
      RECT  62.34 68.455 65.46 68.695 ;
      RECT  62.34 70.825 65.46 71.065 ;
      RECT  62.34 69.725 65.46 69.965 ;
      RECT  62.34 71.305 65.46 71.545 ;
      RECT  62.34 72.405 65.46 72.645 ;
      RECT  62.34 74.775 65.46 75.015 ;
      RECT  62.34 73.675 65.46 73.915 ;
      RECT  62.34 75.255 65.46 75.495 ;
      RECT  62.34 76.355 65.46 76.595 ;
      RECT  62.34 78.725 65.46 78.965 ;
      RECT  62.34 77.625 65.46 77.865 ;
      RECT  62.34 79.205 65.46 79.445 ;
      RECT  62.34 80.305 65.46 80.545 ;
      RECT  62.34 82.675 65.46 82.915 ;
      RECT  62.34 81.575 65.46 81.815 ;
      RECT  62.34 83.155 65.46 83.395 ;
      RECT  62.34 84.255 65.46 84.495 ;
      RECT  62.34 86.625 65.46 86.865 ;
      RECT  62.34 85.525 65.46 85.765 ;
      RECT  62.34 87.105 65.46 87.345 ;
      RECT  62.34 88.205 65.46 88.445 ;
      RECT  62.34 90.575 65.46 90.815 ;
      RECT  62.34 89.475 65.46 89.715 ;
      RECT  62.34 91.055 65.46 91.295 ;
      RECT  62.34 92.155 65.46 92.395 ;
      RECT  62.34 94.525 65.46 94.765 ;
      RECT  62.34 93.425 65.46 93.665 ;
      RECT  63.99 87.585 64.53 87.965 ;
      RECT  63.99 61.035 64.53 61.585 ;
      RECT  63.99 86.005 64.53 86.385 ;
      RECT  63.99 70.205 64.53 70.585 ;
      RECT  63.99 89.955 64.53 90.335 ;
      RECT  63.99 83.635 64.53 84.015 ;
      RECT  63.99 74.155 64.53 74.535 ;
      RECT  63.99 82.055 64.53 82.435 ;
      RECT  63.99 64.985 64.53 65.535 ;
      RECT  63.99 78.105 64.53 78.485 ;
      RECT  63.99 68.935 64.53 69.485 ;
      RECT  63.99 66.255 64.53 66.635 ;
      RECT  63.99 63.885 64.53 64.265 ;
      RECT  63.99 67.835 64.53 68.215 ;
      RECT  63.99 59.935 64.53 60.315 ;
      RECT  63.99 92.635 64.53 93.185 ;
      RECT  63.99 62.305 64.53 62.685 ;
      RECT  63.99 93.905 64.53 94.285 ;
      RECT  63.99 71.785 64.53 72.165 ;
      RECT  63.99 76.835 64.53 77.385 ;
      RECT  63.99 75.735 64.53 76.115 ;
      RECT  63.99 72.885 64.53 73.435 ;
      RECT  63.99 79.685 64.53 80.065 ;
      RECT  63.99 84.735 64.53 85.285 ;
      RECT  63.99 80.785 64.53 81.335 ;
      RECT  63.99 91.535 64.53 91.915 ;
      RECT  63.99 88.685 64.53 89.235 ;
      RECT  71.7 58.23 74.82 58.78 ;
      RECT  74.1 59.695 74.61 59.455 ;
      RECT  74.1 59.765 74.3 59.695 ;
      RECT  72.63 60.315 73.17 59.935 ;
      RECT  71.7 61.585 72.63 61.035 ;
      RECT  71.49 59.695 71.7 59.455 ;
      RECT  74.61 59.695 74.82 59.455 ;
      RECT  71.7 59.695 74.1 59.455 ;
      RECT  73.89 60.555 74.1 60.485 ;
      RECT  74.61 60.315 74.82 59.935 ;
      RECT  73.89 59.765 74.1 59.695 ;
      RECT  74.1 60.555 74.3 60.485 ;
      RECT  71.7 60.795 74.1 60.555 ;
      RECT  74.61 60.795 74.82 60.555 ;
      RECT  72.63 61.585 73.17 61.035 ;
      RECT  71.49 60.315 72.63 59.935 ;
      RECT  71.49 61.585 71.7 61.035 ;
      POLYGON  74.47 60.315 74.47 60.245 74.1 60.245 74.1 60.005 74.47 60.005 74.47 59.935 74.61 59.935 74.61 60.315 74.47 60.315 ;
      RECT  74.1 60.795 74.61 60.555 ;
      RECT  73.17 61.585 74.82 61.035 ;
      POLYGON  73.17 60.315 73.17 59.935 73.72 59.935 73.72 60.005 74.1 60.005 74.1 60.245 73.72 60.245 73.72 60.315 73.17 60.315 ;
      RECT  71.49 60.795 71.7 60.555 ;
      RECT  74.1 62.925 74.61 63.165 ;
      RECT  74.1 62.855 74.3 62.925 ;
      RECT  72.63 62.305 73.17 62.685 ;
      RECT  71.7 61.035 72.63 61.585 ;
      RECT  71.49 62.925 71.7 63.165 ;
      RECT  74.61 62.925 74.82 63.165 ;
      RECT  71.7 62.925 74.1 63.165 ;
      RECT  73.89 62.065 74.1 62.135 ;
      RECT  74.61 62.305 74.82 62.685 ;
      RECT  73.89 62.855 74.1 62.925 ;
      RECT  74.1 62.065 74.3 62.135 ;
      RECT  71.7 61.825 74.1 62.065 ;
      RECT  74.61 61.825 74.82 62.065 ;
      RECT  72.63 61.035 73.17 61.585 ;
      RECT  71.49 62.305 72.63 62.685 ;
      RECT  71.49 61.035 71.7 61.585 ;
      POLYGON  74.47 62.305 74.47 62.375 74.1 62.375 74.1 62.615 74.47 62.615 74.47 62.685 74.61 62.685 74.61 62.305 74.47 62.305 ;
      RECT  74.1 61.825 74.61 62.065 ;
      RECT  73.17 61.035 74.82 61.585 ;
      POLYGON  73.17 62.305 73.17 62.685 73.72 62.685 73.72 62.615 74.1 62.615 74.1 62.375 73.72 62.375 73.72 62.305 73.17 62.305 ;
      RECT  71.49 61.825 71.7 62.065 ;
      RECT  74.1 63.645 74.61 63.405 ;
      RECT  74.1 63.715 74.3 63.645 ;
      RECT  72.63 64.265 73.17 63.885 ;
      RECT  71.7 65.535 72.63 64.985 ;
      RECT  71.49 63.645 71.7 63.405 ;
      RECT  74.61 63.645 74.82 63.405 ;
      RECT  71.7 63.645 74.1 63.405 ;
      RECT  73.89 64.505 74.1 64.435 ;
      RECT  74.61 64.265 74.82 63.885 ;
      RECT  73.89 63.715 74.1 63.645 ;
      RECT  74.1 64.505 74.3 64.435 ;
      RECT  71.7 64.745 74.1 64.505 ;
      RECT  74.61 64.745 74.82 64.505 ;
      RECT  72.63 65.535 73.17 64.985 ;
      RECT  71.49 64.265 72.63 63.885 ;
      RECT  71.49 65.535 71.7 64.985 ;
      POLYGON  74.47 64.265 74.47 64.195 74.1 64.195 74.1 63.955 74.47 63.955 74.47 63.885 74.61 63.885 74.61 64.265 74.47 64.265 ;
      RECT  74.1 64.745 74.61 64.505 ;
      RECT  73.17 65.535 74.82 64.985 ;
      POLYGON  73.17 64.265 73.17 63.885 73.72 63.885 73.72 63.955 74.1 63.955 74.1 64.195 73.72 64.195 73.72 64.265 73.17 64.265 ;
      RECT  71.49 64.745 71.7 64.505 ;
      RECT  74.1 66.875 74.61 67.115 ;
      RECT  74.1 66.805 74.3 66.875 ;
      RECT  72.63 66.255 73.17 66.635 ;
      RECT  71.7 64.985 72.63 65.535 ;
      RECT  71.49 66.875 71.7 67.115 ;
      RECT  74.61 66.875 74.82 67.115 ;
      RECT  71.7 66.875 74.1 67.115 ;
      RECT  73.89 66.015 74.1 66.085 ;
      RECT  74.61 66.255 74.82 66.635 ;
      RECT  73.89 66.805 74.1 66.875 ;
      RECT  74.1 66.015 74.3 66.085 ;
      RECT  71.7 65.775 74.1 66.015 ;
      RECT  74.61 65.775 74.82 66.015 ;
      RECT  72.63 64.985 73.17 65.535 ;
      RECT  71.49 66.255 72.63 66.635 ;
      RECT  71.49 64.985 71.7 65.535 ;
      POLYGON  74.47 66.255 74.47 66.325 74.1 66.325 74.1 66.565 74.47 66.565 74.47 66.635 74.61 66.635 74.61 66.255 74.47 66.255 ;
      RECT  74.1 65.775 74.61 66.015 ;
      RECT  73.17 64.985 74.82 65.535 ;
      POLYGON  73.17 66.255 73.17 66.635 73.72 66.635 73.72 66.565 74.1 66.565 74.1 66.325 73.72 66.325 73.72 66.255 73.17 66.255 ;
      RECT  71.49 65.775 71.7 66.015 ;
      RECT  74.1 67.595 74.61 67.355 ;
      RECT  74.1 67.665 74.3 67.595 ;
      RECT  72.63 68.215 73.17 67.835 ;
      RECT  71.7 69.485 72.63 68.935 ;
      RECT  71.49 67.595 71.7 67.355 ;
      RECT  74.61 67.595 74.82 67.355 ;
      RECT  71.7 67.595 74.1 67.355 ;
      RECT  73.89 68.455 74.1 68.385 ;
      RECT  74.61 68.215 74.82 67.835 ;
      RECT  73.89 67.665 74.1 67.595 ;
      RECT  74.1 68.455 74.3 68.385 ;
      RECT  71.7 68.695 74.1 68.455 ;
      RECT  74.61 68.695 74.82 68.455 ;
      RECT  72.63 69.485 73.17 68.935 ;
      RECT  71.49 68.215 72.63 67.835 ;
      RECT  71.49 69.485 71.7 68.935 ;
      POLYGON  74.47 68.215 74.47 68.145 74.1 68.145 74.1 67.905 74.47 67.905 74.47 67.835 74.61 67.835 74.61 68.215 74.47 68.215 ;
      RECT  74.1 68.695 74.61 68.455 ;
      RECT  73.17 69.485 74.82 68.935 ;
      POLYGON  73.17 68.215 73.17 67.835 73.72 67.835 73.72 67.905 74.1 67.905 74.1 68.145 73.72 68.145 73.72 68.215 73.17 68.215 ;
      RECT  71.49 68.695 71.7 68.455 ;
      RECT  74.1 70.825 74.61 71.065 ;
      RECT  74.1 70.755 74.3 70.825 ;
      RECT  72.63 70.205 73.17 70.585 ;
      RECT  71.7 68.935 72.63 69.485 ;
      RECT  71.49 70.825 71.7 71.065 ;
      RECT  74.61 70.825 74.82 71.065 ;
      RECT  71.7 70.825 74.1 71.065 ;
      RECT  73.89 69.965 74.1 70.035 ;
      RECT  74.61 70.205 74.82 70.585 ;
      RECT  73.89 70.755 74.1 70.825 ;
      RECT  74.1 69.965 74.3 70.035 ;
      RECT  71.7 69.725 74.1 69.965 ;
      RECT  74.61 69.725 74.82 69.965 ;
      RECT  72.63 68.935 73.17 69.485 ;
      RECT  71.49 70.205 72.63 70.585 ;
      RECT  71.49 68.935 71.7 69.485 ;
      POLYGON  74.47 70.205 74.47 70.275 74.1 70.275 74.1 70.515 74.47 70.515 74.47 70.585 74.61 70.585 74.61 70.205 74.47 70.205 ;
      RECT  74.1 69.725 74.61 69.965 ;
      RECT  73.17 68.935 74.82 69.485 ;
      POLYGON  73.17 70.205 73.17 70.585 73.72 70.585 73.72 70.515 74.1 70.515 74.1 70.275 73.72 70.275 73.72 70.205 73.17 70.205 ;
      RECT  71.49 69.725 71.7 69.965 ;
      RECT  74.1 71.545 74.61 71.305 ;
      RECT  74.1 71.615 74.3 71.545 ;
      RECT  72.63 72.165 73.17 71.785 ;
      RECT  71.7 73.435 72.63 72.885 ;
      RECT  71.49 71.545 71.7 71.305 ;
      RECT  74.61 71.545 74.82 71.305 ;
      RECT  71.7 71.545 74.1 71.305 ;
      RECT  73.89 72.405 74.1 72.335 ;
      RECT  74.61 72.165 74.82 71.785 ;
      RECT  73.89 71.615 74.1 71.545 ;
      RECT  74.1 72.405 74.3 72.335 ;
      RECT  71.7 72.645 74.1 72.405 ;
      RECT  74.61 72.645 74.82 72.405 ;
      RECT  72.63 73.435 73.17 72.885 ;
      RECT  71.49 72.165 72.63 71.785 ;
      RECT  71.49 73.435 71.7 72.885 ;
      POLYGON  74.47 72.165 74.47 72.095 74.1 72.095 74.1 71.855 74.47 71.855 74.47 71.785 74.61 71.785 74.61 72.165 74.47 72.165 ;
      RECT  74.1 72.645 74.61 72.405 ;
      RECT  73.17 73.435 74.82 72.885 ;
      POLYGON  73.17 72.165 73.17 71.785 73.72 71.785 73.72 71.855 74.1 71.855 74.1 72.095 73.72 72.095 73.72 72.165 73.17 72.165 ;
      RECT  71.49 72.645 71.7 72.405 ;
      RECT  74.1 74.775 74.61 75.015 ;
      RECT  74.1 74.705 74.3 74.775 ;
      RECT  72.63 74.155 73.17 74.535 ;
      RECT  71.7 72.885 72.63 73.435 ;
      RECT  71.49 74.775 71.7 75.015 ;
      RECT  74.61 74.775 74.82 75.015 ;
      RECT  71.7 74.775 74.1 75.015 ;
      RECT  73.89 73.915 74.1 73.985 ;
      RECT  74.61 74.155 74.82 74.535 ;
      RECT  73.89 74.705 74.1 74.775 ;
      RECT  74.1 73.915 74.3 73.985 ;
      RECT  71.7 73.675 74.1 73.915 ;
      RECT  74.61 73.675 74.82 73.915 ;
      RECT  72.63 72.885 73.17 73.435 ;
      RECT  71.49 74.155 72.63 74.535 ;
      RECT  71.49 72.885 71.7 73.435 ;
      POLYGON  74.47 74.155 74.47 74.225 74.1 74.225 74.1 74.465 74.47 74.465 74.47 74.535 74.61 74.535 74.61 74.155 74.47 74.155 ;
      RECT  74.1 73.675 74.61 73.915 ;
      RECT  73.17 72.885 74.82 73.435 ;
      POLYGON  73.17 74.155 73.17 74.535 73.72 74.535 73.72 74.465 74.1 74.465 74.1 74.225 73.72 74.225 73.72 74.155 73.17 74.155 ;
      RECT  71.49 73.675 71.7 73.915 ;
      RECT  74.1 75.495 74.61 75.255 ;
      RECT  74.1 75.565 74.3 75.495 ;
      RECT  72.63 76.115 73.17 75.735 ;
      RECT  71.7 77.385 72.63 76.835 ;
      RECT  71.49 75.495 71.7 75.255 ;
      RECT  74.61 75.495 74.82 75.255 ;
      RECT  71.7 75.495 74.1 75.255 ;
      RECT  73.89 76.355 74.1 76.285 ;
      RECT  74.61 76.115 74.82 75.735 ;
      RECT  73.89 75.565 74.1 75.495 ;
      RECT  74.1 76.355 74.3 76.285 ;
      RECT  71.7 76.595 74.1 76.355 ;
      RECT  74.61 76.595 74.82 76.355 ;
      RECT  72.63 77.385 73.17 76.835 ;
      RECT  71.49 76.115 72.63 75.735 ;
      RECT  71.49 77.385 71.7 76.835 ;
      POLYGON  74.47 76.115 74.47 76.045 74.1 76.045 74.1 75.805 74.47 75.805 74.47 75.735 74.61 75.735 74.61 76.115 74.47 76.115 ;
      RECT  74.1 76.595 74.61 76.355 ;
      RECT  73.17 77.385 74.82 76.835 ;
      POLYGON  73.17 76.115 73.17 75.735 73.72 75.735 73.72 75.805 74.1 75.805 74.1 76.045 73.72 76.045 73.72 76.115 73.17 76.115 ;
      RECT  71.49 76.595 71.7 76.355 ;
      RECT  74.1 78.725 74.61 78.965 ;
      RECT  74.1 78.655 74.3 78.725 ;
      RECT  72.63 78.105 73.17 78.485 ;
      RECT  71.7 76.835 72.63 77.385 ;
      RECT  71.49 78.725 71.7 78.965 ;
      RECT  74.61 78.725 74.82 78.965 ;
      RECT  71.7 78.725 74.1 78.965 ;
      RECT  73.89 77.865 74.1 77.935 ;
      RECT  74.61 78.105 74.82 78.485 ;
      RECT  73.89 78.655 74.1 78.725 ;
      RECT  74.1 77.865 74.3 77.935 ;
      RECT  71.7 77.625 74.1 77.865 ;
      RECT  74.61 77.625 74.82 77.865 ;
      RECT  72.63 76.835 73.17 77.385 ;
      RECT  71.49 78.105 72.63 78.485 ;
      RECT  71.49 76.835 71.7 77.385 ;
      POLYGON  74.47 78.105 74.47 78.175 74.1 78.175 74.1 78.415 74.47 78.415 74.47 78.485 74.61 78.485 74.61 78.105 74.47 78.105 ;
      RECT  74.1 77.625 74.61 77.865 ;
      RECT  73.17 76.835 74.82 77.385 ;
      POLYGON  73.17 78.105 73.17 78.485 73.72 78.485 73.72 78.415 74.1 78.415 74.1 78.175 73.72 78.175 73.72 78.105 73.17 78.105 ;
      RECT  71.49 77.625 71.7 77.865 ;
      RECT  74.1 79.445 74.61 79.205 ;
      RECT  74.1 79.515 74.3 79.445 ;
      RECT  72.63 80.065 73.17 79.685 ;
      RECT  71.7 81.335 72.63 80.785 ;
      RECT  71.49 79.445 71.7 79.205 ;
      RECT  74.61 79.445 74.82 79.205 ;
      RECT  71.7 79.445 74.1 79.205 ;
      RECT  73.89 80.305 74.1 80.235 ;
      RECT  74.61 80.065 74.82 79.685 ;
      RECT  73.89 79.515 74.1 79.445 ;
      RECT  74.1 80.305 74.3 80.235 ;
      RECT  71.7 80.545 74.1 80.305 ;
      RECT  74.61 80.545 74.82 80.305 ;
      RECT  72.63 81.335 73.17 80.785 ;
      RECT  71.49 80.065 72.63 79.685 ;
      RECT  71.49 81.335 71.7 80.785 ;
      POLYGON  74.47 80.065 74.47 79.995 74.1 79.995 74.1 79.755 74.47 79.755 74.47 79.685 74.61 79.685 74.61 80.065 74.47 80.065 ;
      RECT  74.1 80.545 74.61 80.305 ;
      RECT  73.17 81.335 74.82 80.785 ;
      POLYGON  73.17 80.065 73.17 79.685 73.72 79.685 73.72 79.755 74.1 79.755 74.1 79.995 73.72 79.995 73.72 80.065 73.17 80.065 ;
      RECT  71.49 80.545 71.7 80.305 ;
      RECT  74.1 82.675 74.61 82.915 ;
      RECT  74.1 82.605 74.3 82.675 ;
      RECT  72.63 82.055 73.17 82.435 ;
      RECT  71.7 80.785 72.63 81.335 ;
      RECT  71.49 82.675 71.7 82.915 ;
      RECT  74.61 82.675 74.82 82.915 ;
      RECT  71.7 82.675 74.1 82.915 ;
      RECT  73.89 81.815 74.1 81.885 ;
      RECT  74.61 82.055 74.82 82.435 ;
      RECT  73.89 82.605 74.1 82.675 ;
      RECT  74.1 81.815 74.3 81.885 ;
      RECT  71.7 81.575 74.1 81.815 ;
      RECT  74.61 81.575 74.82 81.815 ;
      RECT  72.63 80.785 73.17 81.335 ;
      RECT  71.49 82.055 72.63 82.435 ;
      RECT  71.49 80.785 71.7 81.335 ;
      POLYGON  74.47 82.055 74.47 82.125 74.1 82.125 74.1 82.365 74.47 82.365 74.47 82.435 74.61 82.435 74.61 82.055 74.47 82.055 ;
      RECT  74.1 81.575 74.61 81.815 ;
      RECT  73.17 80.785 74.82 81.335 ;
      POLYGON  73.17 82.055 73.17 82.435 73.72 82.435 73.72 82.365 74.1 82.365 74.1 82.125 73.72 82.125 73.72 82.055 73.17 82.055 ;
      RECT  71.49 81.575 71.7 81.815 ;
      RECT  74.1 83.395 74.61 83.155 ;
      RECT  74.1 83.465 74.3 83.395 ;
      RECT  72.63 84.015 73.17 83.635 ;
      RECT  71.7 85.285 72.63 84.735 ;
      RECT  71.49 83.395 71.7 83.155 ;
      RECT  74.61 83.395 74.82 83.155 ;
      RECT  71.7 83.395 74.1 83.155 ;
      RECT  73.89 84.255 74.1 84.185 ;
      RECT  74.61 84.015 74.82 83.635 ;
      RECT  73.89 83.465 74.1 83.395 ;
      RECT  74.1 84.255 74.3 84.185 ;
      RECT  71.7 84.495 74.1 84.255 ;
      RECT  74.61 84.495 74.82 84.255 ;
      RECT  72.63 85.285 73.17 84.735 ;
      RECT  71.49 84.015 72.63 83.635 ;
      RECT  71.49 85.285 71.7 84.735 ;
      POLYGON  74.47 84.015 74.47 83.945 74.1 83.945 74.1 83.705 74.47 83.705 74.47 83.635 74.61 83.635 74.61 84.015 74.47 84.015 ;
      RECT  74.1 84.495 74.61 84.255 ;
      RECT  73.17 85.285 74.82 84.735 ;
      POLYGON  73.17 84.015 73.17 83.635 73.72 83.635 73.72 83.705 74.1 83.705 74.1 83.945 73.72 83.945 73.72 84.015 73.17 84.015 ;
      RECT  71.49 84.495 71.7 84.255 ;
      RECT  74.1 86.625 74.61 86.865 ;
      RECT  74.1 86.555 74.3 86.625 ;
      RECT  72.63 86.005 73.17 86.385 ;
      RECT  71.7 84.735 72.63 85.285 ;
      RECT  71.49 86.625 71.7 86.865 ;
      RECT  74.61 86.625 74.82 86.865 ;
      RECT  71.7 86.625 74.1 86.865 ;
      RECT  73.89 85.765 74.1 85.835 ;
      RECT  74.61 86.005 74.82 86.385 ;
      RECT  73.89 86.555 74.1 86.625 ;
      RECT  74.1 85.765 74.3 85.835 ;
      RECT  71.7 85.525 74.1 85.765 ;
      RECT  74.61 85.525 74.82 85.765 ;
      RECT  72.63 84.735 73.17 85.285 ;
      RECT  71.49 86.005 72.63 86.385 ;
      RECT  71.49 84.735 71.7 85.285 ;
      POLYGON  74.47 86.005 74.47 86.075 74.1 86.075 74.1 86.315 74.47 86.315 74.47 86.385 74.61 86.385 74.61 86.005 74.47 86.005 ;
      RECT  74.1 85.525 74.61 85.765 ;
      RECT  73.17 84.735 74.82 85.285 ;
      POLYGON  73.17 86.005 73.17 86.385 73.72 86.385 73.72 86.315 74.1 86.315 74.1 86.075 73.72 86.075 73.72 86.005 73.17 86.005 ;
      RECT  71.49 85.525 71.7 85.765 ;
      RECT  74.1 87.345 74.61 87.105 ;
      RECT  74.1 87.415 74.3 87.345 ;
      RECT  72.63 87.965 73.17 87.585 ;
      RECT  71.7 89.235 72.63 88.685 ;
      RECT  71.49 87.345 71.7 87.105 ;
      RECT  74.61 87.345 74.82 87.105 ;
      RECT  71.7 87.345 74.1 87.105 ;
      RECT  73.89 88.205 74.1 88.135 ;
      RECT  74.61 87.965 74.82 87.585 ;
      RECT  73.89 87.415 74.1 87.345 ;
      RECT  74.1 88.205 74.3 88.135 ;
      RECT  71.7 88.445 74.1 88.205 ;
      RECT  74.61 88.445 74.82 88.205 ;
      RECT  72.63 89.235 73.17 88.685 ;
      RECT  71.49 87.965 72.63 87.585 ;
      RECT  71.49 89.235 71.7 88.685 ;
      POLYGON  74.47 87.965 74.47 87.895 74.1 87.895 74.1 87.655 74.47 87.655 74.47 87.585 74.61 87.585 74.61 87.965 74.47 87.965 ;
      RECT  74.1 88.445 74.61 88.205 ;
      RECT  73.17 89.235 74.82 88.685 ;
      POLYGON  73.17 87.965 73.17 87.585 73.72 87.585 73.72 87.655 74.1 87.655 74.1 87.895 73.72 87.895 73.72 87.965 73.17 87.965 ;
      RECT  71.49 88.445 71.7 88.205 ;
      RECT  74.1 90.575 74.61 90.815 ;
      RECT  74.1 90.505 74.3 90.575 ;
      RECT  72.63 89.955 73.17 90.335 ;
      RECT  71.7 88.685 72.63 89.235 ;
      RECT  71.49 90.575 71.7 90.815 ;
      RECT  74.61 90.575 74.82 90.815 ;
      RECT  71.7 90.575 74.1 90.815 ;
      RECT  73.89 89.715 74.1 89.785 ;
      RECT  74.61 89.955 74.82 90.335 ;
      RECT  73.89 90.505 74.1 90.575 ;
      RECT  74.1 89.715 74.3 89.785 ;
      RECT  71.7 89.475 74.1 89.715 ;
      RECT  74.61 89.475 74.82 89.715 ;
      RECT  72.63 88.685 73.17 89.235 ;
      RECT  71.49 89.955 72.63 90.335 ;
      RECT  71.49 88.685 71.7 89.235 ;
      POLYGON  74.47 89.955 74.47 90.025 74.1 90.025 74.1 90.265 74.47 90.265 74.47 90.335 74.61 90.335 74.61 89.955 74.47 89.955 ;
      RECT  74.1 89.475 74.61 89.715 ;
      RECT  73.17 88.685 74.82 89.235 ;
      POLYGON  73.17 89.955 73.17 90.335 73.72 90.335 73.72 90.265 74.1 90.265 74.1 90.025 73.72 90.025 73.72 89.955 73.17 89.955 ;
      RECT  71.49 89.475 71.7 89.715 ;
      RECT  74.1 91.295 74.61 91.055 ;
      RECT  74.1 91.365 74.3 91.295 ;
      RECT  72.63 91.915 73.17 91.535 ;
      RECT  71.7 93.185 72.63 92.635 ;
      RECT  71.49 91.295 71.7 91.055 ;
      RECT  74.61 91.295 74.82 91.055 ;
      RECT  71.7 91.295 74.1 91.055 ;
      RECT  73.89 92.155 74.1 92.085 ;
      RECT  74.61 91.915 74.82 91.535 ;
      RECT  73.89 91.365 74.1 91.295 ;
      RECT  74.1 92.155 74.3 92.085 ;
      RECT  71.7 92.395 74.1 92.155 ;
      RECT  74.61 92.395 74.82 92.155 ;
      RECT  72.63 93.185 73.17 92.635 ;
      RECT  71.49 91.915 72.63 91.535 ;
      RECT  71.49 93.185 71.7 92.635 ;
      POLYGON  74.47 91.915 74.47 91.845 74.1 91.845 74.1 91.605 74.47 91.605 74.47 91.535 74.61 91.535 74.61 91.915 74.47 91.915 ;
      RECT  74.1 92.395 74.61 92.155 ;
      RECT  73.17 93.185 74.82 92.635 ;
      POLYGON  73.17 91.915 73.17 91.535 73.72 91.535 73.72 91.605 74.1 91.605 74.1 91.845 73.72 91.845 73.72 91.915 73.17 91.915 ;
      RECT  71.49 92.395 71.7 92.155 ;
      RECT  74.1 94.525 74.61 94.765 ;
      RECT  74.1 94.455 74.3 94.525 ;
      RECT  72.63 93.905 73.17 94.285 ;
      RECT  71.7 92.635 72.63 93.185 ;
      RECT  71.49 94.525 71.7 94.765 ;
      RECT  74.61 94.525 74.82 94.765 ;
      RECT  71.7 94.525 74.1 94.765 ;
      RECT  73.89 93.665 74.1 93.735 ;
      RECT  74.61 93.905 74.82 94.285 ;
      RECT  73.89 94.455 74.1 94.525 ;
      RECT  74.1 93.665 74.3 93.735 ;
      RECT  71.7 93.425 74.1 93.665 ;
      RECT  74.61 93.425 74.82 93.665 ;
      RECT  72.63 92.635 73.17 93.185 ;
      RECT  71.49 93.905 72.63 94.285 ;
      RECT  71.49 92.635 71.7 93.185 ;
      POLYGON  74.47 93.905 74.47 93.975 74.1 93.975 74.1 94.215 74.47 94.215 74.47 94.285 74.61 94.285 74.61 93.905 74.47 93.905 ;
      RECT  74.1 93.425 74.61 93.665 ;
      RECT  73.17 92.635 74.82 93.185 ;
      POLYGON  73.17 93.905 73.17 94.285 73.72 94.285 73.72 94.215 74.1 94.215 74.1 93.975 73.72 93.975 73.72 93.905 73.17 93.905 ;
      RECT  71.49 93.425 71.7 93.665 ;
      RECT  71.7 95.99 74.82 95.44 ;
      RECT  71.7 59.455 74.82 59.695 ;
      RECT  71.7 60.555 74.82 60.795 ;
      RECT  71.7 62.925 74.82 63.165 ;
      RECT  71.7 61.825 74.82 62.065 ;
      RECT  71.7 63.405 74.82 63.645 ;
      RECT  71.7 64.505 74.82 64.745 ;
      RECT  71.7 66.875 74.82 67.115 ;
      RECT  71.7 65.775 74.82 66.015 ;
      RECT  71.7 67.355 74.82 67.595 ;
      RECT  71.7 68.455 74.82 68.695 ;
      RECT  71.7 70.825 74.82 71.065 ;
      RECT  71.7 69.725 74.82 69.965 ;
      RECT  71.7 71.305 74.82 71.545 ;
      RECT  71.7 72.405 74.82 72.645 ;
      RECT  71.7 74.775 74.82 75.015 ;
      RECT  71.7 73.675 74.82 73.915 ;
      RECT  71.7 75.255 74.82 75.495 ;
      RECT  71.7 76.355 74.82 76.595 ;
      RECT  71.7 78.725 74.82 78.965 ;
      RECT  71.7 77.625 74.82 77.865 ;
      RECT  71.7 79.205 74.82 79.445 ;
      RECT  71.7 80.305 74.82 80.545 ;
      RECT  71.7 82.675 74.82 82.915 ;
      RECT  71.7 81.575 74.82 81.815 ;
      RECT  71.7 83.155 74.82 83.395 ;
      RECT  71.7 84.255 74.82 84.495 ;
      RECT  71.7 86.625 74.82 86.865 ;
      RECT  71.7 85.525 74.82 85.765 ;
      RECT  71.7 87.105 74.82 87.345 ;
      RECT  71.7 88.205 74.82 88.445 ;
      RECT  71.7 90.575 74.82 90.815 ;
      RECT  71.7 89.475 74.82 89.715 ;
      RECT  71.7 91.055 74.82 91.295 ;
      RECT  71.7 92.155 74.82 92.395 ;
      RECT  71.7 94.525 74.82 94.765 ;
      RECT  71.7 93.425 74.82 93.665 ;
      RECT  72.63 71.785 73.17 72.165 ;
      RECT  72.63 79.685 73.17 80.065 ;
      RECT  72.63 93.905 73.17 94.285 ;
      RECT  72.63 86.005 73.17 86.385 ;
      RECT  72.63 78.105 73.17 78.485 ;
      RECT  72.63 75.735 73.17 76.115 ;
      RECT  72.63 68.935 73.17 69.485 ;
      RECT  72.63 82.055 73.17 82.435 ;
      RECT  72.63 72.885 73.17 73.435 ;
      RECT  72.63 67.835 73.17 68.215 ;
      RECT  72.63 91.535 73.17 91.915 ;
      RECT  72.63 59.935 73.17 60.315 ;
      RECT  72.63 89.955 73.17 90.335 ;
      RECT  72.63 87.585 73.17 87.965 ;
      RECT  72.63 66.255 73.17 66.635 ;
      RECT  72.63 88.685 73.17 89.235 ;
      RECT  72.63 61.035 73.17 61.585 ;
      RECT  72.63 80.785 73.17 81.335 ;
      RECT  72.63 74.155 73.17 74.535 ;
      RECT  72.63 83.635 73.17 84.015 ;
      RECT  72.63 63.885 73.17 64.265 ;
      RECT  72.63 92.635 73.17 93.185 ;
      RECT  72.63 64.985 73.17 65.535 ;
      RECT  72.63 76.835 73.17 77.385 ;
      RECT  72.63 84.735 73.17 85.285 ;
      RECT  72.63 62.305 73.17 62.685 ;
      RECT  72.63 70.205 73.17 70.585 ;
      RECT  67.86 59.695 68.37 59.455 ;
      RECT  67.86 59.765 68.06 59.695 ;
      RECT  66.39 60.315 66.93 59.935 ;
      RECT  65.46 61.585 66.39 61.035 ;
      RECT  65.25 59.695 65.46 59.455 ;
      RECT  68.37 59.695 68.58 59.455 ;
      RECT  65.46 59.695 67.86 59.455 ;
      RECT  67.65 60.555 67.86 60.485 ;
      RECT  68.37 60.315 68.58 59.935 ;
      RECT  67.65 59.765 67.86 59.695 ;
      RECT  67.86 60.555 68.06 60.485 ;
      RECT  65.46 60.795 67.86 60.555 ;
      RECT  68.37 60.795 68.58 60.555 ;
      RECT  66.39 61.585 66.93 61.035 ;
      RECT  65.25 60.315 66.39 59.935 ;
      RECT  65.25 61.585 65.46 61.035 ;
      POLYGON  68.23 60.315 68.23 60.245 67.86 60.245 67.86 60.005 68.23 60.005 68.23 59.935 68.37 59.935 68.37 60.315 68.23 60.315 ;
      RECT  67.86 60.795 68.37 60.555 ;
      RECT  66.93 61.585 68.58 61.035 ;
      POLYGON  66.93 60.315 66.93 59.935 67.48 59.935 67.48 60.005 67.86 60.005 67.86 60.245 67.48 60.245 67.48 60.315 66.93 60.315 ;
      RECT  65.25 60.795 65.46 60.555 ;
      RECT  69.3 59.695 68.79 59.455 ;
      RECT  69.3 59.765 69.1 59.695 ;
      RECT  70.77 60.315 70.23 59.935 ;
      RECT  71.7 61.585 70.77 61.035 ;
      RECT  71.91 59.695 71.7 59.455 ;
      RECT  68.79 59.695 68.58 59.455 ;
      RECT  71.7 59.695 69.3 59.455 ;
      RECT  69.51 60.555 69.3 60.485 ;
      RECT  68.79 60.315 68.58 59.935 ;
      RECT  69.51 59.765 69.3 59.695 ;
      RECT  69.3 60.555 69.1 60.485 ;
      RECT  71.7 60.795 69.3 60.555 ;
      RECT  68.79 60.795 68.58 60.555 ;
      RECT  70.77 61.585 70.23 61.035 ;
      RECT  71.91 60.315 70.77 59.935 ;
      RECT  71.91 61.585 71.7 61.035 ;
      POLYGON  68.93 60.315 68.93 60.245 69.3 60.245 69.3 60.005 68.93 60.005 68.93 59.935 68.79 59.935 68.79 60.315 68.93 60.315 ;
      RECT  69.3 60.795 68.79 60.555 ;
      RECT  70.23 61.585 68.58 61.035 ;
      POLYGON  70.23 60.315 70.23 59.935 69.68 59.935 69.68 60.005 69.3 60.005 69.3 60.245 69.68 60.245 69.68 60.315 70.23 60.315 ;
      RECT  71.91 60.795 71.7 60.555 ;
      RECT  65.46 59.695 71.7 59.455 ;
      RECT  65.46 60.795 71.7 60.555 ;
      RECT  66.39 60.315 66.93 59.935 ;
      RECT  70.23 61.585 70.77 61.035 ;
      RECT  66.39 61.585 66.93 61.035 ;
      RECT  70.23 60.315 70.77 59.935 ;
      RECT  67.86 94.525 68.37 94.765 ;
      RECT  67.86 94.455 68.06 94.525 ;
      RECT  66.39 93.905 66.93 94.285 ;
      RECT  65.46 92.635 66.39 93.185 ;
      RECT  65.25 94.525 65.46 94.765 ;
      RECT  68.37 94.525 68.58 94.765 ;
      RECT  65.46 94.525 67.86 94.765 ;
      RECT  67.65 93.665 67.86 93.735 ;
      RECT  68.37 93.905 68.58 94.285 ;
      RECT  67.65 94.455 67.86 94.525 ;
      RECT  67.86 93.665 68.06 93.735 ;
      RECT  65.46 93.425 67.86 93.665 ;
      RECT  68.37 93.425 68.58 93.665 ;
      RECT  66.39 92.635 66.93 93.185 ;
      RECT  65.25 93.905 66.39 94.285 ;
      RECT  65.25 92.635 65.46 93.185 ;
      POLYGON  68.23 93.905 68.23 93.975 67.86 93.975 67.86 94.215 68.23 94.215 68.23 94.285 68.37 94.285 68.37 93.905 68.23 93.905 ;
      RECT  67.86 93.425 68.37 93.665 ;
      RECT  66.93 92.635 68.58 93.185 ;
      POLYGON  66.93 93.905 66.93 94.285 67.48 94.285 67.48 94.215 67.86 94.215 67.86 93.975 67.48 93.975 67.48 93.905 66.93 93.905 ;
      RECT  65.25 93.425 65.46 93.665 ;
      RECT  69.3 94.525 68.79 94.765 ;
      RECT  69.3 94.455 69.1 94.525 ;
      RECT  70.77 93.905 70.23 94.285 ;
      RECT  71.7 92.635 70.77 93.185 ;
      RECT  71.91 94.525 71.7 94.765 ;
      RECT  68.79 94.525 68.58 94.765 ;
      RECT  71.7 94.525 69.3 94.765 ;
      RECT  69.51 93.665 69.3 93.735 ;
      RECT  68.79 93.905 68.58 94.285 ;
      RECT  69.51 94.455 69.3 94.525 ;
      RECT  69.3 93.665 69.1 93.735 ;
      RECT  71.7 93.425 69.3 93.665 ;
      RECT  68.79 93.425 68.58 93.665 ;
      RECT  70.77 92.635 70.23 93.185 ;
      RECT  71.91 93.905 70.77 94.285 ;
      RECT  71.91 92.635 71.7 93.185 ;
      POLYGON  68.93 93.905 68.93 93.975 69.3 93.975 69.3 94.215 68.93 94.215 68.93 94.285 68.79 94.285 68.79 93.905 68.93 93.905 ;
      RECT  69.3 93.425 68.79 93.665 ;
      RECT  70.23 92.635 68.58 93.185 ;
      POLYGON  70.23 93.905 70.23 94.285 69.68 94.285 69.68 94.215 69.3 94.215 69.3 93.975 69.68 93.975 69.68 93.905 70.23 93.905 ;
      RECT  71.91 93.425 71.7 93.665 ;
      RECT  65.46 94.525 71.7 94.765 ;
      RECT  65.46 93.425 71.7 93.665 ;
      RECT  66.39 93.905 66.93 94.285 ;
      RECT  70.23 92.635 70.77 93.185 ;
      RECT  66.39 92.635 66.93 93.185 ;
      RECT  70.23 93.905 70.77 94.285 ;
      RECT  65.46 58.23 68.58 58.78 ;
      RECT  71.7 58.23 68.58 58.78 ;
      RECT  65.46 95.99 68.58 95.44 ;
      RECT  71.7 95.99 68.58 95.44 ;
      RECT  61.62 59.695 62.13 59.455 ;
      RECT  61.62 59.765 61.82 59.695 ;
      RECT  60.15 60.315 60.69 59.935 ;
      RECT  59.22 61.585 60.15 61.035 ;
      RECT  59.01 59.695 59.22 59.455 ;
      RECT  62.13 59.695 62.34 59.455 ;
      RECT  59.22 59.695 61.62 59.455 ;
      RECT  61.41 60.555 61.62 60.485 ;
      RECT  62.13 60.315 62.34 59.935 ;
      RECT  61.41 59.765 61.62 59.695 ;
      RECT  61.62 60.555 61.82 60.485 ;
      RECT  59.22 60.795 61.62 60.555 ;
      RECT  62.13 60.795 62.34 60.555 ;
      RECT  60.15 61.585 60.69 61.035 ;
      RECT  59.01 60.315 60.15 59.935 ;
      RECT  59.01 61.585 59.22 61.035 ;
      POLYGON  61.99 60.315 61.99 60.245 61.62 60.245 61.62 60.005 61.99 60.005 61.99 59.935 62.13 59.935 62.13 60.315 61.99 60.315 ;
      RECT  61.62 60.795 62.13 60.555 ;
      RECT  60.69 61.585 62.34 61.035 ;
      POLYGON  60.69 60.315 60.69 59.935 61.24 59.935 61.24 60.005 61.62 60.005 61.62 60.245 61.24 60.245 61.24 60.315 60.69 60.315 ;
      RECT  59.01 60.795 59.22 60.555 ;
      RECT  61.62 62.925 62.13 63.165 ;
      RECT  61.62 62.855 61.82 62.925 ;
      RECT  60.15 62.305 60.69 62.685 ;
      RECT  59.22 61.035 60.15 61.585 ;
      RECT  59.01 62.925 59.22 63.165 ;
      RECT  62.13 62.925 62.34 63.165 ;
      RECT  59.22 62.925 61.62 63.165 ;
      RECT  61.41 62.065 61.62 62.135 ;
      RECT  62.13 62.305 62.34 62.685 ;
      RECT  61.41 62.855 61.62 62.925 ;
      RECT  61.62 62.065 61.82 62.135 ;
      RECT  59.22 61.825 61.62 62.065 ;
      RECT  62.13 61.825 62.34 62.065 ;
      RECT  60.15 61.035 60.69 61.585 ;
      RECT  59.01 62.305 60.15 62.685 ;
      RECT  59.01 61.035 59.22 61.585 ;
      POLYGON  61.99 62.305 61.99 62.375 61.62 62.375 61.62 62.615 61.99 62.615 61.99 62.685 62.13 62.685 62.13 62.305 61.99 62.305 ;
      RECT  61.62 61.825 62.13 62.065 ;
      RECT  60.69 61.035 62.34 61.585 ;
      POLYGON  60.69 62.305 60.69 62.685 61.24 62.685 61.24 62.615 61.62 62.615 61.62 62.375 61.24 62.375 61.24 62.305 60.69 62.305 ;
      RECT  59.01 61.825 59.22 62.065 ;
      RECT  61.62 63.645 62.13 63.405 ;
      RECT  61.62 63.715 61.82 63.645 ;
      RECT  60.15 64.265 60.69 63.885 ;
      RECT  59.22 65.535 60.15 64.985 ;
      RECT  59.01 63.645 59.22 63.405 ;
      RECT  62.13 63.645 62.34 63.405 ;
      RECT  59.22 63.645 61.62 63.405 ;
      RECT  61.41 64.505 61.62 64.435 ;
      RECT  62.13 64.265 62.34 63.885 ;
      RECT  61.41 63.715 61.62 63.645 ;
      RECT  61.62 64.505 61.82 64.435 ;
      RECT  59.22 64.745 61.62 64.505 ;
      RECT  62.13 64.745 62.34 64.505 ;
      RECT  60.15 65.535 60.69 64.985 ;
      RECT  59.01 64.265 60.15 63.885 ;
      RECT  59.01 65.535 59.22 64.985 ;
      POLYGON  61.99 64.265 61.99 64.195 61.62 64.195 61.62 63.955 61.99 63.955 61.99 63.885 62.13 63.885 62.13 64.265 61.99 64.265 ;
      RECT  61.62 64.745 62.13 64.505 ;
      RECT  60.69 65.535 62.34 64.985 ;
      POLYGON  60.69 64.265 60.69 63.885 61.24 63.885 61.24 63.955 61.62 63.955 61.62 64.195 61.24 64.195 61.24 64.265 60.69 64.265 ;
      RECT  59.01 64.745 59.22 64.505 ;
      RECT  61.62 66.875 62.13 67.115 ;
      RECT  61.62 66.805 61.82 66.875 ;
      RECT  60.15 66.255 60.69 66.635 ;
      RECT  59.22 64.985 60.15 65.535 ;
      RECT  59.01 66.875 59.22 67.115 ;
      RECT  62.13 66.875 62.34 67.115 ;
      RECT  59.22 66.875 61.62 67.115 ;
      RECT  61.41 66.015 61.62 66.085 ;
      RECT  62.13 66.255 62.34 66.635 ;
      RECT  61.41 66.805 61.62 66.875 ;
      RECT  61.62 66.015 61.82 66.085 ;
      RECT  59.22 65.775 61.62 66.015 ;
      RECT  62.13 65.775 62.34 66.015 ;
      RECT  60.15 64.985 60.69 65.535 ;
      RECT  59.01 66.255 60.15 66.635 ;
      RECT  59.01 64.985 59.22 65.535 ;
      POLYGON  61.99 66.255 61.99 66.325 61.62 66.325 61.62 66.565 61.99 66.565 61.99 66.635 62.13 66.635 62.13 66.255 61.99 66.255 ;
      RECT  61.62 65.775 62.13 66.015 ;
      RECT  60.69 64.985 62.34 65.535 ;
      POLYGON  60.69 66.255 60.69 66.635 61.24 66.635 61.24 66.565 61.62 66.565 61.62 66.325 61.24 66.325 61.24 66.255 60.69 66.255 ;
      RECT  59.01 65.775 59.22 66.015 ;
      RECT  61.62 67.595 62.13 67.355 ;
      RECT  61.62 67.665 61.82 67.595 ;
      RECT  60.15 68.215 60.69 67.835 ;
      RECT  59.22 69.485 60.15 68.935 ;
      RECT  59.01 67.595 59.22 67.355 ;
      RECT  62.13 67.595 62.34 67.355 ;
      RECT  59.22 67.595 61.62 67.355 ;
      RECT  61.41 68.455 61.62 68.385 ;
      RECT  62.13 68.215 62.34 67.835 ;
      RECT  61.41 67.665 61.62 67.595 ;
      RECT  61.62 68.455 61.82 68.385 ;
      RECT  59.22 68.695 61.62 68.455 ;
      RECT  62.13 68.695 62.34 68.455 ;
      RECT  60.15 69.485 60.69 68.935 ;
      RECT  59.01 68.215 60.15 67.835 ;
      RECT  59.01 69.485 59.22 68.935 ;
      POLYGON  61.99 68.215 61.99 68.145 61.62 68.145 61.62 67.905 61.99 67.905 61.99 67.835 62.13 67.835 62.13 68.215 61.99 68.215 ;
      RECT  61.62 68.695 62.13 68.455 ;
      RECT  60.69 69.485 62.34 68.935 ;
      POLYGON  60.69 68.215 60.69 67.835 61.24 67.835 61.24 67.905 61.62 67.905 61.62 68.145 61.24 68.145 61.24 68.215 60.69 68.215 ;
      RECT  59.01 68.695 59.22 68.455 ;
      RECT  61.62 70.825 62.13 71.065 ;
      RECT  61.62 70.755 61.82 70.825 ;
      RECT  60.15 70.205 60.69 70.585 ;
      RECT  59.22 68.935 60.15 69.485 ;
      RECT  59.01 70.825 59.22 71.065 ;
      RECT  62.13 70.825 62.34 71.065 ;
      RECT  59.22 70.825 61.62 71.065 ;
      RECT  61.41 69.965 61.62 70.035 ;
      RECT  62.13 70.205 62.34 70.585 ;
      RECT  61.41 70.755 61.62 70.825 ;
      RECT  61.62 69.965 61.82 70.035 ;
      RECT  59.22 69.725 61.62 69.965 ;
      RECT  62.13 69.725 62.34 69.965 ;
      RECT  60.15 68.935 60.69 69.485 ;
      RECT  59.01 70.205 60.15 70.585 ;
      RECT  59.01 68.935 59.22 69.485 ;
      POLYGON  61.99 70.205 61.99 70.275 61.62 70.275 61.62 70.515 61.99 70.515 61.99 70.585 62.13 70.585 62.13 70.205 61.99 70.205 ;
      RECT  61.62 69.725 62.13 69.965 ;
      RECT  60.69 68.935 62.34 69.485 ;
      POLYGON  60.69 70.205 60.69 70.585 61.24 70.585 61.24 70.515 61.62 70.515 61.62 70.275 61.24 70.275 61.24 70.205 60.69 70.205 ;
      RECT  59.01 69.725 59.22 69.965 ;
      RECT  61.62 71.545 62.13 71.305 ;
      RECT  61.62 71.615 61.82 71.545 ;
      RECT  60.15 72.165 60.69 71.785 ;
      RECT  59.22 73.435 60.15 72.885 ;
      RECT  59.01 71.545 59.22 71.305 ;
      RECT  62.13 71.545 62.34 71.305 ;
      RECT  59.22 71.545 61.62 71.305 ;
      RECT  61.41 72.405 61.62 72.335 ;
      RECT  62.13 72.165 62.34 71.785 ;
      RECT  61.41 71.615 61.62 71.545 ;
      RECT  61.62 72.405 61.82 72.335 ;
      RECT  59.22 72.645 61.62 72.405 ;
      RECT  62.13 72.645 62.34 72.405 ;
      RECT  60.15 73.435 60.69 72.885 ;
      RECT  59.01 72.165 60.15 71.785 ;
      RECT  59.01 73.435 59.22 72.885 ;
      POLYGON  61.99 72.165 61.99 72.095 61.62 72.095 61.62 71.855 61.99 71.855 61.99 71.785 62.13 71.785 62.13 72.165 61.99 72.165 ;
      RECT  61.62 72.645 62.13 72.405 ;
      RECT  60.69 73.435 62.34 72.885 ;
      POLYGON  60.69 72.165 60.69 71.785 61.24 71.785 61.24 71.855 61.62 71.855 61.62 72.095 61.24 72.095 61.24 72.165 60.69 72.165 ;
      RECT  59.01 72.645 59.22 72.405 ;
      RECT  61.62 74.775 62.13 75.015 ;
      RECT  61.62 74.705 61.82 74.775 ;
      RECT  60.15 74.155 60.69 74.535 ;
      RECT  59.22 72.885 60.15 73.435 ;
      RECT  59.01 74.775 59.22 75.015 ;
      RECT  62.13 74.775 62.34 75.015 ;
      RECT  59.22 74.775 61.62 75.015 ;
      RECT  61.41 73.915 61.62 73.985 ;
      RECT  62.13 74.155 62.34 74.535 ;
      RECT  61.41 74.705 61.62 74.775 ;
      RECT  61.62 73.915 61.82 73.985 ;
      RECT  59.22 73.675 61.62 73.915 ;
      RECT  62.13 73.675 62.34 73.915 ;
      RECT  60.15 72.885 60.69 73.435 ;
      RECT  59.01 74.155 60.15 74.535 ;
      RECT  59.01 72.885 59.22 73.435 ;
      POLYGON  61.99 74.155 61.99 74.225 61.62 74.225 61.62 74.465 61.99 74.465 61.99 74.535 62.13 74.535 62.13 74.155 61.99 74.155 ;
      RECT  61.62 73.675 62.13 73.915 ;
      RECT  60.69 72.885 62.34 73.435 ;
      POLYGON  60.69 74.155 60.69 74.535 61.24 74.535 61.24 74.465 61.62 74.465 61.62 74.225 61.24 74.225 61.24 74.155 60.69 74.155 ;
      RECT  59.01 73.675 59.22 73.915 ;
      RECT  61.62 75.495 62.13 75.255 ;
      RECT  61.62 75.565 61.82 75.495 ;
      RECT  60.15 76.115 60.69 75.735 ;
      RECT  59.22 77.385 60.15 76.835 ;
      RECT  59.01 75.495 59.22 75.255 ;
      RECT  62.13 75.495 62.34 75.255 ;
      RECT  59.22 75.495 61.62 75.255 ;
      RECT  61.41 76.355 61.62 76.285 ;
      RECT  62.13 76.115 62.34 75.735 ;
      RECT  61.41 75.565 61.62 75.495 ;
      RECT  61.62 76.355 61.82 76.285 ;
      RECT  59.22 76.595 61.62 76.355 ;
      RECT  62.13 76.595 62.34 76.355 ;
      RECT  60.15 77.385 60.69 76.835 ;
      RECT  59.01 76.115 60.15 75.735 ;
      RECT  59.01 77.385 59.22 76.835 ;
      POLYGON  61.99 76.115 61.99 76.045 61.62 76.045 61.62 75.805 61.99 75.805 61.99 75.735 62.13 75.735 62.13 76.115 61.99 76.115 ;
      RECT  61.62 76.595 62.13 76.355 ;
      RECT  60.69 77.385 62.34 76.835 ;
      POLYGON  60.69 76.115 60.69 75.735 61.24 75.735 61.24 75.805 61.62 75.805 61.62 76.045 61.24 76.045 61.24 76.115 60.69 76.115 ;
      RECT  59.01 76.595 59.22 76.355 ;
      RECT  61.62 78.725 62.13 78.965 ;
      RECT  61.62 78.655 61.82 78.725 ;
      RECT  60.15 78.105 60.69 78.485 ;
      RECT  59.22 76.835 60.15 77.385 ;
      RECT  59.01 78.725 59.22 78.965 ;
      RECT  62.13 78.725 62.34 78.965 ;
      RECT  59.22 78.725 61.62 78.965 ;
      RECT  61.41 77.865 61.62 77.935 ;
      RECT  62.13 78.105 62.34 78.485 ;
      RECT  61.41 78.655 61.62 78.725 ;
      RECT  61.62 77.865 61.82 77.935 ;
      RECT  59.22 77.625 61.62 77.865 ;
      RECT  62.13 77.625 62.34 77.865 ;
      RECT  60.15 76.835 60.69 77.385 ;
      RECT  59.01 78.105 60.15 78.485 ;
      RECT  59.01 76.835 59.22 77.385 ;
      POLYGON  61.99 78.105 61.99 78.175 61.62 78.175 61.62 78.415 61.99 78.415 61.99 78.485 62.13 78.485 62.13 78.105 61.99 78.105 ;
      RECT  61.62 77.625 62.13 77.865 ;
      RECT  60.69 76.835 62.34 77.385 ;
      POLYGON  60.69 78.105 60.69 78.485 61.24 78.485 61.24 78.415 61.62 78.415 61.62 78.175 61.24 78.175 61.24 78.105 60.69 78.105 ;
      RECT  59.01 77.625 59.22 77.865 ;
      RECT  61.62 79.445 62.13 79.205 ;
      RECT  61.62 79.515 61.82 79.445 ;
      RECT  60.15 80.065 60.69 79.685 ;
      RECT  59.22 81.335 60.15 80.785 ;
      RECT  59.01 79.445 59.22 79.205 ;
      RECT  62.13 79.445 62.34 79.205 ;
      RECT  59.22 79.445 61.62 79.205 ;
      RECT  61.41 80.305 61.62 80.235 ;
      RECT  62.13 80.065 62.34 79.685 ;
      RECT  61.41 79.515 61.62 79.445 ;
      RECT  61.62 80.305 61.82 80.235 ;
      RECT  59.22 80.545 61.62 80.305 ;
      RECT  62.13 80.545 62.34 80.305 ;
      RECT  60.15 81.335 60.69 80.785 ;
      RECT  59.01 80.065 60.15 79.685 ;
      RECT  59.01 81.335 59.22 80.785 ;
      POLYGON  61.99 80.065 61.99 79.995 61.62 79.995 61.62 79.755 61.99 79.755 61.99 79.685 62.13 79.685 62.13 80.065 61.99 80.065 ;
      RECT  61.62 80.545 62.13 80.305 ;
      RECT  60.69 81.335 62.34 80.785 ;
      POLYGON  60.69 80.065 60.69 79.685 61.24 79.685 61.24 79.755 61.62 79.755 61.62 79.995 61.24 79.995 61.24 80.065 60.69 80.065 ;
      RECT  59.01 80.545 59.22 80.305 ;
      RECT  61.62 82.675 62.13 82.915 ;
      RECT  61.62 82.605 61.82 82.675 ;
      RECT  60.15 82.055 60.69 82.435 ;
      RECT  59.22 80.785 60.15 81.335 ;
      RECT  59.01 82.675 59.22 82.915 ;
      RECT  62.13 82.675 62.34 82.915 ;
      RECT  59.22 82.675 61.62 82.915 ;
      RECT  61.41 81.815 61.62 81.885 ;
      RECT  62.13 82.055 62.34 82.435 ;
      RECT  61.41 82.605 61.62 82.675 ;
      RECT  61.62 81.815 61.82 81.885 ;
      RECT  59.22 81.575 61.62 81.815 ;
      RECT  62.13 81.575 62.34 81.815 ;
      RECT  60.15 80.785 60.69 81.335 ;
      RECT  59.01 82.055 60.15 82.435 ;
      RECT  59.01 80.785 59.22 81.335 ;
      POLYGON  61.99 82.055 61.99 82.125 61.62 82.125 61.62 82.365 61.99 82.365 61.99 82.435 62.13 82.435 62.13 82.055 61.99 82.055 ;
      RECT  61.62 81.575 62.13 81.815 ;
      RECT  60.69 80.785 62.34 81.335 ;
      POLYGON  60.69 82.055 60.69 82.435 61.24 82.435 61.24 82.365 61.62 82.365 61.62 82.125 61.24 82.125 61.24 82.055 60.69 82.055 ;
      RECT  59.01 81.575 59.22 81.815 ;
      RECT  61.62 83.395 62.13 83.155 ;
      RECT  61.62 83.465 61.82 83.395 ;
      RECT  60.15 84.015 60.69 83.635 ;
      RECT  59.22 85.285 60.15 84.735 ;
      RECT  59.01 83.395 59.22 83.155 ;
      RECT  62.13 83.395 62.34 83.155 ;
      RECT  59.22 83.395 61.62 83.155 ;
      RECT  61.41 84.255 61.62 84.185 ;
      RECT  62.13 84.015 62.34 83.635 ;
      RECT  61.41 83.465 61.62 83.395 ;
      RECT  61.62 84.255 61.82 84.185 ;
      RECT  59.22 84.495 61.62 84.255 ;
      RECT  62.13 84.495 62.34 84.255 ;
      RECT  60.15 85.285 60.69 84.735 ;
      RECT  59.01 84.015 60.15 83.635 ;
      RECT  59.01 85.285 59.22 84.735 ;
      POLYGON  61.99 84.015 61.99 83.945 61.62 83.945 61.62 83.705 61.99 83.705 61.99 83.635 62.13 83.635 62.13 84.015 61.99 84.015 ;
      RECT  61.62 84.495 62.13 84.255 ;
      RECT  60.69 85.285 62.34 84.735 ;
      POLYGON  60.69 84.015 60.69 83.635 61.24 83.635 61.24 83.705 61.62 83.705 61.62 83.945 61.24 83.945 61.24 84.015 60.69 84.015 ;
      RECT  59.01 84.495 59.22 84.255 ;
      RECT  61.62 86.625 62.13 86.865 ;
      RECT  61.62 86.555 61.82 86.625 ;
      RECT  60.15 86.005 60.69 86.385 ;
      RECT  59.22 84.735 60.15 85.285 ;
      RECT  59.01 86.625 59.22 86.865 ;
      RECT  62.13 86.625 62.34 86.865 ;
      RECT  59.22 86.625 61.62 86.865 ;
      RECT  61.41 85.765 61.62 85.835 ;
      RECT  62.13 86.005 62.34 86.385 ;
      RECT  61.41 86.555 61.62 86.625 ;
      RECT  61.62 85.765 61.82 85.835 ;
      RECT  59.22 85.525 61.62 85.765 ;
      RECT  62.13 85.525 62.34 85.765 ;
      RECT  60.15 84.735 60.69 85.285 ;
      RECT  59.01 86.005 60.15 86.385 ;
      RECT  59.01 84.735 59.22 85.285 ;
      POLYGON  61.99 86.005 61.99 86.075 61.62 86.075 61.62 86.315 61.99 86.315 61.99 86.385 62.13 86.385 62.13 86.005 61.99 86.005 ;
      RECT  61.62 85.525 62.13 85.765 ;
      RECT  60.69 84.735 62.34 85.285 ;
      POLYGON  60.69 86.005 60.69 86.385 61.24 86.385 61.24 86.315 61.62 86.315 61.62 86.075 61.24 86.075 61.24 86.005 60.69 86.005 ;
      RECT  59.01 85.525 59.22 85.765 ;
      RECT  61.62 87.345 62.13 87.105 ;
      RECT  61.62 87.415 61.82 87.345 ;
      RECT  60.15 87.965 60.69 87.585 ;
      RECT  59.22 89.235 60.15 88.685 ;
      RECT  59.01 87.345 59.22 87.105 ;
      RECT  62.13 87.345 62.34 87.105 ;
      RECT  59.22 87.345 61.62 87.105 ;
      RECT  61.41 88.205 61.62 88.135 ;
      RECT  62.13 87.965 62.34 87.585 ;
      RECT  61.41 87.415 61.62 87.345 ;
      RECT  61.62 88.205 61.82 88.135 ;
      RECT  59.22 88.445 61.62 88.205 ;
      RECT  62.13 88.445 62.34 88.205 ;
      RECT  60.15 89.235 60.69 88.685 ;
      RECT  59.01 87.965 60.15 87.585 ;
      RECT  59.01 89.235 59.22 88.685 ;
      POLYGON  61.99 87.965 61.99 87.895 61.62 87.895 61.62 87.655 61.99 87.655 61.99 87.585 62.13 87.585 62.13 87.965 61.99 87.965 ;
      RECT  61.62 88.445 62.13 88.205 ;
      RECT  60.69 89.235 62.34 88.685 ;
      POLYGON  60.69 87.965 60.69 87.585 61.24 87.585 61.24 87.655 61.62 87.655 61.62 87.895 61.24 87.895 61.24 87.965 60.69 87.965 ;
      RECT  59.01 88.445 59.22 88.205 ;
      RECT  61.62 90.575 62.13 90.815 ;
      RECT  61.62 90.505 61.82 90.575 ;
      RECT  60.15 89.955 60.69 90.335 ;
      RECT  59.22 88.685 60.15 89.235 ;
      RECT  59.01 90.575 59.22 90.815 ;
      RECT  62.13 90.575 62.34 90.815 ;
      RECT  59.22 90.575 61.62 90.815 ;
      RECT  61.41 89.715 61.62 89.785 ;
      RECT  62.13 89.955 62.34 90.335 ;
      RECT  61.41 90.505 61.62 90.575 ;
      RECT  61.62 89.715 61.82 89.785 ;
      RECT  59.22 89.475 61.62 89.715 ;
      RECT  62.13 89.475 62.34 89.715 ;
      RECT  60.15 88.685 60.69 89.235 ;
      RECT  59.01 89.955 60.15 90.335 ;
      RECT  59.01 88.685 59.22 89.235 ;
      POLYGON  61.99 89.955 61.99 90.025 61.62 90.025 61.62 90.265 61.99 90.265 61.99 90.335 62.13 90.335 62.13 89.955 61.99 89.955 ;
      RECT  61.62 89.475 62.13 89.715 ;
      RECT  60.69 88.685 62.34 89.235 ;
      POLYGON  60.69 89.955 60.69 90.335 61.24 90.335 61.24 90.265 61.62 90.265 61.62 90.025 61.24 90.025 61.24 89.955 60.69 89.955 ;
      RECT  59.01 89.475 59.22 89.715 ;
      RECT  61.62 91.295 62.13 91.055 ;
      RECT  61.62 91.365 61.82 91.295 ;
      RECT  60.15 91.915 60.69 91.535 ;
      RECT  59.22 93.185 60.15 92.635 ;
      RECT  59.01 91.295 59.22 91.055 ;
      RECT  62.13 91.295 62.34 91.055 ;
      RECT  59.22 91.295 61.62 91.055 ;
      RECT  61.41 92.155 61.62 92.085 ;
      RECT  62.13 91.915 62.34 91.535 ;
      RECT  61.41 91.365 61.62 91.295 ;
      RECT  61.62 92.155 61.82 92.085 ;
      RECT  59.22 92.395 61.62 92.155 ;
      RECT  62.13 92.395 62.34 92.155 ;
      RECT  60.15 93.185 60.69 92.635 ;
      RECT  59.01 91.915 60.15 91.535 ;
      RECT  59.01 93.185 59.22 92.635 ;
      POLYGON  61.99 91.915 61.99 91.845 61.62 91.845 61.62 91.605 61.99 91.605 61.99 91.535 62.13 91.535 62.13 91.915 61.99 91.915 ;
      RECT  61.62 92.395 62.13 92.155 ;
      RECT  60.69 93.185 62.34 92.635 ;
      POLYGON  60.69 91.915 60.69 91.535 61.24 91.535 61.24 91.605 61.62 91.605 61.62 91.845 61.24 91.845 61.24 91.915 60.69 91.915 ;
      RECT  59.01 92.395 59.22 92.155 ;
      RECT  61.62 94.525 62.13 94.765 ;
      RECT  61.62 94.455 61.82 94.525 ;
      RECT  60.15 93.905 60.69 94.285 ;
      RECT  59.22 92.635 60.15 93.185 ;
      RECT  59.01 94.525 59.22 94.765 ;
      RECT  62.13 94.525 62.34 94.765 ;
      RECT  59.22 94.525 61.62 94.765 ;
      RECT  61.41 93.665 61.62 93.735 ;
      RECT  62.13 93.905 62.34 94.285 ;
      RECT  61.41 94.455 61.62 94.525 ;
      RECT  61.62 93.665 61.82 93.735 ;
      RECT  59.22 93.425 61.62 93.665 ;
      RECT  62.13 93.425 62.34 93.665 ;
      RECT  60.15 92.635 60.69 93.185 ;
      RECT  59.01 93.905 60.15 94.285 ;
      RECT  59.01 92.635 59.22 93.185 ;
      POLYGON  61.99 93.905 61.99 93.975 61.62 93.975 61.62 94.215 61.99 94.215 61.99 94.285 62.13 94.285 62.13 93.905 61.99 93.905 ;
      RECT  61.62 93.425 62.13 93.665 ;
      RECT  60.69 92.635 62.34 93.185 ;
      POLYGON  60.69 93.905 60.69 94.285 61.24 94.285 61.24 94.215 61.62 94.215 61.62 93.975 61.24 93.975 61.24 93.905 60.69 93.905 ;
      RECT  59.01 93.425 59.22 93.665 ;
      RECT  59.22 59.455 62.34 59.695 ;
      RECT  59.22 60.555 62.34 60.795 ;
      RECT  59.22 62.925 62.34 63.165 ;
      RECT  59.22 61.825 62.34 62.065 ;
      RECT  59.22 63.405 62.34 63.645 ;
      RECT  59.22 64.505 62.34 64.745 ;
      RECT  59.22 66.875 62.34 67.115 ;
      RECT  59.22 65.775 62.34 66.015 ;
      RECT  59.22 67.355 62.34 67.595 ;
      RECT  59.22 68.455 62.34 68.695 ;
      RECT  59.22 70.825 62.34 71.065 ;
      RECT  59.22 69.725 62.34 69.965 ;
      RECT  59.22 71.305 62.34 71.545 ;
      RECT  59.22 72.405 62.34 72.645 ;
      RECT  59.22 74.775 62.34 75.015 ;
      RECT  59.22 73.675 62.34 73.915 ;
      RECT  59.22 75.255 62.34 75.495 ;
      RECT  59.22 76.355 62.34 76.595 ;
      RECT  59.22 78.725 62.34 78.965 ;
      RECT  59.22 77.625 62.34 77.865 ;
      RECT  59.22 79.205 62.34 79.445 ;
      RECT  59.22 80.305 62.34 80.545 ;
      RECT  59.22 82.675 62.34 82.915 ;
      RECT  59.22 81.575 62.34 81.815 ;
      RECT  59.22 83.155 62.34 83.395 ;
      RECT  59.22 84.255 62.34 84.495 ;
      RECT  59.22 86.625 62.34 86.865 ;
      RECT  59.22 85.525 62.34 85.765 ;
      RECT  59.22 87.105 62.34 87.345 ;
      RECT  59.22 88.205 62.34 88.445 ;
      RECT  59.22 90.575 62.34 90.815 ;
      RECT  59.22 89.475 62.34 89.715 ;
      RECT  59.22 91.055 62.34 91.295 ;
      RECT  59.22 92.155 62.34 92.395 ;
      RECT  59.22 94.525 62.34 94.765 ;
      RECT  59.22 93.425 62.34 93.665 ;
      RECT  75.54 59.695 75.03 59.455 ;
      RECT  75.54 59.765 75.34 59.695 ;
      RECT  77.01 60.315 76.47 59.935 ;
      RECT  77.94 61.585 77.01 61.035 ;
      RECT  78.15 59.695 77.94 59.455 ;
      RECT  75.03 59.695 74.82 59.455 ;
      RECT  77.94 59.695 75.54 59.455 ;
      RECT  75.75 60.555 75.54 60.485 ;
      RECT  75.03 60.315 74.82 59.935 ;
      RECT  75.75 59.765 75.54 59.695 ;
      RECT  75.54 60.555 75.34 60.485 ;
      RECT  77.94 60.795 75.54 60.555 ;
      RECT  75.03 60.795 74.82 60.555 ;
      RECT  77.01 61.585 76.47 61.035 ;
      RECT  78.15 60.315 77.01 59.935 ;
      RECT  78.15 61.585 77.94 61.035 ;
      POLYGON  75.17 60.315 75.17 60.245 75.54 60.245 75.54 60.005 75.17 60.005 75.17 59.935 75.03 59.935 75.03 60.315 75.17 60.315 ;
      RECT  75.54 60.795 75.03 60.555 ;
      RECT  76.47 61.585 74.82 61.035 ;
      POLYGON  76.47 60.315 76.47 59.935 75.92 59.935 75.92 60.005 75.54 60.005 75.54 60.245 75.92 60.245 75.92 60.315 76.47 60.315 ;
      RECT  78.15 60.795 77.94 60.555 ;
      RECT  75.54 62.925 75.03 63.165 ;
      RECT  75.54 62.855 75.34 62.925 ;
      RECT  77.01 62.305 76.47 62.685 ;
      RECT  77.94 61.035 77.01 61.585 ;
      RECT  78.15 62.925 77.94 63.165 ;
      RECT  75.03 62.925 74.82 63.165 ;
      RECT  77.94 62.925 75.54 63.165 ;
      RECT  75.75 62.065 75.54 62.135 ;
      RECT  75.03 62.305 74.82 62.685 ;
      RECT  75.75 62.855 75.54 62.925 ;
      RECT  75.54 62.065 75.34 62.135 ;
      RECT  77.94 61.825 75.54 62.065 ;
      RECT  75.03 61.825 74.82 62.065 ;
      RECT  77.01 61.035 76.47 61.585 ;
      RECT  78.15 62.305 77.01 62.685 ;
      RECT  78.15 61.035 77.94 61.585 ;
      POLYGON  75.17 62.305 75.17 62.375 75.54 62.375 75.54 62.615 75.17 62.615 75.17 62.685 75.03 62.685 75.03 62.305 75.17 62.305 ;
      RECT  75.54 61.825 75.03 62.065 ;
      RECT  76.47 61.035 74.82 61.585 ;
      POLYGON  76.47 62.305 76.47 62.685 75.92 62.685 75.92 62.615 75.54 62.615 75.54 62.375 75.92 62.375 75.92 62.305 76.47 62.305 ;
      RECT  78.15 61.825 77.94 62.065 ;
      RECT  75.54 63.645 75.03 63.405 ;
      RECT  75.54 63.715 75.34 63.645 ;
      RECT  77.01 64.265 76.47 63.885 ;
      RECT  77.94 65.535 77.01 64.985 ;
      RECT  78.15 63.645 77.94 63.405 ;
      RECT  75.03 63.645 74.82 63.405 ;
      RECT  77.94 63.645 75.54 63.405 ;
      RECT  75.75 64.505 75.54 64.435 ;
      RECT  75.03 64.265 74.82 63.885 ;
      RECT  75.75 63.715 75.54 63.645 ;
      RECT  75.54 64.505 75.34 64.435 ;
      RECT  77.94 64.745 75.54 64.505 ;
      RECT  75.03 64.745 74.82 64.505 ;
      RECT  77.01 65.535 76.47 64.985 ;
      RECT  78.15 64.265 77.01 63.885 ;
      RECT  78.15 65.535 77.94 64.985 ;
      POLYGON  75.17 64.265 75.17 64.195 75.54 64.195 75.54 63.955 75.17 63.955 75.17 63.885 75.03 63.885 75.03 64.265 75.17 64.265 ;
      RECT  75.54 64.745 75.03 64.505 ;
      RECT  76.47 65.535 74.82 64.985 ;
      POLYGON  76.47 64.265 76.47 63.885 75.92 63.885 75.92 63.955 75.54 63.955 75.54 64.195 75.92 64.195 75.92 64.265 76.47 64.265 ;
      RECT  78.15 64.745 77.94 64.505 ;
      RECT  75.54 66.875 75.03 67.115 ;
      RECT  75.54 66.805 75.34 66.875 ;
      RECT  77.01 66.255 76.47 66.635 ;
      RECT  77.94 64.985 77.01 65.535 ;
      RECT  78.15 66.875 77.94 67.115 ;
      RECT  75.03 66.875 74.82 67.115 ;
      RECT  77.94 66.875 75.54 67.115 ;
      RECT  75.75 66.015 75.54 66.085 ;
      RECT  75.03 66.255 74.82 66.635 ;
      RECT  75.75 66.805 75.54 66.875 ;
      RECT  75.54 66.015 75.34 66.085 ;
      RECT  77.94 65.775 75.54 66.015 ;
      RECT  75.03 65.775 74.82 66.015 ;
      RECT  77.01 64.985 76.47 65.535 ;
      RECT  78.15 66.255 77.01 66.635 ;
      RECT  78.15 64.985 77.94 65.535 ;
      POLYGON  75.17 66.255 75.17 66.325 75.54 66.325 75.54 66.565 75.17 66.565 75.17 66.635 75.03 66.635 75.03 66.255 75.17 66.255 ;
      RECT  75.54 65.775 75.03 66.015 ;
      RECT  76.47 64.985 74.82 65.535 ;
      POLYGON  76.47 66.255 76.47 66.635 75.92 66.635 75.92 66.565 75.54 66.565 75.54 66.325 75.92 66.325 75.92 66.255 76.47 66.255 ;
      RECT  78.15 65.775 77.94 66.015 ;
      RECT  75.54 67.595 75.03 67.355 ;
      RECT  75.54 67.665 75.34 67.595 ;
      RECT  77.01 68.215 76.47 67.835 ;
      RECT  77.94 69.485 77.01 68.935 ;
      RECT  78.15 67.595 77.94 67.355 ;
      RECT  75.03 67.595 74.82 67.355 ;
      RECT  77.94 67.595 75.54 67.355 ;
      RECT  75.75 68.455 75.54 68.385 ;
      RECT  75.03 68.215 74.82 67.835 ;
      RECT  75.75 67.665 75.54 67.595 ;
      RECT  75.54 68.455 75.34 68.385 ;
      RECT  77.94 68.695 75.54 68.455 ;
      RECT  75.03 68.695 74.82 68.455 ;
      RECT  77.01 69.485 76.47 68.935 ;
      RECT  78.15 68.215 77.01 67.835 ;
      RECT  78.15 69.485 77.94 68.935 ;
      POLYGON  75.17 68.215 75.17 68.145 75.54 68.145 75.54 67.905 75.17 67.905 75.17 67.835 75.03 67.835 75.03 68.215 75.17 68.215 ;
      RECT  75.54 68.695 75.03 68.455 ;
      RECT  76.47 69.485 74.82 68.935 ;
      POLYGON  76.47 68.215 76.47 67.835 75.92 67.835 75.92 67.905 75.54 67.905 75.54 68.145 75.92 68.145 75.92 68.215 76.47 68.215 ;
      RECT  78.15 68.695 77.94 68.455 ;
      RECT  75.54 70.825 75.03 71.065 ;
      RECT  75.54 70.755 75.34 70.825 ;
      RECT  77.01 70.205 76.47 70.585 ;
      RECT  77.94 68.935 77.01 69.485 ;
      RECT  78.15 70.825 77.94 71.065 ;
      RECT  75.03 70.825 74.82 71.065 ;
      RECT  77.94 70.825 75.54 71.065 ;
      RECT  75.75 69.965 75.54 70.035 ;
      RECT  75.03 70.205 74.82 70.585 ;
      RECT  75.75 70.755 75.54 70.825 ;
      RECT  75.54 69.965 75.34 70.035 ;
      RECT  77.94 69.725 75.54 69.965 ;
      RECT  75.03 69.725 74.82 69.965 ;
      RECT  77.01 68.935 76.47 69.485 ;
      RECT  78.15 70.205 77.01 70.585 ;
      RECT  78.15 68.935 77.94 69.485 ;
      POLYGON  75.17 70.205 75.17 70.275 75.54 70.275 75.54 70.515 75.17 70.515 75.17 70.585 75.03 70.585 75.03 70.205 75.17 70.205 ;
      RECT  75.54 69.725 75.03 69.965 ;
      RECT  76.47 68.935 74.82 69.485 ;
      POLYGON  76.47 70.205 76.47 70.585 75.92 70.585 75.92 70.515 75.54 70.515 75.54 70.275 75.92 70.275 75.92 70.205 76.47 70.205 ;
      RECT  78.15 69.725 77.94 69.965 ;
      RECT  75.54 71.545 75.03 71.305 ;
      RECT  75.54 71.615 75.34 71.545 ;
      RECT  77.01 72.165 76.47 71.785 ;
      RECT  77.94 73.435 77.01 72.885 ;
      RECT  78.15 71.545 77.94 71.305 ;
      RECT  75.03 71.545 74.82 71.305 ;
      RECT  77.94 71.545 75.54 71.305 ;
      RECT  75.75 72.405 75.54 72.335 ;
      RECT  75.03 72.165 74.82 71.785 ;
      RECT  75.75 71.615 75.54 71.545 ;
      RECT  75.54 72.405 75.34 72.335 ;
      RECT  77.94 72.645 75.54 72.405 ;
      RECT  75.03 72.645 74.82 72.405 ;
      RECT  77.01 73.435 76.47 72.885 ;
      RECT  78.15 72.165 77.01 71.785 ;
      RECT  78.15 73.435 77.94 72.885 ;
      POLYGON  75.17 72.165 75.17 72.095 75.54 72.095 75.54 71.855 75.17 71.855 75.17 71.785 75.03 71.785 75.03 72.165 75.17 72.165 ;
      RECT  75.54 72.645 75.03 72.405 ;
      RECT  76.47 73.435 74.82 72.885 ;
      POLYGON  76.47 72.165 76.47 71.785 75.92 71.785 75.92 71.855 75.54 71.855 75.54 72.095 75.92 72.095 75.92 72.165 76.47 72.165 ;
      RECT  78.15 72.645 77.94 72.405 ;
      RECT  75.54 74.775 75.03 75.015 ;
      RECT  75.54 74.705 75.34 74.775 ;
      RECT  77.01 74.155 76.47 74.535 ;
      RECT  77.94 72.885 77.01 73.435 ;
      RECT  78.15 74.775 77.94 75.015 ;
      RECT  75.03 74.775 74.82 75.015 ;
      RECT  77.94 74.775 75.54 75.015 ;
      RECT  75.75 73.915 75.54 73.985 ;
      RECT  75.03 74.155 74.82 74.535 ;
      RECT  75.75 74.705 75.54 74.775 ;
      RECT  75.54 73.915 75.34 73.985 ;
      RECT  77.94 73.675 75.54 73.915 ;
      RECT  75.03 73.675 74.82 73.915 ;
      RECT  77.01 72.885 76.47 73.435 ;
      RECT  78.15 74.155 77.01 74.535 ;
      RECT  78.15 72.885 77.94 73.435 ;
      POLYGON  75.17 74.155 75.17 74.225 75.54 74.225 75.54 74.465 75.17 74.465 75.17 74.535 75.03 74.535 75.03 74.155 75.17 74.155 ;
      RECT  75.54 73.675 75.03 73.915 ;
      RECT  76.47 72.885 74.82 73.435 ;
      POLYGON  76.47 74.155 76.47 74.535 75.92 74.535 75.92 74.465 75.54 74.465 75.54 74.225 75.92 74.225 75.92 74.155 76.47 74.155 ;
      RECT  78.15 73.675 77.94 73.915 ;
      RECT  75.54 75.495 75.03 75.255 ;
      RECT  75.54 75.565 75.34 75.495 ;
      RECT  77.01 76.115 76.47 75.735 ;
      RECT  77.94 77.385 77.01 76.835 ;
      RECT  78.15 75.495 77.94 75.255 ;
      RECT  75.03 75.495 74.82 75.255 ;
      RECT  77.94 75.495 75.54 75.255 ;
      RECT  75.75 76.355 75.54 76.285 ;
      RECT  75.03 76.115 74.82 75.735 ;
      RECT  75.75 75.565 75.54 75.495 ;
      RECT  75.54 76.355 75.34 76.285 ;
      RECT  77.94 76.595 75.54 76.355 ;
      RECT  75.03 76.595 74.82 76.355 ;
      RECT  77.01 77.385 76.47 76.835 ;
      RECT  78.15 76.115 77.01 75.735 ;
      RECT  78.15 77.385 77.94 76.835 ;
      POLYGON  75.17 76.115 75.17 76.045 75.54 76.045 75.54 75.805 75.17 75.805 75.17 75.735 75.03 75.735 75.03 76.115 75.17 76.115 ;
      RECT  75.54 76.595 75.03 76.355 ;
      RECT  76.47 77.385 74.82 76.835 ;
      POLYGON  76.47 76.115 76.47 75.735 75.92 75.735 75.92 75.805 75.54 75.805 75.54 76.045 75.92 76.045 75.92 76.115 76.47 76.115 ;
      RECT  78.15 76.595 77.94 76.355 ;
      RECT  75.54 78.725 75.03 78.965 ;
      RECT  75.54 78.655 75.34 78.725 ;
      RECT  77.01 78.105 76.47 78.485 ;
      RECT  77.94 76.835 77.01 77.385 ;
      RECT  78.15 78.725 77.94 78.965 ;
      RECT  75.03 78.725 74.82 78.965 ;
      RECT  77.94 78.725 75.54 78.965 ;
      RECT  75.75 77.865 75.54 77.935 ;
      RECT  75.03 78.105 74.82 78.485 ;
      RECT  75.75 78.655 75.54 78.725 ;
      RECT  75.54 77.865 75.34 77.935 ;
      RECT  77.94 77.625 75.54 77.865 ;
      RECT  75.03 77.625 74.82 77.865 ;
      RECT  77.01 76.835 76.47 77.385 ;
      RECT  78.15 78.105 77.01 78.485 ;
      RECT  78.15 76.835 77.94 77.385 ;
      POLYGON  75.17 78.105 75.17 78.175 75.54 78.175 75.54 78.415 75.17 78.415 75.17 78.485 75.03 78.485 75.03 78.105 75.17 78.105 ;
      RECT  75.54 77.625 75.03 77.865 ;
      RECT  76.47 76.835 74.82 77.385 ;
      POLYGON  76.47 78.105 76.47 78.485 75.92 78.485 75.92 78.415 75.54 78.415 75.54 78.175 75.92 78.175 75.92 78.105 76.47 78.105 ;
      RECT  78.15 77.625 77.94 77.865 ;
      RECT  75.54 79.445 75.03 79.205 ;
      RECT  75.54 79.515 75.34 79.445 ;
      RECT  77.01 80.065 76.47 79.685 ;
      RECT  77.94 81.335 77.01 80.785 ;
      RECT  78.15 79.445 77.94 79.205 ;
      RECT  75.03 79.445 74.82 79.205 ;
      RECT  77.94 79.445 75.54 79.205 ;
      RECT  75.75 80.305 75.54 80.235 ;
      RECT  75.03 80.065 74.82 79.685 ;
      RECT  75.75 79.515 75.54 79.445 ;
      RECT  75.54 80.305 75.34 80.235 ;
      RECT  77.94 80.545 75.54 80.305 ;
      RECT  75.03 80.545 74.82 80.305 ;
      RECT  77.01 81.335 76.47 80.785 ;
      RECT  78.15 80.065 77.01 79.685 ;
      RECT  78.15 81.335 77.94 80.785 ;
      POLYGON  75.17 80.065 75.17 79.995 75.54 79.995 75.54 79.755 75.17 79.755 75.17 79.685 75.03 79.685 75.03 80.065 75.17 80.065 ;
      RECT  75.54 80.545 75.03 80.305 ;
      RECT  76.47 81.335 74.82 80.785 ;
      POLYGON  76.47 80.065 76.47 79.685 75.92 79.685 75.92 79.755 75.54 79.755 75.54 79.995 75.92 79.995 75.92 80.065 76.47 80.065 ;
      RECT  78.15 80.545 77.94 80.305 ;
      RECT  75.54 82.675 75.03 82.915 ;
      RECT  75.54 82.605 75.34 82.675 ;
      RECT  77.01 82.055 76.47 82.435 ;
      RECT  77.94 80.785 77.01 81.335 ;
      RECT  78.15 82.675 77.94 82.915 ;
      RECT  75.03 82.675 74.82 82.915 ;
      RECT  77.94 82.675 75.54 82.915 ;
      RECT  75.75 81.815 75.54 81.885 ;
      RECT  75.03 82.055 74.82 82.435 ;
      RECT  75.75 82.605 75.54 82.675 ;
      RECT  75.54 81.815 75.34 81.885 ;
      RECT  77.94 81.575 75.54 81.815 ;
      RECT  75.03 81.575 74.82 81.815 ;
      RECT  77.01 80.785 76.47 81.335 ;
      RECT  78.15 82.055 77.01 82.435 ;
      RECT  78.15 80.785 77.94 81.335 ;
      POLYGON  75.17 82.055 75.17 82.125 75.54 82.125 75.54 82.365 75.17 82.365 75.17 82.435 75.03 82.435 75.03 82.055 75.17 82.055 ;
      RECT  75.54 81.575 75.03 81.815 ;
      RECT  76.47 80.785 74.82 81.335 ;
      POLYGON  76.47 82.055 76.47 82.435 75.92 82.435 75.92 82.365 75.54 82.365 75.54 82.125 75.92 82.125 75.92 82.055 76.47 82.055 ;
      RECT  78.15 81.575 77.94 81.815 ;
      RECT  75.54 83.395 75.03 83.155 ;
      RECT  75.54 83.465 75.34 83.395 ;
      RECT  77.01 84.015 76.47 83.635 ;
      RECT  77.94 85.285 77.01 84.735 ;
      RECT  78.15 83.395 77.94 83.155 ;
      RECT  75.03 83.395 74.82 83.155 ;
      RECT  77.94 83.395 75.54 83.155 ;
      RECT  75.75 84.255 75.54 84.185 ;
      RECT  75.03 84.015 74.82 83.635 ;
      RECT  75.75 83.465 75.54 83.395 ;
      RECT  75.54 84.255 75.34 84.185 ;
      RECT  77.94 84.495 75.54 84.255 ;
      RECT  75.03 84.495 74.82 84.255 ;
      RECT  77.01 85.285 76.47 84.735 ;
      RECT  78.15 84.015 77.01 83.635 ;
      RECT  78.15 85.285 77.94 84.735 ;
      POLYGON  75.17 84.015 75.17 83.945 75.54 83.945 75.54 83.705 75.17 83.705 75.17 83.635 75.03 83.635 75.03 84.015 75.17 84.015 ;
      RECT  75.54 84.495 75.03 84.255 ;
      RECT  76.47 85.285 74.82 84.735 ;
      POLYGON  76.47 84.015 76.47 83.635 75.92 83.635 75.92 83.705 75.54 83.705 75.54 83.945 75.92 83.945 75.92 84.015 76.47 84.015 ;
      RECT  78.15 84.495 77.94 84.255 ;
      RECT  75.54 86.625 75.03 86.865 ;
      RECT  75.54 86.555 75.34 86.625 ;
      RECT  77.01 86.005 76.47 86.385 ;
      RECT  77.94 84.735 77.01 85.285 ;
      RECT  78.15 86.625 77.94 86.865 ;
      RECT  75.03 86.625 74.82 86.865 ;
      RECT  77.94 86.625 75.54 86.865 ;
      RECT  75.75 85.765 75.54 85.835 ;
      RECT  75.03 86.005 74.82 86.385 ;
      RECT  75.75 86.555 75.54 86.625 ;
      RECT  75.54 85.765 75.34 85.835 ;
      RECT  77.94 85.525 75.54 85.765 ;
      RECT  75.03 85.525 74.82 85.765 ;
      RECT  77.01 84.735 76.47 85.285 ;
      RECT  78.15 86.005 77.01 86.385 ;
      RECT  78.15 84.735 77.94 85.285 ;
      POLYGON  75.17 86.005 75.17 86.075 75.54 86.075 75.54 86.315 75.17 86.315 75.17 86.385 75.03 86.385 75.03 86.005 75.17 86.005 ;
      RECT  75.54 85.525 75.03 85.765 ;
      RECT  76.47 84.735 74.82 85.285 ;
      POLYGON  76.47 86.005 76.47 86.385 75.92 86.385 75.92 86.315 75.54 86.315 75.54 86.075 75.92 86.075 75.92 86.005 76.47 86.005 ;
      RECT  78.15 85.525 77.94 85.765 ;
      RECT  75.54 87.345 75.03 87.105 ;
      RECT  75.54 87.415 75.34 87.345 ;
      RECT  77.01 87.965 76.47 87.585 ;
      RECT  77.94 89.235 77.01 88.685 ;
      RECT  78.15 87.345 77.94 87.105 ;
      RECT  75.03 87.345 74.82 87.105 ;
      RECT  77.94 87.345 75.54 87.105 ;
      RECT  75.75 88.205 75.54 88.135 ;
      RECT  75.03 87.965 74.82 87.585 ;
      RECT  75.75 87.415 75.54 87.345 ;
      RECT  75.54 88.205 75.34 88.135 ;
      RECT  77.94 88.445 75.54 88.205 ;
      RECT  75.03 88.445 74.82 88.205 ;
      RECT  77.01 89.235 76.47 88.685 ;
      RECT  78.15 87.965 77.01 87.585 ;
      RECT  78.15 89.235 77.94 88.685 ;
      POLYGON  75.17 87.965 75.17 87.895 75.54 87.895 75.54 87.655 75.17 87.655 75.17 87.585 75.03 87.585 75.03 87.965 75.17 87.965 ;
      RECT  75.54 88.445 75.03 88.205 ;
      RECT  76.47 89.235 74.82 88.685 ;
      POLYGON  76.47 87.965 76.47 87.585 75.92 87.585 75.92 87.655 75.54 87.655 75.54 87.895 75.92 87.895 75.92 87.965 76.47 87.965 ;
      RECT  78.15 88.445 77.94 88.205 ;
      RECT  75.54 90.575 75.03 90.815 ;
      RECT  75.54 90.505 75.34 90.575 ;
      RECT  77.01 89.955 76.47 90.335 ;
      RECT  77.94 88.685 77.01 89.235 ;
      RECT  78.15 90.575 77.94 90.815 ;
      RECT  75.03 90.575 74.82 90.815 ;
      RECT  77.94 90.575 75.54 90.815 ;
      RECT  75.75 89.715 75.54 89.785 ;
      RECT  75.03 89.955 74.82 90.335 ;
      RECT  75.75 90.505 75.54 90.575 ;
      RECT  75.54 89.715 75.34 89.785 ;
      RECT  77.94 89.475 75.54 89.715 ;
      RECT  75.03 89.475 74.82 89.715 ;
      RECT  77.01 88.685 76.47 89.235 ;
      RECT  78.15 89.955 77.01 90.335 ;
      RECT  78.15 88.685 77.94 89.235 ;
      POLYGON  75.17 89.955 75.17 90.025 75.54 90.025 75.54 90.265 75.17 90.265 75.17 90.335 75.03 90.335 75.03 89.955 75.17 89.955 ;
      RECT  75.54 89.475 75.03 89.715 ;
      RECT  76.47 88.685 74.82 89.235 ;
      POLYGON  76.47 89.955 76.47 90.335 75.92 90.335 75.92 90.265 75.54 90.265 75.54 90.025 75.92 90.025 75.92 89.955 76.47 89.955 ;
      RECT  78.15 89.475 77.94 89.715 ;
      RECT  75.54 91.295 75.03 91.055 ;
      RECT  75.54 91.365 75.34 91.295 ;
      RECT  77.01 91.915 76.47 91.535 ;
      RECT  77.94 93.185 77.01 92.635 ;
      RECT  78.15 91.295 77.94 91.055 ;
      RECT  75.03 91.295 74.82 91.055 ;
      RECT  77.94 91.295 75.54 91.055 ;
      RECT  75.75 92.155 75.54 92.085 ;
      RECT  75.03 91.915 74.82 91.535 ;
      RECT  75.75 91.365 75.54 91.295 ;
      RECT  75.54 92.155 75.34 92.085 ;
      RECT  77.94 92.395 75.54 92.155 ;
      RECT  75.03 92.395 74.82 92.155 ;
      RECT  77.01 93.185 76.47 92.635 ;
      RECT  78.15 91.915 77.01 91.535 ;
      RECT  78.15 93.185 77.94 92.635 ;
      POLYGON  75.17 91.915 75.17 91.845 75.54 91.845 75.54 91.605 75.17 91.605 75.17 91.535 75.03 91.535 75.03 91.915 75.17 91.915 ;
      RECT  75.54 92.395 75.03 92.155 ;
      RECT  76.47 93.185 74.82 92.635 ;
      POLYGON  76.47 91.915 76.47 91.535 75.92 91.535 75.92 91.605 75.54 91.605 75.54 91.845 75.92 91.845 75.92 91.915 76.47 91.915 ;
      RECT  78.15 92.395 77.94 92.155 ;
      RECT  75.54 94.525 75.03 94.765 ;
      RECT  75.54 94.455 75.34 94.525 ;
      RECT  77.01 93.905 76.47 94.285 ;
      RECT  77.94 92.635 77.01 93.185 ;
      RECT  78.15 94.525 77.94 94.765 ;
      RECT  75.03 94.525 74.82 94.765 ;
      RECT  77.94 94.525 75.54 94.765 ;
      RECT  75.75 93.665 75.54 93.735 ;
      RECT  75.03 93.905 74.82 94.285 ;
      RECT  75.75 94.455 75.54 94.525 ;
      RECT  75.54 93.665 75.34 93.735 ;
      RECT  77.94 93.425 75.54 93.665 ;
      RECT  75.03 93.425 74.82 93.665 ;
      RECT  77.01 92.635 76.47 93.185 ;
      RECT  78.15 93.905 77.01 94.285 ;
      RECT  78.15 92.635 77.94 93.185 ;
      POLYGON  75.17 93.905 75.17 93.975 75.54 93.975 75.54 94.215 75.17 94.215 75.17 94.285 75.03 94.285 75.03 93.905 75.17 93.905 ;
      RECT  75.54 93.425 75.03 93.665 ;
      RECT  76.47 92.635 74.82 93.185 ;
      POLYGON  76.47 93.905 76.47 94.285 75.92 94.285 75.92 94.215 75.54 94.215 75.54 93.975 75.92 93.975 75.92 93.905 76.47 93.905 ;
      RECT  78.15 93.425 77.94 93.665 ;
      RECT  74.82 59.455 77.94 59.695 ;
      RECT  74.82 60.555 77.94 60.795 ;
      RECT  74.82 62.925 77.94 63.165 ;
      RECT  74.82 61.825 77.94 62.065 ;
      RECT  74.82 63.405 77.94 63.645 ;
      RECT  74.82 64.505 77.94 64.745 ;
      RECT  74.82 66.875 77.94 67.115 ;
      RECT  74.82 65.775 77.94 66.015 ;
      RECT  74.82 67.355 77.94 67.595 ;
      RECT  74.82 68.455 77.94 68.695 ;
      RECT  74.82 70.825 77.94 71.065 ;
      RECT  74.82 69.725 77.94 69.965 ;
      RECT  74.82 71.305 77.94 71.545 ;
      RECT  74.82 72.405 77.94 72.645 ;
      RECT  74.82 74.775 77.94 75.015 ;
      RECT  74.82 73.675 77.94 73.915 ;
      RECT  74.82 75.255 77.94 75.495 ;
      RECT  74.82 76.355 77.94 76.595 ;
      RECT  74.82 78.725 77.94 78.965 ;
      RECT  74.82 77.625 77.94 77.865 ;
      RECT  74.82 79.205 77.94 79.445 ;
      RECT  74.82 80.305 77.94 80.545 ;
      RECT  74.82 82.675 77.94 82.915 ;
      RECT  74.82 81.575 77.94 81.815 ;
      RECT  74.82 83.155 77.94 83.395 ;
      RECT  74.82 84.255 77.94 84.495 ;
      RECT  74.82 86.625 77.94 86.865 ;
      RECT  74.82 85.525 77.94 85.765 ;
      RECT  74.82 87.105 77.94 87.345 ;
      RECT  74.82 88.205 77.94 88.445 ;
      RECT  74.82 90.575 77.94 90.815 ;
      RECT  74.82 89.475 77.94 89.715 ;
      RECT  74.82 91.055 77.94 91.295 ;
      RECT  74.82 92.155 77.94 92.395 ;
      RECT  74.82 94.525 77.94 94.765 ;
      RECT  74.82 93.425 77.94 93.665 ;
      RECT  59.22 62.925 77.94 63.165 ;
      RECT  59.22 61.825 77.94 62.065 ;
      RECT  59.22 63.405 77.94 63.645 ;
      RECT  59.22 64.505 77.94 64.745 ;
      RECT  59.22 66.875 77.94 67.115 ;
      RECT  59.22 65.775 77.94 66.015 ;
      RECT  59.22 67.355 77.94 67.595 ;
      RECT  59.22 68.455 77.94 68.695 ;
      RECT  59.22 70.825 77.94 71.065 ;
      RECT  59.22 69.725 77.94 69.965 ;
      RECT  59.22 71.305 77.94 71.545 ;
      RECT  59.22 72.405 77.94 72.645 ;
      RECT  59.22 74.775 77.94 75.015 ;
      RECT  59.22 73.675 77.94 73.915 ;
      RECT  59.22 75.255 77.94 75.495 ;
      RECT  59.22 76.355 77.94 76.595 ;
      RECT  59.22 78.725 77.94 78.965 ;
      RECT  59.22 77.625 77.94 77.865 ;
      RECT  59.22 79.205 77.94 79.445 ;
      RECT  59.22 80.305 77.94 80.545 ;
      RECT  59.22 82.675 77.94 82.915 ;
      RECT  59.22 81.575 77.94 81.815 ;
      RECT  59.22 83.155 77.94 83.395 ;
      RECT  59.22 84.255 77.94 84.495 ;
      RECT  59.22 86.625 77.94 86.865 ;
      RECT  59.22 85.525 77.94 85.765 ;
      RECT  59.22 87.105 77.94 87.345 ;
      RECT  59.22 88.205 77.94 88.445 ;
      RECT  59.22 90.575 77.94 90.815 ;
      RECT  59.22 89.475 77.94 89.715 ;
      RECT  59.22 91.055 77.94 91.295 ;
      RECT  59.22 92.155 77.94 92.395 ;
      RECT  59.22 59.455 77.94 59.695 ;
      RECT  59.22 93.425 77.94 93.665 ;
      RECT  63.99 70.205 64.53 70.585 ;
      RECT  63.99 86.005 64.53 86.385 ;
      RECT  63.99 61.035 64.53 61.585 ;
      RECT  72.63 88.685 73.17 89.235 ;
      RECT  63.99 80.785 64.53 81.335 ;
      RECT  72.63 71.785 73.17 72.165 ;
      RECT  72.63 61.035 73.17 61.585 ;
      RECT  72.63 74.155 73.17 74.535 ;
      RECT  72.63 86.005 73.17 86.385 ;
      RECT  63.99 91.535 64.53 91.915 ;
      RECT  72.63 72.885 73.17 73.435 ;
      RECT  72.63 64.985 73.17 65.535 ;
      RECT  63.99 76.835 64.53 77.385 ;
      RECT  63.99 87.585 64.53 87.965 ;
      RECT  63.99 68.935 64.53 69.485 ;
      RECT  72.63 75.735 73.17 76.115 ;
      RECT  63.99 75.735 64.53 76.115 ;
      RECT  72.63 66.255 73.17 66.635 ;
      RECT  63.99 78.105 64.53 78.485 ;
      RECT  72.63 92.635 73.17 93.185 ;
      RECT  63.99 93.905 64.53 94.285 ;
      RECT  63.99 82.055 64.53 82.435 ;
      RECT  63.99 66.255 64.53 66.635 ;
      RECT  72.63 68.935 73.17 69.485 ;
      RECT  72.63 59.935 73.17 60.315 ;
      RECT  63.99 83.635 64.53 84.015 ;
      RECT  72.63 62.305 73.17 62.685 ;
      RECT  72.63 67.835 73.17 68.215 ;
      RECT  63.99 62.305 64.53 62.685 ;
      RECT  72.63 76.835 73.17 77.385 ;
      RECT  63.99 59.935 64.53 60.315 ;
      RECT  72.63 87.585 73.17 87.965 ;
      RECT  63.99 71.785 64.53 72.165 ;
      RECT  72.63 79.685 73.17 80.065 ;
      RECT  63.99 64.985 64.53 65.535 ;
      RECT  72.63 80.785 73.17 81.335 ;
      RECT  63.99 88.685 64.53 89.235 ;
      RECT  72.63 91.535 73.17 91.915 ;
      RECT  72.63 83.635 73.17 84.015 ;
      RECT  63.99 79.685 64.53 80.065 ;
      RECT  72.63 78.105 73.17 78.485 ;
      RECT  72.63 82.055 73.17 82.435 ;
      RECT  72.63 84.735 73.17 85.285 ;
      RECT  63.99 92.635 64.53 93.185 ;
      RECT  63.99 84.735 64.53 85.285 ;
      RECT  63.99 72.885 64.53 73.435 ;
      RECT  63.99 67.835 64.53 68.215 ;
      RECT  72.63 93.905 73.17 94.285 ;
      RECT  72.63 89.955 73.17 90.335 ;
      RECT  63.99 63.885 64.53 64.265 ;
      RECT  72.63 70.205 73.17 70.585 ;
      RECT  63.99 74.155 64.53 74.535 ;
      RECT  72.63 63.885 73.17 64.265 ;
      RECT  63.99 89.955 64.53 90.335 ;
      RECT  65.46 52.385 62.34 52.525 ;
      RECT  65.46 52.385 68.58 52.525 ;
      RECT  71.7 52.385 68.58 52.525 ;
      RECT  65.46 101.835 68.58 101.695 ;
      RECT  71.7 101.835 68.58 101.695 ;
      RECT  71.7 101.835 74.82 101.695 ;
      RECT  48.4 61.31 48.54 92.91 ;
      RECT  48.4 61.31 48.54 92.91 ;
      RECT  88.76 61.31 88.62 92.91 ;
      RECT  88.76 61.31 88.62 92.91 ;
      RECT  56.12 28.475 56.26 60.51 ;
      RECT  79.8 93.71 79.94 114.85 ;
      RECT  57.36 28.475 57.5 60.51 ;
      RECT  79.18 93.71 79.32 114.85 ;
      RECT  56.74 28.475 56.88 60.51 ;
      RECT  57.98 28.475 58.12 60.51 ;
      RECT  78.56 93.71 78.7 114.85 ;
      RECT  5.41 3.045 5.74 3.305 ;
      RECT  0.685 2.69 1.015 2.95 ;
      RECT  5.02 2.29 5.35 2.55 ;
      RECT  1.845 3.46 2.115 3.78 ;
      RECT  0.685 2.69 1.015 2.95 ;
      RECT  9.28 2.445 9.42 2.585 ;
      RECT  7.56 4.355 7.7 4.495 ;
      RECT  1.845 3.46 2.115 3.78 ;
      RECT  5.41 11.095 5.74 10.835 ;
      RECT  0.685 11.45 1.015 11.19 ;
      RECT  5.02 11.85 5.35 11.59 ;
      RECT  1.845 10.68 2.115 10.36 ;
      RECT  0.685 11.45 1.015 11.19 ;
      RECT  9.28 11.695 9.42 11.555 ;
      RECT  7.56 9.785 7.7 9.645 ;
      RECT  1.845 10.68 2.115 10.36 ;
      RECT  0.685 2.69 1.015 2.95 ;
      RECT  0.685 11.19 1.015 11.45 ;
      RECT  9.28 2.445 9.42 2.585 ;
      RECT  7.56 4.355 7.7 4.495 ;
      RECT  9.28 11.555 9.42 11.695 ;
      RECT  7.56 9.645 7.7 9.785 ;
      RECT  1.845 0.0 1.985 14.14 ;
      RECT  8.88 57.36 8.74 59.97 ;
      RECT  1.085 57.36 0.945 104.77 ;
      RECT  0.685 2.69 1.015 2.95 ;
      RECT  0.685 11.19 1.015 11.45 ;
      RECT  13.815 3.275 13.955 3.415 ;
      RECT  8.74 57.36 8.88 59.97 ;
      RECT  16.85 53.085 19.61 53.225 ;
      RECT  16.85 31.745 19.61 31.885 ;
      RECT  18.64 39.005 19.61 39.145 ;
      RECT  18.88 24.675 19.61 24.815 ;
      RECT  18.88 3.465 19.61 3.605 ;
      RECT  131.75 137.035 131.42 136.775 ;
      RECT  136.475 137.39 136.145 137.13 ;
      RECT  132.14 137.79 131.81 137.53 ;
      RECT  135.315 136.62 135.045 136.3 ;
      RECT  136.475 137.39 136.145 137.13 ;
      RECT  127.88 137.635 127.74 137.495 ;
      RECT  129.6 135.725 129.46 135.585 ;
      RECT  135.315 136.62 135.045 136.3 ;
      RECT  136.475 137.39 136.145 137.13 ;
      RECT  127.88 137.635 127.74 137.495 ;
      RECT  129.6 135.725 129.46 135.585 ;
      RECT  135.315 140.08 135.175 133.01 ;
      RECT  128.28 96.86 128.42 94.25 ;
      RECT  136.075 96.86 136.215 49.45 ;
      RECT  136.475 137.39 136.145 137.13 ;
      RECT  123.765 136.805 123.625 136.665 ;
      RECT  128.42 96.86 128.28 94.25 ;
      RECT  120.73 101.135 117.97 100.995 ;
      RECT  118.94 108.525 117.97 108.385 ;
      RECT  118.7 115.405 117.97 115.265 ;
      RECT  118.7 136.695 117.97 136.555 ;
      RECT  19.18 111.605 19.51 111.865 ;
      RECT  14.455 111.25 14.785 111.51 ;
      RECT  18.79 110.85 19.12 111.11 ;
      RECT  15.615 112.02 15.885 112.34 ;
      RECT  19.18 119.655 19.51 119.395 ;
      RECT  14.455 120.01 14.785 119.75 ;
      RECT  18.79 120.41 19.12 120.15 ;
      RECT  15.615 119.24 15.885 118.92 ;
      RECT  19.18 125.745 19.51 126.005 ;
      RECT  14.455 125.39 14.785 125.65 ;
      RECT  18.79 124.99 19.12 125.25 ;
      RECT  15.615 126.16 15.885 126.48 ;
      RECT  19.18 133.795 19.51 133.535 ;
      RECT  14.455 134.15 14.785 133.89 ;
      RECT  18.79 134.55 19.12 134.29 ;
      RECT  15.615 133.38 15.885 133.06 ;
      RECT  14.455 111.25 14.785 111.51 ;
      RECT  14.455 119.75 14.785 120.01 ;
      RECT  14.455 125.39 14.785 125.65 ;
      RECT  14.455 133.89 14.785 134.15 ;
      RECT  19.18 111.605 19.51 111.865 ;
      RECT  19.18 119.395 19.51 119.655 ;
      RECT  19.18 125.745 19.51 126.005 ;
      RECT  19.18 133.535 19.51 133.795 ;
      RECT  118.4 42.615 118.07 42.355 ;
      RECT  123.125 42.97 122.795 42.71 ;
      RECT  118.79 43.37 118.46 43.11 ;
      RECT  121.965 42.2 121.695 41.88 ;
      RECT  118.4 34.565 118.07 34.825 ;
      RECT  123.125 34.21 122.795 34.47 ;
      RECT  118.79 33.81 118.46 34.07 ;
      RECT  121.965 34.98 121.695 35.3 ;
      RECT  118.4 28.475 118.07 28.215 ;
      RECT  123.125 28.83 122.795 28.57 ;
      RECT  118.79 29.23 118.46 28.97 ;
      RECT  121.965 28.06 121.695 27.74 ;
      RECT  118.4 20.425 118.07 20.685 ;
      RECT  123.125 20.07 122.795 20.33 ;
      RECT  118.79 19.67 118.46 19.93 ;
      RECT  121.965 20.84 121.695 21.16 ;
      RECT  123.125 42.97 122.795 42.71 ;
      RECT  123.125 34.47 122.795 34.21 ;
      RECT  123.125 28.83 122.795 28.57 ;
      RECT  123.125 20.33 122.795 20.07 ;
      RECT  118.4 42.615 118.07 42.355 ;
      RECT  118.4 34.825 118.07 34.565 ;
      RECT  118.4 28.475 118.07 28.215 ;
      RECT  118.4 20.685 118.07 20.425 ;
      RECT  30.86 3.045 31.19 3.305 ;
      RECT  26.135 2.69 26.465 2.95 ;
      RECT  30.47 2.29 30.8 2.55 ;
      RECT  27.295 3.46 27.565 3.78 ;
      RECT  36.7 3.045 37.03 3.305 ;
      RECT  31.975 2.69 32.305 2.95 ;
      RECT  36.31 2.29 36.64 2.55 ;
      RECT  33.135 3.46 33.405 3.78 ;
      RECT  26.135 2.69 26.465 2.95 ;
      RECT  31.975 2.69 32.305 2.95 ;
      RECT  30.86 3.045 31.19 3.305 ;
      RECT  36.7 3.045 37.03 3.305 ;
   LAYER  m3 ;
      RECT  63.655 58.26 64.145 58.75 ;
      RECT  63.655 95.47 64.145 95.96 ;
      RECT  73.015 58.26 73.505 58.75 ;
      RECT  73.015 95.47 73.505 95.96 ;
      RECT  69.895 58.26 70.385 58.75 ;
      RECT  66.775 58.26 67.265 58.75 ;
      RECT  69.895 95.96 70.385 95.47 ;
      RECT  66.775 95.96 67.265 95.47 ;
      RECT  60.175 74.1 60.665 74.59 ;
      RECT  60.175 66.2 60.665 66.69 ;
      RECT  60.175 70.15 60.665 70.64 ;
      RECT  60.175 91.48 60.665 91.97 ;
      RECT  60.175 89.9 60.665 90.39 ;
      RECT  60.175 71.73 60.665 72.22 ;
      RECT  60.175 84.765 60.665 85.255 ;
      RECT  60.175 61.065 60.665 61.555 ;
      RECT  60.175 72.915 60.665 73.405 ;
      RECT  60.175 76.865 60.665 77.355 ;
      RECT  60.175 78.05 60.665 78.54 ;
      RECT  60.175 65.015 60.665 65.505 ;
      RECT  60.175 87.53 60.665 88.02 ;
      RECT  60.175 68.965 60.665 69.455 ;
      RECT  60.175 75.68 60.665 76.17 ;
      RECT  60.175 92.665 60.665 93.155 ;
      RECT  60.175 82.0 60.665 82.49 ;
      RECT  60.175 85.95 60.665 86.44 ;
      RECT  60.175 59.88 60.665 60.37 ;
      RECT  60.175 80.815 60.665 81.305 ;
      RECT  60.175 83.58 60.665 84.07 ;
      RECT  60.175 79.63 60.665 80.12 ;
      RECT  60.175 88.715 60.665 89.205 ;
      RECT  60.175 67.78 60.665 68.27 ;
      RECT  60.175 63.83 60.665 64.32 ;
      RECT  60.175 93.85 60.665 94.34 ;
      RECT  60.175 62.25 60.665 62.74 ;
      RECT  76.495 71.73 76.985 72.22 ;
      RECT  76.495 88.715 76.985 89.205 ;
      RECT  76.495 62.25 76.985 62.74 ;
      RECT  76.495 82.0 76.985 82.49 ;
      RECT  76.495 70.15 76.985 70.64 ;
      RECT  76.495 75.68 76.985 76.17 ;
      RECT  76.495 80.815 76.985 81.305 ;
      RECT  76.495 61.065 76.985 61.555 ;
      RECT  76.495 89.9 76.985 90.39 ;
      RECT  76.495 63.83 76.985 64.32 ;
      RECT  76.495 68.965 76.985 69.455 ;
      RECT  76.495 93.85 76.985 94.34 ;
      RECT  76.495 74.1 76.985 74.59 ;
      RECT  76.495 85.95 76.985 86.44 ;
      RECT  76.495 92.665 76.985 93.155 ;
      RECT  76.495 83.58 76.985 84.07 ;
      RECT  76.495 84.765 76.985 85.255 ;
      RECT  76.495 65.015 76.985 65.505 ;
      RECT  76.495 59.88 76.985 60.37 ;
      RECT  76.495 78.05 76.985 78.54 ;
      RECT  76.495 66.2 76.985 66.69 ;
      RECT  76.495 67.78 76.985 68.27 ;
      RECT  76.495 91.48 76.985 91.97 ;
      RECT  76.495 76.865 76.985 77.355 ;
      RECT  76.495 87.53 76.985 88.02 ;
      RECT  76.495 72.915 76.985 73.405 ;
      RECT  76.495 79.63 76.985 80.12 ;
      RECT  63.655 95.47 64.145 95.96 ;
      RECT  69.99 95.565 70.29 95.865 ;
      RECT  69.99 58.355 70.29 58.655 ;
      RECT  66.87 95.565 67.17 95.865 ;
      RECT  63.655 58.26 64.145 58.75 ;
      RECT  73.015 95.47 73.505 95.96 ;
      RECT  66.87 58.355 67.17 58.655 ;
      RECT  73.015 58.26 73.505 58.75 ;
      RECT  60.27 87.625 60.57 87.925 ;
      RECT  76.59 74.195 76.89 74.495 ;
      RECT  76.59 61.16 76.89 61.46 ;
      RECT  60.27 84.86 60.57 85.16 ;
      RECT  76.59 88.81 76.89 89.11 ;
      RECT  60.27 65.11 60.57 65.41 ;
      RECT  60.27 83.675 60.57 83.975 ;
      RECT  60.27 88.81 60.57 89.11 ;
      RECT  60.27 75.775 60.57 76.075 ;
      RECT  76.59 75.775 76.89 76.075 ;
      RECT  76.59 59.975 76.89 60.275 ;
      RECT  60.27 76.96 60.57 77.26 ;
      RECT  76.59 82.095 76.89 82.395 ;
      RECT  76.59 93.945 76.89 94.245 ;
      RECT  60.27 73.01 60.57 73.31 ;
      RECT  60.27 91.575 60.57 91.875 ;
      RECT  76.59 89.995 76.89 90.295 ;
      RECT  76.59 71.825 76.89 72.125 ;
      RECT  60.27 63.925 60.57 64.225 ;
      RECT  76.59 69.06 76.89 69.36 ;
      RECT  76.59 73.01 76.89 73.31 ;
      RECT  60.27 79.725 60.57 80.025 ;
      RECT  60.27 92.76 60.57 93.06 ;
      RECT  76.59 70.245 76.89 70.545 ;
      RECT  76.59 67.875 76.89 68.175 ;
      RECT  76.59 63.925 76.89 64.225 ;
      RECT  60.27 86.045 60.57 86.345 ;
      RECT  60.27 82.095 60.57 82.395 ;
      RECT  60.27 62.345 60.57 62.645 ;
      RECT  60.27 66.295 60.57 66.595 ;
      RECT  76.59 62.345 76.89 62.645 ;
      RECT  76.59 76.96 76.89 77.26 ;
      RECT  60.27 59.975 60.57 60.275 ;
      RECT  76.59 83.675 76.89 83.975 ;
      RECT  60.27 74.195 60.57 74.495 ;
      RECT  76.59 80.91 76.89 81.21 ;
      RECT  76.59 84.86 76.89 85.16 ;
      RECT  76.59 66.295 76.89 66.595 ;
      RECT  60.27 89.995 60.57 90.295 ;
      RECT  76.59 65.11 76.89 65.41 ;
      RECT  60.27 80.91 60.57 81.21 ;
      RECT  76.59 87.625 76.89 87.925 ;
      RECT  76.59 78.145 76.89 78.445 ;
      RECT  60.27 61.16 60.57 61.46 ;
      RECT  76.59 91.575 76.89 91.875 ;
      RECT  60.27 70.245 60.57 70.545 ;
      RECT  60.27 78.145 60.57 78.445 ;
      RECT  60.27 67.875 60.57 68.175 ;
      RECT  60.27 69.06 60.57 69.36 ;
      RECT  76.59 86.045 76.89 86.345 ;
      RECT  60.27 71.825 60.57 72.125 ;
      RECT  60.27 93.945 60.57 94.245 ;
      RECT  76.59 79.725 76.89 80.025 ;
      RECT  76.59 92.76 76.89 93.06 ;
      RECT  64.74 55.305 64.25 55.795 ;
      RECT  66.18 55.305 66.67 55.795 ;
      RECT  70.98 55.305 70.49 55.795 ;
      RECT  62.34 52.305 71.7 52.605 ;
      RECT  64.25 55.305 64.74 55.795 ;
      RECT  66.18 55.305 66.67 55.795 ;
      RECT  70.49 55.305 70.98 55.795 ;
      RECT  65.46 50.61 71.7 50.91 ;
      RECT  67.12 41.695 67.61 42.185 ;
      RECT  67.06 45.885 67.55 46.375 ;
      RECT  68.93 41.695 69.42 42.185 ;
      RECT  68.99 45.885 69.48 46.375 ;
      RECT  67.47 49.755 67.96 50.245 ;
      RECT  68.58 49.755 69.07 50.245 ;
      RECT  68.93 40.085 69.42 40.575 ;
      RECT  67.12 40.085 67.61 40.575 ;
      RECT  69.555 33.935 70.045 34.425 ;
      RECT  69.455 29.185 69.945 29.675 ;
      RECT  66.595 29.185 67.085 29.675 ;
      RECT  66.495 33.935 66.985 34.425 ;
      RECT  66.55 36.12 67.04 36.61 ;
      RECT  67.1 32.275 67.59 32.765 ;
      RECT  69.5 36.12 69.99 36.61 ;
      RECT  69.525 31.265 70.015 31.755 ;
      RECT  68.95 32.275 69.44 32.765 ;
      RECT  66.525 31.265 67.015 31.755 ;
      RECT  65.46 50.91 71.7 50.61 ;
      RECT  62.34 52.605 71.7 52.305 ;
      RECT  64.25 55.795 64.74 55.305 ;
      RECT  66.495 34.425 66.985 33.935 ;
      RECT  66.595 29.675 67.085 29.185 ;
      RECT  66.18 55.795 66.67 55.305 ;
      RECT  68.99 46.375 69.48 45.885 ;
      RECT  67.12 42.185 67.61 41.695 ;
      RECT  69.455 29.675 69.945 29.185 ;
      RECT  68.93 42.185 69.42 41.695 ;
      RECT  67.06 46.375 67.55 45.885 ;
      RECT  70.49 55.795 70.98 55.305 ;
      RECT  69.555 34.425 70.045 33.935 ;
      RECT  68.93 40.575 69.42 40.085 ;
      RECT  69.525 31.755 70.015 31.265 ;
      RECT  66.525 31.755 67.015 31.265 ;
      RECT  67.12 40.575 67.61 40.085 ;
      RECT  66.55 36.61 67.04 36.12 ;
      RECT  69.5 36.61 69.99 36.12 ;
      RECT  68.58 50.245 69.07 49.755 ;
      RECT  67.47 50.245 67.96 49.755 ;
      RECT  67.1 32.765 67.59 32.275 ;
      RECT  68.95 32.765 69.44 32.275 ;
      RECT  66.18 98.915 66.67 98.425 ;
      RECT  70.98 98.915 70.49 98.425 ;
      RECT  72.42 98.915 72.91 98.425 ;
      RECT  65.46 101.915 74.82 101.615 ;
      RECT  72.42 98.915 72.91 98.425 ;
      RECT  66.18 98.915 66.67 98.425 ;
      RECT  70.49 98.915 70.98 98.425 ;
      RECT  65.46 103.61 71.7 103.31 ;
      RECT  67.12 112.525 67.61 112.035 ;
      RECT  67.06 108.335 67.55 107.845 ;
      RECT  68.93 112.525 69.42 112.035 ;
      RECT  68.99 108.335 69.48 107.845 ;
      RECT  67.47 104.465 67.96 103.975 ;
      RECT  68.58 104.465 69.07 103.975 ;
      RECT  68.93 114.135 69.42 113.645 ;
      RECT  67.12 114.135 67.61 113.645 ;
      RECT  65.46 103.31 71.7 103.61 ;
      RECT  65.46 101.615 74.82 101.915 ;
      RECT  67.12 112.035 67.61 112.525 ;
      RECT  70.49 98.425 70.98 98.915 ;
      RECT  67.06 107.845 67.55 108.335 ;
      RECT  66.18 98.425 66.67 98.915 ;
      RECT  68.93 112.035 69.42 112.525 ;
      RECT  68.99 107.845 69.48 108.335 ;
      RECT  72.42 98.425 72.91 98.915 ;
      RECT  68.58 103.975 69.07 104.465 ;
      RECT  68.93 113.645 69.42 114.135 ;
      RECT  67.47 103.975 67.96 104.465 ;
      RECT  67.12 113.645 67.61 114.135 ;
      RECT  32.6 67.17 33.09 67.66 ;
      RECT  25.985 63.185 26.475 63.675 ;
      RECT  35.855 67.135 36.345 67.625 ;
      RECT  32.6 63.22 33.09 63.71 ;
      RECT  35.855 63.185 36.345 63.675 ;
      RECT  24.625 63.185 25.115 63.675 ;
      RECT  34.495 63.185 34.985 63.675 ;
      RECT  34.495 67.135 34.985 67.625 ;
      RECT  30.475 63.22 30.965 63.71 ;
      RECT  30.475 67.17 30.965 67.66 ;
      RECT  32.6 79.02 33.09 79.51 ;
      RECT  25.985 75.035 26.475 75.525 ;
      RECT  35.855 78.985 36.345 79.475 ;
      RECT  32.6 75.07 33.09 75.56 ;
      RECT  35.855 75.035 36.345 75.525 ;
      RECT  24.625 75.035 25.115 75.525 ;
      RECT  34.495 75.035 34.985 75.525 ;
      RECT  34.495 78.985 34.985 79.475 ;
      RECT  30.475 75.07 30.965 75.56 ;
      RECT  30.475 79.02 30.965 79.51 ;
      RECT  35.855 63.185 36.345 63.675 ;
      RECT  46.925 65.16 47.415 65.65 ;
      RECT  46.925 69.11 47.415 69.6 ;
      RECT  43.67 85.07 44.16 85.56 ;
      RECT  43.67 90.87 44.16 91.36 ;
      RECT  46.925 84.91 47.415 85.4 ;
      RECT  46.925 67.135 47.415 67.625 ;
      RECT  43.67 65.32 44.16 65.81 ;
      RECT  35.855 75.035 36.345 75.525 ;
      RECT  46.925 77.01 47.415 77.5 ;
      RECT  46.925 71.085 47.415 71.575 ;
      RECT  32.6 63.22 33.09 63.71 ;
      RECT  43.67 77.17 44.16 77.66 ;
      RECT  46.925 80.96 47.415 81.45 ;
      RECT  25.985 75.035 26.475 75.525 ;
      RECT  43.67 86.92 44.16 87.41 ;
      RECT  46.925 63.185 47.415 63.675 ;
      RECT  43.67 63.22 44.16 63.71 ;
      RECT  25.985 63.185 26.475 63.675 ;
      RECT  43.67 79.02 44.16 79.51 ;
      RECT  43.67 75.07 44.16 75.56 ;
      RECT  32.6 67.17 33.09 67.66 ;
      RECT  46.925 75.035 47.415 75.525 ;
      RECT  35.855 78.985 36.345 79.475 ;
      RECT  46.925 88.86 47.415 89.35 ;
      RECT  43.67 67.17 44.16 67.66 ;
      RECT  46.925 86.885 47.415 87.375 ;
      RECT  43.67 81.12 44.16 81.61 ;
      RECT  43.67 82.97 44.16 83.46 ;
      RECT  35.855 67.135 36.345 67.625 ;
      RECT  43.67 69.27 44.16 69.76 ;
      RECT  43.67 71.12 44.16 71.61 ;
      RECT  46.925 82.935 47.415 83.425 ;
      RECT  46.925 90.835 47.415 91.325 ;
      RECT  46.925 78.985 47.415 79.475 ;
      RECT  32.6 75.07 33.09 75.56 ;
      RECT  43.67 73.22 44.16 73.71 ;
      RECT  46.925 73.06 47.415 73.55 ;
      RECT  32.6 79.02 33.09 79.51 ;
      RECT  43.67 89.02 44.16 89.51 ;
      RECT  41.545 81.11 42.035 81.6 ;
      RECT  41.545 89.01 42.035 89.5 ;
      RECT  45.565 88.86 46.055 89.35 ;
      RECT  30.475 67.17 30.965 67.66 ;
      RECT  41.545 73.21 42.035 73.7 ;
      RECT  34.495 75.035 34.985 75.525 ;
      RECT  45.565 73.06 46.055 73.55 ;
      RECT  41.545 77.16 42.035 77.65 ;
      RECT  24.625 63.185 25.115 63.675 ;
      RECT  45.565 63.185 46.055 63.675 ;
      RECT  30.475 63.22 30.965 63.71 ;
      RECT  41.545 63.22 42.035 63.71 ;
      RECT  41.545 71.12 42.035 71.61 ;
      RECT  41.545 69.26 42.035 69.75 ;
      RECT  41.545 79.02 42.035 79.51 ;
      RECT  45.565 77.01 46.055 77.5 ;
      RECT  41.545 85.06 42.035 85.55 ;
      RECT  45.565 84.91 46.055 85.4 ;
      RECT  45.565 69.11 46.055 69.6 ;
      RECT  45.565 65.16 46.055 65.65 ;
      RECT  41.545 75.07 42.035 75.56 ;
      RECT  41.545 82.97 42.035 83.46 ;
      RECT  45.565 82.935 46.055 83.425 ;
      RECT  45.565 78.985 46.055 79.475 ;
      RECT  41.545 86.92 42.035 87.41 ;
      RECT  41.545 90.87 42.035 91.36 ;
      RECT  34.495 63.185 34.985 63.675 ;
      RECT  30.475 75.07 30.965 75.56 ;
      RECT  34.495 78.985 34.985 79.475 ;
      RECT  45.565 67.135 46.055 67.625 ;
      RECT  45.565 86.885 46.055 87.375 ;
      RECT  34.495 67.135 34.985 67.625 ;
      RECT  45.565 80.96 46.055 81.45 ;
      RECT  41.545 65.31 42.035 65.8 ;
      RECT  30.475 79.02 30.965 79.51 ;
      RECT  41.545 67.17 42.035 67.66 ;
      RECT  45.565 90.835 46.055 91.325 ;
      RECT  45.565 75.035 46.055 75.525 ;
      RECT  24.625 75.035 25.115 75.525 ;
      RECT  45.565 71.085 46.055 71.575 ;
      RECT  25.985 63.185 26.475 63.675 ;
      RECT  51.28 76.785 51.77 77.275 ;
      RECT  46.925 82.935 47.415 83.425 ;
      RECT  35.855 78.985 36.345 79.475 ;
      RECT  35.855 75.035 36.345 75.525 ;
      RECT  43.67 73.22 44.16 73.71 ;
      RECT  43.67 75.07 44.16 75.56 ;
      RECT  46.925 67.135 47.415 67.625 ;
      RECT  46.925 88.86 47.415 89.35 ;
      RECT  46.925 73.06 47.415 73.55 ;
      RECT  43.67 71.12 44.16 71.61 ;
      RECT  43.67 85.07 44.16 85.56 ;
      RECT  46.925 75.035 47.415 75.525 ;
      RECT  43.67 82.97 44.16 83.46 ;
      RECT  35.855 67.135 36.345 67.625 ;
      RECT  46.925 84.91 47.415 85.4 ;
      RECT  32.6 67.17 33.09 67.66 ;
      RECT  55.855 76.865 56.345 77.355 ;
      RECT  46.925 86.885 47.415 87.375 ;
      RECT  35.855 63.185 36.345 63.675 ;
      RECT  43.67 67.17 44.16 67.66 ;
      RECT  46.925 65.16 47.415 65.65 ;
      RECT  43.67 90.87 44.16 91.36 ;
      RECT  46.925 63.185 47.415 63.675 ;
      RECT  43.67 77.17 44.16 77.66 ;
      RECT  46.925 77.01 47.415 77.5 ;
      RECT  43.67 65.32 44.16 65.81 ;
      RECT  46.925 69.11 47.415 69.6 ;
      RECT  32.6 75.07 33.09 75.56 ;
      RECT  43.67 89.02 44.16 89.51 ;
      RECT  32.6 63.22 33.09 63.71 ;
      RECT  46.925 78.985 47.415 79.475 ;
      RECT  46.925 80.96 47.415 81.45 ;
      RECT  25.985 75.035 26.475 75.525 ;
      RECT  32.6 79.02 33.09 79.51 ;
      RECT  43.67 86.92 44.16 87.41 ;
      RECT  43.67 79.02 44.16 79.51 ;
      RECT  43.67 69.27 44.16 69.76 ;
      RECT  46.925 90.835 47.415 91.325 ;
      RECT  43.67 81.12 44.16 81.61 ;
      RECT  43.67 63.22 44.16 63.71 ;
      RECT  46.925 71.085 47.415 71.575 ;
      RECT  41.545 79.02 42.035 79.51 ;
      RECT  34.495 78.985 34.985 79.475 ;
      RECT  41.545 69.26 42.035 69.75 ;
      RECT  34.495 63.185 34.985 63.675 ;
      RECT  41.545 65.31 42.035 65.8 ;
      RECT  49.155 76.79 49.645 77.28 ;
      RECT  30.475 79.02 30.965 79.51 ;
      RECT  30.475 67.17 30.965 67.66 ;
      RECT  41.545 75.07 42.035 75.56 ;
      RECT  34.495 75.035 34.985 75.525 ;
      RECT  45.565 82.935 46.055 83.425 ;
      RECT  45.565 80.96 46.055 81.45 ;
      RECT  45.565 78.985 46.055 79.475 ;
      RECT  45.565 86.885 46.055 87.375 ;
      RECT  45.565 90.835 46.055 91.325 ;
      RECT  45.565 88.86 46.055 89.35 ;
      RECT  34.495 67.135 34.985 67.625 ;
      RECT  53.365 76.865 53.855 77.355 ;
      RECT  41.545 85.06 42.035 85.55 ;
      RECT  41.545 90.87 42.035 91.36 ;
      RECT  45.565 67.135 46.055 67.625 ;
      RECT  41.545 63.22 42.035 63.71 ;
      RECT  41.545 89.01 42.035 89.5 ;
      RECT  41.545 77.16 42.035 77.65 ;
      RECT  45.565 84.91 46.055 85.4 ;
      RECT  24.625 75.035 25.115 75.525 ;
      RECT  30.475 63.22 30.965 63.71 ;
      RECT  45.565 63.185 46.055 63.675 ;
      RECT  45.565 77.01 46.055 77.5 ;
      RECT  24.625 63.185 25.115 63.675 ;
      RECT  41.545 81.11 42.035 81.6 ;
      RECT  41.545 71.12 42.035 71.61 ;
      RECT  45.565 69.11 46.055 69.6 ;
      RECT  45.565 73.06 46.055 73.55 ;
      RECT  41.545 86.92 42.035 87.41 ;
      RECT  45.565 65.16 46.055 65.65 ;
      RECT  45.565 75.035 46.055 75.525 ;
      RECT  41.545 67.17 42.035 67.66 ;
      RECT  30.475 75.07 30.965 75.56 ;
      RECT  41.545 82.97 42.035 83.46 ;
      RECT  45.565 71.085 46.055 71.575 ;
      RECT  41.545 73.21 42.035 73.7 ;
      RECT  104.56 67.17 104.07 67.66 ;
      RECT  111.175 63.185 110.685 63.675 ;
      RECT  101.305 67.135 100.815 67.625 ;
      RECT  104.56 63.22 104.07 63.71 ;
      RECT  101.305 63.185 100.815 63.675 ;
      RECT  112.535 63.185 112.045 63.675 ;
      RECT  102.665 63.185 102.175 63.675 ;
      RECT  102.665 67.135 102.175 67.625 ;
      RECT  106.685 63.22 106.195 63.71 ;
      RECT  106.685 67.17 106.195 67.66 ;
      RECT  104.56 79.02 104.07 79.51 ;
      RECT  111.175 75.035 110.685 75.525 ;
      RECT  101.305 78.985 100.815 79.475 ;
      RECT  104.56 75.07 104.07 75.56 ;
      RECT  101.305 75.035 100.815 75.525 ;
      RECT  112.535 75.035 112.045 75.525 ;
      RECT  102.665 75.035 102.175 75.525 ;
      RECT  102.665 78.985 102.175 79.475 ;
      RECT  106.685 75.07 106.195 75.56 ;
      RECT  106.685 79.02 106.195 79.51 ;
      RECT  101.305 63.185 100.815 63.675 ;
      RECT  90.235 65.16 89.745 65.65 ;
      RECT  90.235 69.11 89.745 69.6 ;
      RECT  93.49 85.07 93.0 85.56 ;
      RECT  93.49 90.87 93.0 91.36 ;
      RECT  90.235 84.91 89.745 85.4 ;
      RECT  90.235 67.135 89.745 67.625 ;
      RECT  93.49 65.32 93.0 65.81 ;
      RECT  101.305 75.035 100.815 75.525 ;
      RECT  90.235 77.01 89.745 77.5 ;
      RECT  90.235 71.085 89.745 71.575 ;
      RECT  104.56 63.22 104.07 63.71 ;
      RECT  93.49 77.17 93.0 77.66 ;
      RECT  90.235 80.96 89.745 81.45 ;
      RECT  111.175 75.035 110.685 75.525 ;
      RECT  93.49 86.92 93.0 87.41 ;
      RECT  90.235 63.185 89.745 63.675 ;
      RECT  93.49 63.22 93.0 63.71 ;
      RECT  111.175 63.185 110.685 63.675 ;
      RECT  93.49 79.02 93.0 79.51 ;
      RECT  93.49 75.07 93.0 75.56 ;
      RECT  104.56 67.17 104.07 67.66 ;
      RECT  90.235 75.035 89.745 75.525 ;
      RECT  101.305 78.985 100.815 79.475 ;
      RECT  90.235 88.86 89.745 89.35 ;
      RECT  93.49 67.17 93.0 67.66 ;
      RECT  90.235 86.885 89.745 87.375 ;
      RECT  93.49 81.12 93.0 81.61 ;
      RECT  93.49 82.97 93.0 83.46 ;
      RECT  101.305 67.135 100.815 67.625 ;
      RECT  93.49 69.27 93.0 69.76 ;
      RECT  93.49 71.12 93.0 71.61 ;
      RECT  90.235 82.935 89.745 83.425 ;
      RECT  90.235 90.835 89.745 91.325 ;
      RECT  90.235 78.985 89.745 79.475 ;
      RECT  104.56 75.07 104.07 75.56 ;
      RECT  93.49 73.22 93.0 73.71 ;
      RECT  90.235 73.06 89.745 73.55 ;
      RECT  104.56 79.02 104.07 79.51 ;
      RECT  93.49 89.02 93.0 89.51 ;
      RECT  95.615 81.11 95.125 81.6 ;
      RECT  95.615 89.01 95.125 89.5 ;
      RECT  91.595 88.86 91.105 89.35 ;
      RECT  106.685 67.17 106.195 67.66 ;
      RECT  95.615 73.21 95.125 73.7 ;
      RECT  102.665 75.035 102.175 75.525 ;
      RECT  91.595 73.06 91.105 73.55 ;
      RECT  95.615 77.16 95.125 77.65 ;
      RECT  112.535 63.185 112.045 63.675 ;
      RECT  91.595 63.185 91.105 63.675 ;
      RECT  106.685 63.22 106.195 63.71 ;
      RECT  95.615 63.22 95.125 63.71 ;
      RECT  95.615 71.12 95.125 71.61 ;
      RECT  95.615 69.26 95.125 69.75 ;
      RECT  95.615 79.02 95.125 79.51 ;
      RECT  91.595 77.01 91.105 77.5 ;
      RECT  95.615 85.06 95.125 85.55 ;
      RECT  91.595 84.91 91.105 85.4 ;
      RECT  91.595 69.11 91.105 69.6 ;
      RECT  91.595 65.16 91.105 65.65 ;
      RECT  95.615 75.07 95.125 75.56 ;
      RECT  95.615 82.97 95.125 83.46 ;
      RECT  91.595 82.935 91.105 83.425 ;
      RECT  91.595 78.985 91.105 79.475 ;
      RECT  95.615 86.92 95.125 87.41 ;
      RECT  95.615 90.87 95.125 91.36 ;
      RECT  102.665 63.185 102.175 63.675 ;
      RECT  106.685 75.07 106.195 75.56 ;
      RECT  102.665 78.985 102.175 79.475 ;
      RECT  91.595 67.135 91.105 67.625 ;
      RECT  91.595 86.885 91.105 87.375 ;
      RECT  102.665 67.135 102.175 67.625 ;
      RECT  91.595 80.96 91.105 81.45 ;
      RECT  95.615 65.31 95.125 65.8 ;
      RECT  106.685 79.02 106.195 79.51 ;
      RECT  95.615 67.17 95.125 67.66 ;
      RECT  91.595 90.835 91.105 91.325 ;
      RECT  91.595 75.035 91.105 75.525 ;
      RECT  112.535 75.035 112.045 75.525 ;
      RECT  91.595 71.085 91.105 71.575 ;
      RECT  111.175 63.185 110.685 63.675 ;
      RECT  85.88 76.785 85.39 77.275 ;
      RECT  90.235 82.935 89.745 83.425 ;
      RECT  101.305 78.985 100.815 79.475 ;
      RECT  101.305 75.035 100.815 75.525 ;
      RECT  93.49 73.22 93.0 73.71 ;
      RECT  93.49 75.07 93.0 75.56 ;
      RECT  90.235 67.135 89.745 67.625 ;
      RECT  90.235 88.86 89.745 89.35 ;
      RECT  90.235 73.06 89.745 73.55 ;
      RECT  93.49 71.12 93.0 71.61 ;
      RECT  93.49 85.07 93.0 85.56 ;
      RECT  90.235 75.035 89.745 75.525 ;
      RECT  93.49 82.97 93.0 83.46 ;
      RECT  101.305 67.135 100.815 67.625 ;
      RECT  90.235 84.91 89.745 85.4 ;
      RECT  104.56 67.17 104.07 67.66 ;
      RECT  81.305 76.865 80.815 77.355 ;
      RECT  90.235 86.885 89.745 87.375 ;
      RECT  101.305 63.185 100.815 63.675 ;
      RECT  93.49 67.17 93.0 67.66 ;
      RECT  90.235 65.16 89.745 65.65 ;
      RECT  93.49 90.87 93.0 91.36 ;
      RECT  90.235 63.185 89.745 63.675 ;
      RECT  93.49 77.17 93.0 77.66 ;
      RECT  90.235 77.01 89.745 77.5 ;
      RECT  93.49 65.32 93.0 65.81 ;
      RECT  90.235 69.11 89.745 69.6 ;
      RECT  104.56 75.07 104.07 75.56 ;
      RECT  93.49 89.02 93.0 89.51 ;
      RECT  104.56 63.22 104.07 63.71 ;
      RECT  90.235 78.985 89.745 79.475 ;
      RECT  90.235 80.96 89.745 81.45 ;
      RECT  111.175 75.035 110.685 75.525 ;
      RECT  104.56 79.02 104.07 79.51 ;
      RECT  93.49 86.92 93.0 87.41 ;
      RECT  93.49 79.02 93.0 79.51 ;
      RECT  93.49 69.27 93.0 69.76 ;
      RECT  90.235 90.835 89.745 91.325 ;
      RECT  93.49 81.12 93.0 81.61 ;
      RECT  93.49 63.22 93.0 63.71 ;
      RECT  90.235 71.085 89.745 71.575 ;
      RECT  95.615 79.02 95.125 79.51 ;
      RECT  102.665 78.985 102.175 79.475 ;
      RECT  95.615 69.26 95.125 69.75 ;
      RECT  102.665 63.185 102.175 63.675 ;
      RECT  95.615 65.31 95.125 65.8 ;
      RECT  88.005 76.79 87.515 77.28 ;
      RECT  106.685 79.02 106.195 79.51 ;
      RECT  106.685 67.17 106.195 67.66 ;
      RECT  95.615 75.07 95.125 75.56 ;
      RECT  102.665 75.035 102.175 75.525 ;
      RECT  91.595 82.935 91.105 83.425 ;
      RECT  91.595 80.96 91.105 81.45 ;
      RECT  91.595 78.985 91.105 79.475 ;
      RECT  91.595 86.885 91.105 87.375 ;
      RECT  91.595 90.835 91.105 91.325 ;
      RECT  91.595 88.86 91.105 89.35 ;
      RECT  102.665 67.135 102.175 67.625 ;
      RECT  83.795 76.865 83.305 77.355 ;
      RECT  95.615 85.06 95.125 85.55 ;
      RECT  95.615 90.87 95.125 91.36 ;
      RECT  91.595 67.135 91.105 67.625 ;
      RECT  95.615 63.22 95.125 63.71 ;
      RECT  95.615 89.01 95.125 89.5 ;
      RECT  95.615 77.16 95.125 77.65 ;
      RECT  91.595 84.91 91.105 85.4 ;
      RECT  112.535 75.035 112.045 75.525 ;
      RECT  106.685 63.22 106.195 63.71 ;
      RECT  91.595 63.185 91.105 63.675 ;
      RECT  91.595 77.01 91.105 77.5 ;
      RECT  112.535 63.185 112.045 63.675 ;
      RECT  95.615 81.11 95.125 81.6 ;
      RECT  95.615 71.12 95.125 71.61 ;
      RECT  91.595 69.11 91.105 69.6 ;
      RECT  91.595 73.06 91.105 73.55 ;
      RECT  95.615 86.92 95.125 87.41 ;
      RECT  91.595 65.16 91.105 65.65 ;
      RECT  91.595 75.035 91.105 75.525 ;
      RECT  95.615 67.17 95.125 67.66 ;
      RECT  106.685 75.07 106.195 75.56 ;
      RECT  95.615 82.97 95.125 83.46 ;
      RECT  91.595 71.085 91.105 71.575 ;
      RECT  95.615 73.21 95.125 73.7 ;
      RECT  43.67 65.32 44.16 65.81 ;
      RECT  93.0 81.12 93.49 81.61 ;
      RECT  89.745 71.085 90.235 71.575 ;
      RECT  46.925 84.91 47.415 85.4 ;
      RECT  93.0 69.27 93.49 69.76 ;
      RECT  89.745 86.885 90.235 87.375 ;
      RECT  43.67 73.22 44.16 73.71 ;
      RECT  46.925 88.86 47.415 89.35 ;
      RECT  67.06 45.885 67.55 46.375 ;
      RECT  70.49 55.305 70.98 55.795 ;
      RECT  43.67 77.17 44.16 77.66 ;
      RECT  66.87 95.565 67.17 95.865 ;
      RECT  80.815 76.865 81.305 77.355 ;
      RECT  66.595 29.185 67.085 29.675 ;
      RECT  46.925 73.06 47.415 73.55 ;
      RECT  89.745 63.185 90.235 63.675 ;
      RECT  69.555 33.935 70.045 34.425 ;
      RECT  93.0 65.32 93.49 65.81 ;
      RECT  43.67 67.17 44.16 67.66 ;
      RECT  35.855 67.135 36.345 67.625 ;
      RECT  43.67 89.02 44.16 89.51 ;
      RECT  93.0 73.22 93.49 73.71 ;
      RECT  89.745 90.835 90.235 91.325 ;
      RECT  68.99 45.885 69.48 46.375 ;
      RECT  46.925 63.185 47.415 63.675 ;
      RECT  46.925 78.985 47.415 79.475 ;
      RECT  66.495 33.935 66.985 34.425 ;
      RECT  89.745 69.11 90.235 69.6 ;
      RECT  35.855 78.985 36.345 79.475 ;
      RECT  46.925 77.01 47.415 77.5 ;
      RECT  63.655 95.47 64.145 95.96 ;
      RECT  46.925 90.835 47.415 91.325 ;
      RECT  69.99 95.565 70.29 95.865 ;
      RECT  67.12 112.035 67.61 112.525 ;
      RECT  43.67 71.12 44.16 71.61 ;
      RECT  55.855 76.865 56.345 77.355 ;
      RECT  68.93 112.035 69.42 112.525 ;
      RECT  46.925 71.085 47.415 71.575 ;
      RECT  43.67 86.92 44.16 87.41 ;
      RECT  43.67 75.07 44.16 75.56 ;
      RECT  89.745 82.935 90.235 83.425 ;
      RECT  93.0 71.12 93.49 71.61 ;
      RECT  93.0 67.17 93.49 67.66 ;
      RECT  46.925 75.035 47.415 75.525 ;
      RECT  100.815 75.035 101.305 75.525 ;
      RECT  93.0 79.02 93.49 79.51 ;
      RECT  73.015 95.47 73.505 95.96 ;
      RECT  66.18 55.305 66.67 55.795 ;
      RECT  43.67 69.27 44.16 69.76 ;
      RECT  100.815 63.185 101.305 63.675 ;
      RECT  89.745 65.16 90.235 65.65 ;
      RECT  46.925 67.135 47.415 67.625 ;
      RECT  85.39 76.785 85.88 77.275 ;
      RECT  93.0 89.02 93.49 89.51 ;
      RECT  93.0 90.87 93.49 91.36 ;
      RECT  25.985 75.035 26.475 75.525 ;
      RECT  93.0 85.07 93.49 85.56 ;
      RECT  89.745 78.985 90.235 79.475 ;
      RECT  89.745 75.035 90.235 75.525 ;
      RECT  110.685 63.185 111.175 63.675 ;
      RECT  93.0 75.07 93.49 75.56 ;
      RECT  43.67 81.12 44.16 81.61 ;
      RECT  43.67 63.22 44.16 63.71 ;
      RECT  104.07 63.22 104.56 63.71 ;
      RECT  89.745 84.91 90.235 85.4 ;
      RECT  100.815 78.985 101.305 79.475 ;
      RECT  43.67 85.07 44.16 85.56 ;
      RECT  46.925 69.11 47.415 69.6 ;
      RECT  100.815 67.135 101.305 67.625 ;
      RECT  93.0 77.17 93.49 77.66 ;
      RECT  67.06 107.845 67.55 108.335 ;
      RECT  32.6 75.07 33.09 75.56 ;
      RECT  51.28 76.785 51.77 77.275 ;
      RECT  104.07 79.02 104.56 79.51 ;
      RECT  104.07 75.07 104.56 75.56 ;
      RECT  32.6 63.22 33.09 63.71 ;
      RECT  46.925 65.16 47.415 65.65 ;
      RECT  89.745 80.96 90.235 81.45 ;
      RECT  32.6 79.02 33.09 79.51 ;
      RECT  66.87 58.355 67.17 58.655 ;
      RECT  64.25 55.305 64.74 55.795 ;
      RECT  73.015 58.26 73.505 58.75 ;
      RECT  43.67 82.97 44.16 83.46 ;
      RECT  89.745 77.01 90.235 77.5 ;
      RECT  66.18 98.425 66.67 98.915 ;
      RECT  32.6 67.17 33.09 67.66 ;
      RECT  68.93 41.695 69.42 42.185 ;
      RECT  89.745 88.86 90.235 89.35 ;
      RECT  68.99 107.845 69.48 108.335 ;
      RECT  93.0 86.92 93.49 87.41 ;
      RECT  69.99 58.355 70.29 58.655 ;
      RECT  110.685 75.035 111.175 75.525 ;
      RECT  43.67 79.02 44.16 79.51 ;
      RECT  89.745 73.06 90.235 73.55 ;
      RECT  72.42 98.425 72.91 98.915 ;
      RECT  93.0 63.22 93.49 63.71 ;
      RECT  69.455 29.185 69.945 29.675 ;
      RECT  63.655 58.26 64.145 58.75 ;
      RECT  35.855 75.035 36.345 75.525 ;
      RECT  67.12 41.695 67.61 42.185 ;
      RECT  89.745 67.135 90.235 67.625 ;
      RECT  46.925 80.96 47.415 81.45 ;
      RECT  46.925 86.885 47.415 87.375 ;
      RECT  46.925 82.935 47.415 83.425 ;
      RECT  93.0 82.97 93.49 83.46 ;
      RECT  35.855 63.185 36.345 63.675 ;
      RECT  25.985 63.185 26.475 63.675 ;
      RECT  70.49 98.425 70.98 98.915 ;
      RECT  104.07 67.17 104.56 67.66 ;
      RECT  43.67 90.87 44.16 91.36 ;
      RECT  60.27 87.625 60.57 87.925 ;
      RECT  67.12 40.085 67.61 40.575 ;
      RECT  45.565 90.835 46.055 91.325 ;
      RECT  53.365 76.865 53.855 77.355 ;
      RECT  66.55 36.12 67.04 36.61 ;
      RECT  76.59 74.195 76.89 74.495 ;
      RECT  76.59 61.16 76.89 61.46 ;
      RECT  102.175 78.985 102.665 79.475 ;
      RECT  95.125 82.97 95.615 83.46 ;
      RECT  60.27 84.86 60.57 85.16 ;
      RECT  45.565 63.185 46.055 63.675 ;
      RECT  76.59 88.81 76.89 89.11 ;
      RECT  34.495 63.185 34.985 63.675 ;
      RECT  60.27 65.11 60.57 65.41 ;
      RECT  60.27 83.675 60.57 83.975 ;
      RECT  60.27 88.81 60.57 89.11 ;
      RECT  91.105 82.935 91.595 83.425 ;
      RECT  60.27 75.775 60.57 76.075 ;
      RECT  91.105 67.135 91.595 67.625 ;
      RECT  76.59 75.775 76.89 76.075 ;
      RECT  91.105 69.11 91.595 69.6 ;
      RECT  76.59 59.975 76.89 60.275 ;
      RECT  49.155 76.79 49.645 77.28 ;
      RECT  30.475 75.07 30.965 75.56 ;
      RECT  69.5 36.12 69.99 36.61 ;
      RECT  60.27 76.96 60.57 77.26 ;
      RECT  67.47 103.975 67.96 104.465 ;
      RECT  95.125 69.26 95.615 69.75 ;
      RECT  106.195 63.22 106.685 63.71 ;
      RECT  91.105 71.085 91.595 71.575 ;
      RECT  76.59 82.095 76.89 82.395 ;
      RECT  95.125 85.06 95.615 85.55 ;
      RECT  112.045 75.035 112.535 75.525 ;
      RECT  76.59 93.945 76.89 94.245 ;
      RECT  60.27 73.01 60.57 73.31 ;
      RECT  68.58 49.755 69.07 50.245 ;
      RECT  41.545 71.12 42.035 71.61 ;
      RECT  41.545 90.87 42.035 91.36 ;
      RECT  68.93 40.085 69.42 40.575 ;
      RECT  95.125 71.12 95.615 71.61 ;
      RECT  34.495 67.135 34.985 67.625 ;
      RECT  41.545 63.22 42.035 63.71 ;
      RECT  41.545 67.17 42.035 67.66 ;
      RECT  45.565 77.01 46.055 77.5 ;
      RECT  60.27 91.575 60.57 91.875 ;
      RECT  24.625 75.035 25.115 75.525 ;
      RECT  102.175 63.185 102.665 63.675 ;
      RECT  76.59 89.995 76.89 90.295 ;
      RECT  45.565 65.16 46.055 65.65 ;
      RECT  106.195 79.02 106.685 79.51 ;
      RECT  76.59 71.825 76.89 72.125 ;
      RECT  60.27 63.925 60.57 64.225 ;
      RECT  76.59 69.06 76.89 69.36 ;
      RECT  41.545 77.16 42.035 77.65 ;
      RECT  41.545 79.02 42.035 79.51 ;
      RECT  95.125 75.07 95.615 75.56 ;
      RECT  95.125 67.17 95.615 67.66 ;
      RECT  76.59 73.01 76.89 73.31 ;
      RECT  45.565 75.035 46.055 75.525 ;
      RECT  95.125 77.16 95.615 77.65 ;
      RECT  41.545 85.06 42.035 85.55 ;
      RECT  45.565 78.985 46.055 79.475 ;
      RECT  106.195 67.17 106.685 67.66 ;
      RECT  45.565 80.96 46.055 81.45 ;
      RECT  60.27 79.725 60.57 80.025 ;
      RECT  41.545 65.31 42.035 65.8 ;
      RECT  60.27 92.76 60.57 93.06 ;
      RECT  95.125 81.11 95.615 81.6 ;
      RECT  76.59 70.245 76.89 70.545 ;
      RECT  30.475 79.02 30.965 79.51 ;
      RECT  24.625 63.185 25.115 63.675 ;
      RECT  76.59 67.875 76.89 68.175 ;
      RECT  76.59 63.925 76.89 64.225 ;
      RECT  60.27 86.045 60.57 86.345 ;
      RECT  67.47 49.755 67.96 50.245 ;
      RECT  60.27 82.095 60.57 82.395 ;
      RECT  66.525 31.265 67.015 31.755 ;
      RECT  60.27 62.345 60.57 62.645 ;
      RECT  41.545 75.07 42.035 75.56 ;
      RECT  60.27 66.295 60.57 66.595 ;
      RECT  76.59 62.345 76.89 62.645 ;
      RECT  91.105 86.885 91.595 87.375 ;
      RECT  95.125 79.02 95.615 79.51 ;
      RECT  91.105 63.185 91.595 63.675 ;
      RECT  95.125 63.22 95.615 63.71 ;
      RECT  41.545 82.97 42.035 83.46 ;
      RECT  68.93 113.645 69.42 114.135 ;
      RECT  91.105 90.835 91.595 91.325 ;
      RECT  41.545 86.92 42.035 87.41 ;
      RECT  68.95 32.275 69.44 32.765 ;
      RECT  41.545 69.26 42.035 69.75 ;
      RECT  91.105 84.91 91.595 85.4 ;
      RECT  76.59 76.96 76.89 77.26 ;
      RECT  41.545 81.11 42.035 81.6 ;
      RECT  91.105 88.86 91.595 89.35 ;
      RECT  45.565 82.935 46.055 83.425 ;
      RECT  45.565 67.135 46.055 67.625 ;
      RECT  60.27 59.975 60.57 60.275 ;
      RECT  45.565 71.085 46.055 71.575 ;
      RECT  95.125 89.01 95.615 89.5 ;
      RECT  76.59 83.675 76.89 83.975 ;
      RECT  41.545 73.21 42.035 73.7 ;
      RECT  91.105 75.035 91.595 75.525 ;
      RECT  45.565 84.91 46.055 85.4 ;
      RECT  60.27 74.195 60.57 74.495 ;
      RECT  67.12 113.645 67.61 114.135 ;
      RECT  76.59 80.91 76.89 81.21 ;
      RECT  45.565 69.11 46.055 69.6 ;
      RECT  76.59 84.86 76.89 85.16 ;
      RECT  76.59 66.295 76.89 66.595 ;
      RECT  95.125 73.21 95.615 73.7 ;
      RECT  91.105 73.06 91.595 73.55 ;
      RECT  112.045 63.185 112.535 63.675 ;
      RECT  60.27 89.995 60.57 90.295 ;
      RECT  41.545 89.01 42.035 89.5 ;
      RECT  76.59 65.11 76.89 65.41 ;
      RECT  60.27 80.91 60.57 81.21 ;
      RECT  76.59 87.625 76.89 87.925 ;
      RECT  91.105 77.01 91.595 77.5 ;
      RECT  76.59 78.145 76.89 78.445 ;
      RECT  60.27 61.16 60.57 61.46 ;
      RECT  83.305 76.865 83.795 77.355 ;
      RECT  69.525 31.265 70.015 31.755 ;
      RECT  95.125 86.92 95.615 87.41 ;
      RECT  76.59 91.575 76.89 91.875 ;
      RECT  30.475 67.17 30.965 67.66 ;
      RECT  30.475 63.22 30.965 63.71 ;
      RECT  34.495 75.035 34.985 75.525 ;
      RECT  60.27 70.245 60.57 70.545 ;
      RECT  45.565 88.86 46.055 89.35 ;
      RECT  60.27 78.145 60.57 78.445 ;
      RECT  45.565 86.885 46.055 87.375 ;
      RECT  95.125 65.31 95.615 65.8 ;
      RECT  45.565 73.06 46.055 73.55 ;
      RECT  67.1 32.275 67.59 32.765 ;
      RECT  106.195 75.07 106.685 75.56 ;
      RECT  87.515 76.79 88.005 77.28 ;
      RECT  95.125 90.87 95.615 91.36 ;
      RECT  102.175 67.135 102.665 67.625 ;
      RECT  60.27 67.875 60.57 68.175 ;
      RECT  60.27 69.06 60.57 69.36 ;
      RECT  76.59 86.045 76.89 86.345 ;
      RECT  60.27 71.825 60.57 72.125 ;
      RECT  91.105 78.985 91.595 79.475 ;
      RECT  60.27 93.945 60.57 94.245 ;
      RECT  102.175 75.035 102.665 75.525 ;
      RECT  91.105 80.96 91.595 81.45 ;
      RECT  76.59 79.725 76.89 80.025 ;
      RECT  91.105 65.16 91.595 65.65 ;
      RECT  34.495 78.985 34.985 79.475 ;
      RECT  68.58 103.975 69.07 104.465 ;
      RECT  76.59 92.76 76.89 93.06 ;
      RECT  -0.245 6.825 0.245 7.315 ;
      RECT  -0.245 -0.255 0.245 0.235 ;
      RECT  -0.245 13.905 0.245 14.395 ;
      RECT  2.485 62.715 1.995 63.205 ;
      RECT  2.485 62.715 1.995 63.205 ;
      RECT  6.165 62.715 5.675 63.205 ;
      RECT  2.485 73.915 1.995 74.405 ;
      RECT  6.165 85.115 5.675 85.605 ;
      RECT  6.165 73.915 5.675 74.405 ;
      RECT  6.165 73.915 5.675 74.405 ;
      RECT  2.485 96.315 1.995 96.805 ;
      RECT  2.485 107.515 1.995 108.005 ;
      RECT  6.165 96.315 5.675 96.805 ;
      RECT  2.485 85.115 1.995 85.605 ;
      RECT  6.165 107.515 5.675 108.005 ;
      RECT  6.165 62.715 5.675 63.205 ;
      RECT  2.485 73.915 1.995 74.405 ;
      RECT  6.165 101.915 5.675 102.405 ;
      RECT  2.485 90.715 1.995 91.205 ;
      RECT  6.165 79.515 5.675 80.005 ;
      RECT  6.165 68.315 5.675 68.805 ;
      RECT  2.485 57.115 1.995 57.605 ;
      RECT  2.485 68.315 1.995 68.805 ;
      RECT  6.165 57.115 5.675 57.605 ;
      RECT  2.485 101.915 1.995 102.405 ;
      RECT  2.485 79.515 1.995 80.005 ;
      RECT  6.165 90.715 5.675 91.205 ;
      RECT  5.675 107.515 6.165 108.005 ;
      RECT  1.995 73.915 2.485 74.405 ;
      RECT  1.995 62.715 2.485 63.205 ;
      RECT  1.995 96.315 2.485 96.805 ;
      RECT  18.945 49.245 19.435 49.735 ;
      RECT  18.945 35.105 19.435 35.595 ;
      RECT  5.675 96.315 6.165 96.805 ;
      RECT  5.675 62.715 6.165 63.205 ;
      RECT  1.995 85.115 2.485 85.605 ;
      RECT  1.995 107.515 2.485 108.005 ;
      RECT  -0.245 6.825 0.245 7.315 ;
      RECT  5.675 85.115 6.165 85.605 ;
      RECT  5.675 73.915 6.165 74.405 ;
      RECT  18.945 6.825 19.435 7.315 ;
      RECT  18.945 20.965 19.435 21.455 ;
      RECT  1.995 68.315 2.485 68.805 ;
      RECT  5.675 57.115 6.165 57.605 ;
      RECT  1.995 101.915 2.485 102.405 ;
      RECT  18.945 28.035 19.435 28.525 ;
      RECT  18.945 42.175 19.435 42.665 ;
      RECT  -0.245 13.905 0.245 14.395 ;
      RECT  5.675 68.315 6.165 68.805 ;
      RECT  1.995 79.515 2.485 80.005 ;
      RECT  5.675 79.515 6.165 80.005 ;
      RECT  -0.245 -0.255 0.245 0.235 ;
      RECT  1.995 57.115 2.485 57.605 ;
      RECT  5.675 101.915 6.165 102.405 ;
      RECT  1.995 90.715 2.485 91.205 ;
      RECT  18.945 -0.245 19.435 0.245 ;
      RECT  18.945 56.315 19.435 56.805 ;
      RECT  5.675 90.715 6.165 91.205 ;
      RECT  18.945 13.895 19.435 14.385 ;
      RECT  137.405 133.255 136.915 132.765 ;
      RECT  137.405 140.335 136.915 139.845 ;
      RECT  134.675 91.505 135.165 91.015 ;
      RECT  134.675 91.505 135.165 91.015 ;
      RECT  130.995 91.505 131.485 91.015 ;
      RECT  134.675 80.305 135.165 79.815 ;
      RECT  130.995 69.105 131.485 68.615 ;
      RECT  130.995 80.305 131.485 79.815 ;
      RECT  130.995 80.305 131.485 79.815 ;
      RECT  134.675 57.905 135.165 57.415 ;
      RECT  134.675 46.705 135.165 46.215 ;
      RECT  130.995 57.905 131.485 57.415 ;
      RECT  134.675 69.105 135.165 68.615 ;
      RECT  130.995 46.705 131.485 46.215 ;
      RECT  130.995 91.505 131.485 91.015 ;
      RECT  134.675 80.305 135.165 79.815 ;
      RECT  130.995 52.305 131.485 51.815 ;
      RECT  134.675 63.505 135.165 63.015 ;
      RECT  130.995 74.705 131.485 74.215 ;
      RECT  130.995 85.905 131.485 85.415 ;
      RECT  134.675 97.105 135.165 96.615 ;
      RECT  134.675 85.905 135.165 85.415 ;
      RECT  130.995 97.105 131.485 96.615 ;
      RECT  134.675 52.305 135.165 51.815 ;
      RECT  134.675 74.705 135.165 74.215 ;
      RECT  130.995 63.505 131.485 63.015 ;
      RECT  135.165 91.505 134.675 91.015 ;
      RECT  118.635 119.115 118.145 118.625 ;
      RECT  131.485 57.905 130.995 57.415 ;
      RECT  135.165 57.905 134.675 57.415 ;
      RECT  131.485 91.505 130.995 91.015 ;
      RECT  135.165 46.705 134.675 46.215 ;
      RECT  118.635 133.255 118.145 132.765 ;
      RECT  131.485 69.105 130.995 68.615 ;
      RECT  131.485 80.305 130.995 79.815 ;
      RECT  137.405 133.255 136.915 132.765 ;
      RECT  118.635 104.975 118.145 104.485 ;
      RECT  135.165 69.105 134.675 68.615 ;
      RECT  135.165 80.305 134.675 79.815 ;
      RECT  131.485 46.705 130.995 46.215 ;
      RECT  118.635 97.905 118.145 97.415 ;
      RECT  131.485 74.705 130.995 74.215 ;
      RECT  118.635 112.045 118.145 111.555 ;
      RECT  131.485 97.105 130.995 96.615 ;
      RECT  135.165 97.105 134.675 96.615 ;
      RECT  118.635 126.185 118.145 125.695 ;
      RECT  118.635 140.325 118.145 139.835 ;
      RECT  135.165 85.905 134.675 85.415 ;
      RECT  131.485 85.905 130.995 85.415 ;
      RECT  137.405 140.335 136.915 139.845 ;
      RECT  131.485 63.505 130.995 63.015 ;
      RECT  135.165 63.505 134.675 63.015 ;
      RECT  131.485 52.305 130.995 51.815 ;
      RECT  135.165 52.305 134.675 51.815 ;
      RECT  135.165 74.705 134.675 74.215 ;
      RECT  13.77 109.95 19.61 110.25 ;
      RECT  16.445 115.385 16.935 115.875 ;
      RECT  16.445 129.525 16.935 130.015 ;
      RECT  16.445 122.455 16.935 122.945 ;
      RECT  16.445 136.595 16.935 137.085 ;
      RECT  16.445 108.315 16.935 108.805 ;
      RECT  123.81 44.27 117.97 43.97 ;
      RECT  121.135 38.835 120.645 38.345 ;
      RECT  121.135 24.695 120.645 24.205 ;
      RECT  121.135 31.765 120.645 31.275 ;
      RECT  121.135 17.625 120.645 17.135 ;
      RECT  121.135 45.905 120.645 45.415 ;
      RECT  25.45 1.39 37.13 1.69 ;
      RECT  28.125 6.825 28.615 7.315 ;
      RECT  33.965 6.825 34.455 7.315 ;
      RECT  28.125 -0.245 28.615 0.245 ;
      RECT  33.965 -0.245 34.455 0.245 ;
   LAYER  m4 ;
   END
   END    sram_2_16_sky130
END    LIBRARY
